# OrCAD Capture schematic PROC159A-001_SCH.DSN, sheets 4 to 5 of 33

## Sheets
4 08. POWER INPUT: size C; title: USB-C POWER
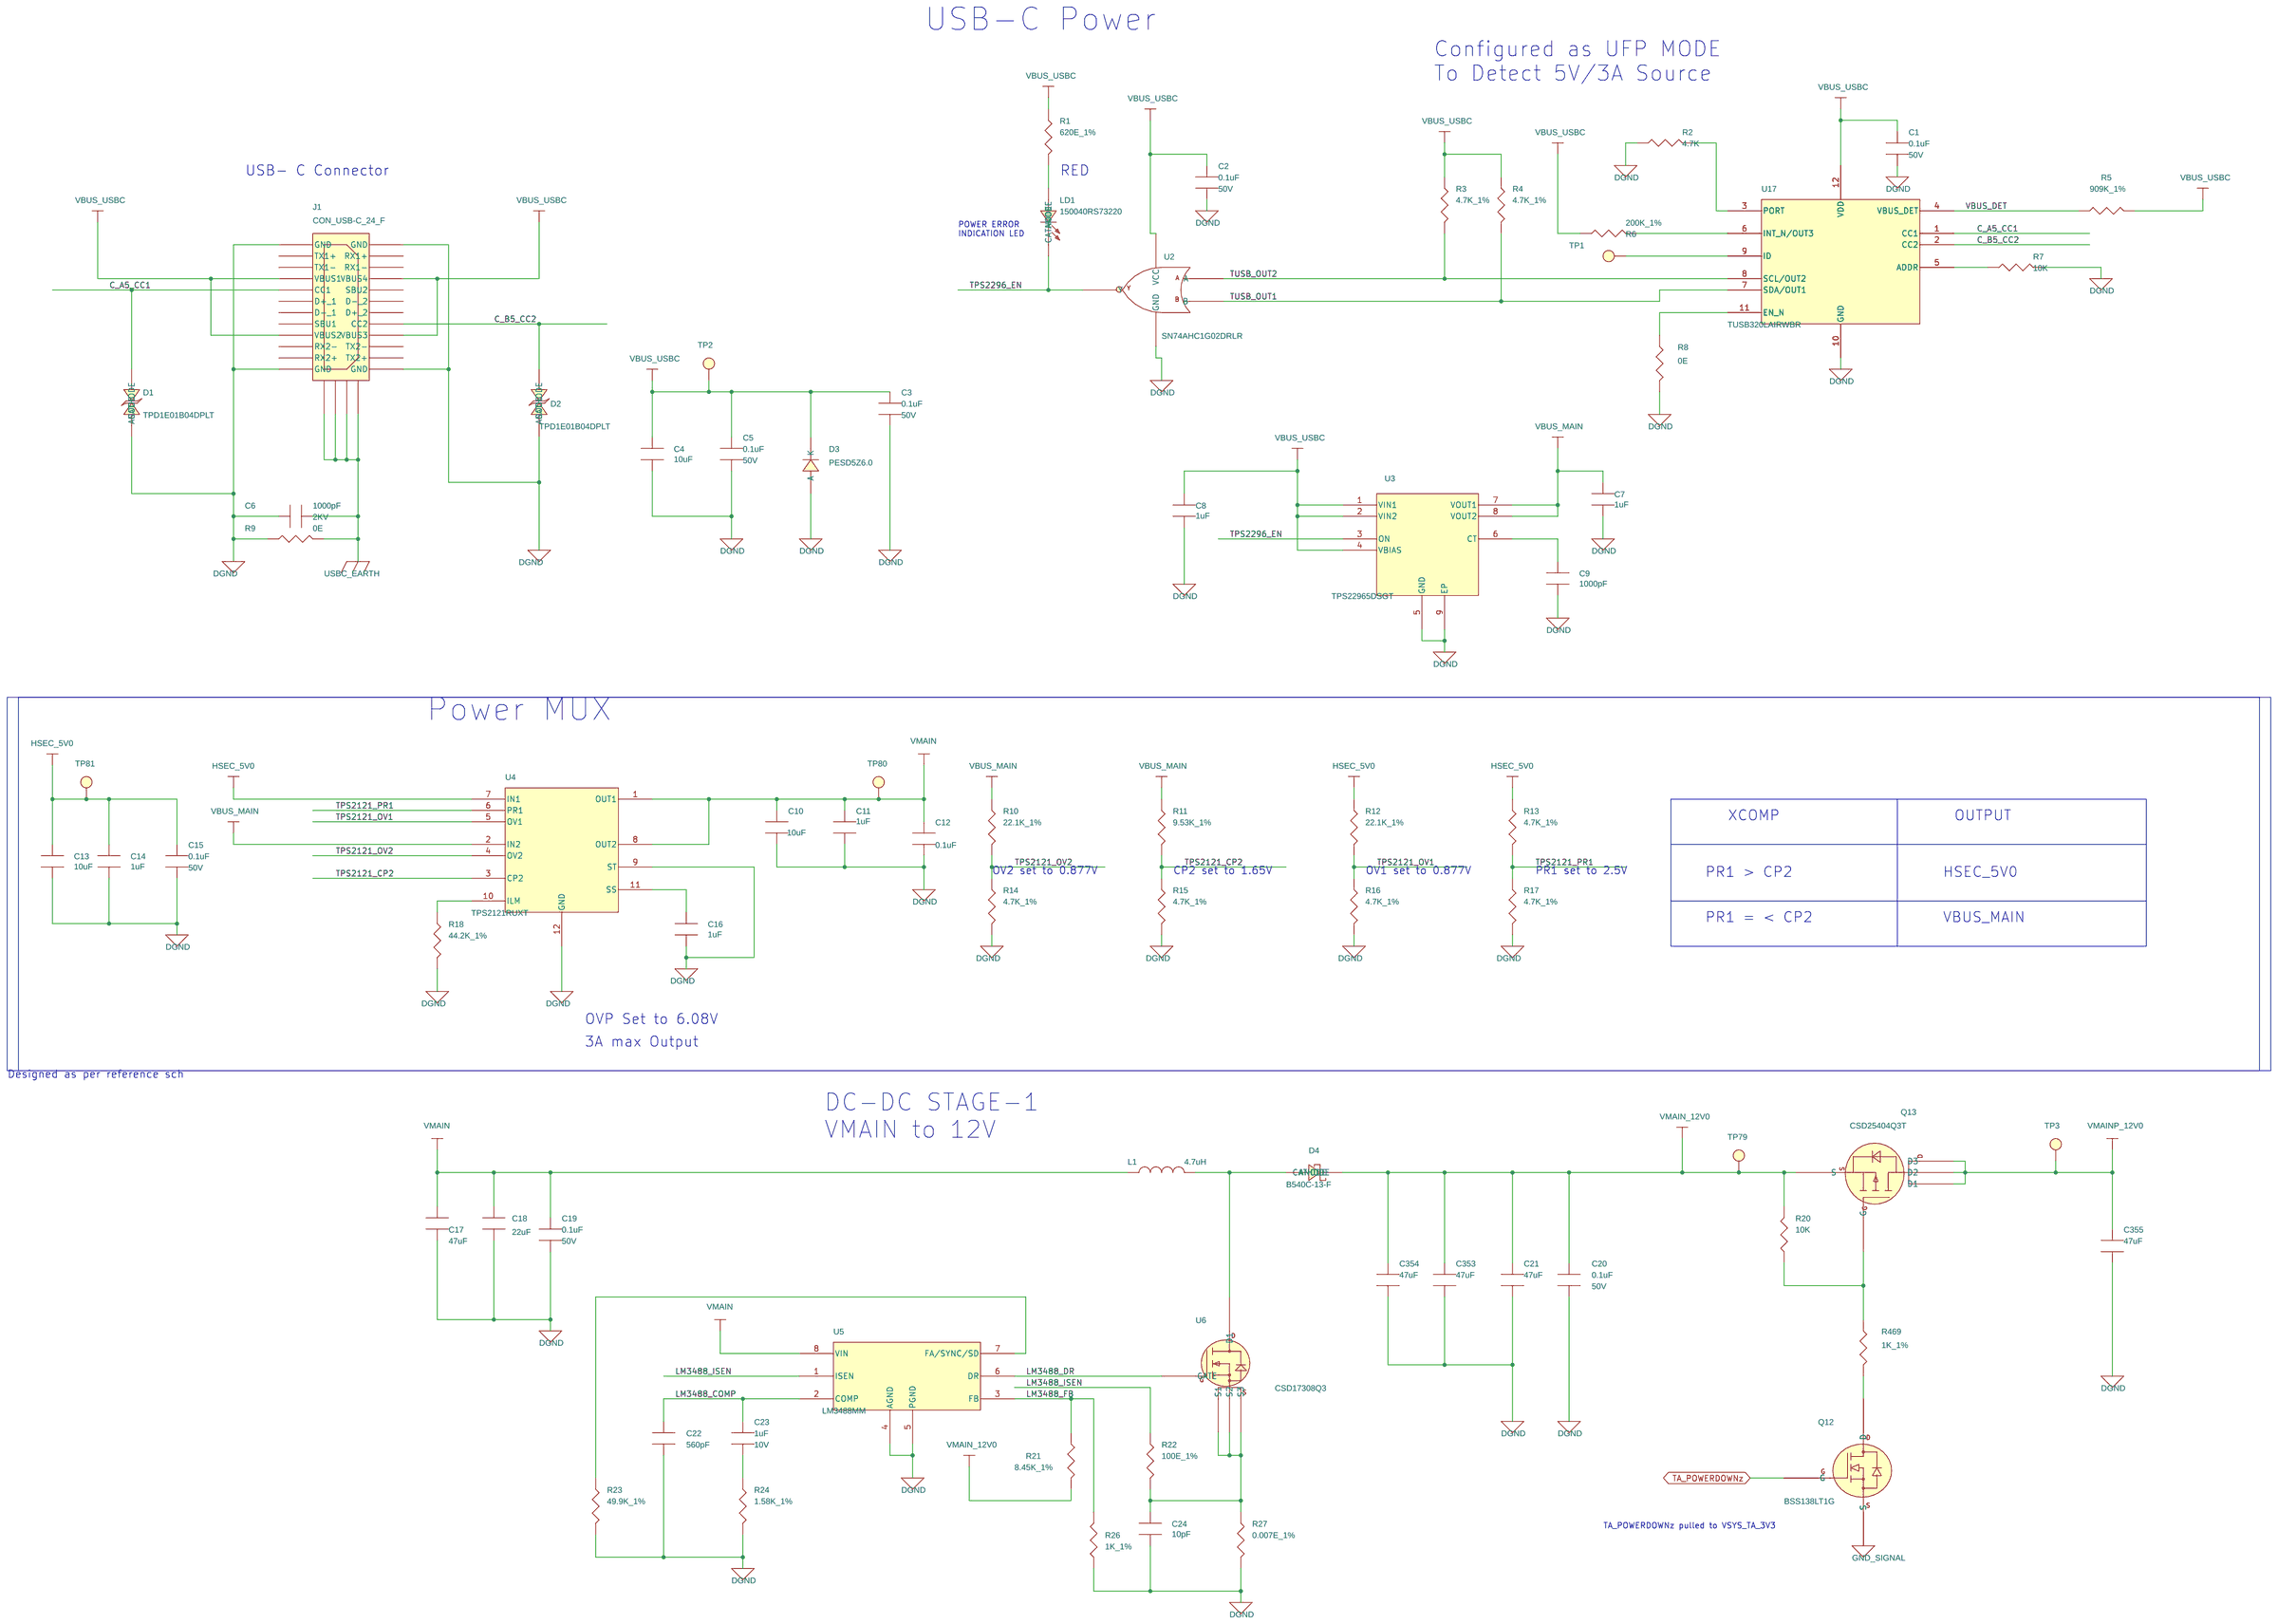
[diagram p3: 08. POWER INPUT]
5 04. POWER SEQUENCE: title: POWER SEQUENCE

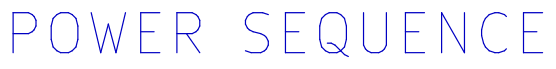
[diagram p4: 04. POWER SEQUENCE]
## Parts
C1  0.1uF  [CAP0402_0-75]
C2  0.1uF  [CAP0402_0-75]
C3  0.1uF  [CAP0402_0-75]
C4  10uF  [CAP1206_2]
C5  0.1uF  [CAP0402_0-75]
C6  1000pF  [CAP1206_1-75]
C7  1uF  [CAP0402_0-75]
C8  1uF  [CAP0402_0-75]
C9  1000pF  [CAP0402_0-75]
C10  10uF  [CAP1206_2]
C11  1uF  [CAP0402_0-75]
C12  0.1uF  [CAP0402_0-75]
C13  10uF  [CAP1206_2]
C14  1uF  [CAP0402_0-75]
C15  0.1uF  [CAP0402_0-75]
C16  1uF  [CAP0402_0-75]
C17  47uF  [CAP1206_2]
C18  22uF  [CAP0805_1-5]
C19  0.1uF  [CAP0402_0-75]
C20  0.1uF  [CAP0402_0-75]
C21  47uF  [CAP1206_2]
C22  560pF  [CAP0402_0-75]
C23  1uF  [CAP0402_0-75]
C24  10pF  [CAP0402_0-75]
C353  47uF  [CAP1206_2]
C354  47uF  [CAP1206_2]
C355  47uF  [CAP1206_2]
D1  TPD1E01B04DPLT  [DIO_DFN0201_0-4]
D2  TPD1E01B04DPLT  [DIO_DFN0201_0-4]
D3  PESD5Z6.0  [DIO_SOD523F_0-7]
D4  B540C-13-F  [DIO_SMC]
J1  CON_USB-C_24_F  [CON_USBC24_2012670_S_R_S_3-9]
L1  4.7uH  [IND_IHLP2020CZ-01_210X210_SMD_3]
LD1  150040RS73220  [LED_150040GS73220_40X20_SMD_0-4]
Q12  BSS138LT1G  [SOT23-123_1-2]
Q13  CSD25404Q3T  [VSON8_CSD173_130X130_1-1]
R1  620E_1%  [RES0402_0-5]
R2  4.7K  [RES0402_0-5]
R3  4.7K_1%  [RES0402_0-5]
R4  4.7K_1%  [RES0402_0-5]
R5  909K_1%  [RES0201_0-5]
R6  200K_1%  [RES0402_0-5]
R7  10K  [RES0402_0-5]
R8  0E  [RES0402_0-5]
R9  0E  [RES0805_0-75]
R10  22.1K_1%  [RES0402_0-5]
R11  9.53K_1%  [RES0402_0-5]
R12  22.1K_1%  [RES0402_0-5]
R13  4.7K_1%  [RES0402_0-5]
R14  4.7K_1%  [RES0402_0-5]
R15  4.7K_1%  [RES0402_0-5]
R16  4.7K_1%  [RES0402_0-5]
R17  4.7K_1%  [RES0402_0-5]
R18  44.2K_1%  [RES0402_0-5]
R20  10K  [RES0201_0-5]
R21  8.45K_1%  [RES0402_0-5]
R22  100E_1%  [RES0402_0-5]
R23  49.9K_1%  [RES0402_0-5]
R24  1.58K_1%  [RES0402_0-5]
R26  1K_1%  [RES0402_0-5]
R27  0.007E_1%  [RES1206_W_0-75]
R469  1K_1%  [RES0402_0-5]
TP1  TP40_SMD  [TP40_SMD]
TP2  TP40_SMD  [TP40_SMD]
TP3  TP40_SMD  [TP40_SMD]
TP79  TP40_SMD  [TP40_SMD]
TP80  TP40_SMD  [TP40_SMD]
TP81  TP40_SMD  [TP40_SMD]
U2  SN74AHC1G02DRLR  [SOT553-5_0-6]
U3  TPS22965DSGT  [WSON8_19-68_80X80_0-8]
U4  TPS2121RUXT  [VQFNHR12_TPS2121_80X100_1]
U5  LM3488MM  [VSSOP8_25-59_120X120_1-1]
U6  CSD17308Q3  [VSON8_CSD173_130X130]
U17  TUSB320LAIRWBR  [X2QFN12_TUSB322I_60X60_0-4]

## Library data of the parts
C1-C3 C5 C15 C19 C20 = CAP: CAP CERAMIC 0.1uF 50V 10% X7R 0402; Automotive Alternate_mfr_name: TDK; Automotive Alternate_mfr_part_number: CGA2B3X7R1H104K050BB; Chkd/date: MANIRAJA/261020; Crtd /date: ALVY/211020; Custom_Duty: 15%; Customs_HS_Code: 85322990; Direct Alternate_mfr_name: TDK; Direct Alternate_mfr_part_number: C1005X7R1H104K050BE; Distributor_name: DIGIKEY; Distributor_part_number: 490-10700-1-ND; Footprint Path: Y:\MIS_DATABASE\Library\ALTIUM_TOOL\PCB_FOOTPRINTS\Altium_Footprint_Lib.PcbLib; Height: 0.55MM; Library Path: Y:\MIS_DATABASE\Library\ALTIUM_TOOL\SCHEMATICS_PARTS\MS_DISCRETE_Library.schlib; Mfr_name: MURATA; Mfr_part_number: GRM155R71H104KE14D; Mistral Part No: 120011100014-R; Package: 0402; Part_type: CAPACITORS\CERAMIC; Project: J7_CP; RoHS: RoHS; Temperature: -55°C+125°C; Tolerance: 10%; Voltage: 50V; Wattage: NA; Weight: 3.1mg; Datasheet: Y:\MIS_DATABASE\DATASHEETS\CAPACITORS\GRM155R71H104KE14.PDF
C4 C10 C13 = CAP: CAP CERAMIC 10uF 50V 10% X7T 1206; Chkd/date: ALVY/010721; Crtd /date: MANIRAJA/010721; Custom_Duty: 15%; Customs_HS_Code: 85322990; Distributor_name: DIGIKEY; Distributor_part_number: 490-GRM31CD71H106KE11LCT-ND; Footprint Path: Y:\MIS_DATABASE\Library\ALTIUM_TOOL\PCB_FOOTPRINTS\Altium_Footprint_Lib.PcbLib; Height: 1.90MM; Library Path: Y:\MIS_DATABASE\Library\ALTIUM_TOOL\SCHEMATICS_PARTS\MS_DISCRETE_Library.schlib; Mfr_name: MURATA; Mfr_part_number: GRM31CD71H106KE11L; Mistral Part No: 120021070004-R; Package: 1206; Part_type: CAPACITORS\CERAMIC; Project: TI_AM263X_CC; RoHS: RoHS; Temperature: -55°C+125°C; Tolerance: 10%; Voltage: 50V; Wattage: NA; Weight: 27mg; Datasheet: Y:\MIS_DATABASE\DATASHEETS\CAPACITORS\GRM31CD71H106KE11.PDF
C6 = CAP: CAP CERAMIC 1000pF 2KV 10% X7R 1206; Automotive Alternate_mfr_name: KEMET; Automotive Alternate_mfr_part_number: C1206X102KGRACAUTO; Chkd/date: SHREESHAIL/291106; Crtd /date: MAZHAR/281106; Custom_Duty: 15%; Customs_HS_Code: 85322990; Direct Alternate_mfr_name: KEMET; Direct Alternate_mfr_part_number: C1206C102KGRACTU; Distributor_name: DIGIKEY; Distributor_part_number: 478-2956-1-ND; Footprint Path: Y:\MIS_DATABASE\Library\ALTIUM_TOOL\PCB_FOOTPRINTS\Altium_Footprint_Lib.PcbLib; Height: 1.52MM; Library Path: Y:\MIS_DATABASE\Library\ALTIUM_TOOL\SCHEMATICS_PARTS\MS_DISCRETE_Library.schlib; Mfr_name: AVX CORPORATION; Mfr_part_number: 1206GC102KAT1A; Mistral Part No: 120015080006-R; Package: 1206; Part_type: CAPACITORS\CERAMIC; Project: ADR1B; RoHS: RoHS; Temperature: -55°C+125°C; Tolerance: 10%; Voltage: 2KV; Wattage: NA; Weight: 16.2mg; Datasheet: Y:\MIS_DATABASE\DATASHEETS\CAPACITORS\AVX_HV-MLC.PDF
C7 C8 C11 C14 C16 = CAP: CAP CERAMIC 1uF 25V 10% X6S 0402; Chkd/date: MANIRAJA/140518; Crtd /date: ALVY/140518; Custom_Duty: 15%; Customs_HS_Code: 85322990; Distributor_name: DIGIKEY; Distributor_part_number: 490-10014-1-ND; Footprint Path: Y:\MIS_DATABASE\Library\ALTIUM_TOOL\PCB_FOOTPRINTS\Altium_Footprint_Lib.PcbLib; Height: 0.60MM; Library Path: Y:\MIS_DATABASE\Library\ALTIUM_TOOL\SCHEMATICS_PARTS\MS_DISCRETE_Library.schlib; Mfr_name: MURATA; Mfr_part_number: GRM155C81E105KE11D; Mistral Part No: 120018050004-R; Package: 0402; Part_type: CAPACITORS\CERAMIC; Project: TI_SVB_MAXWELL_DUT; RoHS: RoHS; Temperature: -55°C+105°C; Tolerance: 10%; Voltage: 25V; Wattage: NA; Weight: 6mg; Datasheet: Y:\MIS_DATABASE\DATASHEETS\CAPACITORS\GRM155C81E105KE11X.PDF
C9 = CAP: CAP CERAMIC 1000pF 50V 5% C0G(NP0) 0402; Chkd/date: VASANTHA/281216; Crtd /date: MAZHAR/290806; Custom_Duty: 15%; Customs_HS_Code: 85322990; Distributor_name: DIGIKEY; Distributor_part_number: 490-3244-1-ND; Footprint Path: Y:\MIS_DATABASE\Library\ALTIUM_TOOL\PCB_FOOTPRINTS\Altium_Footprint_Lib.PcbLib; Height: 0.55MM; Library Path: Y:\MIS_DATABASE\Library\ALTIUM_TOOL\SCHEMATICS_PARTS\MS_DISCRETE_Library.schlib; Mfr_name: MURATA; Mfr_part_number: GRM1555C1H102JA01D; Mistral Part No: 120016110009-R; Package: 0402; Part_type: CAPACITORS\CERAMIC; Project: SVDO_RMB_MMA; RoHS: RoHS; Temperature: -55°C+125°C; Tolerance: 5%; Voltage: 50V; Wattage: NA; Weight: 6mg; Datasheet: Y:\MIS_DATABASE\DATASHEETS\CAPACITORS\MURATA-GXX-SER_NOV17.PDF
C12 = CAP: CAP CERAMIC 0.1uF 50V 10% X7R 0402; Alt_Mfr_name: YAGEO AMERICA; Alt_Mfr_part_number: CC0402KRX5R8BB104; Chkd/date: MANIRAJA/261020; Crtd /date: ALVY/211020; Custom_Duty: 15%; Customs_HS_Code: 85322990; Distributor_name: DIGIKEY; Distributor_part_number: 490-10700-1-ND; Footprint Path: Y:\MIS_DATABASE\Library\ALTIUM_TOOL\PCB_FOOTPRINTS\Altium_Footprint_Lib.PcbLib; Height: 0.55MM; Library Path: Y:\MIS_DATABASE\Library\ALTIUM_TOOL\SCHEMATICS_PARTS\MS_DISCRETE_Library.schlib; Mfr_name: MURATA; Mfr_part_number: GRM155R71H104KE14D; Mistral Part No: 120011100014-R; Package: 0402; Part_type: CAPACITORS\CERAMIC; Project: J7_CP; RoHS: RoHS; Temperature: -55°C+125°C; Tolerance: 10%; Voltage: 50V; Wattage: NA; Weight: 3.1mg; Datasheet: Y:\MIS_DATABASE\DATASHEETS\CAPACITORS\GRM155R71H104KE14.PDF
C17 = CAP: CAP CERAMIC 47uF 10V 20% X5R 1206; Chkd/date: USMAN/121213; Crtd /date: USMAN/121213; Custom_Duty: 15%; Customs_HS_Code: 85322990; Distributor_name: DIGIKEY; Distributor_part_number: 490-5528-1-ND; Footprint Path: Y:\MIS_DATABASE\Library\ALTIUM_TOOL\PCB_FOOTPRINTS\Altium_Footprint_Lib.PcbLib; Height: 1.80MM; Library Path: Y:\MIS_DATABASE\Library\ALTIUM_TOOL\SCHEMATICS_PARTS\MS_DISCRETE_Library.schlib; Mfr_name: MURATA; Mfr_part_number: GRM31CR61A476ME15L; Mistral Part No: 120013120015-R; Package: 1206; Part_type: CAPACITORS\CERAMIC; Project: DMP; RoHS: RoHS; Temperature: -55°C+85°C; Tolerance: 20%; Voltage: 10V; Wattage: NA; Weight: 40mg; Datasheet: Y:\MIS_DATABASE\DATASHEETS\CAPACITORS\MURATA-GXX-SER_NOV17.PDF
C18 = CAP: CAP CERAMIC 22uF 25V 20% X5R 0805; Chkd/date: MANIRAJA/110718; Crtd /date: ALVY/110718; Custom_Duty: 15%; Customs_HS_Code: 85322990; Distributor_name: DIGIKEY; Distributor_part_number: 490-14661-1-ND; Footprint Path: Y:\MIS_DATABASE\Library\ALTIUM_TOOL\PCB_FOOTPRINTS\Altium_Footprint_Lib.PcbLib; Height: 1.45MM; Library Path: Y:\MIS_DATABASE\Library\ALTIUM_TOOL\SCHEMATICS_PARTS\MS_DISCRETE_Library.schlib; Mfr_name: MURATA; Mfr_part_number: GRM21BR61E226ME44K; Mistral Part No: 120013120018-R; Package: 0805; Part_type: CAPACITORS\CERAMIC; Project: TI_J7SVB_PCIE_ADD-ON-CARD; RoHS: RoHS; Temperature: -55°C+85°C; Tolerance: 20%; Voltage: 25V; Wattage: NA; Weight: 9.5mg; Datasheet: Y:\MIS_DATABASE\DATASHEETS\CAPACITORS\GRM21BR61E226ME44K.PDF
C21 C353-C355 = CAP: CAP CERAMIC 47uF 25V 20% X5R 1206; Chkd/date: VASANTHA/261214; Crtd /date: USMAN/160513; Custom_Duty: 15%; Customs_HS_Code: 85322990; Distributor_name: DIGIKEY; Distributor_part_number: 445-8047-1-ND; Footprint Path: Y:\MIS_DATABASE\Library\ALTIUM_TOOL\PCB_FOOTPRINTS\Altium_Footprint_Lib.PcbLib; Height: 1.80MM; Library Path: Y:\MIS_DATABASE\Library\ALTIUM_TOOL\SCHEMATICS_PARTS\MS_DISCRETE_Library.schlib; Mfr_name: TDK CORPORATION; Mfr_part_number: C3216X5R1E476M160AC; Mistral Part No: 120013050002-R; Package: 1206; Part_type: CAPACITORS\CERAMIC; Project: ERP; RoHS: RoHS; Temperature: -55°C+85°C; Tolerance: 20%; Voltage: 25V; Wattage: NA; Weight: 16.2mg; Datasheet: Y:\MIS_DATABASE\DATASHEETS\CAPACITORS\TDK_C-SER-JUL17.PDF
C22 = CAP: CAP CERAMIC 560pF 50V 5% C0G(NP0) 0402; Chkd/date: ALVY/260821; Crtd /date: MANIRAJA/260821; Custom_Duty: 15%; Customs_HS_Code: 85322990; Distributor_name: DIGIKEY; Distributor_part_number: 490-6248-1-ND; Footprint Path: Y:\MIS_DATABASE\Library\ALTIUM_TOOL\PCB_FOOTPRINTS\Altium_Footprint_Lib.PcbLib; Height: 0.55MM; Library Path: Y:\MIS_DATABASE\Library\ALTIUM_TOOL\SCHEMATICS_PARTS\MS_DISCRETE_Library.schlib; Mfr_name: MURATA; Mfr_part_number: GRM1555C1H561JA01J; Mistral Part No: 120019120008-R; Package: 0402; Part_type: CAPACITORS\CERAMIC; Project: TI_AM62x SKEVM_BRD; RoHS: RoHS; Temperature: -55°C+125°C; Tolerance: 5%; Voltage: 50V; Wattage: NA; Weight: 6mg; Datasheet: Y:\MIS_DATABASE\DATASHEETS\CAPACITORS\GRM1555C1H561JA01.PDF
C23 = CAP: CAP CERAMIC 1uF 10V 10% X5R 0402; Automotive Alternate_mfr_name: TDK; Automotive Alternate_mfr_part_number: CGA2B3X7R1H104K050BB; Chkd/date: MANIRAJA/190218; Crtd /date: ALVY/160218; Custom_Duty: 15%; Customs_HS_Code: 85322990; Direct Alternate_mfr_name: TDK; Direct Alternate_mfr_part_number: C1005X7R1H104K050BE; Distributor_name: DIGIKEY; Distributor_part_number: 399-7765-1-ND; Footprint Path: Y:\MIS_DATABASE\Library\ALTIUM_TOOL\PCB_FOOTPRINTS\Altium_Footprint_Lib.PcbLib; Height: 0.55MM; Library Path: Y:\MIS_DATABASE\Library\ALTIUM_TOOL\SCHEMATICS_PARTS\MS_DISCRETE_Library.schlib; Mfr_name: KEMET; Mfr_part_number: C0402C105K8PACTU; Mistral Part No: 120014050010-R; Package: 0402; Part_type: CAPACITORS\CERAMIC; Project: GRACO SMART MODULE; RoHS: RoHS; Temperature: -55°C+85°C; Tolerance: 10%; Voltage: 10V; Wattage: NA; Weight: 0.65mg; Datasheet: Y:\MIS_DATABASE\DATASHEETS\CAPACITORS\KEMET-C-X5R.PDF
C24 = CAP: CAP CERAMIC 10pF 50V 10% X7R 0402; Chkd/date: PRAVEEN/221222; Crtd /date: PRAVEEN/221222; Custom_Duty: 15%; Customs_HS_Code: 85322990; Distributor_name: DIGIKEY; Distributor_part_number: 399-C0402C100K5RAC7867CT-ND; Footprint Path: Y:\MIS_DATABASE\Library\ALTIUM_TOOL\PCB_FOOTPRINTS\Altium_Footprint_Lib.PcbLib; Height: 0.55MM; Library Path: Y:\MIS_DATABASE\Library\ALTIUM_TOOL\SCHEMATICS_PARTS\MS_DISCRETE_Library.schlib; Mfr_name: KEMET; Mfr_part_number: C0402C100K5RAC7867; Mistral Part No: 120022120019-R; Package: 0402; Part_type: CAPACITORS\CERAMIC; Project: DFS; RoHS: RoHS; Temperature: -55°C+125°C; Tolerance: 10%; Voltage: 50V; Wattage: NA; Weight: 0.65mg; Datasheet: Y:\MIS_DATABASE\DATASHEETS\CAPACITORS\C0402C100K5RAC7867.PDF
D1 D2 = DIODE_TVS_DUAL: DIODE 1CH ESD PROTECTION FOR USB TYPE-C AND THUNDERBOLT3 X2SON2; Chkd/date: MANIRAJA/230920; Crtd /date: ALVY/230920; Custom_Duty: 15%; Customs_HS_Code: 85412900; Distributor_name: DIGIKEY; Distributor_part_number: 296-44484-1-ND; Footprint Path: Y:\MIS_DATABASE\Library\ALTIUM_TOOL\PCB_FOOTPRINTS\Altium_Footprint_Lib.PcbLib; Height: 0.32MM; Library Path: Y:\MIS_DATABASE\Library\ALTIUM_TOOL\SCHEMATICS_PARTS\MS_DISCRETE_Library.schlib; Mfr_name: TEXAS INSTRUMENTS; Mistral Part No: 130020090037-R; Package: X2SON2; Part_type: DIODE\TVS; Project: AM64X_SKEVM; RoHS: RoHS; Temperature: -40°C+125°C; Tolerance: NA; Voltage: NA; Wattage: NA; Weight: 0.2mg; Datasheet: Y:\MIS_DATABASE\DATASHEETS\DISCRETES\DIODES\TPD1E01B04.PDF
D3 = DIODE: DIODE 6V LOW CAPACITANCE UNIDIRECTIONAL ESD PROTECTION SOD523; Crtd /date: ALVY/230621; Custom_Duty: 15%; Customs_HS_Code: 85412900; Distributor_name: DIGIKEY; Distributor_part_number: 1727-5815-1-ND; Footprint Path: Y:\MIS_DATABASE\Library\ALTIUM_TOOL\PCB_FOOTPRINTS\Altium_Footprint_Lib.PcbLib; Height: 0.65MM; Library Path: Y:\MIS_DATABASE\Library\ALTIUM_TOOL\SCHEMATICS_PARTS\MS_DISCRETE_Library.schlib; Mfr_name: NEXPERIA; Mfr_part_number: PESD5Z6.0,115; Mistral Part No: 130021060065-R; Package: SOD523; Project: AM263x_CC; RoHS: RoHS; Temperature: -65°C+150°C; Tolerance: NA; Voltage: 6V; Wattage: NA; Weight: 1.49mg; Datasheet: Y:\MIS_DATABASE\DATASHEETS\DISCRETES\DIODES\PESD5ZX.PDF
D4 = DIODE_SCHOTTKY: DIODE SCHOTTKY 40V 5A SMC; Chkd/date: BAVISH/311210; Crtd /date: MAZHAR/201210; Custom_Duty: 15%; Customs_HS_Code: 85412900; Distributor_name: DIGIKEY; Distributor_part_number: B540C-FDICT-ND; Height: 2.5MM; Mfr_name: DIODES INC; Mistral Part No: 130010120033-R; Package: SMC; Part_type: DIODE\SCHOTTKY; Project: IEMS; RoHS: RoHS; Temperature: -55°C+125°C; Tolerance: NA; Voltage: 40V; Wattage: NA; Weight: 0.21g; Datasheet: Y:\MIS_DATABASE\DATASHEETS\DISCRETES\DIODES\B540C.PDF
J1 = CON_USB-C_24_1240183621: CON USB-C TYPE 24POS FEMALE RT SMD; Chkd/date: MANIRAJA/050618; Crtd /date: ALVY/040618; Custom_Duty: 24%; Customs_HS_Code: 85369090; Distributor_name: DIGIKEY; Distributor_part_number: WM17992CT-ND; Footprint Path: Y:\MIS_DATABASE\Library\ALTIUM_TOOL\PCB_FOOTPRINTS\Altium_Footprint_Lib.PcbLib; Height: 3.86MM; Library Path: Y:\MIS_DATABASE\Library\ALTIUM_TOOL\SCHEMATICS_PARTS\MS_CONNECTOR_Library.schlib; Mfr_name: MOLEX; Mfr_part_number: 2012670005; Mistral Part No: 150018060002-R; Package: SMD; Part_type: CONNECTOR\USB; Project: TI_J7SVB_USB_ADD-ON-CARD; RoHS: RoHS; Temperature: -40°C+105°C; Tolerance: NA; Voltage: NA; Wattage: NA; Weight: 0.686g; Datasheet: Y:\MIS_DATABASE\DATASHEETS\CONNECTORS\2012670X.PDF
L1 = INDUCTOR: IND POWER 4.7uH 3.5A 20% SMD; Chkd/date: MANIRAJA/050219; Crtd /date: BAVISH/131010; Custom_Duty: 24%; Customs_HS_Code: 85437099; Distributor_name: DIGIKEY; Distributor_part_number: 541-1270-1-ND; Footprint Path: Y:\MIS_DATABASE\Library\ALTIUM_TOOL\PCB_FOOTPRINTS\Altium_Footprint_Lib.PcbLib; Height: 3.00MM; Library Path: Y:\MIS_DATABASE\Library\ALTIUM_TOOL\SCHEMATICS_PARTS\MS_DISCRETE_Library.schlib; Mfr_name: VISHAY; Mfr_part_number: IHLP2020CZER4R7M01; Mistral Part No: 130011010024-R; Package: SMD; Project: ITS-PWR_CARD; RoHS: RoHS; Temperature: -55°C+125°C; Tolerance: 20%; Voltage: NA; Wattage: NA; Weight: 200mg; Datasheet: Y:\MIS_DATABASE\DATASHEETS\DISCRETES\INDUCTORS\IHLP-2020CZ-01-SER.PDF
LD1 = DIODE_LED: DIODE LED RED SMD; Chkd/date: MANIRAJA/100920; Crtd /date: ALVY/100920; Custom_Duty: 24%; Customs_HS_Code: 85439000; Distributor_name: DIGIKEY; Distributor_part_number: 732-13422-1-ND; Footprint Path: Y:\MIS_DATABASE\Library\ALTIUM_TOOL\PCB_FOOTPRINTS\Altium_Footprint_Lib.PcbLib; Height: 0.35MM; Library Path: Y:\MIS_DATABASE\Library\ALTIUM_TOOL\SCHEMATICS_PARTS\MS_OPTO_Library.schlib; Mfr_name: WURTH ELECTRONICS; Mistral Part No: 130020090020-R; Package: SMD; Part_type: OPTO\LED; Project: AM64X_SKEVM; RoHS: RoHS; Temperature: -40°C+85°C; Tolerance: NA; Voltage: NA; Wattage: NA; Weight: 29.3mg; Datasheet: Y:\MIS_DATABASE\DATASHEETS\DISCRETES\LEDS\150040RS73220.PDF
Q12 = MOSFET_BSS138W: IC MOSFET N-CHANNEL 50V 200mA SOT23-3; Chkd/date: MANIRAJA/250219; Crtd /date: JEBRAN/060416; Custom_Duty: 15%; Customs_HS_Code: 85423100; Distributor_name: DIGIKEY; Distributor_part_number: BSS138LT1GOSCT-ND; Footprint Path: Y:\MIS_DATABASE\Library\ALTIUM_TOOL\PCB_FOOTPRINTS\Altium_Footprint_Lib.PcbLib; Height: 1.11MM; Library Path: Y:\MIS_DATABASE\Library\ALTIUM_TOOL\SCHEMATICS_PARTS\MS_MOSFET_Library.schlib; Mfr_name: ON SEMICONDUCTOR; Mistral Part No: 142016040001-R; Package: SOT23-3; Part_type: ICS\POWER\MOSFET; Project: LRDE_ABCM; RoHS: RoHS; Temperature: -55°C+150°C; Tolerance: NA; Voltage: NA; Wattage: NA; Weight: 8mg; Datasheet: Y:\MIS_DATABASE\DATASHEETS\DISCRETES\TRANSISTORS_FETS\BSS138LT1G.PDF
Q13 = MOSFET_CSD25402Q3A: IC 20V P-CHANNEL NEXFET POWER MOSFET VSON8; Chkd/date: ALVY/250621; Crtd /date: MANIRAJA/250621; Custom_Duty: 15%; Customs_HS_Code: 85423100; Distributor_name: DIGIKEY; Distributor_part_number: 296-43210-1-ND; Footprint Path: Y:\MIS_DATABASE\Library\ALTIUM_TOOL\PCB_FOOTPRINTS\Altium_Footprint_Lib.PcbLib; Height: 1.10MM; Library Path: Y:\MIS_DATABASE\Library\ALTIUM_TOOL\SCHEMATICS_PARTS\MS_MOSFET_Library.schlib; Mfr_name: TEXAS INSTRUMENTS; Mistral Part No: 142021060036-R; Package: VSON8; Part_type: ICS\POWER\MOSFET; Project: VOLTA_CHARGER V5; RoHS: RoHS; Temperature: -55°C+150°C; Tolerance: NA; Voltage: NA; Wattage: NA; Weight: 44.5mg; Datasheet: Y:\MIS_DATABASE\DATASHEETS\ICS\POWER\CSD25404Q3.PDF
R1 = RESISTOR: RES 620E 1/10W 1% 0402; Chkd/date: USMAN/120313; Crtd /date: CHAITHANYA/270912; Custom_Duty: 15%; Customs_HS_Code: 85332119; Distributor_name: DIGIKEY; Distributor_part_number: P620LCT-ND; Footprint Path: Y:\MIS_DATABASE\Library\ALTIUM_TOOL\PCB_FOOTPRINTS\Altium_Footprint_Lib.PcbLib; Height: 0.40MM; Library Path: Y:\MIS_DATABASE\Library\ALTIUM_TOOL\SCHEMATICS_PARTS\MS_DISCRETE_Library.schlib; Mfr_name: PANASONIC-ECG; Mfr_part_number: ERJ-2RKF6200X; Mistral Part No: 110012090013-R; Package: 0402; Part_type: RESISTORS\FIXED; Project: ITS-CONTROLER_CARD; RoHS: RoHS; Temperature: -55°C+155°C; Tolerance: 1%; Voltage: NA; Wattage: 1/10W; Weight: 0.8mg; Datasheet: Y:\MIS_DATABASE\DATASHEETS\RESISTORS\PAN-ERJSER_NOV17.PDF
R2 = RESISTOR: RES 4.7K 1/16W 5% 0402; Chkd/date: VASANTHA/130516; Crtd /date: VASANTHA/130516; Custom_Duty: 15%; Customs_HS_Code: 85332119; Distributor_name: DIGIKEY; Distributor_part_number: 311-4.7KJRCT-ND; Footprint Path: Y:\MIS_DATABASE\Library\ALTIUM_TOOL\PCB_FOOTPRINTS\Altium_Footprint_Lib.PcbLib; Height: 0.40MM; Library Path: Y:\MIS_DATABASE\Library\ALTIUM_TOOL\SCHEMATICS_PARTS\MS_DISCRETE_Library.schlib; Mfr_name: YAGEO AMERICA; Mfr_part_number: RC0402JR-074K7L; Mistral Part No: 110011060001-R; Package: 0402; Part_type: RESISTORS\FIXED; Project: TMDXCSK368; RoHS: RoHS; Temperature: -55°C+155°C; Tolerance: 5%; Voltage: NA; Wattage: 1/16W; Weight: 0.65mg; Datasheet: Y:\MIS_DATABASE\DATASHEETS\RESISTORS\RCXXXXL-SER_MAR18.PDF
R3 R4 R13-R17 = RESISTOR: RES 4.7K 1/16W 1% 0402; Chkd/date: VASANTHA/061216; Crtd /date: USMAN/070109; Custom_Duty: 15%; Customs_HS_Code: 85332119; Distributor_name: DIGIKEY; Distributor_part_number: 541-4.70KLCT-ND; Footprint Path: Y:\MIS_DATABASE\Library\ALTIUM_TOOL\PCB_FOOTPRINTS\Altium_Footprint_Lib.PcbLib; Height: 0.40MM; Library Path: Y:\MIS_DATABASE\Library\ALTIUM_TOOL\SCHEMATICS_PARTS\MS_DISCRETE_Library.schlib; Mfr_name: VISHAY; Mfr_part_number: CRCW04024K70FKED; Mistral Part No: 110009030797-R; Package: 0402; Part_type: RESISTORS\FIXED; Project: OMAP_EVM; RoHS: RoHS; Temperature: -55°C+155°C; Tolerance: 1%; Voltage: NA; Wattage: 1/16W; Weight: 0.65mg; Datasheet: Y:\MIS_DATABASE\DATASHEETS\RESISTORS\CRCW0603.PDF
R5 = RESISTOR: RES 909K 1/20W 1% 0201; Chkd/date: TAMILARASU/270423; Crtd /date: TAMILARASU/270423; Custom_Duty: 0.15; Customs_HS_Code: 85332119; Distributor_name: DIGIKEY; Distributor_part_number: P123197CT-ND; Footprint Path: Y:\MIS_DATABASE\Library\ALTIUM_TOOL\PCB_FOOTPRINTS\Altium_Footprint_Lib.PcbLib; Height: 0.26MM; Library Path: Y:\MIS_DATABASE\Library\ALTIUM_TOOL\SCHEMATICS_PARTS\MS_DISCRETE_Library.schlib; Mfr_name: PANASONIC-ECG; Mfr_part_number: ERJ-1GNF9093C; Mistral Part No: 110023040018-R; Package: 0201; Part_type: RESISTORS\FIXED; Project: AM263P_CC; RoHS: RoHS; Temperature: -55°C+125°C; Tolerance: 1%; Voltage: NA; Wattage: 1/20W; Weight: 0.15mg; Datasheet: Y:\MIS_DATABASE\DATASHEETS\RESISTORS\PAN-ERJSER_NOV17.PDF
R6 = RESISTOR: RES 200K 1/10W 1% 0402; Chkd/date: SHREESHAIL/121205; Crtd /date: MAZHAR/010805; Custom_Duty: 15%; Customs_HS_Code: 85332119; Distributor_name: DIGIKEY; Distributor_part_number: P200KLCT-ND; Footprint Path: Y:\MIS_DATABASE\Library\ALTIUM_TOOL\PCB_FOOTPRINTS\Altium_Footprint_Lib.PcbLib; Height: 0.40MM; Library Path: Y:\MIS_DATABASE\Library\ALTIUM_TOOL\SCHEMATICS_PARTS\MS_DISCRETE_Library.schlib; Mfr_name: PANASONIC-ECG; Mfr_part_number: ERJ-2RKF2003X; Mistral Part No: 110009030474-R; Package: 0402; Part_type: RESISTORS\FIXED; Project: PMP-VIOMEDIA; RoHS: RoHS; Temperature: -55°C+155°C; Tolerance: 1%; Voltage: NA; Wattage: 1/10W; Weight: 0.8mg; Datasheet: Y:\MIS_DATABASE\DATASHEETS\RESISTORS\PAN-ERJSER_NOV17.PDF
R7 = RESISTOR: RES 10K 1/16W 5% 0402; Chkd/date: VASANTHA/061216; Crtd /date: MAZHAR/230805; Custom_Duty: 15%; Customs_HS_Code: 85332119; Distributor_name: DIGIKEY; Distributor_part_number: 311-10KJRCT-ND; Footprint Path: Y:\MIS_DATABASE\Library\ALTIUM_TOOL\PCB_FOOTPRINTS\Altium_Footprint_Lib.PcbLib; Height: 0.40MM; Library Path: Y:\MIS_DATABASE\Library\ALTIUM_TOOL\SCHEMATICS_PARTS\MS_DISCRETE_Library.schlib; Mfr_name: YAGEO AMERICA; Mfr_part_number: RC0402JR-0710KL; Mistral Part No: 110011060021-R; Package: 0402; Part_type: RESISTORS\FIXED; Project: HSE; RoHS: RoHS; Temperature: -55°C+155°C; Tolerance: 5%; Voltage: NA; Wattage: 1/16W; Weight: 0.65mg; Datasheet: Y:\MIS_DATABASE\DATASHEETS\RESISTORS\RCXXXXL-SER_MAR18.PDF
R8 = RESISTOR: RES 0E 1/10W JUMPER 0402; Chkd/date: VASANTHA/061216; Crtd /date: NAVEED/201014; Custom_Duty: 15%; Customs_HS_Code: 85332119; Distributor_name: DIGIKEY; Distributor_part_number: P0.0JCT-ND; Footprint Path: Y:\MIS_DATABASE\Library\ALTIUM_TOOL\PCB_FOOTPRINTS\Altium_Footprint_Lib.PcbLib; Height: 0.40MM; IBISSP_MODLES: VALUE REPEATING 2 TIME; Library Path: Y:\MIS_DATABASE\Library\ALTIUM_TOOL\SCHEMATICS_PARTS\MS_DISCRETE_Library.schlib; Mfr_name: PANASONIC-ECG; Mfr_part_number: ERJ-2GE0R00X; Mistral Part No: 110018030052-R; Package: 0402; Part_type: RESISTORS\FIXED; Project: AEGIS POM; RoHS: RoHS; Temperature: -55°C+155°C; Tolerance: NA; Voltage: NA; Wattage: 1/10W; Weight: 0.8mg; Datasheet: Y:\MIS_DATABASE\DATASHEETS\RESISTORS\PAN-ERJSER_NOV17.PDF
R9 = RESISTOR: RES 0E 1/8W 5% 0805; Chkd/date: VASANTHA/130416; Crtd /date: JEBRAN/020316; Custom_Duty: 15%; Customs_HS_Code: 85332119; Distributor_name: DIGIKEY; Distributor_part_number: 311-0.0ARCT-ND; Footprint Path: Y:\MIS_DATABASE\Library\ALTIUM_TOOL\PCB_FOOTPRINTS\Altium_Footprint_Lib.PcbLib; Height: 0.60MM; Library Path: Y:\MIS_DATABASE\Library\ALTIUM_TOOL\SCHEMATICS_PARTS\MS_DISCRETE_Library.schlib; Mfr_name: YAGEO AMERICA; Mfr_part_number: RC0805JR-070RL; Mistral Part No: 110009030074-R; Package: 0805; Part_type: RESISTORS\FIXED; Project: ZK_BIOMETRIC; RoHS: RoHS; Temperature: -55°C+155°C; Tolerance: 5%; Voltage: NA; Wattage: 1/8W; Weight: 5.5mg; Datasheet: Y:\MIS_DATABASE\DATASHEETS\RESISTORS\RCXXXXL-SER_MAR18.PDF
R10 R12 = RESISTOR: RES 22.1K 1/16W 1% 0402; Chkd/date: MAZHAR/101110; Crtd /date: BAVISH/091110; Custom_Duty: 15%; Customs_HS_Code: 85332119; Distributor_name: DIGIKEY; Distributor_part_number: 541-22.1KLCT-ND; Footprint Path: Y:\MIS_DATABASE\Library\ALTIUM_TOOL\PCB_FOOTPRINTS\Altium_Footprint_Lib.PcbLib; Height: 0.40MM; Library Path: Y:\MIS_DATABASE\Library\ALTIUM_TOOL\SCHEMATICS_PARTS\MS_DISCRETE_Library.schlib; Mfr_name: VISHAY; Mfr_part_number: CRCW040222K1FKED; Mistral Part No: 110010110004-R; Package: 0402; Part_type: RESISTORS\FIXED; Project: CPCI3GADC_CARD; RoHS: RoHS; Temperature: -55°C+155°C; Tolerance: 1%; Voltage: NA; Wattage: 1/16W; Weight: 0.65mg; Datasheet: Y:\MIS_DATABASE\DATASHEETS\RESISTORS\CRCW0603.PDF
R11 = RESISTOR: RES 9.53K 1/16W 1% 0402; Chkd/date: MANIRAJA/070521; Crtd /date: ALVY/070521; Custom_Duty: 15%; Customs_HS_Code: 85332119; Distributor_name: DIGIKEY; Distributor_part_number: 311-9.53KLRCT-ND; Footprint Path: Y:\MIS_DATABASE\Library\ALTIUM_TOOL\PCB_FOOTPRINTS\Altium_Footprint_Lib.PcbLib; Height: 0.40MM; Library Path: Y:\MIS_DATABASE\Library\ALTIUM_TOOL\SCHEMATICS_PARTS\MS_DISCRETE_Library.schlib; Mfr_name: YAGEO AMERICA; Mfr_part_number: RC0402FR-079K53L; Mistral Part No: 110021050001-R; Package: 0402; Part_type: RESISTORS\FIXED; Project: TI_AM263X_SVB_DUT; RoHS: RoHS; Temperature: -55°C+155°C; Tolerance: 1%; Voltage: NA; Wattage: 1/16W; Weight: 0.65mg; Datasheet: Y:\MIS_DATABASE\DATASHEETS\RESISTORS\RCXXXXL-SER_MAR18.PDF
R18 = RESISTOR: RES 44.2K 1/10W 1% 0402; Chkd/date: MAZHAR/041208; Crtd /date: USMAN/181108; Custom_Duty: 15%; Customs_HS_Code: 85332119; Distributor_name: DIGIKEY; Distributor_part_number: P44.2KLCT-ND; Footprint Path: Y:\MIS_DATABASE\Library\ALTIUM_TOOL\PCB_FOOTPRINTS\Altium_Footprint_Lib.PcbLib; Height: 0.40MM; Library Path: Y:\MIS_DATABASE\Library\ALTIUM_TOOL\SCHEMATICS_PARTS\MS_DISCRETE_Library.schlib; Mfr_name: PANASONIC-ECG; Mfr_part_number: ERJ-2RKF4422X; Mistral Part No: 110009030845-R; Package: 0402; Part_type: RESISTORS\FIXED; Project: PICO PROJECTOR; RoHS: RoHS; Temperature: -55°C+155°C; Tolerance: 1%; Voltage: NA; Wattage: 1/10W; Weight: 0.8mg; Datasheet: Y:\MIS_DATABASE\DATASHEETS\RESISTORS\PAN-ERJSER_NOV17.PDF
R20 = RESISTOR: RES 10K 1/20W 5% 0201; Chkd/date: MANIRAJA/050517; Crtd /date: MANIRAJA/050517; Custom_Duty: 15%; Customs_HS_Code: 85332119; Distributor_name: DIGIKEY; Distributor_part_number: 311-10KNCT-ND; Footprint Path: Y:\MIS_DATABASE\Library\ALTIUM_TOOL\PCB_FOOTPRINTS\Altium_Footprint_Lib.PcbLib; Height: 0.26MM; Library Path: Y:\MIS_DATABASE\Library\ALTIUM_TOOL\SCHEMATICS_PARTS\MS_DISCRETE_Library.schlib; Mfr_name: YAGEO AMERICA; Mfr_part_number: RC0201JR-0710KL; Mistral Part No: 110010070051-R; Package: 0201; Part_type: RESISTORS\FIXED; Project: GOLDEN-I LITE; RoHS: RoHS; Temperature: -55°C+125°C; Tolerance: 5%; Voltage: NA; Wattage: 1/20W; Weight: 0.17mg; Datasheet: Y:\MIS_DATABASE\DATASHEETS\RESISTORS\RCXXXXL-SER_MAR18.PDF
R21 = RESISTOR: RES 8.45K 1/10W 1% 0402; Chkd/date: MANIRAJA/260320; Crtd /date: ALVY/240320; Custom_Duty: 15%; Customs_HS_Code: 85332119; Distributor_name: DIGIKEY; Distributor_part_number: P8.45KLCT-ND; Footprint Path: Y:\MIS_DATABASE\Library\ALTIUM_TOOL\PCB_FOOTPRINTS\Altium_Footprint_Lib.PcbLib; Height: 0.40MM; Library Path: Y:\MIS_DATABASE\Library\ALTIUM_TOOL\SCHEMATICS_PARTS\MS_DISCRETE_Library.schlib; Mfr_name: PANASONIC-ECG; Mfr_part_number: ERJ-2RKF8451X; Mistral Part No: 110020030032-R; Package: 0402; Part_type: RESISTORS\FIXED; Project: DARE_ECU_MCB; RoHS: RoHS; Temperature: -55°C+155°C; Tolerance: 1%; Voltage: NA; Wattage: 1/10W; Weight: 0.8mg; Datasheet: Y:\MIS_DATABASE\DATASHEETS\RESISTORS\PAN-ERJSER_NOV17.PDF
R22 = RESISTOR: RES 100E 1/16W 1% 0402; Chkd/date: MANIRAJA/080519; Crtd /date: ALVY/080519; Custom_Duty: 15%; Customs_HS_Code: 85332119; Distributor_name: DIGIKEY; Distributor_part_number: 541-3962-1-ND; Footprint Path: Y:\MIS_DATABASE\Library\ALTIUM_TOOL\PCB_FOOTPRINTS\Altium_Footprint_Lib.PcbLib; Height: 0.35MM; Library Path: Y:\MIS_DATABASE\Library\ALTIUM_TOOL\SCHEMATICS_PARTS\MS_DISCRETE_Library.schlib; Mfr_name: VISHAY; Mfr_part_number: CRCW0402100RFKEDC; Mistral Part No: 110014070015-R; Package: 0402; Part_type: RESISTORS\FIXED; Project: BRUKER_SD820_COMMONDO; RoHS: RoHS; Temperature: -55°C+155°C; Tolerance: 1%; Voltage: NA; Wattage: 1/16W; Weight: 0.65mg; Datasheet: Y:\MIS_DATABASE\DATASHEETS\RESISTORS\CRCW_C-SER.PDF
R23 = RESISTOR: RES 49.9K 1/16W 1% 0402; Chkd/date: MANIRAJA/221021; Crtd /date: ALVY/211021; Custom_Duty: 15%; Customs_HS_Code: 85332119; Distributor_name: DIGIKEY; Distributor_part_number: 541-3994-1-ND; Footprint Path: Y:\MIS_DATABASE\Library\ALTIUM_TOOL\PCB_FOOTPRINTS\Altium_Footprint_Lib.PcbLib; Height: 0.35MM; Library Path: Y:\MIS_DATABASE\Library\ALTIUM_TOOL\SCHEMATICS_PARTS\MS_DISCRETE_Library.schlib; Mfr_name: VISHAY; Mfr_part_number: CRCW040249K9FKEDC; Mistral Part No: 110009030902-R; Package: 0402; Part_type: RESISTORS\FIXED; Project: ERU_EMCR_MCRH_WGM BRD; RoHS: RoHS; Temperature: -55°C+155°C; Tolerance: 1%; Voltage: NA; Wattage: 1/16W; Weight: 0.65mg; Datasheet: Y:\MIS_DATABASE\DATASHEETS\RESISTORS\CRCW_C-SER.PDF
R24 = RESISTOR: RES 1.58K 1/10W 1% 0402; Chkd/date: MAZHAR/160609; Crtd /date: USMAN/090609; Custom_Duty: 15%; Customs_HS_Code: 85332119; Distributor_name: DIGIKEY; Distributor_part_number: P1.58KLCT-ND; Footprint Path: Y:\MIS_DATABASE\Library\ALTIUM_TOOL\PCB_FOOTPRINTS\Altium_Footprint_Lib.PcbLib; Height: 0.40MM; Library Path: Y:\MIS_DATABASE\Library\ALTIUM_TOOL\SCHEMATICS_PARTS\MS_DISCRETE_Library.schlib; Mfr_name: PANASONIC-ECG; Mfr_part_number: ERJ-2RKF1581X; Mistral Part No: 110009031208-R; Package: 0402; Part_type: RESISTORS\FIXED; Project: BBB; RoHS: RoHS; Temperature: -55°C+155°C; Tolerance: 1%; Voltage: NA; Wattage: 1/10W; Weight: 0.8mg; Datasheet: Y:\MIS_DATABASE\DATASHEETS\RESISTORS\PAN-ERJSER_NOV17.PDF
R26 R469 = RESISTOR: RES 1K 1/10W 1% 0402; Chkd/date: VASANTHA/281216; Crtd /date: MAZHAR/150506; Custom_Duty: 15%; Customs_HS_Code: 85332119; Distributor_name: DIGIKEY; Distributor_part_number: P1.00KLCT-ND; Footprint Path: Y:\MIS_DATABASE\Library\ALTIUM_TOOL\PCB_FOOTPRINTS\Altium_Footprint_Lib.PcbLib; Height: 0.40MM; Library Path: Y:\MIS_DATABASE\Library\ALTIUM_TOOL\SCHEMATICS_PARTS\MS_DISCRETE_Library.schlib; Mfr_name: PANASONIC-ECG; Mfr_part_number: ERJ-2RKF1001X; Mistral Part No: 110009030411-R; Package: 0402; Part_type: RESISTORS\FIXED; Project: VOCERA; RoHS: RoHS; Temperature: -55°C+155°C; Tolerance: 1%; Voltage: NA; Wattage: 1/10W; Weight: 0.8mg; Datasheet: Y:\MIS_DATABASE\DATASHEETS\RESISTORS\PAN-ERJSER_NOV17.PDF
R27 = RESISTOR: RES 0.007E 1W 1% 1206-W; Chkd/date: MANIRAJA/060720; Crtd /date: ALVY/030720; Custom_Duty: 15%; Customs_HS_Code: 85332119; Distributor_name: DIGIKEY; Distributor_part_number: PRL1632.007FCT-ND; Footprint Path: Y:\MIS_DATABASE\Library\ALTIUM_TOOL\PCB_FOOTPRINTS\Altium_Footprint_Lib.PcbLib; Height: 0.60MM; Library Path: Y:\MIS_DATABASE\Library\ALTIUM_TOOL\SCHEMATICS_PARTS\MS_DISCRETE_Library.schlib; Mfr_name: SUSUMU; Mfr_part_number: PRL1632-R007-F-T1; Mistral Part No: 110020070003-R; Package: 1206-W; Part_type: RESISTORS\FIXED; Project: ISSI TDA4VM; RoHS: RoHS; Temperature: -55°C+125°C; Tolerance: 1%; Voltage: NA; Wattage: 1W; Weight: 13.2mg; Datasheet: Y:\MIS_DATABASE\DATASHEETS\RESISTORS\PRL-SERIES.PDF
TP1-TP3 TP79-TP81 = TESTPOINT: TESTPOINT CIR 40 SMD; Chkd/date: MAZHAR/190505; Crtd /date: MAZHAR/190505; Distributor_name: NA; Distributor_part_number: NA; Footprint Path: Y:\MIS_DATABASE\Library\ALTIUM_TOOL\PCB_FOOTPRINTS\Altium_Footprint_Lib.PcbLib; Height: NA; Library Path: Y:\MIS_DATABASE\Library\ALTIUM_TOOL\SCHEMATICS_PARTS\MS_DISCRETE_Library.schlib; MECHANICAL 3D STEP FILE: NA; Mfr_name: LOCAL; Mistral Part No: 130009030933; Package: SMD; Project: RAINIER-3; RoHS: NA; Temperature: NA; Tolerance: NA; Voltage: NA; Wattage: NA; Weight: NA; Datasheet: NA
U2 = SN74AHC1G02DBV_SOT23-5: IC SINGLE 2-INPUT POSITIVE-NOR GATE SOT553-5; Chkd/date: MANIRAJA/141020; Crtd /date: ALVY/131020; Custom_Duty: 15%; Customs_HS_Code: 85423100; Distributor_name: DIGIKEY; Distributor_part_number: 296-23229-1-ND; Footprint Path: Y:\MIS_DATABASE\Library\ALTIUM_TOOL\PCB_FOOTPRINTS\Altium_Footprint_Lib.PcbLib; Height: 0.60MM; Library Path: Y:\MIS_DATABASE\Library\ALTIUM_TOOL\SCHEMATICS_PARTS\MS_GATE_Library.schlib; Mfr_name: TEXAS INSTRUMENTS; Mistral Part No: 141020100014-R; Package: SOT553-5; Part_type: ICS\DIGITAL\GATES; Project: AM64X_SKEVM; RoHS: RoHS; Temperature: -40°C+125°C; Tolerance: NA; Voltage: NA; Wattage: NA; Weight: 2.8mg; Datasheet: Y:\MIS_DATABASE\DATASHEETS\ICS\DIGITAL\GATES\SN74AHC1G02XX.PDF
U3 = TPS22965DSGT_WSON8: IC 5.7V 6A 1-CHANNEL 16mE ON-RESISTANCE LOAD SWITCH WSON8; Chkd/date: MANIRAJA/080817; Crtd /date: VASANTHA/280714; Custom_Duty: 15%; Customs_HS_Code: 85423100; Distributor_name: DIGIKEY; Distributor_part_number: 296-34943-1-ND; Footprint Path: Y:\MIS_DATABASE\Library\ALTIUM_TOOL\PCB_FOOTPRINTS\Altium_Footprint_Lib.PcbLib; Height: 0.80MM; Library Path: Y:\MIS_DATABASE\Library\ALTIUM_TOOL\SCHEMATICS_PARTS\MS_MISCPOWER_Library.schlib; Mfr_name: TEXAS INSTRUMENTS; Mistral Part No: 142014070020-R; Package: WSON8; Part_type: ICS\POWER\DRIVER; Project: DC_MIST_DIGITAL CARD; RoHS: RoHS; Temperature: -40°C+105°C; Tolerance: NA; Voltage: NA; Wattage: NA; Weight: 11mg; Datasheet: Y:\MIS_DATABASE\DATASHEETS\ICS\POWER\TPS22965-SER.PDF
U4 = TPS2121RUXT_VQFNHR12: IC 4.5A 56mE PRIORITY POWER MUX WITH SEAMLESS SWITCHOVER VQFN-HR12; Chkd/date: VASANTHA/270319; Crtd /date: ALVY/270319; Custom_Duty: 15%; Customs_HS_Code: 85423100; Distributor_name: DIGIKEY; Distributor_part_number: 296-53412-1-ND; Footprint Path: Y:\MIS_DATABASE\Library\ALTIUM_TOOL\PCB_FOOTPRINTS\Altium_Footprint_Lib.PcbLib; Height: 1.00MM; Library Path: Y:\MIS_DATABASE\Library\ALTIUM_TOOL\SCHEMATICS_PARTS\MS_MISCPOWER_Library.schlib; Mfr_name: TEXAS INSTRUMENTS; Mistral Part No: 142019030004-R; Package: VQFN-HR12; Part_type: ICS\POWER; Project: RFSU BACKPLANE; RoHS: RoHS; Temperature: -40°C+125°C; Tolerance: NA; Voltage: NA; Wattage: NA; Weight: NA; Datasheet: Y:\MIS_DATABASE\DATASHEETS\ICS\POWER\TPS212XX.PDF
U5 = LM3488_VSSOP8: IC HIGH-EFFICIENCY CONTROLLER FOR BOOST SEPIC AND FLY-BACK DC-DC CONVERTERS VSSOP8; Chkd/date: ALVY/040522; Crtd /date: TAMILARASU/040522; Custom_Duty: 15%; Customs_HS_Code: 85423100; Distributor_name: DIGIKEY; Distributor_part_number: LM3488MM/NOPBCT-ND; Footprint Path: Y:\MIS_DATABASE\Library\ALTIUM_TOOL\PCB_FOOTPRINTS\Altium_Footprint_Lib.PcbLib; Height: 1.10MM; Library Path: Y:\MIS_DATABASE\Library\ALTIUM_TOOL\SCHEMATICS_PARTS\MS_MISCPOWER_Library.schlib; Mfr_name: TEXAS INSTRUMENTS; Mfr_part_number: LM3488MM/NOPB; Mistral Part No: 142022050001-R; Package: VSSOP8; Part_type: ICS\POWER\CONTROL; Project: AM263xC_BRD; RoHS: RoHS; Temperature: -40°C+125°C; Tolerance: NA; Voltage: NA; Wattage: NA; Weight: 31.3mg; Datasheet: Y:\MIS_DATABASE\DATASHEETS\ICS\POWER\LM3488.PDF
U6 = MOSFET_CSD18501Q5A: IC MOSFET N-CHANNEL 30V 47A VSON8; Chkd/date: VASANTHA/13115; Crtd /date: VASANTHA/13115; Custom_Duty: 15%; Customs_HS_Code: 85423100; Distributor_name: DIGIKEY; Distributor_part_number: 296-27210-1-ND; Footprint Path: Y:\MIS_DATABASE\Library\ALTIUM_TOOL\PCB_FOOTPRINTS\Altium_Footprint_Lib.PcbLib; Height: 1.10MM; Library Path: Y:\MIS_DATABASE\Library\ALTIUM_TOOL\SCHEMATICS_PARTS\MS_MOSFET_Library.schlib; Mfr_name: TEXAS INSTRUMENTS; Mistral Part No: 142015110013-R; Package: SON8; Part_type: ICS\POWER\MOSFET; Project: OCTASIC_3600; RoHS: RoHS; Temperature: -55°C+150°C; Tolerance: NA; Voltage: 30V; Wattage: NA; Weight: NA; Datasheet: Y:\MIS_DATABASE\DATASHEETS\DISCRETES\TRANSISTORS_FETS\CSD17308Q3.PDF
U17 = TUSB320LAI_X2QFN12: IC USB TYPE-C CHANNEL LOGIC AND PORT CONTROL X2QFN12; Chkd/date: MANIRAJA/210920; Crtd /date: ALVY/210920; Custom_Duty: 15%; Customs_HS_Code: 85423100; Distributor_name: DIGIKEY; Distributor_part_number: 296-TUSB320LAIRWBRCT-ND; Footprint Path: Y:\MIS_DATABASE\Library\ALTIUM_TOOL\PCB_FOOTPRINTS\Altium_Footprint_Lib.PcbLib; Height: 0.40MM; Library Path: Y:\MIS_DATABASE\Library\ALTIUM_TOOL\SCHEMATICS_PARTS\MS_MISCINTERFACE_Library.schlib; Mfr_name: TEXAS INSTRUMENTS; Mistral Part No: 141020090030-R; Package: X2QFN12; Part_type: ICS\INTERFACE; Project: AM64X_SKEVM; RoHS: RoHS; Temperature: -40°C+85°C; Tolerance: NA; Voltage: NA; Wattage: NA; Weight: 5mg; Datasheet: Y:\MIS_DATABASE\DATASHEETS\ICS\INTERFACE\TUSB320LAI.PDF

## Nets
DGND: C1.2 C2.2 C3.2 C4.2 C5.2 C6.1 C7.2 C8.2 C9.2 C10.2 C11.2 C12.1 C13.2 C14.2 C15.2 C16.2 C17.2 C18.2 C19.2 C20.2 C21.2 C22.2 C24.2 C353.2 C354.2 C355.2 D1.2(ANODE) D2.2(ANODE) D3.2(A) J1.A1(GND) J1.A12(GND) J1.B1(GND) J1.B12(GND) Q12.2(S) R2.1 R7.2 R8.2 R9.1 R14.2 R15.2 R16.2 R17.2 R18.2 R23.2 R24.2 R26.1 R27.2 U2.3(GND) U3.5(GND) U3.9(EP) U4.9(ST) U4.12(GND) U5.4(AGND) U5.5(PGND) U17.10(GND) ; also on sheet 1 2 3 6 7 8 9 10 11 12 13 14 15 16 17 24 25 26 27 28 29 30 32 33
VBUS_DET: R5.1 U17.4(VBUS_DET)
VBUS_MAIN: C7.1 R10.1 R11.1 U3.7(VOUT1) U3.8(VOUT2) U4.2(IN2)
VBUS_USBC: C1.1 C2.1 C3.1 C4.1 C5.1 C8.1 D3.1(K) J1.A4(VBUS1) J1.A9(VBUS2) J1.B4(VBUS3) J1.B9(VBUS4) R1.1 R3.1 R4.1 R5.2 R6.1 TP2.1(TP) U2.5(VCC) U3.1(VIN1) U3.2(VIN2) U3.4(VBIAS) U17.12(VDD)
C_A5_CC1: D1.1(CATHODE) J1.A5(CC1) U17.1(CC1)
C_B5_CC2: D2.1(CATHODE) J1.B5(CC2) U17.2(CC2)
HSEC_5V0: C13.1 C14.1 C15.1 R12.1 R13.1 TP81.1(TP) U4.7(IN1) ; also on sheet 6
LM3488_COMP: C22.1 C23.1 U5.2(COMP)
LM3488_DR: U5.6(DR) U6.4(GATE)
LM3488_FB: R21.1 R26.2 U5.3(FB)
LM3488_ISEN: R22.1 U5.1(ISEN)
TA_POWERDOWNz: Q12.1(G) ; also on sheet 3 28
TPS2121_CP2: R11.2 R15.1 U4.3(CP2)
TPS2121_OV1: R12.2 R16.1 U4.5(OV1)
TPS2121_OV2: R10.2 R14.1 U4.4(OV2)
TPS2121_PR1: R13.2 R17.1 U4.6(PR1)
TPS2296_EN: LD1.1(CATHODE) U2.4(Y) U3.3(ON)
TUSB_OUT1: R4.2 U2.2(B) U17.7(SDA/OUT1)
TUSB_OUT2: R3.2 U2.1(A) U17.8(SCL/OUT2)
USBC_EARTH: C6.2 J1.SH1 J1.SH2 J1.SH3 J1.SH4 R9.2
VMAIN: C10.1 C11.1 C12.2 C17.1 C18.1 C19.1 L1.1 TP80.1(TP) U4.1(OUT1) U4.8(OUT2) U5.8(VIN) ; also on sheet 1 10 14 26 27 29
VMAIN_12V0: C20.1 C21.1 C353.1 C354.1 D4.1(CATHODE) Q13.5(S) R20.2 R21.2 TP79.1(TP) ; also on sheet 13 30
VMAINP_12V0: C355.1 Q13.1(D1) Q13.2(D2) Q13.3(D3) TP3.1(TP) ; also on sheet 30
N35052540: R7.1 U17.5(ADDR)
N35052638: R18.1 U4.10(ILM)
N35052879: C9.1 U3.6(CT)
N35052899: R6.2 U17.6(INT_N/OUT3)
N35052954: R2.2 U17.3(PORT)
N35052969: TP1.1(TP) U17.9(ID)
N35053013: R8.1 U17.11(EN_N)
N35053423: C16.1 U4.11(SS)
N35053522: D4.2(ANODE) L1.2 U6.5(D1)
N35053536: C24.1 R22.2 R27.1 U6.1(S1) U6.2(S2) U6.3(S3)
N35053695: R23.1 U5.7(FA/SYNC/SD)
N35053732: C23.2 R24.1
N35056553: LD1.2(ANODE) R1.2
N35537520: Q13.4(G) R20.1 R469.1
N35538921: Q12.3(D) R469.2

Not connected (* = marked no-connect by the designer): J1 A2(TX1+) A3(TX1-) A6(D+_1) A7(D-_1) A8(SBU1) A10(RX2-) A11(RX2+) B2(TX2+) B3(TX2-) B6(D+_2) B7(D-_2) B8(SBU2) B10(RX1-) B11(RX1+)

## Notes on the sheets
sheet 4
- USB-C Power
- Configured as UFP MODE
  To Detect 5V/3A Source
- USB- C Connector
- RED
- POWER ERROR
  INDICATION LED
- Power MUX
- XCOMP
- OUTPUT
- OV2 set to 0.877V
- CP2 set to 1.65V
- OV1 set to 0.877V
- PR1 set to 2.5V
- PR1 > CP2
- HSEC_5V0
- PR1 = < CP2
- VBUS_MAIN
- OVP Set to 6.08V
- 3A max Output
- Designed as per reference sch
- DC-DC STAGE-1
   VMAIN to 12V
- TA_POWERDOWNz pulled to VSYS_TA_3V3
sheet 5
- POWER SEQUENCE
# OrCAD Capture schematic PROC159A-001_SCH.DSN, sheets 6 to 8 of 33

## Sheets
6 31. HSEC Connector: size C; title: HSEC CONN
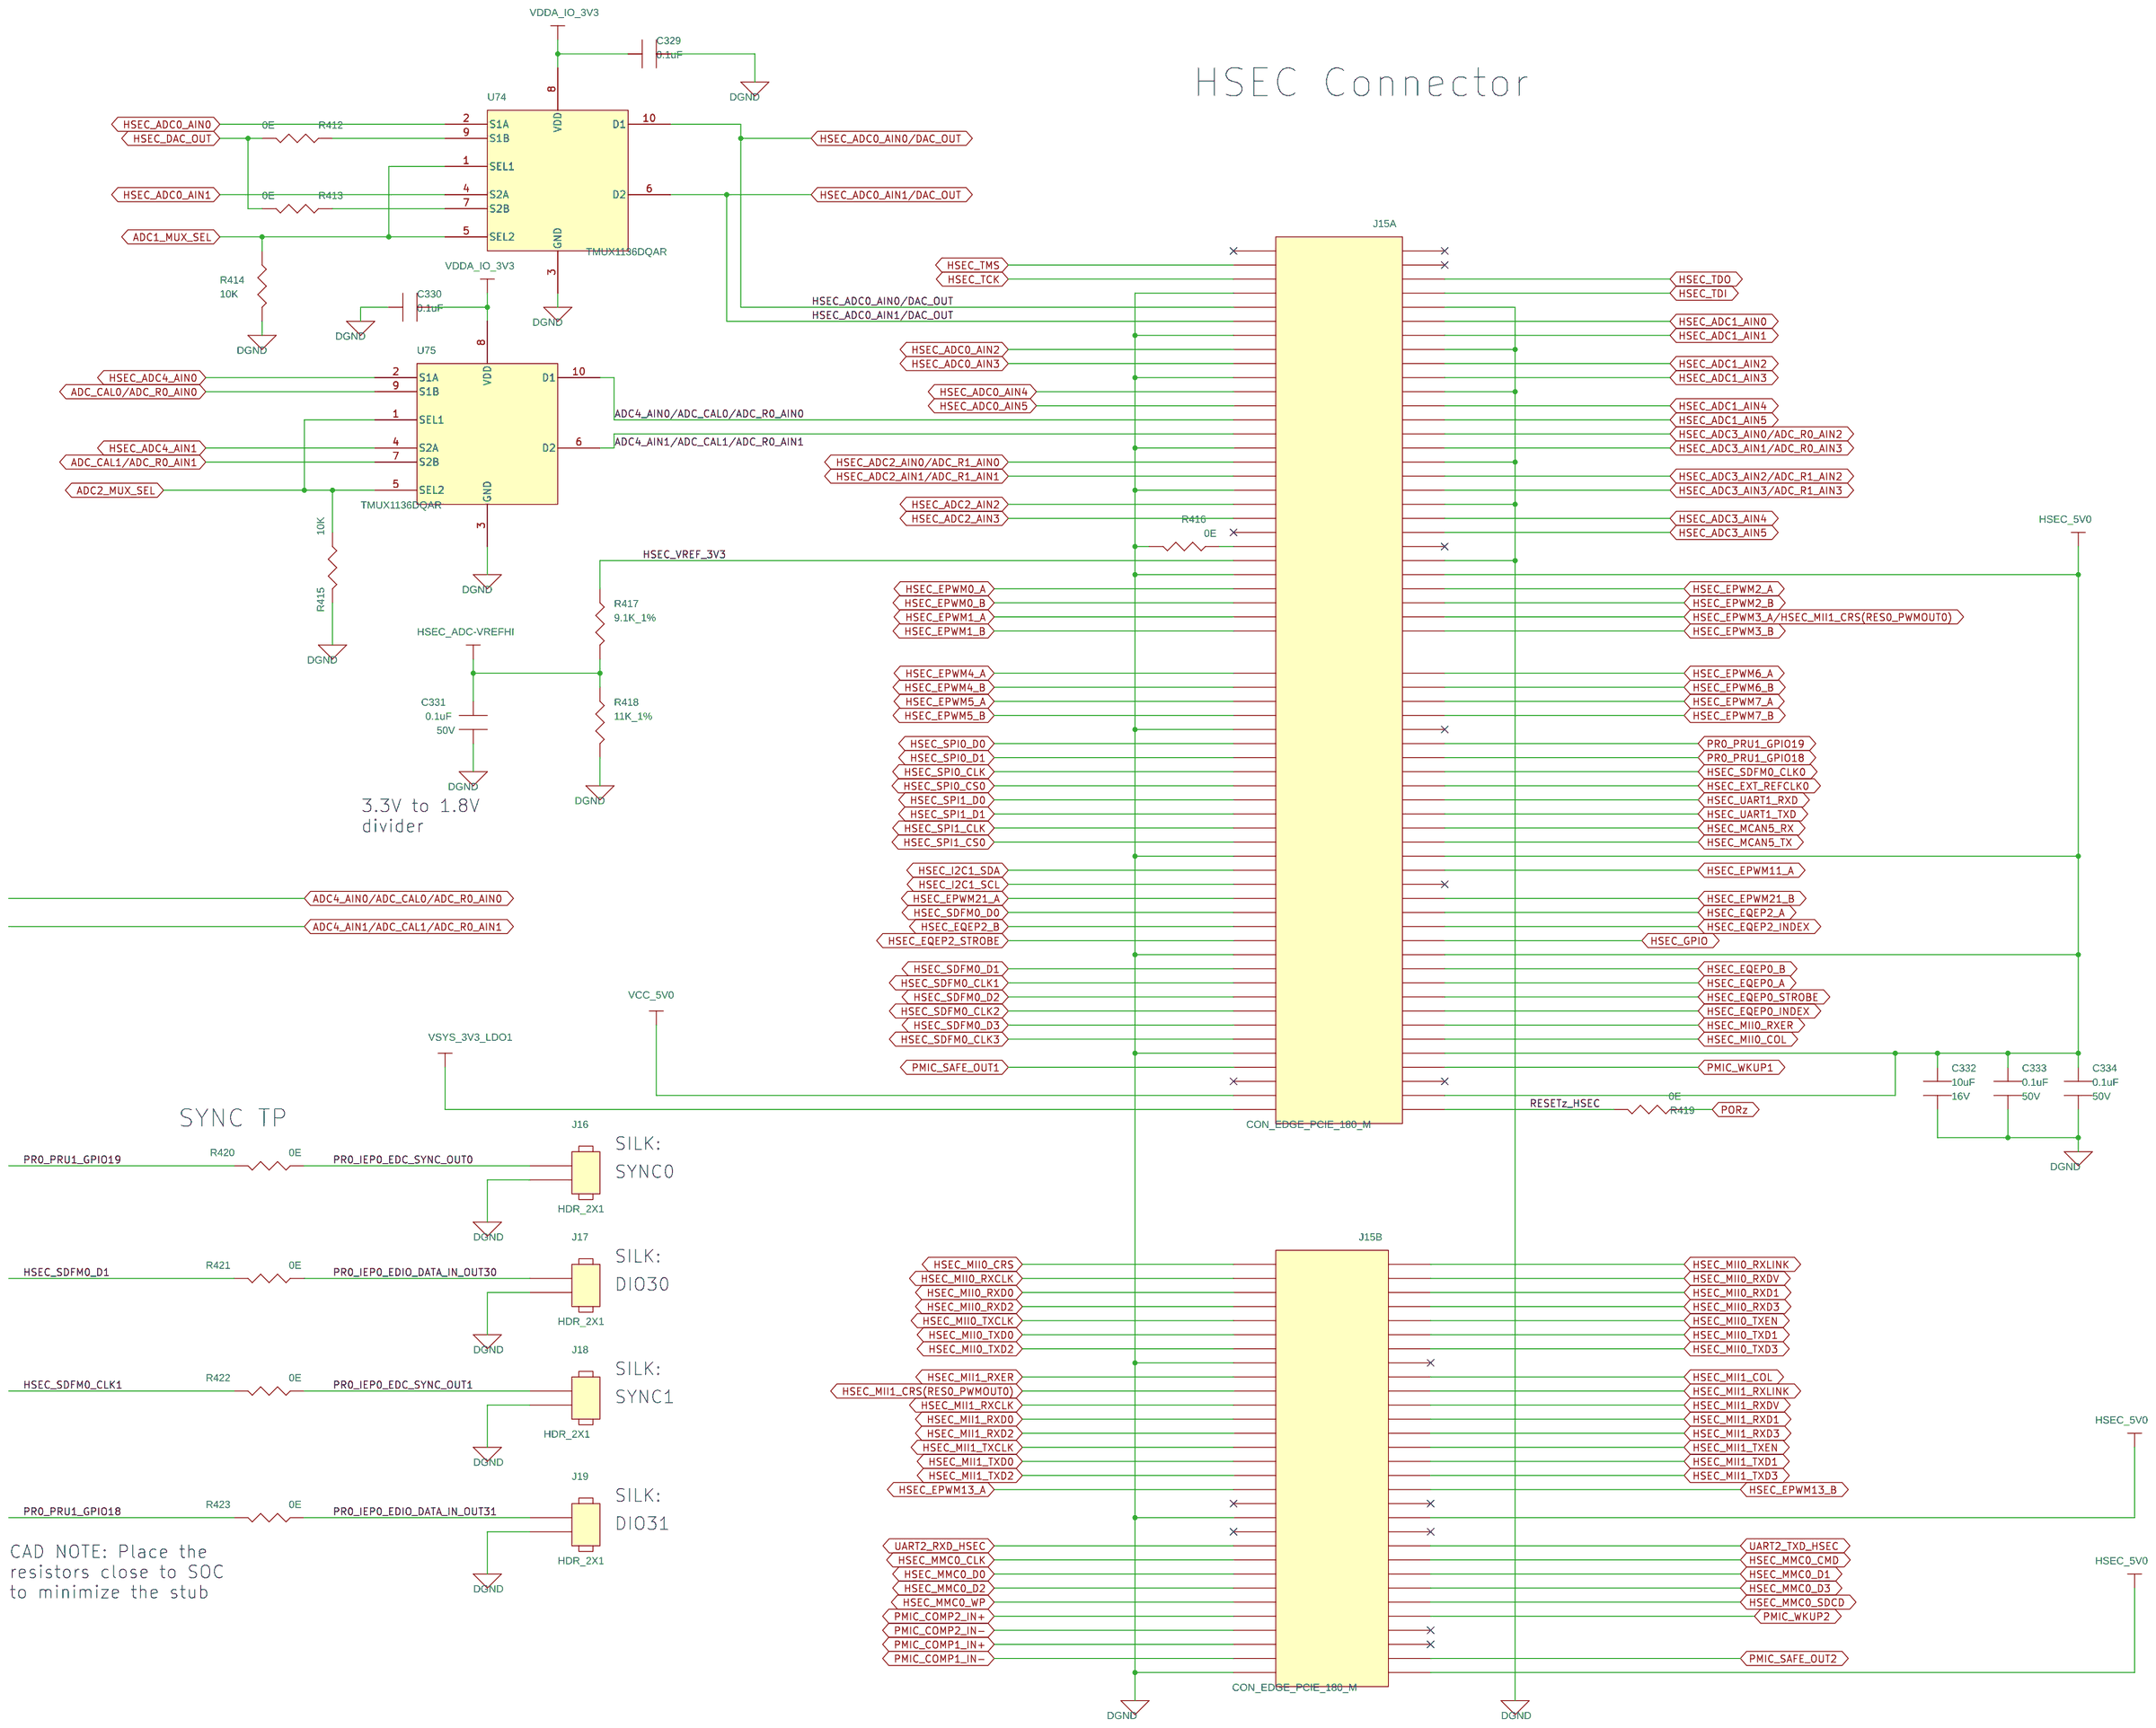
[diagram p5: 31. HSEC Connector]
7 20. SOC-ICSS ETHERNET CONN: size C; title: SOC-ICSS ETHERNET CONN
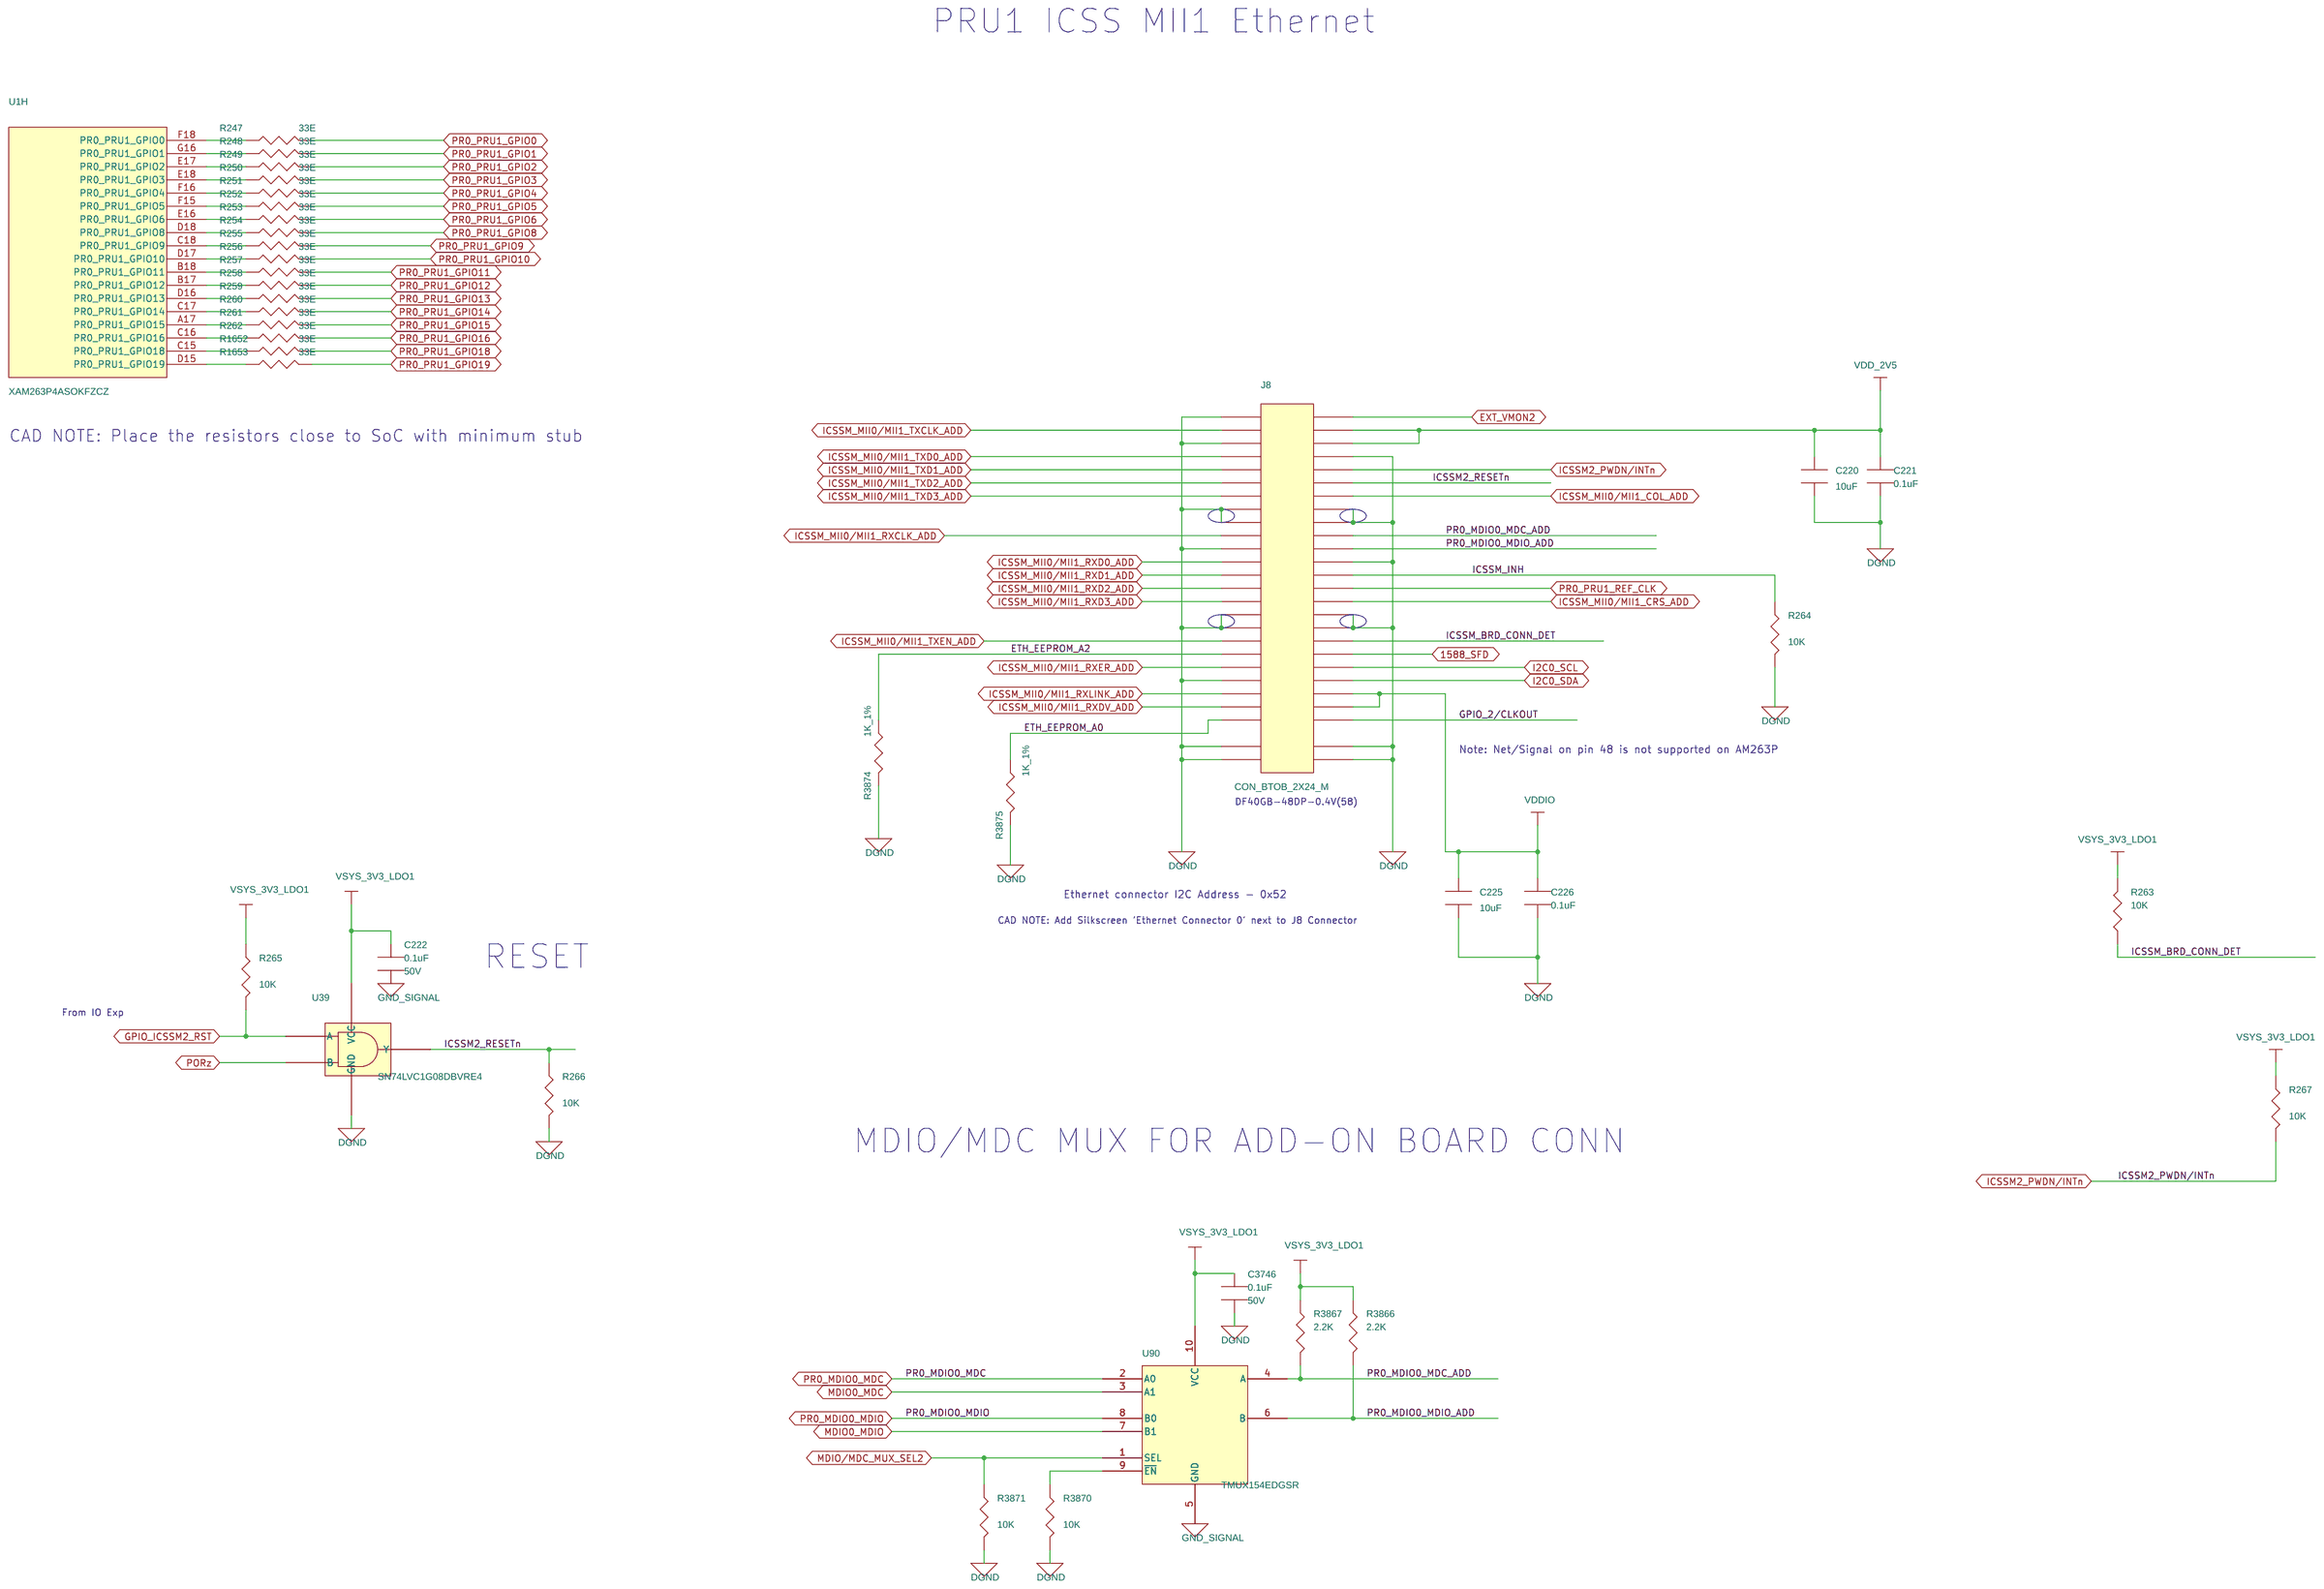
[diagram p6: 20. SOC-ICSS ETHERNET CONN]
8 13. SOC_POWER and GND: size C; title: SOC POWER AND GND

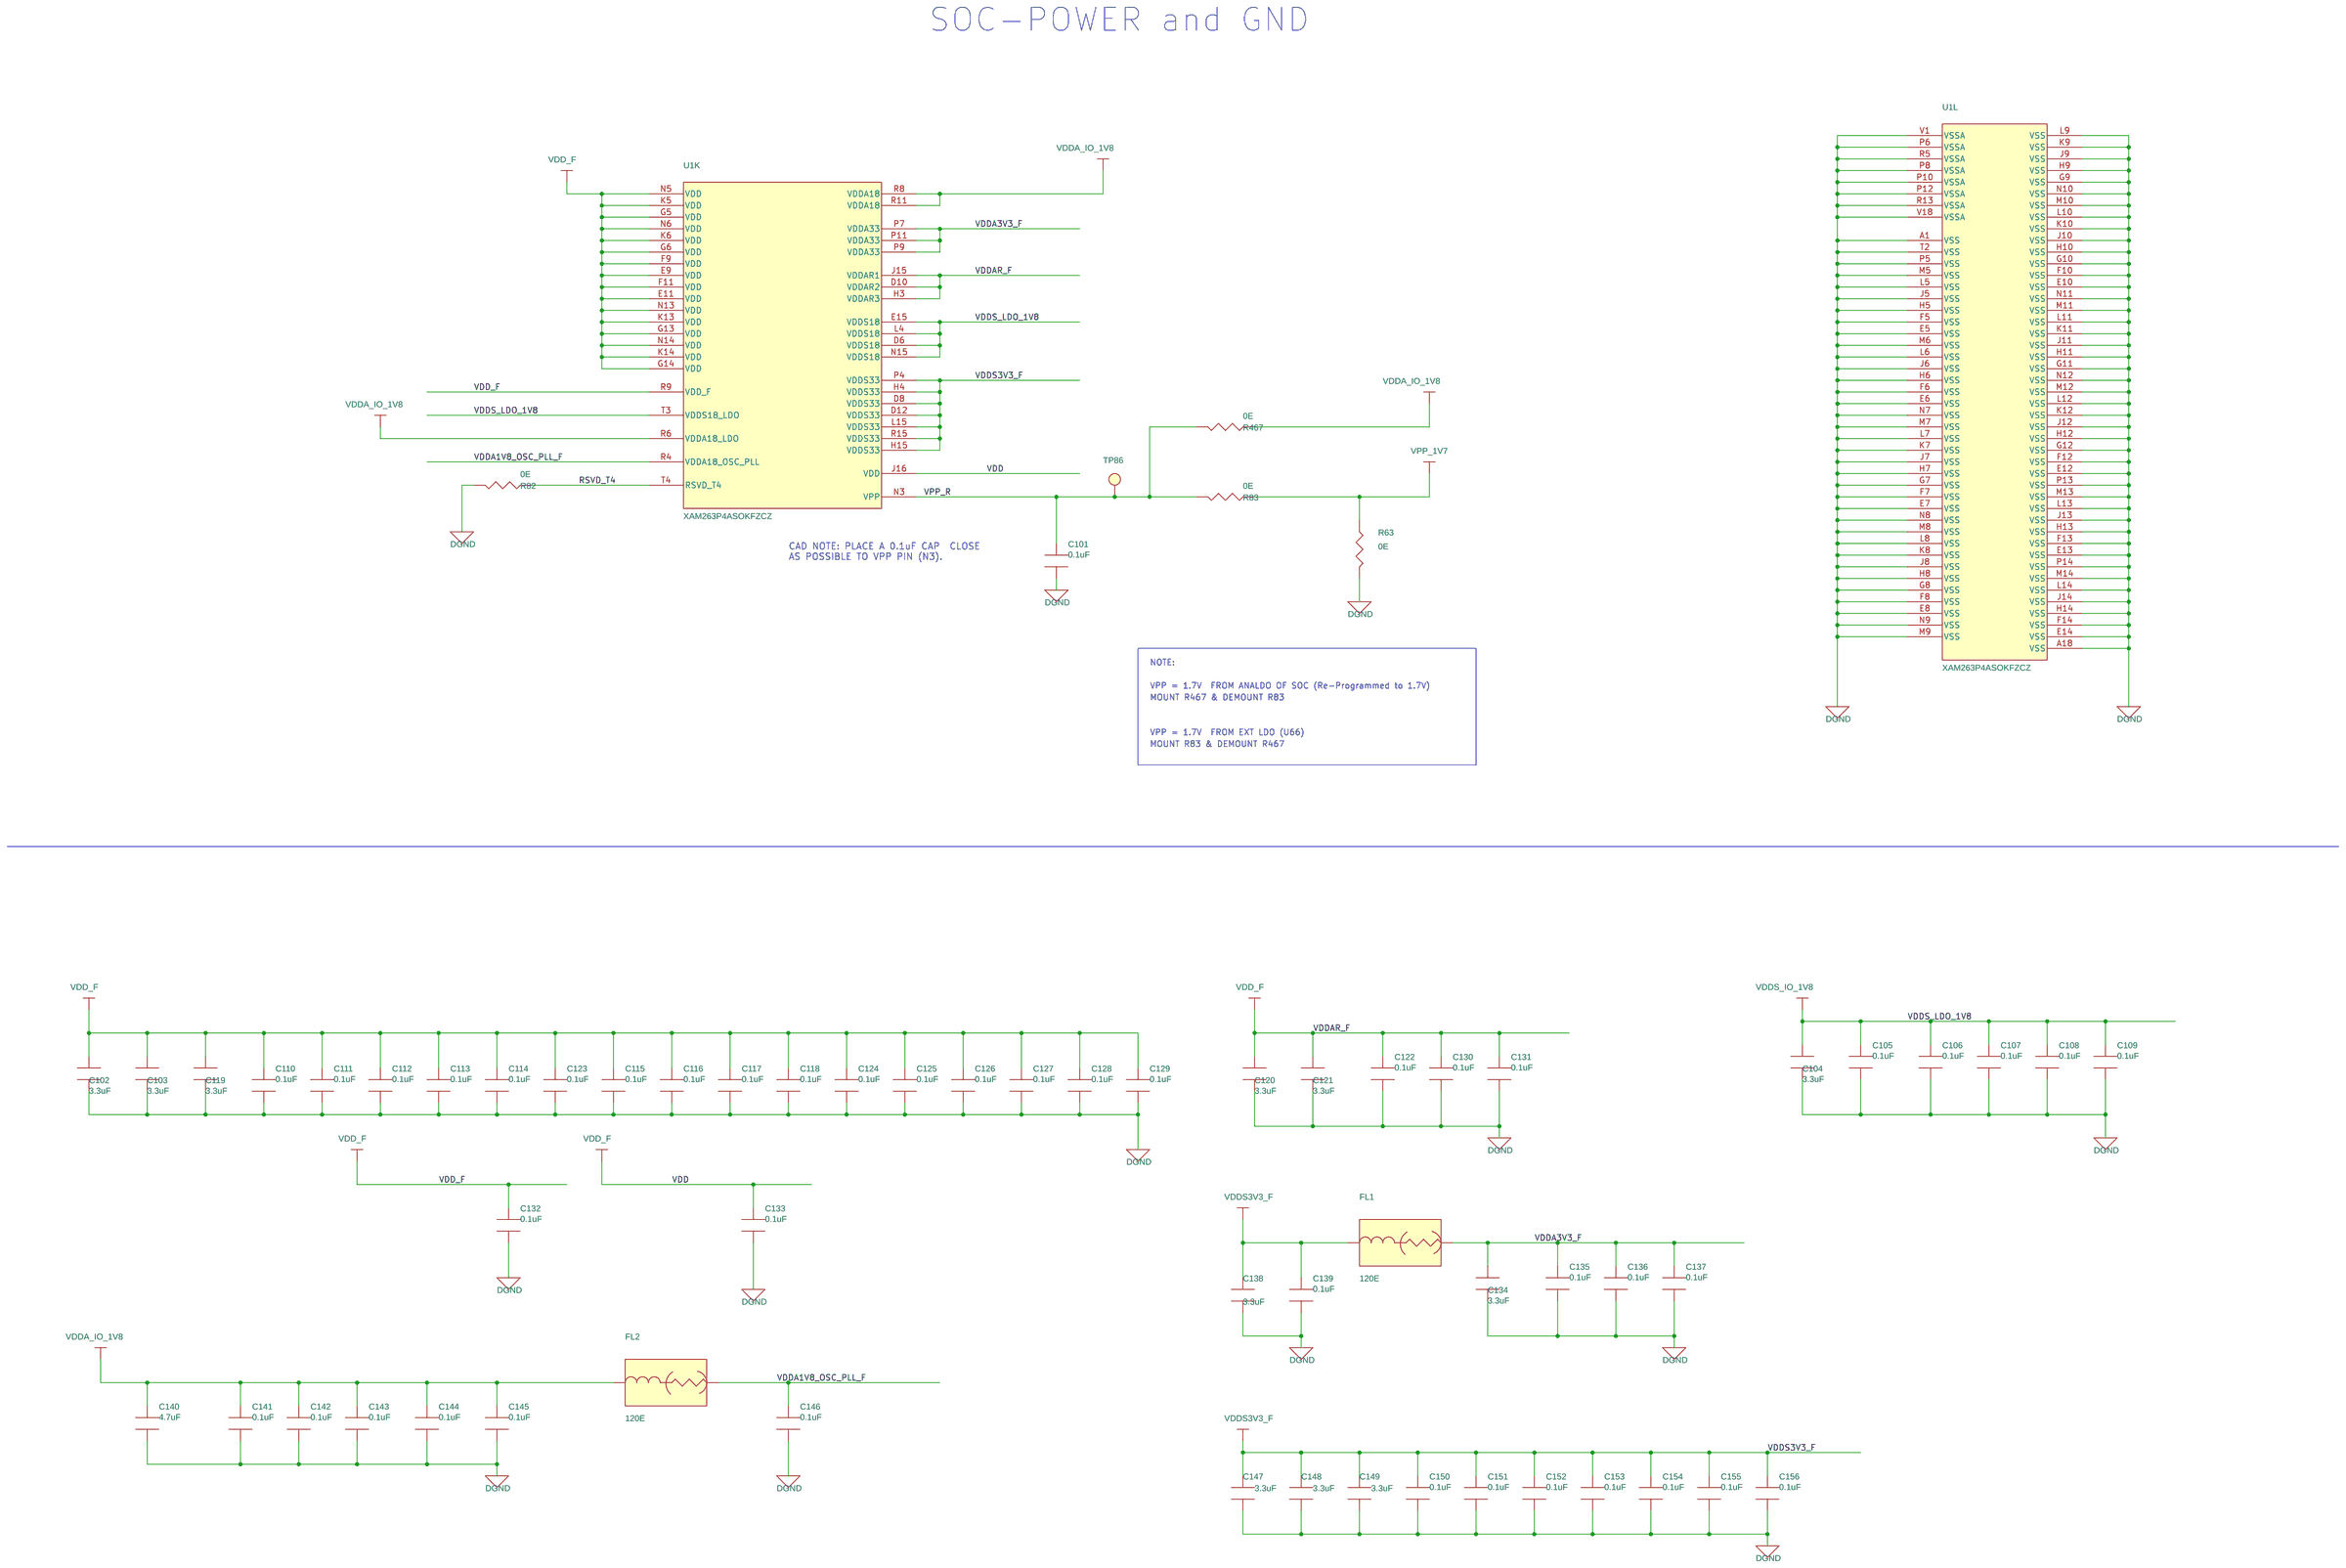
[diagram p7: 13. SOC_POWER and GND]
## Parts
sheet 13. SOC_POWER and GND
C101  0.1uF  [CAP0201_0-5]
C102  3.3uF  [CAP0603_1]
C103  3.3uF  [CAP0603_1]
C104  3.3uF  [CAP0603_1]
C105  0.1uF  [CAP0201_0-5]
C106  0.1uF  [CAP0201_0-5]
C107  0.1uF  [CAP0201_0-5]
C108  0.1uF  [CAP0402_0-75]
C109  0.1uF  [CAP0201_0-5]
C110  0.1uF  [CAP0201_0-5]
C111  0.1uF  [CAP0201_0-5]
C112  0.1uF  [CAP0201_0-5]
C113  0.1uF  [CAP0201_0-5]
C114  0.1uF  [CAP0201_0-5]
C115  0.1uF  [CAP0201_0-5]
C116  0.1uF  [CAP0201_0-5]
C117  0.1uF  [CAP0201_0-5]
C118  0.1uF  [CAP0201_0-5]
C119  3.3uF  [CAP0603_1]
C120  3.3uF  [CAP0603_1]
C121  3.3uF  [CAP0603_1]
C122  0.1uF  [CAP0201_0-5]
C123  0.1uF  [CAP0201_0-5]
C124  0.1uF  [CAP0201_0-5]
C125  0.1uF  [CAP0201_0-5]
C126  0.1uF  [CAP0201_0-5]
C127  0.1uF  [CAP0201_0-5]
C128  0.1uF  [CAP0201_0-5]
C129  0.1uF  [CAP0201_0-5]
C130  0.1uF  [CAP0201_0-5]
C131  0.1uF  [CAP0201_0-5]
C132  0.1uF  [CAP0201_0-5]
C133  0.1uF  [CAP0201_0-5]
C134  3.3uF  [CAP0603_1]
C135  0.1uF  [CAP0201_0-5]
C136  0.1uF  [CAP0201_0-5]
C137  0.1uF  [CAP0201_0-5]
C138  3.3uF  [CAP0603_1]
C139  0.1uF  [CAP0201_0-5]
C140  4.7uF  [CAP0603_1]
C141  0.1uF  [CAP0201_0-5]
C142  0.1uF  [CAP0201_0-5]
C143  0.1uF  [CAP0201_0-5]
C144  0.1uF  [CAP0201_0-5]
C145  0.1uF  [CAP0201_0-5]
C146  0.1uF  [CAP0201_0-5]
C147  3.3uF  [CAP0603_1]
C148  3.3uF  [CAP0603_1]
C149  3.3uF  [CAP0603_1]
C150  0.1uF  [CAP0201_0-5]
C151  0.1uF  [CAP0201_0-5]
C152  0.1uF  [CAP0201_0-5]
C153  0.1uF  [CAP0201_0-5]
C154  0.1uF  [CAP0201_0-5]
C155  0.1uF  [CAP0201_0-5]
C156  0.1uF  [CAP0201_0-5]
FL1  120E  [EMIFIL_BLM18R_0603_1]
FL2  120E  [EMIFIL_BLM18R_0603_1]
R63  0E  [RES0402_0-5]
R82  0E  [RES0402_0-5]
R83  0E  [RES0402_0-5]
R467  0E  [RES0402_0-5]
TP86  TP20_SMD  [TP20_SMD]
U1  XAM263P4ASOKFZCZ  [BGA324_31-49_590X590_1-4]  (sections A,B,C,D,E,F,G,H,I,J,K,L,M)
sheet 20. SOC-ICSS ETHERNET CONN
C220  10uF  [CAP0402_0-75]
C221  0.1uF  [CAP0402_0-75]
C222  0.1uF  [CAP0402_0-75]
C225  10uF  [CAP0402_0-75]
C226  0.1uF  [CAP0402_0-75]
C3746  0.1uF  [CAP0402_0-75]
J8  CON_BTOB_2X24_M  [CON_BTOB2X24_DF40GB-48DP_P_S_S_1-3]
R247  33E  [RES0402_0-5]
R248  33E  [RES0402_0-5]
R249  33E  [RES0402_0-5]
R250  33E  [RES0402_0-5]
R251  33E  [RES0402_0-5]
R252  33E  [RES0402_0-5]
R253  33E  [RES0402_0-5]
R254  33E  [RES0402_0-5]
R255  33E  [RES0402_0-5]
R256  33E  [RES0402_0-5]
R257  33E  [RES0402_0-5]
R258  33E  [RES0402_0-5]
R259  33E  [RES0402_0-5]
R260  33E  [RES0402_0-5]
R261  33E  [RES0402_0-5]
R262  33E  [RES0402_0-5]
R263  10K  [RES0201_0-5]
R264  10K  [RES0402_0-5]
R265  10K  [RES0402_0-5]
R266  10K  [RES0402_0-5]
R267  10K  [RES0402_0-5]
R1652  33E  [RES0402_0-5]
R1653  33E  [RES0402_0-5]
R3866  2.2K  [RES0402_0-5]
R3867  2.2K  [RES0402_0-5]
R3870  10K  [RES0402_0-5]
R3871  10K  [RES0402_0-5]
R3874  1K_1%  [RES0402_0-5]
R3875  1K_1%  [RES0402_0-5]
U39  SN74LVC1G08DBVRE4  [SOT23-5]
U90  TMUX154EDGSR  [MSOP10_19-68_120X120_1-1]
sheet 31. HSEC Connector
C329  0.1uF  [CAP0402_0-75]
C330  0.1uF  [CAP0402_0-75]
C331  0.1uF  [CAP0402_0-75]
C332  10uF  [CAP0603_1]
C333  0.1uF  [CAP0402_0-75]
C334  0.1uF  [CAP0402_0-75]
J15  CON_EDGE_PCIE_180_M  [CON_EDGE180_HSEC8-180_FING_P_R_S]  (sections A,B)
J16  HDR_2X1  [HDR_2X1_100_S_T_10-8]
J17  HDR_2X1  [HDR_2X1_100_S_T_10-8]
J18  HDR_2X1  [HDR_2X1_100_S_T_10-8]
J19  HDR_2X1  [HDR_2X1_100_S_T_10-8]
R412  0E  [RES0402_0-5]
R413  0E  [RES0402_0-5]
R414  10K  [RES0402_0-5]
R415  10K  [RES0402_0-5]
R416  0E  [RES0402_0-5]
R417  9.1K_1%  [RES0402_0-5]
R418  11K_1%  [RES0402_0-5]
R419  0E  [RES0402_0-5]
R420  0E  [RES0402_0-5]
R421  0E  [RES0402_0-5]
R422  0E  [RES0402_0-5]
R423  0E  [RES0402_0-5]
U74  TMUX1136DQAR  [USON10_TMUX1204_40X100_0-6]
U75  TMUX1136DQAR  [USON10_TMUX1204_40X100_0-6]

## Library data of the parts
C101 C105-C107 C109-C118 C122-C133 C135-C137 C139 C141-C146 C150-C156 = CAP: CAP CERAMIC 0.1uF 10V 10% X5R 0201; Chkd/date: VASANTHA/061216; Crtd /date: MUDDU/190810; Custom_Duty: 15%; Customs_HS_Code: 85322990; Distributor_name: DIGIKEY; Distributor_part_number: 490-5881-1-ND; Footprint Path: Y:\MIS_DATABASE\Library\ALTIUM_TOOL\PCB_FOOTPRINTS\Altium_Footprint_Lib.PcbLib; Height: 0.33MM; Library Path: Y:\MIS_DATABASE\Library\ALTIUM_TOOL\SCHEMATICS_PARTS\MS_DISCRETE_Library.schlib; Mfr_name: MURATA; Mfr_part_number: GRM033R61A104KE15D; Mistral Part No: 120009050017-R; Package: 0201; Part_type: CAPACITORS\CERAMIC; Project: PB_BUGBASE; RoHS: RoHS; Temperature: -55°C+85°C; Tolerance: 10%; Voltage: 10V; Wattage: NA; Weight: 0.33mg; Datasheet: Y:\MIS_DATABASE\DATASHEETS\CAPACITORS\MURATA-GXX-SER_NOV17.PDF
C102-C104 C119-C121 C134 C138 C147-C149 = CAP: CAP CERAMIC 3.3uF 10V 10% X5R 0603; Chkd/date: MANIRAJA/210519; Crtd /date: MANIRAJA/210519; Custom_Duty: 15%; Customs_HS_Code: 85322990; Distributor_name: DIGIKEY; Distributor_part_number: 1276-1892-1-ND; Footprint Path: Y:\MIS_DATABASE\Library\ALTIUM_TOOL\PCB_FOOTPRINTS\Altium_Footprint_Lib.PcbLib; Height: 0.90MM; Library Path: Y:\MIS_DATABASE\Library\ALTIUM_TOOL\SCHEMATICS_PARTS\MS_DISCRETE_Library.schlib; Mfr_name: SAMSUNG; Mfr_part_number: CL10A335KP8NNNC; Mistral Part No: 120014070039-R; Package: 0603; Part_type: CAPACITORS\CERAMIC; Project: RFSU_RFTJ_CARD; RoHS: RoHS; Temperature: -55°C+85°C; Tolerance: 10%; Voltage: 10V; Wattage: NA; Weight: NA; Datasheet: Y:\MIS_DATABASE\DATASHEETS\CAPACITORS\CL10A335KP8NNNC.PDF
C108 = CAP: CAP CERAMIC 0.1uF 25V 10% X7R 0402; Chkd/date: MANIRAJA/190218; Crtd /date: ALVY/160218; Custom_Duty: 15%; Customs_HS_Code: 85322990; Distributor_name: DIGIKEY; Distributor_part_number: 490-10698-1-ND; Footprint Path: Y:\MIS_DATABASE\Library\ALTIUM_TOOL\PCB_FOOTPRINTS\Altium_Footprint_Lib.PcbLib; Height: 0.55MM; Library Path: Y:\MIS_DATABASE\Library\ALTIUM_TOOL\SCHEMATICS_PARTS\MS_DISCRETE_Library.schlib; Mfr_name: MURATA; Mfr_part_number: GRM155R71E104KE14D; Mistral Part No: 120013060012-R; Package: 0402; Part_type: CAPACITORS\CERAMIC; Project: GRACO SMART MODULE; RoHS: RoHS; Temperature: -55°C+125°C; Tolerance: 10%; Voltage: 25V; Wattage: NA; Weight: 6mg; Datasheet: Y:\MIS_DATABASE\DATASHEETS\CAPACITORS\GRM155R71E104KE14.PDF
C140 = CAP: CAP CERAMIC 4.7uF 25V 10% X6S 0603; Chkd/date: MANIRAJA/241018; Crtd /date: ALVY/241018; Custom_Duty: 15%; Customs_HS_Code: 85322990; Distributor_name: DIGIKEY; Distributor_part_number: 490-7199-1-ND; Footprint Path: Y:\MIS_DATABASE\Library\ALTIUM_TOOL\PCB_FOOTPRINTS\Altium_Footprint_Lib.PcbLib; Height: 1.00MM; Library Path: Y:\MIS_DATABASE\Library\ALTIUM_TOOL\SCHEMATICS_PARTS\MS_DISCRETE_Library.schlib; Mfr_name: MURATA; Mfr_part_number: GRM188C81E475KE11D; Mistral Part No: 120018100056-R; Package: 0603; Part_type: CAPACITORS\CERAMIC; Project: TI_J7ES_EVM_CP; RoHS: RoHS; Temperature: -55°C+105°C; Tolerance: 10%; Voltage: 25V; Wattage: NA; Weight: 6.3mg; Datasheet: Y:\MIS_DATABASE\DATASHEETS\CAPACITORS\GRM188C81E475KE11D.PDF
FL1 FL2 = EMIFILTER_IND: FERRITE BEAD 120E 2A 0603; Chkd/date: VASANTHA/061216; Crtd /date: MUDDU/190610; Custom_Duty: 24%; Customs_HS_Code: 85437099; Distributor_name: DIGIKEY; Distributor_part_number: 490-3991-1-ND; Footprint Path: Y:\MIS_DATABASE\Library\ALTIUM_TOOL\PCB_FOOTPRINTS\Altium_Footprint_Lib.PcbLib; Height: 0.95MM; Library Path: Y:\MIS_DATABASE\Library\ALTIUM_TOOL\SCHEMATICS_PARTS\MS_FILTER_Library.schlib; Mfr_name: MURATA; Mfr_part_number: BLM18EG121SN1D; Mistral Part No: 130010060030-R; Package: 0603; Part_type: FILTER; Project: CENTAURUS; RoHS: RoHS; Temperature: -55°C+125°C; Tolerance: NA; Voltage: NA; Wattage: NA; Weight: NA; Datasheet: Y:\MIS_DATABASE\DATASHEETS\DISCRETES\INDUCTORS\BLM18E.PDF
R63 R82 R83 R412 R413 R416 R419-R423 R467 = RESISTOR: RES 0E 1/10W JUMPER 0402; Chkd/date: VASANTHA/061216; Crtd /date: NAVEED/201014; Custom_Duty: 15%; Customs_HS_Code: 85332119; Distributor_name: DIGIKEY; Distributor_part_number: P0.0JCT-ND; Footprint Path: Y:\MIS_DATABASE\Library\ALTIUM_TOOL\PCB_FOOTPRINTS\Altium_Footprint_Lib.PcbLib; Height: 0.40MM; IBISSP_MODLES: VALUE REPEATING 2 TIME; Library Path: Y:\MIS_DATABASE\Library\ALTIUM_TOOL\SCHEMATICS_PARTS\MS_DISCRETE_Library.schlib; Mfr_name: PANASONIC-ECG; Mfr_part_number: ERJ-2GE0R00X; Mistral Part No: 110018030052-R; Package: 0402; Part_type: RESISTORS\FIXED; Project: AEGIS POM; RoHS: RoHS; Temperature: -55°C+155°C; Tolerance: NA; Voltage: NA; Wattage: 1/10W; Weight: 0.8mg; Datasheet: Y:\MIS_DATABASE\DATASHEETS\RESISTORS\PAN-ERJSER_NOV17.PDF
TP86 = TESTPOINT: TESTPOINT CIR 20 SMD; Chkd/date: SHREESHAIL/171006; Crtd /date: MAZHAR/171006; Custom_Duty: NA; Customs_HS_Code: NA; Distributor_name: NA; Distributor_part_number: NA; Footprint Path: Y:\MIS_DATABASE\Library\ALTIUM_TOOL\PCB_FOOTPRINTS\Altium_Footprint_Lib.PcbLib; Height: NA; Library Path: Y:\MIS_DATABASE\Library\ALTIUM_TOOL\SCHEMATICS_PARTS\MS_DISCRETE_Library.schlib; MECHANICAL 3D STEP FILE: NA; Mfr_name: LOCAL; Mistral Part No: NA; Package: SMD; Project: BT MODULE_CSRBC04; RoHS: NA; Temperature: NA; Tolerance: NA; Voltage: NA; Wattage: NA; Weight: NA; Datasheet: NA
U1 = XAM263P4ASOKFZCZ_BGA324: IC AM263P SoC BGA324; Chkd/date: PRAVEEN/050423; Crtd /date: PRAVEEN/050423; Custom_Duty: 15%; Customs_HS_Code: 85423100; Distributor_name: NA; Distributor_part_number: NA; Footprint Path: Y:\MIS_DATABASE\Library\ALTIUM_TOOL\PCB_FOOTPRINTS\Altium_Footprint_Lib.PcbLib; Height: 1.40MM; MECHANICAL 3D STEP FILE: NA; Mfr_name: NA; Mistral Part No: 141323040001; Package: BGA324; Part_type: ICS\DIGITAL\FPGA; Project: AM263P_CC; RoHS: RoHS; Temperature: NA; Tolerance: NA; Voltage: NA; Wattage: NA; Weight: NA; Datasheet: Y:\MIS_DATABASE\DATASHEETS\ICS\INTERFACE\ZCZ0324A.PDF
C220 C225 = CAP: CAP CERAMIC 10uF 10V 20% X5R 0402; Chkd/date: MANIRAJA/300520; Crtd /date: ALVY/260520; Custom_Duty: 15%; Customs_HS_Code: 85322990; Distributor_name: DIGIKEY; Distributor_part_number: 490-GRM155R61A106ME11DTR-ND; Footprint Path: Y:\MIS_DATABASE\Library\ALTIUM_TOOL\PCB_FOOTPRINTS\Altium_Footprint_Lib.PcbLib; Height: 0.55MM; Library Path: Y:\MIS_DATABASE\Library\ALTIUM_TOOL\SCHEMATICS_PARTS\MS_DISCRETE_Library.schlib; Mfr_name: MURATA; Mfr_part_number: GRM155R61A106ME11D; Mistral Part No: 120013110019-R; Package: 0402; Part_type: CAPACITORS\CERAMIC; Project: QCS610_NANOSOM; RoHS: RoHS; Temperature: -55°C+85°C; Tolerance: 20%; Voltage: 10V; Wattage: NA; Weight: 3.1mg; Datasheet: Y:\MIS_DATABASE\DATASHEETS\CAPACITORS\MURATA-GXX-SER_NOV17.PDF
C221 C226 C329-C331 C333 C334 = CAP: CAP CERAMIC 0.1uF 50V 10% X7R 0402; Chkd/date: MANIRAJA/261020; Crtd /date: ALVY/211020; Custom_Duty: 15%; Customs_HS_Code: 85322990; Distributor_name: DIGIKEY; Distributor_part_number: 490-10700-1-ND; Footprint Path: Y:\MIS_DATABASE\Library\ALTIUM_TOOL\PCB_FOOTPRINTS\Altium_Footprint_Lib.PcbLib; Height: 0.55MM; Library Path: Y:\MIS_DATABASE\Library\ALTIUM_TOOL\SCHEMATICS_PARTS\MS_DISCRETE_Library.schlib; Mfr_name: MURATA; Mfr_part_number: GRM155R71H104KE14D; Mistral Part No: 120011100014-R; Package: 0402; Part_type: CAPACITORS\CERAMIC; Project: J7_CP; RoHS: RoHS; Temperature: -55°C+125°C; Tolerance: 10%; Voltage: 50V; Wattage: NA; Weight: 3.1mg; Datasheet: Y:\MIS_DATABASE\DATASHEETS\CAPACITORS\GRM155R71H104KE14.PDF
C222 C3746 = CAP: CAP CERAMIC 0.1uF 50V 10% X7R 0402; Automotive Alternate_mfr_name: TDK; Automotive Alternate_mfr_part_number: CGA2B3X7R1H104K050BB; Chkd/date: MANIRAJA/261020; Crtd /date: ALVY/211020; Custom_Duty: 15%; Customs_HS_Code: 85322990; Direct Alternate_mfr_name: TDK; Direct Alternate_mfr_part_number: C1005X7R1H104K050BE; Distributor_name: DIGIKEY; Distributor_part_number: 490-10700-1-ND; Footprint Path: Y:\MIS_DATABASE\Library\ALTIUM_TOOL\PCB_FOOTPRINTS\Altium_Footprint_Lib.PcbLib; Height: 0.55MM; Library Path: Y:\MIS_DATABASE\Library\ALTIUM_TOOL\SCHEMATICS_PARTS\MS_DISCRETE_Library.schlib; Mfr_name: MURATA; Mfr_part_number: GRM155R71H104KE14D; Mistral Part No: 120011100014-R; Package: 0402; Part_type: CAPACITORS\CERAMIC; Project: J7_CP; RoHS: RoHS; Temperature: -55°C+125°C; Tolerance: 10%; Voltage: 50V; Wattage: NA; Weight: 3.1mg; Datasheet: Y:\MIS_DATABASE\DATASHEETS\CAPACITORS\GRM155R71H104KE14.PDF
J8 = CON_BTOB_24X2_M_SH4: CON BTOB 2X24 0.40MM PITCH MALE ST SMD; Chkd/date: PRAVEEN/290323; Crtd /date: PRAVEEN/290323; Custom_Duty: 24%; Customs_HS_Code: 85369090; Distributor_name: DIGIKEY; Distributor_part_number: H124956CT-ND; Footprint Path: Y:\MIS_DATABASE\Library\ALTIUM_TOOL\PCB_FOOTPRINTS\Altium_Footprint_Lib.PcbLib; Height: 1.30MM; Library Path: Y:\MIS_DATABASE\Library\ALTIUM_TOOL\SCHEMATICS_PARTS\MS_CONNECTOR_Library.schlib; Mfr_name: HIROSE ELECTRIC EUROPE; Mfr_part_number: DF40GB-48DP-0.4V(58); Mistral Part No: 150023030029-R; Package: SMD; Part_type: CONNECTOR\BTOB; Project: AM263P_CC; RoHS: RoHS; Temperature: -35°C+85°C; Tolerance: NA; Voltage: NA; Wattage: NA; Weight: NA; Datasheet: Y:\MIS_DATABASE\DATASHEETS\CONNECTORS\DF40GB-48DP-0.4V.PDF
R247-R262 R1652 R1653 = RESISTOR: RES 33E 1/10W 5% 0402; Chkd/date: VASANTHA/201216; Crtd /date: GEETHA/190406; Custom_Duty: 15%; Customs_HS_Code: 85332119; Distributor_name: DIGIKEY; Distributor_part_number: P33JCT-ND; Footprint Path: Y:\MIS_DATABASE\Library\ALTIUM_TOOL\PCB_FOOTPRINTS\Altium_Footprint_Lib.PcbLib; Height: 0.40MM; Library Path: Y:\MIS_DATABASE\Library\ALTIUM_TOOL\SCHEMATICS_PARTS\MS_DISCRETE_Library.schlib; Mfr_name: PANASONIC-ECG; Mfr_part_number: ERJ-2GEJ330X; Mistral Part No: 110009030699-R; Package: 0402; Part_type: RESISTORS\FIXED; Project: RED EYE; RoHS: RoHS; Temperature: -55°C+155°C; Tolerance: 5%; Voltage: NA; Wattage: 1/10W; Weight: 0.8mg; Datasheet: Y:\MIS_DATABASE\DATASHEETS\RESISTORS\PAN-ERJSER_NOV17.PDF
R263 = RESISTOR: RES 10K 1/20W 5% 0201; Chkd/date: MANIRAJA/050517; Crtd /date: MANIRAJA/050517; Custom_Duty: 15%; Customs_HS_Code: 85332119; Distributor_name: DIGIKEY; Distributor_part_number: 311-10KNCT-ND; Footprint Path: Y:\MIS_DATABASE\Library\ALTIUM_TOOL\PCB_FOOTPRINTS\Altium_Footprint_Lib.PcbLib; Height: 0.26MM; Library Path: Y:\MIS_DATABASE\Library\ALTIUM_TOOL\SCHEMATICS_PARTS\MS_DISCRETE_Library.schlib; Mfr_name: YAGEO AMERICA; Mfr_part_number: RC0201JR-0710KL; Mistral Part No: 110010070051-R; Package: 0201; Part_type: RESISTORS\FIXED; Project: GOLDEN-I LITE; RoHS: RoHS; Temperature: -55°C+125°C; Tolerance: 5%; Voltage: NA; Wattage: 1/20W; Weight: 0.17mg; Datasheet: Y:\MIS_DATABASE\DATASHEETS\RESISTORS\RCXXXXL-SER_MAR18.PDF
R264-R267 R414 R415 R3870 R3871 = RESISTOR: RES 10K 1/16W 5% 0402; Chkd/date: VASANTHA/061216; Crtd /date: MAZHAR/230805; Custom_Duty: 15%; Customs_HS_Code: 85332119; Distributor_name: DIGIKEY; Distributor_part_number: 311-10KJRCT-ND; Footprint Path: Y:\MIS_DATABASE\Library\ALTIUM_TOOL\PCB_FOOTPRINTS\Altium_Footprint_Lib.PcbLib; Height: 0.40MM; Library Path: Y:\MIS_DATABASE\Library\ALTIUM_TOOL\SCHEMATICS_PARTS\MS_DISCRETE_Library.schlib; Mfr_name: YAGEO AMERICA; Mfr_part_number: RC0402JR-0710KL; Mistral Part No: 110011060021-R; Package: 0402; Part_type: RESISTORS\FIXED; Project: HSE; RoHS: RoHS; Temperature: -55°C+155°C; Tolerance: 5%; Voltage: NA; Wattage: 1/16W; Weight: 0.65mg; Datasheet: Y:\MIS_DATABASE\DATASHEETS\RESISTORS\RCXXXXL-SER_MAR18.PDF
R3866 R3867 = RESISTOR: RES 2.2K 1/10W 5% 0402; Chkd/date: SHREESHAIL/210406; Crtd /date: GEETHA/200406; Custom_Duty: 15%; Customs_HS_Code: 85332119; Distributor_name: DIGIKEY; Distributor_part_number: P2.2KJCT-ND; Footprint Path: Y:\MIS_DATABASE\Library\ALTIUM_TOOL\PCB_FOOTPRINTS\Altium_Footprint_Lib.PcbLib; Height: 0.40MM; Library Path: Y:\MIS_DATABASE\Library\ALTIUM_TOOL\SCHEMATICS_PARTS\MS_DISCRETE_Library.schlib; Mfr_name: PANASONIC-ECG; Mfr_part_number: ERJ-2GEJ222X; Mistral Part No: 110009030429-R; Package: 0402; Part_type: RESISTORS\FIXED; Project: RED EYE; RoHS: RoHS; Temperature: -55°C+155°C; Tolerance: 5%; Voltage: NA; Wattage: 1/10W; Weight: 0.8mg; Datasheet: Y:\MIS_DATABASE\DATASHEETS\RESISTORS\PAN-ERJSER_NOV17.PDF
R3874 R3875 = RESISTOR: RES 1K 1/10W 1% 0402; Chkd/date: VASANTHA/281216; Crtd /date: MAZHAR/150506; Custom_Duty: 15%; Customs_HS_Code: 85332119; Distributor_name: DIGIKEY; Distributor_part_number: P1.00KLCT-ND; Footprint Path: Y:\MIS_DATABASE\Library\ALTIUM_TOOL\PCB_FOOTPRINTS\Altium_Footprint_Lib.PcbLib; Height: 0.40MM; Library Path: Y:\MIS_DATABASE\Library\ALTIUM_TOOL\SCHEMATICS_PARTS\MS_DISCRETE_Library.schlib; Mfr_name: PANASONIC-ECG; Mfr_part_number: ERJ-2RKF1001X; Mistral Part No: 110009030411-R; Package: 0402; Part_type: RESISTORS\FIXED; Project: VOCERA; RoHS: RoHS; Temperature: -55°C+155°C; Tolerance: 1%; Voltage: NA; Wattage: 1/10W; Weight: 0.8mg; Datasheet: Y:\MIS_DATABASE\DATASHEETS\RESISTORS\PAN-ERJSER_NOV17.PDF
U39 = SN74LVC1G08DBVRE4_SOT23-5: IC SINGLE 2-INPUT POSITIVE AND GATE SOT23-5; Automotive Alternate_mfr_name: TEXAS INSTRUMENTS; Automotive Alternate_mfr_part_number: SN74LVC1G08QDBVRQ1; Chkd/date: SUHAS/221010; Crtd /date: USMAN/151008; Custom_Duty: 15%; Customs_HS_Code: 85423100; Distributor_name: DIGIKEY; Distributor_part_number: SN74LVC1G08DBVRE4-ND; Height: 1.45MM; Mfr_name: TEXAS INSTRUMENTS; Mistral Part No: 141009060026-R; Part_type: ICS\DIGITAL\GATES; Project: KHAN_MAIN; RoHS: Sb/ Br FREE; Temperature: -40°C+85°C; Datasheet: Y:\MIS_DATABASE\DATASHEETS\ICS\DIGITAL\GATES\SN74LVC1G08.PDF
U90 = TMUX154EDGSR_VSSOP10: IC ESD PROTECTED 2-CH 2:1 SWITCH WITH POWERED-OFF PROTECTION VSSOP10; Chkd/date: MANIRAJA/040918; Crtd /date: MANIRAJA/040918; Custom_Duty: 15%; Customs_HS_Code: 85423100; Distributor_name: DIGIKEY; Distributor_part_number: 296-48347-1-ND; Footprint Path: Y:\MIS_DATABASE\Library\ALTIUM_TOOL\PCB_FOOTPRINTS\Altium_Footprint_Lib.PcbLib; Height: 1.10MM; Library Path: Y:\MIS_DATABASE\Library\ALTIUM_TOOL\SCHEMATICS_PARTS\MS_ANALOG-APPLICATION_Library.schlib; Mfr_name: TEXAS INSTRUMENTS; Mistral Part No: 140118090001-R; Package: VSSOP10; Part_type: ICS\ANALOG\SWITCH; Project: DLRL_DFP_ATRUC CARD; RoHS: RoHS; Temperature: -40°C+85°C; Tolerance: NA; Voltage: NA; Wattage: NA; Weight: NA; Datasheet: Y:\MIS_DATABASE\DATASHEETS\ICS\ANALOG\TMUX154EXXX.PDF
C332 = CAP: CAP CERAMIC 10uF 16V 20% X6S 0603; Chkd/date: VASANTHA/170117; Crtd /date: VASANTHA/170117; Custom_Duty: 15%; Customs_HS_Code: 85322990; Distributor_name: DIGIKEY; Distributor_part_number: 490-7198-1-ND; Footprint Path: Y:\MIS_DATABASE\Library\ALTIUM_TOOL\PCB_FOOTPRINTS\Altium_Footprint_Lib.PcbLib; Height: 0.90MM; Library Path: Y:\MIS_DATABASE\Library\ALTIUM_TOOL\SCHEMATICS_PARTS\MS_DISCRETE_Library.schlib; Mfr_name: MURATA; Mfr_part_number: GRM188C81C106MA73D; Mistral Part No: 120017010004-R; Package: 0603; Part_type: CAPACITORS\CERAMIC; Project: TRMM_SMART-M_PS; RoHS: RoHS; Temperature: -55°C+105°C; Tolerance: 20%; Voltage: 16V; Wattage: NA; Weight: 6.3mg; Datasheet: Y:\MIS_DATABASE\DATASHEETS\CAPACITORS\MURATA-GXX-SER_NOV17.PDF
J15 = CON_EDGE_180_HSEC8-180: CON EDGE PCIE FINGERS 180POS 0.80MM PITCH MALE RT SMD; Chkd/date: ALVY/250321; Crtd /date: MANIRAJA/250321; Custom_Duty: NA; Customs_HS_Code: NA; Distributor_name: NA; Distributor_part_number: NA; Footprint Path: Y:\MIS_DATABASE\Library\ALTIUM_TOOL\PCB_FOOTPRINTS\Altium_Footprint_Lib.PcbLib; Height: NA; Library Path: Y:\MIS_DATABASE\Library\ALTIUM_TOOL\SCHEMATICS_PARTS\MS_CONNECTOR_Library.schlib; Mfr_name: SAMTEC; Mfr_part_number: HSEC8-180 EDGE CONNECTOR; Mistral Part No: NA; Package: SMD; Part_type: CONNECTOR\EDGE; Project: TI_AM263XX_CC; RoHS: NA; Temperature: NA; Tolerance: NA; Voltage: NA; Wattage: NA; Weight: NA; Datasheet: NA
J16-J19 = HEADER_2X1: CON HDR 2X1 2.54MM PITCH ST TH; Chkd/date: VASANTHA/060117; Crtd /date: MAZHAR/280405; Custom_Duty: 24%; Customs_HS_Code: 85369090; Distributor_name: DIGIKEY; Distributor_part_number: WM4000-ND; Footprint Path: Y:\MIS_DATABASE\Library\ALTIUM_TOOL\PCB_FOOTPRINTS\Altium_Footprint_Lib.PcbLib; Height: 10.79MM; Library Path: Y:\MIS_DATABASE\Library\ALTIUM_TOOL\SCHEMATICS_PARTS\MS_CONNECTOR_Library.schlib; Mfr_name: MOLEX; Mfr_part_number: 22-03-2021; Mistral Part No: 150009030246-R; Package: THRU-HOLE; Part_type: CONNECTOR\HEADERS; Project: FPGA EXTENDER CARD; RoHS: RoHS; Temperature: -0°C+75°C; Tolerance: NA; Voltage: NA; Wattage: NA; Weight: 139gm; Datasheet: Y:\MIS_DATABASE\DATASHEETS\CONNECTORS\HEADER_X4030.PDF
R417 = RESISTOR: RES 9.1K 1/16W 1% 0402; Chkd/date: VASANTHA/280616; Crtd /date: VASANTHA/280616; Custom_Duty: 15%; Customs_HS_Code: 85332119; Distributor_name: DIGIKEY; Distributor_part_number: 311-9.10KLRCT-ND; Footprint Path: Y:\MIS_DATABASE\Library\ALTIUM_TOOL\PCB_FOOTPRINTS\Altium_Footprint_Lib.PcbLib; Height: 0.40MM; Library Path: Y:\MIS_DATABASE\Library\ALTIUM_TOOL\SCHEMATICS_PARTS\MS_DISCRETE_Library.schlib; Mfr_name: YAGEO AMERICA; Mfr_part_number: RC0402FR-079K1L; Mistral Part No: 110016060010-R; Package: 0402; Part_type: RESISTORS\FIXED; Project: TMDXCSKCC; RoHS: RoHS; Temperature: -55°C+155°C; Tolerance: 1%; Voltage: NA; Wattage: 1/16W; Weight: 0.65mg; Datasheet: Y:\MIS_DATABASE\DATASHEETS\RESISTORS\RCXXXXL-SER_MAR18.PDF
R418 = RESISTOR: RES 11K 1/16W 1% 0402; Chkd/date: VASANTHA/251115; Crtd /date: VASANTHA/251115; Custom_Duty: 15%; Customs_HS_Code: 85332119; Distributor_name: DIGIKEY; Distributor_part_number: 311-11.0KLRCT-ND; Footprint Path: Y:\MIS_DATABASE\Library\ALTIUM_TOOL\PCB_FOOTPRINTS\Altium_Footprint_Lib.PcbLib; Height: 0.40MM; Library Path: Y:\MIS_DATABASE\Library\ALTIUM_TOOL\SCHEMATICS_PARTS\MS_DISCRETE_Library.schlib; Mfr_name: YAGEO AMERICA; Mfr_part_number: RC0402FR-0711KL; Mistral Part No: 110015110012-R; Package: 0402; Part_type: RESISTORS\FIXED; Project: TI_VLAN_SWITCH; RoHS: RoHS; Temperature: -55°C+155°C; Tolerance: 1%; Voltage: NA; Wattage: 1/16W; Weight: 0.65mg; Datasheet: Y:\MIS_DATABASE\DATASHEETS\RESISTORS\RCXXXXL-SER_MAR18.PDF
U74 U75 = TMUX1136_USON10: IC 5V LOW-LEAKAGE-CURRENT 2:1 2-CHANNEL PRECISION ANALOG SWITCH USON10; Chkd/date: MANIRAJA/291121; Crtd /date: ALVY/291121; Custom_Duty: 15%; Customs_HS_Code: 85423100; Distributor_name: DIGIKEY; Distributor_part_number: 296-TMUX1136DQARCT-ND; Footprint Path: Y:\MIS_DATABASE\Library\ALTIUM_TOOL\PCB_FOOTPRINTS\Altium_Footprint_Lib.PcbLib; Height: 0.55MM; Library Path: Y:\MIS_DATABASE\Library\ALTIUM_TOOL\SCHEMATICS_PARTS\MS_ANALOG-APPLICATION_Library.schlib; Mfr_name: TEXAS INSTRUMENTS; Mistral Part No: 140121110003-R; Package: USON10; Part_type: ICS\ANALOG\SWITCH; Project: TI_AM263x_CC_BRD; RoHS: RoHS; Temperature: -40°C+125°C; Tolerance: NA; Voltage: NA; Wattage: NA; Weight: 4.3mg; Datasheet: Y:\MIS_DATABASE\DATASHEETS\ICS\ANALOG\TMUX1136.PDF

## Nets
DGND: C101.2 C102.2 C103.2 C104.2 C105.2 C106.2 C107.2 C108.2 C109.2 C110.2 C111.2 C112.2 C113.2 C114.2 C115.2 C116.2 C117.2 C118.2 C119.2 C120.2 C121.2 C122.2 C123.2 C124.2 C125.2 C126.2 C127.2 C128.2 C129.2 C130.2 C131.2 C132.2 C133.2 C134.2 C135.2 C136.2 C137.2 C138.2 C139.2 C140.2 C141.2 C142.2 C143.2 C144.2 C145.2 C146.2 C147.2 C148.2 C149.2 C150.2 C151.2 C152.2 C153.2 C154.2 C155.2 C156.2 C220.2 C221.2 C222.2 C225.2 C226.2 C329.2 C330.1 C331.2 C332.2 C333.2 C334.2 C3746.2 J8.1 J8.5 J8.8 J8.15 J8.16 J8.17 J8.18 J8.21 J8.24 J8.31 J8.32 J8.33 J8.34 J8.41 J8.SH1 J8.SH2 J8.SH3 J8.SH4 J15.7 J15.10 J15.13 J15.16 J15.19 J15.22 J15.29 J15.32 J15.35 J15.38 J15.46 J15.47 J15.65 J15.83 J15.97 J15.111 J15.135 J15.157 J15.179 J16.2 J17.2 J18.2 J19.2 R63.2 R82.2 R264.1 R266.1 R414.2 R415.2 R416.2 R418.2 R3870.1 R3871.1 R3874.2 R3875.2 U1.A1(VSS) U1.A18(VSS) U1.E5(VSS) U1.E6(VSS) U1.E7(VSS) U1.E8(VSS) U1.E10(VSS) U1.E12(VSS) U1.E13(VSS) U1.E14(VSS) U1.F5(VSS) U1.F6(VSS) U1.F7(VSS) U1.F8(VSS) U1.F10(VSS) U1.F12(VSS) U1.F13(VSS) U1.F14(VSS) U1.G7(VSS) U1.G8(VSS) U1.G9(VSS) U1.G10(VSS) U1.G11(VSS) U1.G12(VSS) U1.H5(VSS) U1.H6(VSS) U1.H7(VSS) U1.H8(VSS) U1.H9(VSS) U1.H10(VSS) U1.H11(VSS) U1.H12(VSS) U1.H13(VSS) U1.H14(VSS) U1.J5(VSS) U1.J6(VSS) U1.J7(VSS) U1.J8(VSS) U1.J9(VSS) U1.J10(VSS) U1.J11(VSS) U1.J12(VSS) U1.J13(VSS) U1.J14(VSS) U1.K7(VSS) U1.K8(VSS) U1.K9(VSS) U1.K10(VSS) U1.K11(VSS) U1.K12(VSS) U1.L5(VSS) U1.L6(VSS) U1.L7(VSS) U1.L8(VSS) U1.L9(VSS) U1.L10(VSS) U1.L11(VSS) U1.L12(VSS) U1.L13(VSS) U1.L14(VSS) U1.M5(VSS) U1.M6(VSS) U1.M7(VSS) U1.M8(VSS) U1.M9(VSS) U1.M10(VSS) U1.M11(VSS) U1.M12(VSS) U1.M13(VSS) U1.M14(VSS) U1.N7(VSS) U1.N8(VSS) U1.N9(VSS) U1.N10(VSS) U1.N11(VSS) U1.N12(VSS) U1.P5(VSS) U1.P6(VSSA) U1.P8(VSSA) U1.P10(VSSA) U1.P12(VSSA) U1.P13(VSS) U1.P14(VSS) U1.R5(VSSA) U1.R13(VSSA) U1.T2(VSS) U1.V1(VSSA) U1.V18(VSSA) U39.3(GND) U74.3(GND) U75.3(GND) U90.5(GND) ; also on sheet 1 2 3 4 9 10 11 12 13 14 15 16 17 24 25 26 27 28 29 30 32 33
VCC_1V2: C102.1 C103.1 C110.1 C111.1 C112.1 C113.1 C114.1 C115.1 C116.1 C117.1 C118.1 C119.1 C120.1 C121.1 C122.1 C123.1 C124.1 C125.1 C126.1 C127.1 C128.1 C129.1 C130.1 C131.1 C132.1 C133.1 U1.D10(VDDAR2) U1.E9(VDD) U1.E11(VDD) U1.F9(VDD) U1.F11(VDD) U1.G5(VDD) U1.G6(VDD) U1.G13(VDD) U1.G14(VDD) U1.H3(VDDAR3) U1.J15(VDDAR1) U1.J16(VDD) U1.K5(VDD) U1.K6(VDD) U1.K13(VDD) U1.K14(VDD) U1.N5(VDD) U1.N6(VDD) U1.N13(VDD) U1.N14(VDD) U1.R9(VDD_F) ; also on sheet 1
VCC_5V0: J15.117 ; also on sheet 13
VDD_2V5: C220.1 C221.1 J8.4 J8.6 ; also on sheet 14 15
VDD_IO_3V3: C138.1 C139.1 C147.1 C148.1 C149.1 C150.1 C151.1 C152.1 C153.1 C154.1 C155.1 C156.1 FL1.1 U1.D8(VDDS33) U1.D12(VDDS33) U1.H4(VDDS33) U1.H15(VDDS33) U1.L15(VDDS33) U1.P4(VDDS33) U1.R15(VDDS33) ; also on sheet 1
VDDA1V8_OSC_PLL_F: C146.1 FL2.2 U1.R4(VDDA18_OSC_PLL)
VDDA3V3_F: C134.1 C135.1 C136.1 C137.1 FL1.2 U1.P7(VDDA33) U1.P9(VDDA33) U1.P11(VDDA33)
VDDA_IO_1V8: C140.1 C141.1 C142.1 C143.1 C144.1 C145.1 FL2.1 R467.1 U1.R6(VDDA18_LDO) U1.R8(VDDA18) U1.R11(VDDA18) ; also on sheet 16
VDDA_IO_3V3: C329.1 C330.2 U74.8(VDD) U75.8(VDD) ; also on sheet 2 16
VDDIO: C225.1 C226.1 J8.44 J8.46 ; also on sheet 14 15
VDDS_IO_1V8: C104.1 C105.1 C106.1 C107.1 C108.1 C109.1 U1.D6(VDDS18) U1.E15(VDDS18) U1.L4(VDDS18) U1.N15(VDDS18) U1.T3(VDDS18_LDO) ; also on sheet 9
1588_SFD: J8.38 ; also on sheet 27
ADC1_MUX_SEL: R414.1 U74.1(SEL1) U74.5(SEL2) ; also on sheet 12
ADC2_MUX_SEL: R415.1 U75.1(SEL1) U75.5(SEL2) ; also on sheet 12
ADC4_AIN0/ADC_CAL0/ADC_R0_AIN0: J15.25 U75.10(D1) ; also on sheet 16
ADC4_AIN1/ADC_CAL1/ADC_R0_AIN1: J15.27 U75.6(D2) ; also on sheet 16
ADC_CAL0/ADC_R0_AIN0: U75.9(S1B) ; also on sheet 2
ADC_CAL1/ADC_R0_AIN1: U75.7(S2B) ; also on sheet 2
ETH_EEPROM_A0: J8.47 R3875.1
ETH_EEPROM_A2: J8.37 R3874.1
EXT_VMON2: J8.2 ; also on sheet 30
GPIO_2/CLKOUT: J8.48
GPIO_ICSSM2_RST: R265.1 U39.1(A) ; also on sheet 12
HSEC_5V0: C332.1 C333.1 C334.1 J15.48 J15.84 J15.98 J15.112 J15.118 J15.158 J15.180 ; also on sheet 4
HSEC_ADC0_AIN0: U74.2(S1A) ; also on sheet 16
HSEC_ADC0_AIN0/DAC_OUT: J15.9 U74.10(D1) ; also on sheet 16
HSEC_ADC0_AIN1: U74.4(S2A) ; also on sheet 16
HSEC_ADC0_AIN1/DAC_OUT: J15.11 U74.6(D2) ; also on sheet 16
HSEC_ADC0_AIN2: J15.15 ; also on sheet 16
HSEC_ADC0_AIN3: J15.17 ; also on sheet 16
HSEC_ADC0_AIN4: J15.21 ; also on sheet 16
HSEC_ADC0_AIN5: J15.23 ; also on sheet 16
HSEC_ADC1_AIN0: J15.12 ; also on sheet 16
HSEC_ADC1_AIN1: J15.14 ; also on sheet 16
HSEC_ADC1_AIN2: J15.18 ; also on sheet 16
HSEC_ADC1_AIN3: J15.20 ; also on sheet 16
HSEC_ADC1_AIN4: J15.24 ; also on sheet 16
HSEC_ADC1_AIN5: J15.26 ; also on sheet 16
HSEC_ADC2_AIN0/ADC_R1_AIN0: J15.31 ; also on sheet 2
HSEC_ADC2_AIN1/ADC_R1_AIN1: J15.33 ; also on sheet 2
HSEC_ADC2_AIN2: J15.37 ; also on sheet 16
HSEC_ADC2_AIN3: J15.39 ; also on sheet 16
HSEC_ADC3_AIN0/ADC_R0_AIN2: J15.28 ; also on sheet 2
HSEC_ADC3_AIN1/ADC_R0_AIN3: J15.30 ; also on sheet 2
HSEC_ADC3_AIN2/ADC_R1_AIN2: J15.34 ; also on sheet 2
HSEC_ADC3_AIN3/ADC_R1_AIN3: J15.36 ; also on sheet 2
HSEC_ADC3_AIN4: J15.40 ; also on sheet 16
HSEC_ADC3_AIN5: J15.42 ; also on sheet 16
HSEC_ADC4_AIN0: U75.2(S1A) ; also on sheet 16
HSEC_ADC4_AIN1: U75.4(S2A) ; also on sheet 16
HSEC_ADC-VREFHI: C331.1 R417.2 R418.1 ; also on sheet 16
HSEC_DAC_OUT: R412.2 R413.2 ; also on sheet 16
HSEC_EPWM0_A: J15.49 ; also on sheet 27
HSEC_EPWM0_B: J15.51 ; also on sheet 27
HSEC_EPWM1_A: J15.53 ; also on sheet 27
HSEC_EPWM1_B: J15.55 ; also on sheet 27
HSEC_EPWM2_A: J15.50 ; also on sheet 27
HSEC_EPWM2_B: J15.52 ; also on sheet 27
HSEC_EPWM3_A/HSEC_MII1_CRS(RES0_PWMOUT0): J15.54 ; also on sheet 2
HSEC_EPWM3_B: J15.56 ; also on sheet 27
HSEC_EPWM4_A: J15.57 ; also on sheet 27
HSEC_EPWM4_B: J15.59 ; also on sheet 27
HSEC_EPWM5_A: J15.61 ; also on sheet 27
HSEC_EPWM5_B: J15.63 ; also on sheet 27
HSEC_EPWM6_A: J15.58 ; also on sheet 27
HSEC_EPWM6_B: J15.60 ; also on sheet 27
HSEC_EPWM7_A: J15.62 ; also on sheet 27
HSEC_EPWM7_B: J15.64 ; also on sheet 27
HSEC_EPWM11_A: J15.86 ; also on sheet 27
HSEC_EPWM13_A: J15.153 ; also on sheet 27
HSEC_EPWM13_B: J15.154 ; also on sheet 27
HSEC_EPWM21_A: J15.89 ; also on sheet 15
HSEC_EPWM21_B: J15.90 ; also on sheet 15
HSEC_EQEP0_A: J15.102 ; also on sheet 26
HSEC_EQEP0_B: J15.100 ; also on sheet 26
HSEC_EQEP0_INDEX: J15.106 ; also on sheet 26
HSEC_EQEP0_STROBE: J15.104 ; also on sheet 26
HSEC_EQEP2_A: J15.92 ; also on sheet 26
HSEC_EQEP2_B: J15.93 ; also on sheet 26
HSEC_EQEP2_INDEX: J15.94 ; also on sheet 26
HSEC_EQEP2_STROBE: J15.95 ; also on sheet 26
HSEC_EXT_REFCLK0: J15.74 ; also on sheet 27
HSEC_GPIO: J15.96 ; also on sheet 12
HSEC_I2C1_SCL: J15.87 ; also on sheet 26
HSEC_I2C1_SDA: J15.85 ; also on sheet 26
HSEC_MCAN5_RX: J15.80 ; also on sheet 13
HSEC_MCAN5_TX: J15.82 ; also on sheet 13
HSEC_MII0_COL: J15.110 ; also on sheet 32
HSEC_MII0_CRS: J15.121 ; also on sheet 32
HSEC_MII0_RXCLK: J15.123 ; also on sheet 32
HSEC_MII0_RXD0: J15.125 ; also on sheet 32
HSEC_MII0_RXD1: J15.126 ; also on sheet 32
HSEC_MII0_RXD2: J15.127 ; also on sheet 32
HSEC_MII0_RXD3: J15.128 ; also on sheet 32
HSEC_MII0_RXDV: J15.124 ; also on sheet 32
HSEC_MII0_RXER: J15.108 ; also on sheet 32
HSEC_MII0_RXLINK: J15.122 ; also on sheet 32
HSEC_MII0_TXCLK: J15.129 ; also on sheet 32
HSEC_MII0_TXD0: J15.131 ; also on sheet 32
HSEC_MII0_TXD1: J15.132 ; also on sheet 32
HSEC_MII0_TXD2: J15.133 ; also on sheet 32
HSEC_MII0_TXD3: J15.134 ; also on sheet 32
HSEC_MII0_TXEN: J15.130 ; also on sheet 32
HSEC_MII1_COL: J15.138 ; also on sheet 32
HSEC_MII1_CRS(RES0_PWMOUT0): J15.139 ; also on sheet 2 32
HSEC_MII1_RXCLK: J15.141 ; also on sheet 32
HSEC_MII1_RXD0: J15.143 ; also on sheet 32
HSEC_MII1_RXD1: J15.144 ; also on sheet 32
HSEC_MII1_RXD2: J15.145 ; also on sheet 32
HSEC_MII1_RXD3: J15.146 ; also on sheet 32
HSEC_MII1_RXDV: J15.142 ; also on sheet 32
HSEC_MII1_RXER: J15.137 ; also on sheet 32
HSEC_MII1_RXLINK: J15.140 ; also on sheet 32
HSEC_MII1_TXCLK: J15.147 ; also on sheet 32
HSEC_MII1_TXD0: J15.149 ; also on sheet 32
HSEC_MII1_TXD1: J15.150 ; also on sheet 32
HSEC_MII1_TXD2: J15.151 ; also on sheet 32
HSEC_MII1_TXD3: J15.152 ; also on sheet 32
HSEC_MII1_TXEN: J15.148 ; also on sheet 32
HSEC_MMC0_CLK: J15.163 ; also on sheet 25
HSEC_MMC0_CMD: J15.164 ; also on sheet 25
HSEC_MMC0_D0: J15.165 ; also on sheet 25
HSEC_MMC0_D1: J15.166 ; also on sheet 25
HSEC_MMC0_D2: J15.167 ; also on sheet 25
HSEC_MMC0_D3: J15.168 ; also on sheet 25
HSEC_MMC0_SDCD: J15.170 ; also on sheet 25
HSEC_MMC0_WP: J15.169 ; also on sheet 25
HSEC_SDFM0_CLK0: J15.72 ; also on sheet 27
HSEC_SDFM0_CLK1: J15.101 R422.2 ; also on sheet 27
HSEC_SDFM0_CLK2: J15.105 ; also on sheet 27
HSEC_SDFM0_CLK3: J15.109 ; also on sheet 27
HSEC_SDFM0_D0: J15.91 ; also on sheet 27
HSEC_SDFM0_D1: J15.99 R421.2 ; also on sheet 27
HSEC_SDFM0_D2: J15.103 ; also on sheet 27
HSEC_SDFM0_D3: J15.107 ; also on sheet 27
HSEC_SPI0_CLK: J15.71 ; also on sheet 26
HSEC_SPI0_CS0: J15.73 ; also on sheet 26
HSEC_SPI0_D0: J15.67 ; also on sheet 26
HSEC_SPI0_D1: J15.69 ; also on sheet 26
HSEC_SPI1_CLK: J15.79 ; also on sheet 30
HSEC_SPI1_CS0: J15.81 ; also on sheet 30
HSEC_SPI1_D0: J15.75 ; also on sheet 30
HSEC_SPI1_D1: J15.77 ; also on sheet 30
HSEC_TCK: J15.5 ; also on sheet 27
HSEC_TDI: J15.8 ; also on sheet 27
HSEC_TDO: J15.6 ; also on sheet 27
HSEC_TMS: J15.3 ; also on sheet 27
HSEC_UART1_RXD: J15.76 ; also on sheet 9
HSEC_UART1_TXD: J15.78 ; also on sheet 9
HSEC_VREF_3V3: J15.45 R417.1
I2C0_SCL: J8.40 ; also on sheet 26
I2C0_SDA: J8.42 ; also on sheet 26
ICSSM2_PWDN/INTn: J8.10 R267.1 ; also on sheet 27
ICSSM2_RESETn: J8.12 R266.2 U39.4(Y)
ICSSM_BRD_CONN_DET: J8.36 R263.1
ICSSM_INH: J8.26 R264.2
ICSSM_MII0/MII1_COL_ADD: J8.14 ; also on sheet 33
ICSSM_MII0/MII1_CRS_ADD: J8.30 ; also on sheet 33
ICSSM_MII0/MII1_RXCLK_ADD: J8.19 ; also on sheet 33
ICSSM_MII0/MII1_RXD0_ADD: J8.23 ; also on sheet 33
ICSSM_MII0/MII1_RXD1_ADD: J8.25 ; also on sheet 33
ICSSM_MII0/MII1_RXD2_ADD: J8.27 ; also on sheet 33
ICSSM_MII0/MII1_RXD3_ADD: J8.29 ; also on sheet 33
ICSSM_MII0/MII1_RXDV_ADD: J8.45 ; also on sheet 33
ICSSM_MII0/MII1_RXER_ADD: J8.39 ; also on sheet 33
ICSSM_MII0/MII1_RXLINK_ADD: J8.43 ; also on sheet 33
ICSSM_MII0/MII1_TXCLK_ADD: J8.3 ; also on sheet 33
ICSSM_MII0/MII1_TXD0_ADD: J8.7 ; also on sheet 33
ICSSM_MII0/MII1_TXD1_ADD: J8.9 ; also on sheet 33
ICSSM_MII0/MII1_TXD2_ADD: J8.11 ; also on sheet 33
ICSSM_MII0/MII1_TXD3_ADD: J8.13 ; also on sheet 33
ICSSM_MII0/MII1_TXEN_ADD: J8.35 ; also on sheet 33
MDIO0_MDC: U90.3(A1) ; also on sheet 12 15
MDIO0_MDIO: U90.7(B1) ; also on sheet 12 15
MDIO/MDC_MUX_SEL2: R3871.2 U90.1(SEL) ; also on sheet 12
PMIC_COMP1_IN+: J15.175 ; also on sheet 30
PMIC_COMP1_IN-: J15.177 ; also on sheet 30
PMIC_COMP2_IN+: J15.171 ; also on sheet 30
PMIC_COMP2_IN-: J15.173 ; also on sheet 30
PMIC_SAFE_OUT1: J15.113 ; also on sheet 30
PMIC_SAFE_OUT2: J15.178 ; also on sheet 27 30
PMIC_WKUP1: J15.114 ; also on sheet 30
PMIC_WKUP2: J15.172 ; also on sheet 13 30
PORZ: R419.1 U39.2(B) ; also on sheet 10 11 15 24 27
PR0_IEP0_EDC_SYNC_OUT0: J16.1 R420.1
PR0_IEP0_EDC_SYNC_OUT1: J18.1 R422.1
PR0_IEP0_EDIO_DATA_IN_OUT30: J17.1 R421.1
PR0_IEP0_EDIO_DATA_IN_OUT31: J19.1 R423.1
PR0_MDIO0_MDC: U90.2(A0) ; also on sheet 15
PR0_MDIO0_MDC_ADD: J8.20 R3867.2 U90.4(A)
PR0_MDIO0_MDIO: U90.8(B0) ; also on sheet 15
PR0_MDIO0_MDIO_ADD: J8.22 R3866.2 U90.6(B)
PR0_PRU1_GPIO0: R247.2 ; also on sheet 32
PR0_PRU1_GPIO1: R248.2 ; also on sheet 32
PR0_PRU1_GPIO2: R249.2 ; also on sheet 32
PR0_PRU1_GPIO3: R250.2 ; also on sheet 32
PR0_PRU1_GPIO4: R251.2 ; also on sheet 32
PR0_PRU1_GPIO5: R252.2 ; also on sheet 32
PR0_PRU1_GPIO6: R253.2 ; also on sheet 32
PR0_PRU1_GPIO8: R254.2 ; also on sheet 32
PR0_PRU1_GPIO9: R255.2 ; also on sheet 32
PR0_PRU1_GPIO10: R256.2 ; also on sheet 32
PR0_PRU1_GPIO11: R257.2 ; also on sheet 32
PR0_PRU1_GPIO12: R258.2 ; also on sheet 32
PR0_PRU1_GPIO13: R259.2 ; also on sheet 32
PR0_PRU1_GPIO14: R260.2 ; also on sheet 32
PR0_PRU1_GPIO15: R261.2 ; also on sheet 32
PR0_PRU1_GPIO16: R262.2 ; also on sheet 32
PR0_PRU1_GPIO18: J15.70 R423.2 R1652.2
PR0_PRU1_GPIO19: J15.68 R420.2 R1653.2
PR0_PRU1_REF_CLK: J8.28 ; also on sheet 9
RESETz_HSEC: J15.120 R419.2
RSVD_T4: R82.1 U1.T4(RSVD)
UART2_RXD_HSEC: J15.161 ; also on sheet 26
UART2_TXD_HSEC: J15.162 ; also on sheet 26
VPP_1V7: R63.1 R83.1 ; also on sheet 29
VPP_R: C101.1 R83.2 R467.2 TP86.1(TP) U1.N3(VPP)
VSYS_3V3_LDO1: C222.1 C3746.1 J15.119 R263.2 R265.2 R267.2 R3866.1 R3867.1 U39.5(VCC) U90.10(VCC) ; also on sheet 1 9 10 11 12 13 14 15 16 17 24 26 27 28 29 30 32 33
N33461336: J15.43 R416.1
N33933588: R412.1 U74.9(S1B)
N33933633: R413.1 U74.7(S2B)
N35805242: R247.1 U1.F18(PR0_PRU1_GPIO0)
N35805430: R255.1 U1.C18(PR0_PRU1_GPIO9)
N35805533: R248.1 U1.G16(PR0_PRU1_GPIO1)
N35805539: R249.1 U1.E17(PR0_PRU1_GPIO2)
N35805550: R250.1 U1.E18(PR0_PRU1_GPIO3)
N35805561: R251.1 U1.F16(PR0_PRU1_GPIO4)
N35805574: R252.1 U1.F15(PR0_PRU1_GPIO5)
N35805586: R253.1 U1.E16(PR0_PRU1_GPIO6)
N35805597: R254.1 U1.D18(PR0_PRU1_GPIO8)
N35805610: R256.1 U1.D17(PR0_PRU1_GPIO10)
N35805636: R257.1 U1.B18(PR0_PRU1_GPIO11)
N35805639: R258.1 U1.B17(PR0_PRU1_GPIO12)
N35805644: R259.1 U1.D16(PR0_PRU1_GPIO13)
N35805649: R260.1 U1.C17(PR0_PRU1_GPIO14)
N35805656: R261.1 U1.A17(PR0_PRU1_GPIO15)
N35805662: R262.1 U1.C16(PR0_PRU1_GPIO16)
N35805667: R1652.1 U1.C15(PR0_PRU1_GPIO18)
N35805672: R1653.1 U1.D15(PR0_PRU1_GPIO19)
N35842882: R3870.2 U90.9(~{EN})

Not connected (* = marked no-connect by the designer): J15 1* 2* 4* 41* 44* 66* 88* 115* 116* 136* 155* 156* 159* 160* 174* 176*

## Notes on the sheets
sheet 6
- HSEC Connector
- 3.3V to 1.8V
  divider
- SYNC TP
- SILK:
- SYNC0
- SILK:
- DIO30
- SILK:
- SYNC1
- SILK:
- DIO31
- CAD NOTE: Place the
  resistors close to SOC
  to minimize the stub
sheet 7
- PRU1 ICSS MII1 Ethernet
- CAD NOTE: Place the resistors close to SoC with minimum stub
- Note: Net/Signal on pin 48 is not supported on AM263P
- DF40GB-48DP-0.4V(58)
- Ethernet connector I2C Address - 0x52
- CAD NOTE: Add Silkscreen 'Ethernet Connector 0' next to J8 Connector
- RESET
- From IO Exp
- MDIO/MDC MUX FOR ADD-ON BOARD CONN
sheet 8
- SOC-POWER and GND
- CAD NOTE: PLACE A 0.1uF CAP  CLOSE
  AS POSSIBLE TO VPP PIN (N3).
- NOTE:
- VPP = 1.7V  FROM ANALDO OF SOC (Re-Programmed to 1.7V)
- MOUNT R467 & DEMOUNT R83
- MOUNT R83 & DEMOUNT R467
- VPP = 1.7V  FROM EXT LDO (U66)
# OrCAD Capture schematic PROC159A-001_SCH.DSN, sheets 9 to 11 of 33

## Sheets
9 23. CLOCKS AND LIN1: size C; title: CLOCKS AND LIN1
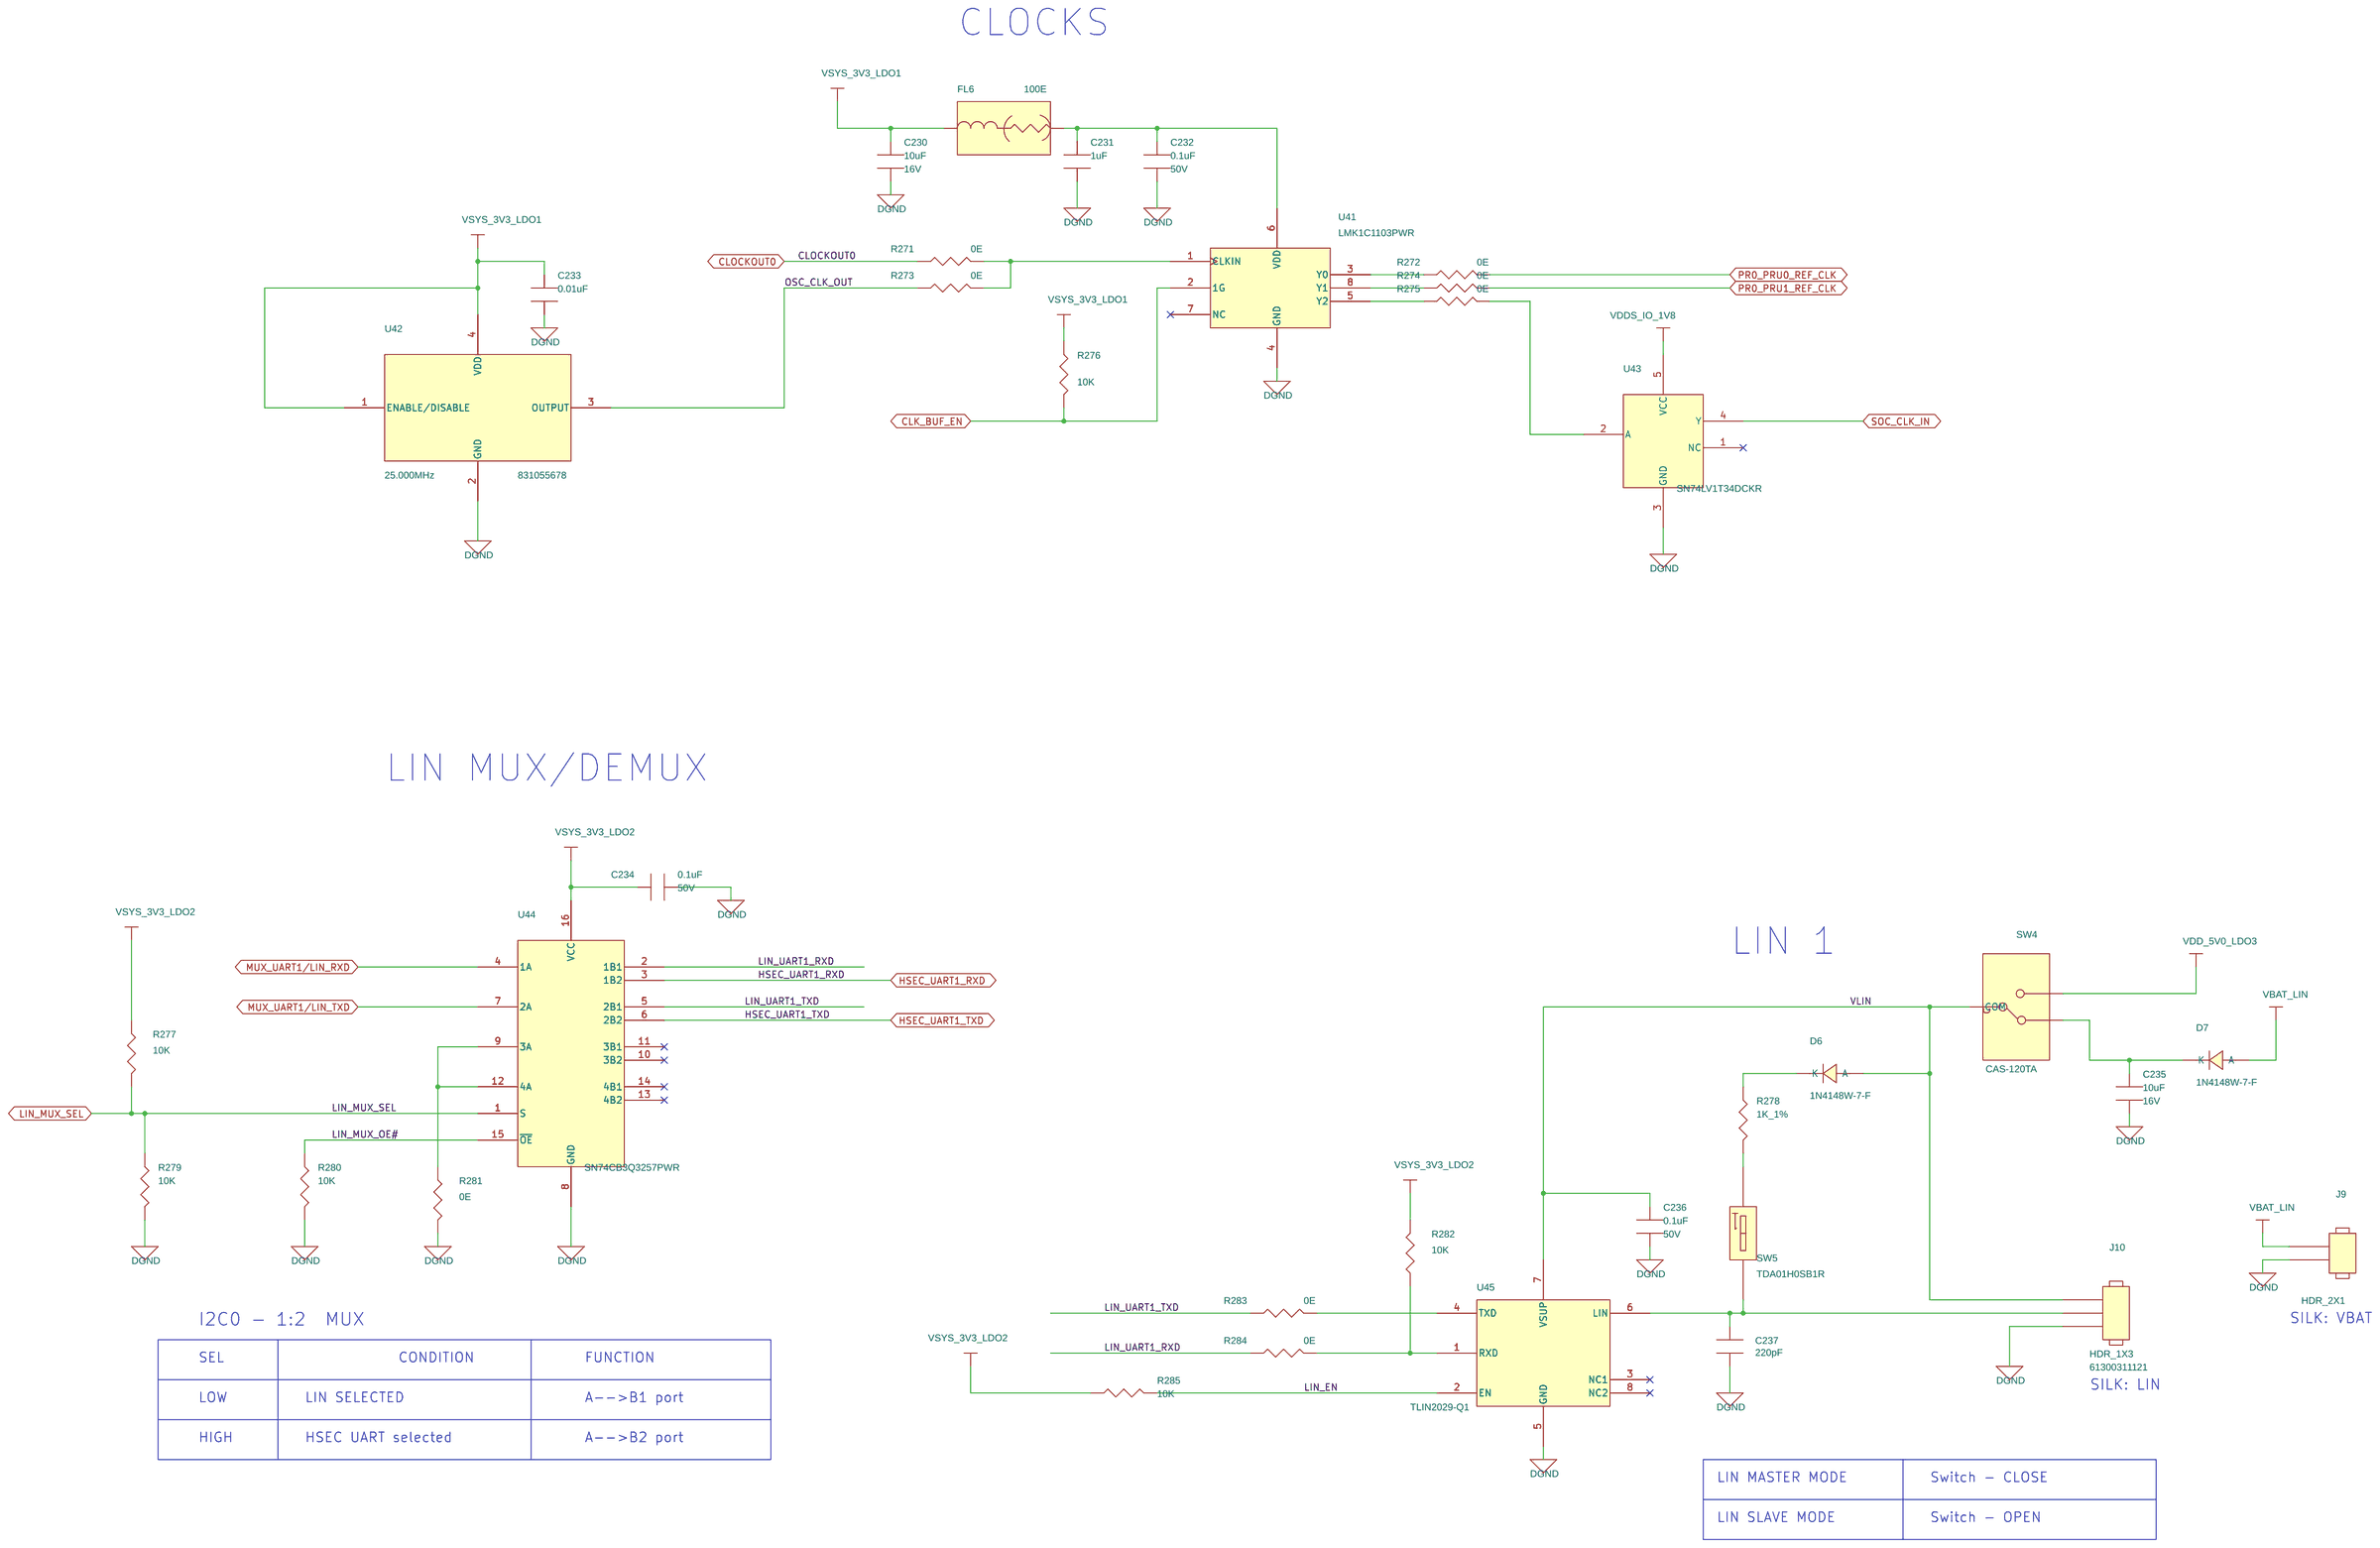
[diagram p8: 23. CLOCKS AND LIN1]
10 32. RESET SWITCHES: size C; title: RESET SWITCHES
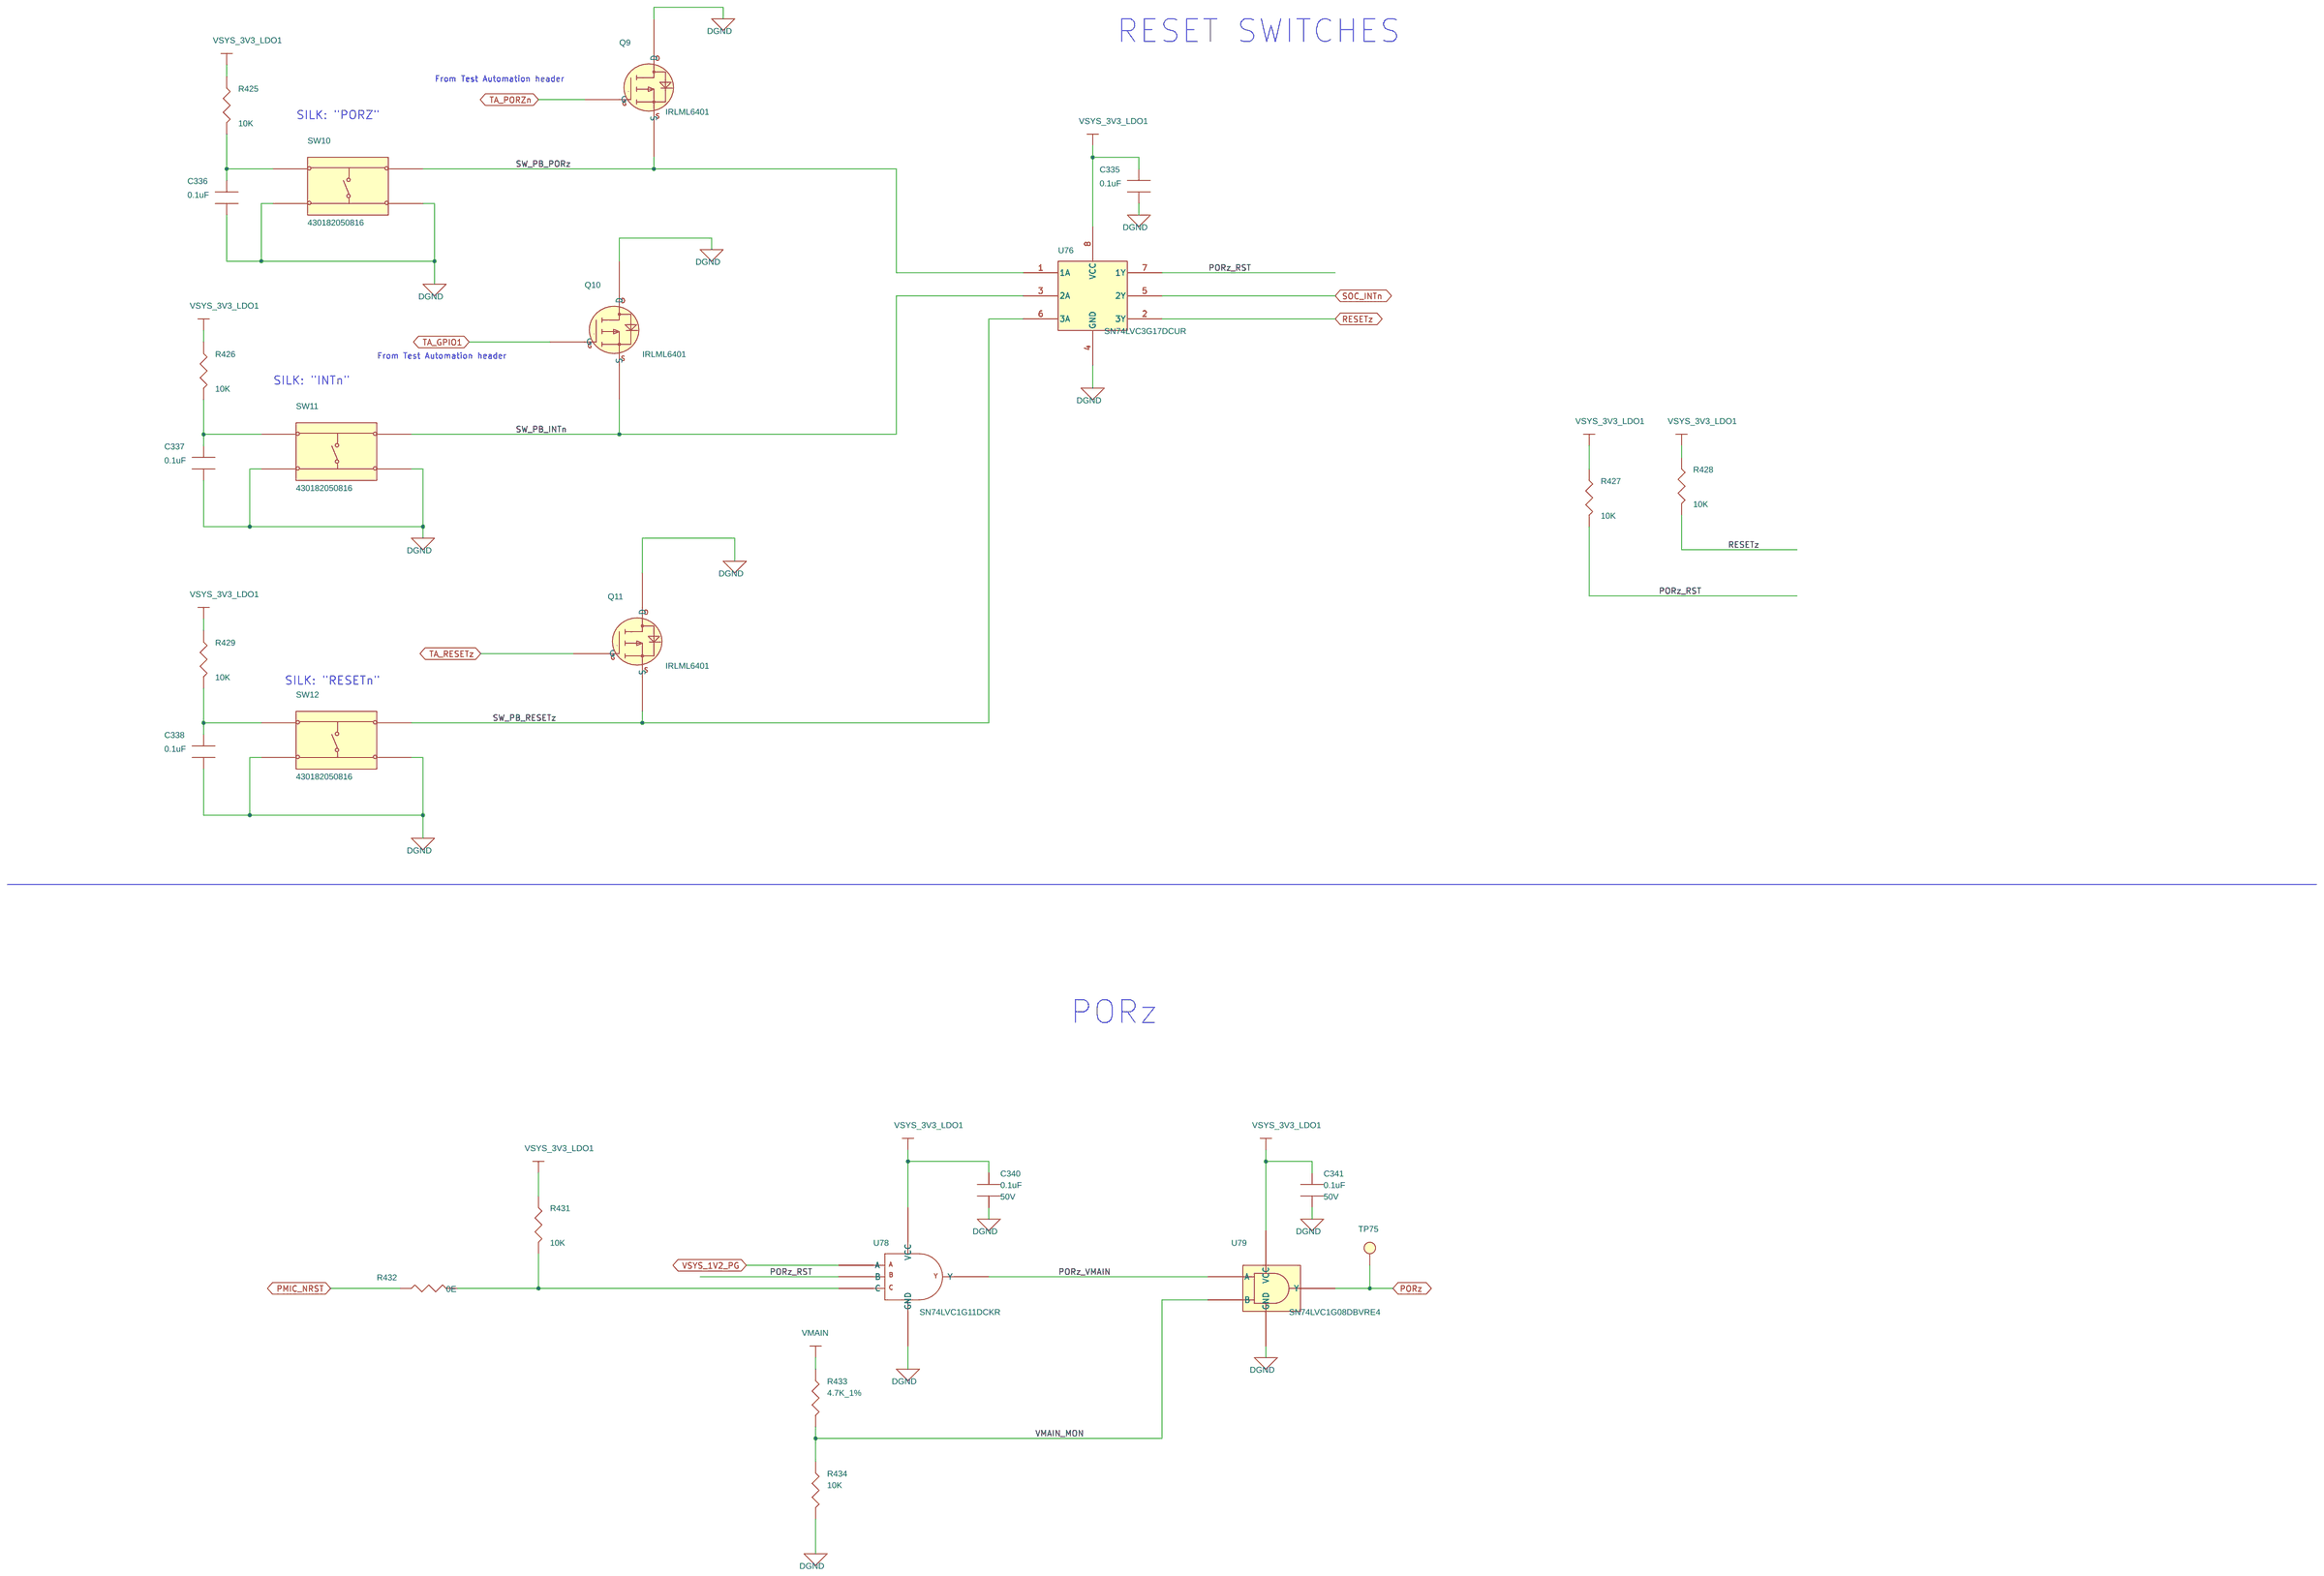
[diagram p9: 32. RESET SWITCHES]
11 25. BOOTMODE BUFFER AND SWITCH: size C; title: BOOTMODE BUFFER AND SWITCH

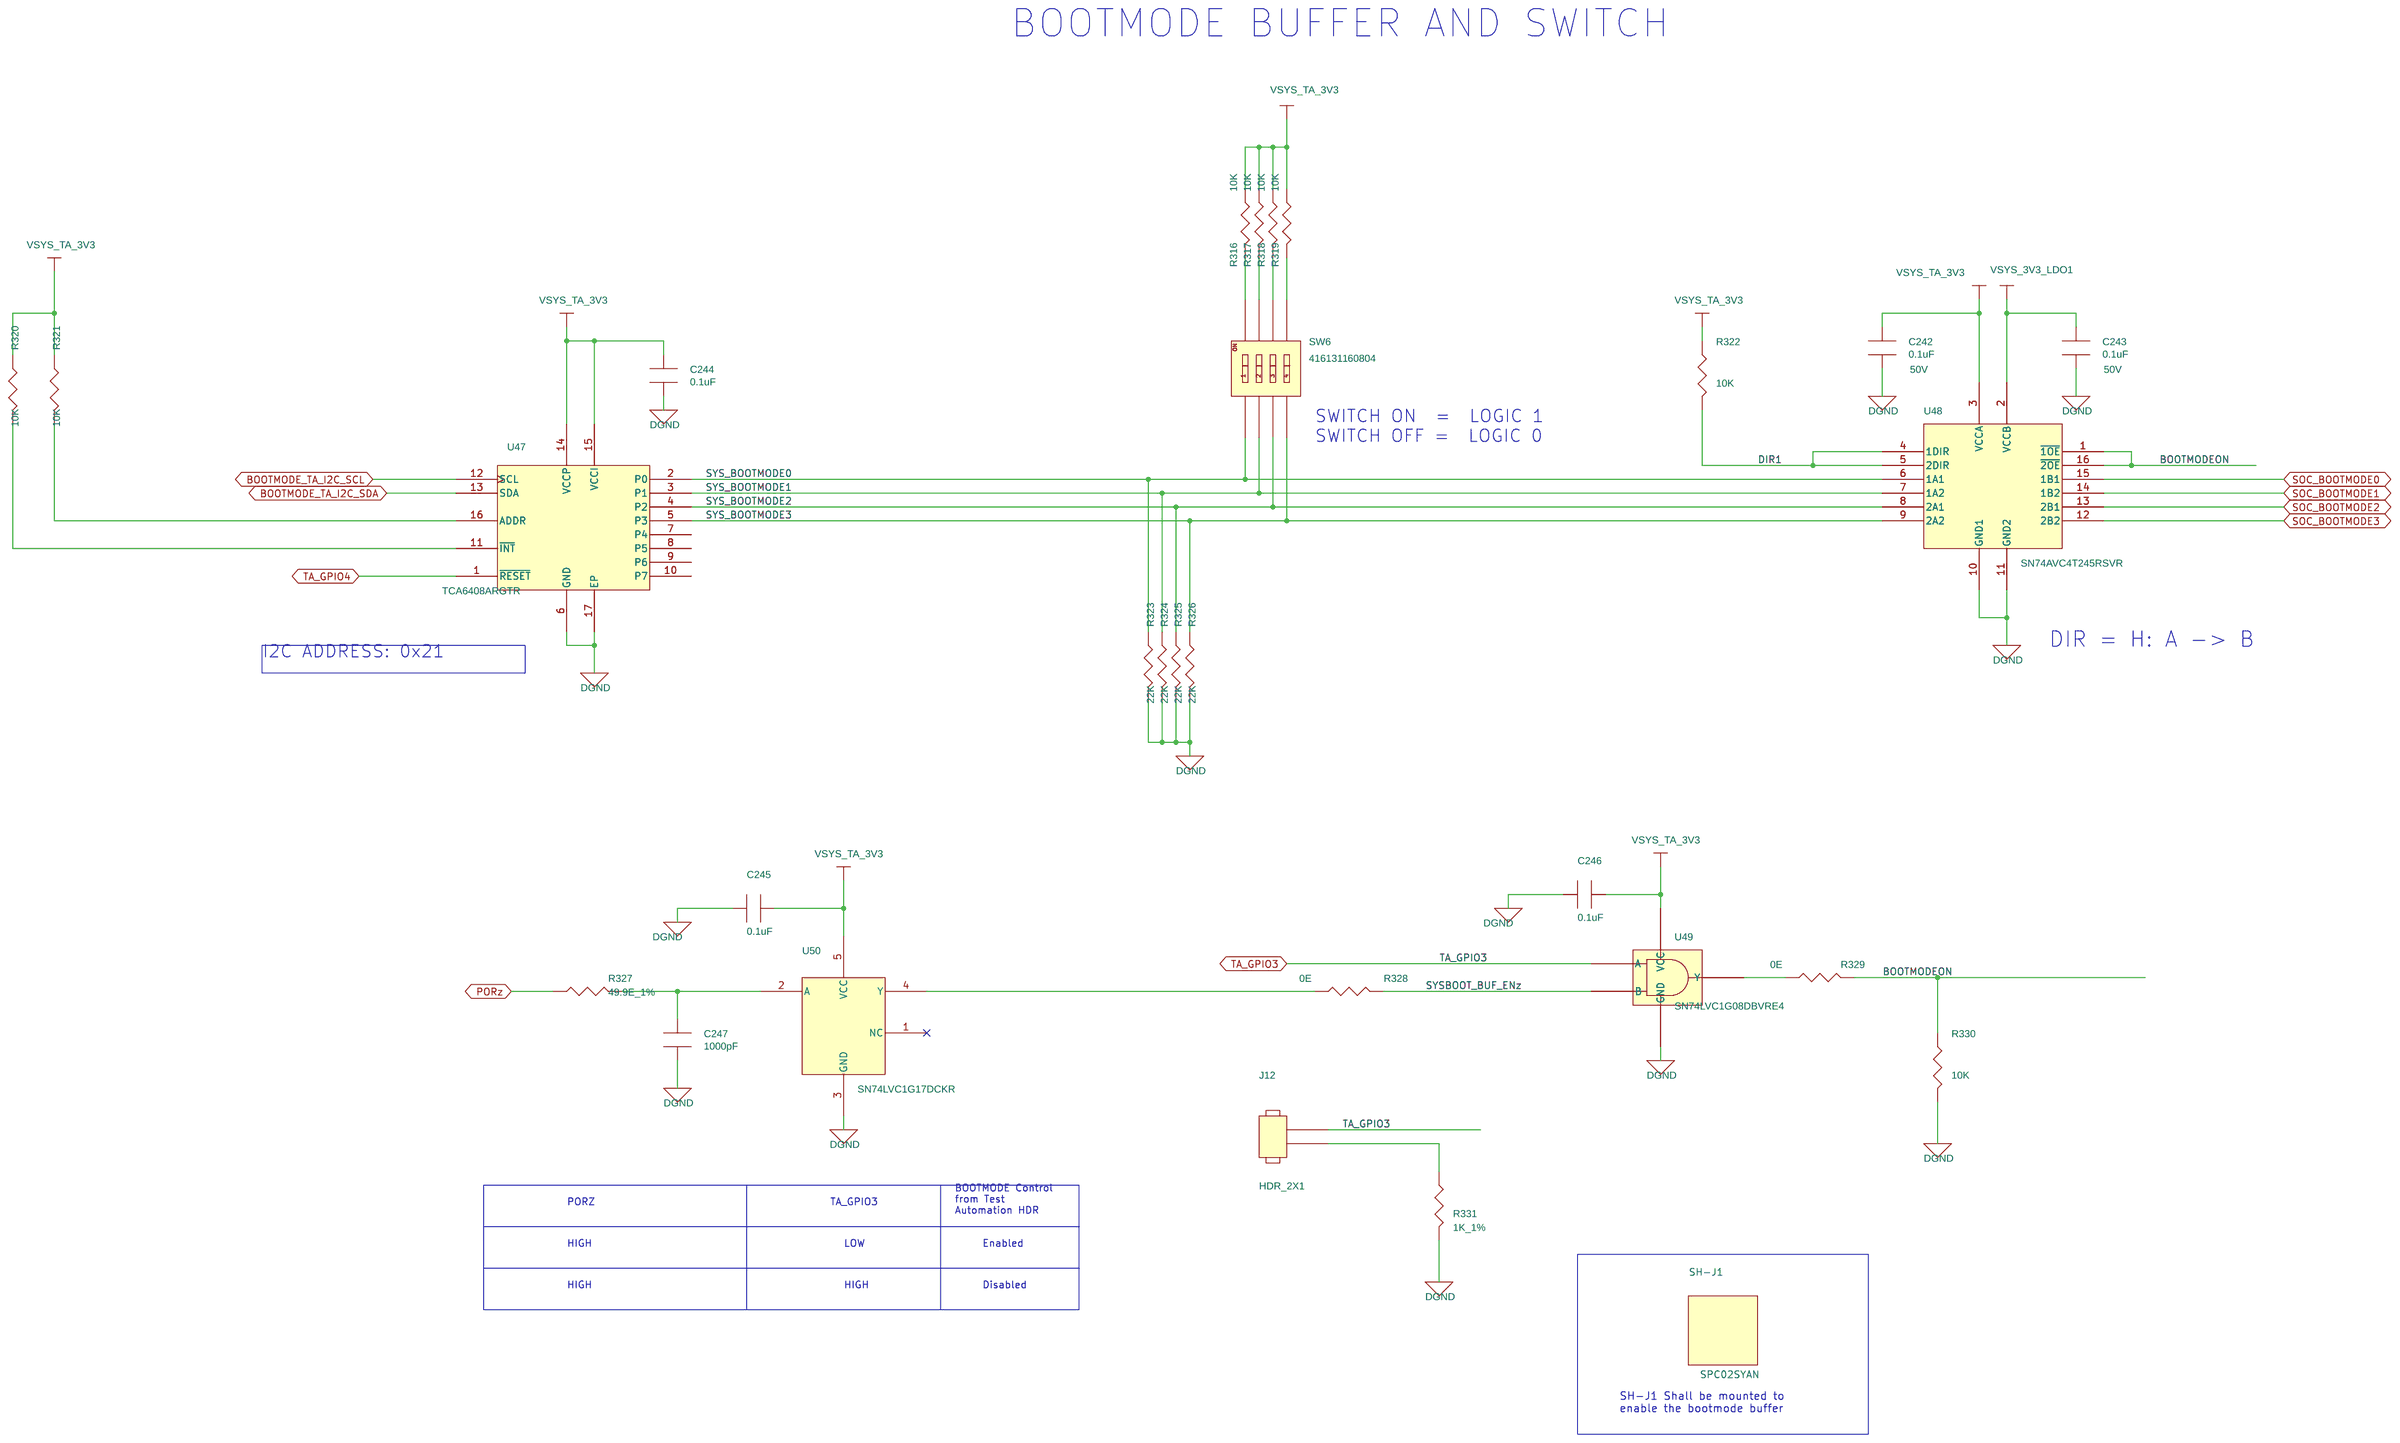
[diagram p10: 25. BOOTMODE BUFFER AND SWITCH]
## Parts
sheet 23. CLOCKS AND LIN1
C230  10uF  [CAP0603_1]
C231  1uF  [CAP0402_0-75]
C232  0.1uF  [CAP0402_0-75]
C233  0.01uF  [CAP0402_0-75]
C234  0.1uF  [CAP0402_0-75]
C235  10uF  [CAP0603_1]
C236  0.1uF  [CAP0402_0-75]
C237  220pF  [CAP0402_0-75]
D6  1N4148W-7-F  [DIO_SOD123_1-4]
D7  1N4148W-7-F  [DIO_SOD123_1-4]
FL6  100E  [EMIFIL_BLM18R_0603]
J9  HDR_2X1  [HDR_2X1_100_S_T]
J10  HDR_1X3  [HDR_1X3_100_S_T]
R271  0E  [RES0402_0-5]
R272  0E  [RES0402_0-5]
R273  0E  [RES0402_0-5]
R274  0E  [RES0402_0-5]
R275  0E  [RES0402_0-5]
R276  10K  [RES0402_0-5]
R277  10K  [RES0402_0-5]
R278  1K_1%  [RES0402_0-5]
R279  10K  [RES0402_0-5]
R280  10K  [RES0402_0-5]
R281  0E  [RES0402_0-5]
R282  10K  [RES0402_0-5]
R283  0E  [RES0402_0-5]
R284  0E  [RES0402_0-5]
R285  10K  [RES0402_0-5]
SW4  CAS-120TA  [SW3_CAS-120TA_215X100_SMD]
SW5  TDA01H0SB1R  [SW_TDA01H0S_240X90_SMD_2-3]
U41  LMK1C1103PWR  [TSSOP8_25-59_125X180_1-2]
U42  25.000MHz  [OSC4_ASEK_130X100_SMD_1-2]
U43  SN74LV1T34DCKR  [SC70-5_1-1]
U44  SN74CB3Q3257PWR  [TSSOP16_25-59_205X180]
U45  TLIN2029-Q1  [SOIC8_1-8]
sheet 25. BOOTMODE BUFFER AND SWITCH
C242  0.1uF  [CAP0402_0-75]
C243  0.1uF  [CAP0402_0-75]
C244  0.1uF  [CAP0402_0-75]
C245  0.1uF  [CAP0402_0-75]
C246  0.1uF  [CAP0402_0-75]
C247  1000pF  [CAP0402_0-75]
J12  HDR_2X1  [HDR_2X1_100_S_T]
R316  10K  [RES0402_0-5]
R317  10K  [RES0402_0-5]
R318  10K  [RES0402_0-5]
R319  10K  [RES0402_0-5]
R320  10K  [RES0402_0-5]
R321  10K  [RES0402_0-5]
R322  10K  [RES0402_0-5]
R323  22K  [RES0402_0-5]
R324  22K  [RES0402_0-5]
R325  22K  [RES0402_0-5]
R326  22K  [RES0402_0-5]
R327  49.9E_1%  [RES0402_0-5]
R328  0E  [RES0402_0-5]
R329  0E  [RES0402_0-5]
R330  10K  [RES0402_0-5]
R331  1K_1%  [RES0402_0-5]
SH-J1  SPC02SYAN  [NA]
SW6  416131160804  [SW8_416131160804_260X230_SMD_2-7]
U47  TCA6408ARGTR  [QFN16_19-68_120X120_1_EP1-6]
U48  SN74AVC4T245RSVR  [UQFN16_TMUX1574_70X100_0-6]
U49  SN74LVC1G08DBVRE4  [SOT23-5]
U50  SN74LVC1G17DCKR  [SC70-5]
sheet 32. RESET SWITCHES
C335  0.1uF  [CAP0402_0-75]
C336  0.1uF  [CAP0402_0-75]
C337  0.1uF  [CAP0402_0-75]
C338  0.1uF  [CAP0402_0-75]
C340  0.1uF  [CAP0402_0-75]
C341  0.1uF  [CAP0402_0-75]
Q9  IRLML6401  [TO_SOT23-123]
Q10  IRLML6401  [TO_SOT23-123]
Q11  IRLML6401  [TO_SOT23-123]
R425  10K  [RES0402_0-5]
R426  10K  [RES0402_0-5]
R427  10K  [RES0402_0-5]
R428  10K  [RES0402_0-5]
R429  10K  [RES0402_0-5]
R431  10K  [RES0402_0-5]
R432  0E  [RES0402_0-5]
R433  4.7K_1%  [RES0402_0-5]
R434  10K  [RES0402_0-5]
SW10  430182050816  [SW4_430182050816_240X240_SMD_5-2]
SW11  430182050816  [SW4_430182050816_240X240_SMD_5-2]
SW12  430182050816  [SW4_430182050816_240X240_SMD_5-2]
TP75  TP40_SMD  [TP40_SMD]
U76  SN74LVC3G17DCUR  [VSSOP8_19-68_85X95_0-9]
U78  SN74LVC1G11DCKR  [SC70-6]
U79  SN74LVC1G08DBVRE4  [SOT23-5]

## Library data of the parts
C230 C235 = CAP: CAP CERAMIC 10uF 16V 20% X6S 0603; Chkd/date: VASANTHA/170117; Crtd /date: VASANTHA/170117; Custom_Duty: 15%; Customs_HS_Code: 85322990; Distributor_name: DIGIKEY; Distributor_part_number: 490-7198-1-ND; Footprint Path: Y:\MIS_DATABASE\Library\ALTIUM_TOOL\PCB_FOOTPRINTS\Altium_Footprint_Lib.PcbLib; Height: 0.90MM; Library Path: Y:\MIS_DATABASE\Library\ALTIUM_TOOL\SCHEMATICS_PARTS\MS_DISCRETE_Library.schlib; Mfr_name: MURATA; Mfr_part_number: GRM188C81C106MA73D; Mistral Part No: 120017010004-R; Package: 0603; Part_type: CAPACITORS\CERAMIC; Project: TRMM_SMART-M_PS; RoHS: RoHS; Temperature: -55°C+105°C; Tolerance: 20%; Voltage: 16V; Wattage: NA; Weight: 6.3mg; Datasheet: Y:\MIS_DATABASE\DATASHEETS\CAPACITORS\MURATA-GXX-SER_NOV17.PDF
C231 = CAP: CAP CERAMIC 1uF 25V 10% X6S 0402; Chkd/date: MANIRAJA/140518; Crtd /date: ALVY/140518; Custom_Duty: 15%; Customs_HS_Code: 85322990; Distributor_name: DIGIKEY; Distributor_part_number: 490-10014-1-ND; Footprint Path: Y:\MIS_DATABASE\Library\ALTIUM_TOOL\PCB_FOOTPRINTS\Altium_Footprint_Lib.PcbLib; Height: 0.60MM; Library Path: Y:\MIS_DATABASE\Library\ALTIUM_TOOL\SCHEMATICS_PARTS\MS_DISCRETE_Library.schlib; Mfr_name: MURATA; Mfr_part_number: GRM155C81E105KE11D; Mistral Part No: 120018050004-R; Package: 0402; Part_type: CAPACITORS\CERAMIC; Project: TI_SVB_MAXWELL_DUT; RoHS: RoHS; Temperature: -55°C+105°C; Tolerance: 10%; Voltage: 25V; Wattage: NA; Weight: 6mg; Datasheet: Y:\MIS_DATABASE\DATASHEETS\CAPACITORS\GRM155C81E105KE11X.PDF
C232 C236 C242-C246 C341 = CAP: CAP CERAMIC 0.1uF 50V 10% X7R 0402; Chkd/date: MANIRAJA/261020; Crtd /date: ALVY/211020; Custom_Duty: 15%; Customs_HS_Code: 85322990; Distributor_name: DIGIKEY; Distributor_part_number: 490-10700-1-ND; Footprint Path: Y:\MIS_DATABASE\Library\ALTIUM_TOOL\PCB_FOOTPRINTS\Altium_Footprint_Lib.PcbLib; Height: 0.55MM; Library Path: Y:\MIS_DATABASE\Library\ALTIUM_TOOL\SCHEMATICS_PARTS\MS_DISCRETE_Library.schlib; Mfr_name: MURATA; Mfr_part_number: GRM155R71H104KE14D; Mistral Part No: 120011100014-R; Package: 0402; Part_type: CAPACITORS\CERAMIC; Project: J7_CP; RoHS: RoHS; Temperature: -55°C+125°C; Tolerance: 10%; Voltage: 50V; Wattage: NA; Weight: 3.1mg; Datasheet: Y:\MIS_DATABASE\DATASHEETS\CAPACITORS\GRM155R71H104KE14.PDF
C233 = CAP: CAP CERAMIC 0.01uF 50V 10% X7R 0402; Chkd/date: MANIRAJA/280319; Crtd /date: MANIRAJA/280319; Custom_Duty: 15%; Customs_HS_Code: 85322990; Distributor_name: DIGIKEY; Distributor_part_number: 490-4516-1-ND; Footprint Path: Y:\MIS_DATABASE\Library\ALTIUM_TOOL\PCB_FOOTPRINTS\Altium_Footprint_Lib.PcbLib; Height: 0.55MM; Library Path: Y:\MIS_DATABASE\Library\ALTIUM_TOOL\SCHEMATICS_PARTS\MS_DISCRETE_Library.schlib; Mfr_name: MURATA; Mfr_part_number: GRM155R71H103KA88D; Mistral Part No: 120009030025-R; Package: 0402; Part_type: CAPACITORS\CERAMIC; Project: G4_SVGA; RoHS: RoHS; Temperature: -55°C+125°C; Tolerance: 10%; Voltage: 50V; Wattage: NA; Weight: 0.65mg; Datasheet: Y:\MIS_DATABASE\DATASHEETS\CAPACITORS\GRM155R71H103KA88D.PDF
C234 C335-C338 C340 = CAP: CAP CERAMIC 0.1uF 50V 10% X7R 0402; Automotive Alternate_mfr_name: TDK; Automotive Alternate_mfr_part_number: CGA2B3X7R1H104K050BB; Chkd/date: MANIRAJA/261020; Crtd /date: ALVY/211020; Custom_Duty: 15%; Customs_HS_Code: 85322990; Direct Alternate_mfr_name: TDK; Direct Alternate_mfr_part_number: C1005X7R1H104K050BE; Distributor_name: DIGIKEY; Distributor_part_number: 490-10700-1-ND; Footprint Path: Y:\MIS_DATABASE\Library\ALTIUM_TOOL\PCB_FOOTPRINTS\Altium_Footprint_Lib.PcbLib; Height: 0.55MM; Library Path: Y:\MIS_DATABASE\Library\ALTIUM_TOOL\SCHEMATICS_PARTS\MS_DISCRETE_Library.schlib; Mfr_name: MURATA; Mfr_part_number: GRM155R71H104KE14D; Mistral Part No: 120011100014-R; Package: 0402; Part_type: CAPACITORS\CERAMIC; Project: J7_CP; RoHS: RoHS; Temperature: -55°C+125°C; Tolerance: 10%; Voltage: 50V; Wattage: NA; Weight: 3.1mg; Datasheet: Y:\MIS_DATABASE\DATASHEETS\CAPACITORS\GRM155R71H104KE14.PDF
C237 = CAP: CAP CERAMIC 220pF 100V 5% C0G(NP0) 0402; Chkd/date: MANIRAJA/061021; Crtd /date: ALVY/051021; Custom_Duty: 15%; Customs_HS_Code: 85322990; Distributor_name: DIGIKEY; Distributor_part_number: 490-GRM1555C2A221JE01DTR-ND; Footprint Path: Y:\MIS_DATABASE\Library\ALTIUM_TOOL\PCB_FOOTPRINTS\Altium_Footprint_Lib.PcbLib; Height: 0.55MM; Library Path: Y:\MIS_DATABASE\Library\ALTIUM_TOOL\SCHEMATICS_PARTS\MS_DISCRETE_Library.schlib; Mfr_name: MURATA; Mfr_part_number: GRM1555C2A221JE01D; Mistral Part No: 120021100001-R; Package: 0402; Part_type: CAPACITORS\CERAMIC; Project: TI_AM62x SKEVM_BRD; RoHS: RoHS; Temperature: -55°C+125°C; Tolerance: 5%; Voltage: 100V; Wattage: NA; Weight: 1.6mg; Datasheet: Y:\MIS_DATABASE\DATASHEETS\CAPACITORS\GRM1555C2A221JE01.PDF
D6 D7 = DIODE: DIODE SWITCH 400mW 100V SOD123; Chkd/date: VASANTHA/220317; Crtd /date: MANIRAJA/150317; Custom_Duty: 15%; Customs_HS_Code: 85412900; Distributor_name: DIGIKEY; Distributor_part_number: 1N4148W-FDICT-ND; Height: 1.35MM; Mfr_name: DIODES INC; Mistral Part No: 130009030246-R; Package: SOD123; Part_type: DIODE\SWITCHING; Project: REVA-IBMS; RoHS: RoHS; Temperature: -65°C+150°C; Tolerance: NA; Voltage: 100V; Wattage: 400mW; Weight: 0.01g; Datasheet: Y:\MIS_DATABASE\DATASHEETS\DISCRETES\DIODES\1N4148W.PDF
FL6 = EMIFILTER_IND: PASSIVE FILTER EMI 100E 2A 0603; Chkd/date: BAVISH/170811; Crtd /date: CHAITHANYA/170811; Custom_Duty: 24%; Customs_HS_Code: 85437099; Distributor_name: DIGIKEY; Distributor_part_number: BLM18EG101TN1D-ND; Footprint Path: Y:\MIS_DATABASE\Library\ALTIUM_TOOL\PCB_FOOTPRINTS\Altium_Footprint_Lib.PcbLib; Height: 0.65MM; Library Path: Y:\MIS_DATABASE\Library\ALTIUM_TOOL\SCHEMATICS_PARTS\MS_FILTER_Library.schlib; Mfr_name: MURATA; Mfr_part_number: BLM18EG101TN1D; Mistral Part No: 130011080028-R; Package: 0603; Part_type: FILTER; Project: CPCI3GADC_CARD; RoHS: RoHS; Temperature: -55°C+125°C; Tolerance: NA; Voltage: NA; Wattage: NA; Weight: NA; Datasheet: Y:\MIS_DATABASE\DATASHEETS\DISCRETES\INDUCTORS\BLM18E.PDF
J9 J12 = HEADER_2X1: CON HDR 2X1 2.54MM PITCH ST TH; Chkd/date: NAVEED/210714; Crtd /date: USMAN/031012; Custom_Duty: 24%; Customs_HS_Code: 85369090; Distributor_name: DIGIKEY; Distributor_part_number: WM8072-ND; Height: 5.60MM; Mfr_name: MOLEX; Mfr_part_number: 90120-0122; Mistral Part No: 150012100005-R; Package: THRU-HOLE; Part_type: CONNECTOR\HEADERS; Project: NPOL_FEP; RoHS: RoHS; Temperature: -55°C+125°C; Tolerance: NA; Voltage: NA; Wattage: NA; Weight: NA; Datasheet: Y:\MIS_DATABASE\DATASHEETS\CONNECTORS\90120-SERIES.PDF
J10 = HEADER_3X1: CON HDR 1X3 2.54MM PITCH ST TH; Chkd/date: VASANTHA/211015; Crtd /date: VASANTHA/211015; Custom_Duty: 24%; Customs_HS_Code: 85369090; Distributor_name: DIGIKEY; Distributor_part_number: 732-5316-ND; Height: 8.54MM; Mfr_name: WURTH ELECTRONICS INC; Mfr_part_number: 61300311121; Mistral Part No: 150015100037-R; Package: THRU-HOLE; Part_type: CONNECTOR\HEADERS; Project: CYPHY_ROADKILL; RoHS: RoHS; Temperature: NA; Tolerance: NA; Voltage: NA; Wattage: NA; Weight: NA; Datasheet: Y:\MIS_DATABASE\DATASHEETS\CONNECTORS\6130XXX.PDF
R271-R275 R283 R284 = RESISTOR: RES 0E 1/10W JUMPER 0402; Assembly_Instruction: DNI; Chkd/date: VASANTHA/061216; Crtd /date: NAVEED/201014; Custom_Duty: 15%; Customs_HS_Code: 85332119; Distributor_name: DIGIKEY; Distributor_part_number: P0.0JCT-ND; Footprint Path: Y:\MIS_DATABASE\Library\ALTIUM_TOOL\PCB_FOOTPRINTS\Altium_Footprint_Lib.PcbLib; Height: 0.40MM; IBISSP_MODLES: VALUE REPEATING 2 TIME; Library Path: Y:\MIS_DATABASE\Library\ALTIUM_TOOL\SCHEMATICS_PARTS\MS_DISCRETE_Library.schlib; Mfr_name: PANASONIC-ECG; Mfr_part_number: ERJ-2GE0R00X; Mistral Part No: 110018030052-R; Package: 0402; Part_type: RESISTORS\FIXED; Project: AEGIS POM; RoHS: RoHS; Temperature: -55°C+155°C; Tolerance: NA; Voltage: NA; Wattage: 1/10W; Weight: 0.8mg; Datasheet: Y:\MIS_DATABASE\DATASHEETS\RESISTORS\PAN-ERJSER_NOV17.PDF
R276 R277 R282 R285 R316-R322 R330 R425-R429 R431 R434 = RESISTOR: RES 10K 1/16W 5% 0402; Chkd/date: VASANTHA/061216; Crtd /date: MAZHAR/230805; Custom_Duty: 15%; Customs_HS_Code: 85332119; Distributor_name: DIGIKEY; Distributor_part_number: 311-10KJRCT-ND; Footprint Path: Y:\MIS_DATABASE\Library\ALTIUM_TOOL\PCB_FOOTPRINTS\Altium_Footprint_Lib.PcbLib; Height: 0.40MM; Library Path: Y:\MIS_DATABASE\Library\ALTIUM_TOOL\SCHEMATICS_PARTS\MS_DISCRETE_Library.schlib; Mfr_name: YAGEO AMERICA; Mfr_part_number: RC0402JR-0710KL; Mistral Part No: 110011060021-R; Package: 0402; Part_type: RESISTORS\FIXED; Project: HSE; RoHS: RoHS; Temperature: -55°C+155°C; Tolerance: 5%; Voltage: NA; Wattage: 1/16W; Weight: 0.65mg; Datasheet: Y:\MIS_DATABASE\DATASHEETS\RESISTORS\RCXXXXL-SER_MAR18.PDF
R278 R331 = RESISTOR: RES 1K 1/10W 1% 0402; Chkd/date: VASANTHA/281216; Crtd /date: MAZHAR/150506; Custom_Duty: 15%; Customs_HS_Code: 85332119; Distributor_name: DIGIKEY; Distributor_part_number: P1.00KLCT-ND; Footprint Path: Y:\MIS_DATABASE\Library\ALTIUM_TOOL\PCB_FOOTPRINTS\Altium_Footprint_Lib.PcbLib; Height: 0.40MM; Library Path: Y:\MIS_DATABASE\Library\ALTIUM_TOOL\SCHEMATICS_PARTS\MS_DISCRETE_Library.schlib; Mfr_name: PANASONIC-ECG; Mfr_part_number: ERJ-2RKF1001X; Mistral Part No: 110009030411-R; Package: 0402; Part_type: RESISTORS\FIXED; Project: VOCERA; RoHS: RoHS; Temperature: -55°C+155°C; Tolerance: 1%; Voltage: NA; Wattage: 1/10W; Weight: 0.8mg; Datasheet: Y:\MIS_DATABASE\DATASHEETS\RESISTORS\PAN-ERJSER_NOV17.PDF
R279 R280 = RESISTOR: RES 10K 1/16W 5% 0402; Assembly_Instruction: DNI; Chkd/date: VASANTHA/061216; Crtd /date: MAZHAR/230805; Custom_Duty: 15%; Customs_HS_Code: 85332119; Distributor_name: DIGIKEY; Distributor_part_number: 311-10KJRCT-ND; Footprint Path: Y:\MIS_DATABASE\Library\ALTIUM_TOOL\PCB_FOOTPRINTS\Altium_Footprint_Lib.PcbLib; Height: 0.40MM; Library Path: Y:\MIS_DATABASE\Library\ALTIUM_TOOL\SCHEMATICS_PARTS\MS_DISCRETE_Library.schlib; Mfr_name: YAGEO AMERICA; Mfr_part_number: RC0402JR-0710KL; Mistral Part No: 110011060021-R; Package: 0402; Part_type: RESISTORS\FIXED; Project: HSE; RoHS: RoHS; Temperature: -55°C+155°C; Tolerance: 5%; Voltage: NA; Wattage: 1/16W; Weight: 0.65mg; Datasheet: Y:\MIS_DATABASE\DATASHEETS\RESISTORS\RCXXXXL-SER_MAR18.PDF
R281 R328 R329 R432 = RESISTOR: RES 0E 1/10W JUMPER 0402; Chkd/date: VASANTHA/061216; Crtd /date: NAVEED/201014; Custom_Duty: 15%; Customs_HS_Code: 85332119; Distributor_name: DIGIKEY; Distributor_part_number: P0.0JCT-ND; Footprint Path: Y:\MIS_DATABASE\Library\ALTIUM_TOOL\PCB_FOOTPRINTS\Altium_Footprint_Lib.PcbLib; Height: 0.40MM; IBISSP_MODLES: VALUE REPEATING 2 TIME; Library Path: Y:\MIS_DATABASE\Library\ALTIUM_TOOL\SCHEMATICS_PARTS\MS_DISCRETE_Library.schlib; Mfr_name: PANASONIC-ECG; Mfr_part_number: ERJ-2GE0R00X; Mistral Part No: 110018030052-R; Package: 0402; Part_type: RESISTORS\FIXED; Project: AEGIS POM; RoHS: RoHS; Temperature: -55°C+155°C; Tolerance: NA; Voltage: NA; Wattage: 1/10W; Weight: 0.8mg; Datasheet: Y:\MIS_DATABASE\DATASHEETS\RESISTORS\PAN-ERJSER_NOV17.PDF
SW4 = SWTACT_CAS-120TA: SWITCH TACT SPST SMD; Chkd/date: MAZHAR/221108; Crtd /date: USMAN/171008; Custom_Duty: 24%; Customs_HS_Code: 85369090; Distributor_name: DIGIKEY; Distributor_part_number: CAS120JCT-ND; Height: 2.50MM; Mfr_name: COPAL ELECTRONICS; Mistral Part No: 130009030342; Package: SMD; Part_type: ELECTRO-MECHANICAL\SWITCH; Project: SMART VIEW_IP CAMERA; Datasheet: Y:\MIS_DATABASE\DATASHEETS\MISC\SWITCHES\CAS-XX.PDF
SW5 = SW2_CHS-01TA: SWITCH SLIDE 1POS SPST SMD; Chkd/date: MANIRAJA/031018; Crtd /date: MANIRAJA/031018; Custom_Duty: 24%; Customs_HS_Code: 85369090; Distributor_name: DIGIKEY; Distributor_part_number: CKN10538CT-ND; Footprint Path: Y:\MIS_DATABASE\Library\ALTIUM_TOOL\PCB_FOOTPRINTS\Altium_Footprint_Lib.PcbLib; Height: 2.30MM; Library Path: Y:\MIS_DATABASE\Library\ALTIUM_TOOL\SCHEMATICS_PARTS\MS_SWITCH_Library.schlib; Mfr_name: CK; Mistral Part No: 130018100003-R; Package: SMD; Part_type: ELECTRO-MECHANICAL\SWITCH; Project: TI_60GHz-AOP; RoHS: RoHS; Temperature: -40°C+85°C; Tolerance: NA; Voltage: NA; Wattage: NA; Weight: NA; Datasheet: Y:\MIS_DATABASE\DATASHEETS\MISC\SWITCHES\TDAXX-SER.PDF
U41 = LMK1C1103_TSSOP8: IC 3-CHANNEL LVCMOS CLOCK BUFFER TSSOP8; Chkd/date: MANIRAJA/080920; Crtd /date: ALVY/070920; Custom_Duty: 15%; Customs_HS_Code: 85423100; Distributor_name: DIGIKEY; Distributor_part_number: 296-LMK1C1103PWRCT-ND; Footprint Path: Y:\MIS_DATABASE\Library\ALTIUM_TOOL\PCB_FOOTPRINTS\Altium_Footprint_Lib.PcbLib; Height: 1.20MM; Library Path: Y:\MIS_DATABASE\Library\ALTIUM_TOOL\SCHEMATICS_PARTS\MS_COMBINATIONAL_Library.schlib; Mfr_name: TEXAS INSTRUMENTS; Mistral Part No: 141020090002-R; Package: TSSOP8; Part_type: ICS\DIGITAL\COMBINATIONAL; Project: AM64X_SKEVM; RoHS: RoHS; Temperature: -40°C+125°C; Tolerance: NA; Voltage: NA; Wattage: NA; Weight: 34.1mg; Datasheet: Y:\MIS_DATABASE\DATASHEETS\ICS\DIGITAL\COMBINATIONAL\LMK1C110X.PDF
U42 = OSC4_EQXP-HC33: OSC 25.000MHz 3.3V CMOS SMD; Chkd/date: MANIRAJA/070121; Crtd /date: ALVY/060121; Custom_Duty: 24%; Customs_HS_Code: 85437099; Distributor_name: NA; Distributor_part_number: NA; Footprint Path: Y:\MIS_DATABASE\Library\ALTIUM_TOOL\PCB_FOOTPRINTS\Altium_Footprint_Lib.PcbLib; Height: 1.20MM; Library Path: Y:\MIS_DATABASE\Library\ALTIUM_TOOL\SCHEMATICS_PARTS\MS_DISCRETE_Library.schlib; Mfr_name: WURTH ELEKTRONIK; Mfr_part_number: 831055678; Mistral Part No: 130021010008-R; Package: SMD; Part_type: OSCILLATORS; Project: TI_AM243x LP EVM; RoHS: RoHS; Temperature: -40°C+85°C; Tolerance: NA; Voltage: 3.3V; Wattage: NA; Weight: NA; Datasheet: Y:\MIS_DATABASE\DATASHEETS\MISC\CRY_OSC\831055678.PDF
U43 = SN74LVC1G07DBVR_SOT23-5: IC SINGLE BUFFER GATE CMOS LOGIC LEVEL SHIFTER SC70-5; Chkd/date: MANIRAJA/130819; Crtd /date: MANIRAJA/130819; Custom_Duty: 15%; Customs_HS_Code: 85423100; Distributor_name: DIGIKEY; Distributor_part_number: 296-37177-1-ND; Footprint Path: Y:\MIS_DATABASE\Library\ALTIUM_TOOL\PCB_FOOTPRINTS\Altium_Footprint_Lib.PcbLib; Height: 1.10MM; Library Path: Y:\MIS_DATABASE\Library\ALTIUM_TOOL\SCHEMATICS_PARTS\MS_GATE_Library.schlib; Mfr_name: TEXAS INSTRUMENTS; Mistral Part No: 141019080005-R; Package: SC70-5; Part_type: ICS\DIGITAL\GATES; Project: BRUKER_SD820_COMMONDO; RoHS: RoHS; Temperature: -40°C+125°C; Tolerance: NA; Voltage: NA; Wattage: NA; Weight: 20mg; Datasheet: Y:\MIS_DATABASE\DATASHEETS\ICS\DIGITAL\GATES\SN74LV1T34.PDF
U44 = SN74CB3Q3257PWR_TSSOP16: IC 4BIT 1-OF-2 FET MULTIPLEXER/DEMULTIPLEXER TSSOP16; Chkd/date: SUHAS/251010; Crtd /date: USMAN/060109; Custom_Duty: 15%; Customs_HS_Code: 85423100; Distributor_name: DIGIKEY; Distributor_part_number: 296-19138-1-ND; Height: 1.20MM; Mfr_name: TEXAS INSTRUMENTS; Mistral Part No: 141009030117-R; Package: TSSOP16; Part_type: ICS\DIGITAL\COMBINATIONAL; Project: OMAP_EVM; RoHS: Sb/ Br FREE; Temperature: -40°C+85°C; Datasheet: Y:\MIS_DATABASE\DATASHEETS\ICS\DIGITAL\COMBINATIONAL\SN74CB3Q3257.PDF
U45 = TLIN2029DQ1_SOIC8: IC FAULT PROTECTED LIN TRANSCEIVER WITH DOMINANT STATE TIMEOUT SOIC8; Chkd/date: MANIRAJA/140818; Crtd /date: ALVY/140818; Custom_Duty: 15%; Customs_HS_Code: 85423100; Distributor_name: DIGIKEY; Distributor_part_number: 296-49967-ND; Footprint Path: Y:\MIS_DATABASE\Library\ALTIUM_TOOL\PCB_FOOTPRINTS\Altium_Footprint_Lib.PcbLib; Height: 1.75MM; Library Path: Y:\MIS_DATABASE\Library\ALTIUM_TOOL\SCHEMATICS_PARTS\MS_TELECOM_Library.schlib; Mfr_name: TEXAS INSTRUMENTS; Mfr_part_number: TLIN2029DQ1; Mistral Part No: 143018080003-R; Package: SOIC8; Part_type: ICS\TELECOM\TRANSCEIVER; Project: TI_J7ES_GESI_BOARD; RoHS: RoHS; Temperature: -40°C+125°C; Tolerance: NA; Voltage: NA; Wattage: NA; Weight: NA; Datasheet: Y:\MIS_DATABASE\DATASHEETS\ICS\TELECOM\TLIN2029-Q1.PDF
C247 = CAP: CAP CERAMIC 1000pF 50V 5% C0G(NP0) 0402; Chkd/date: VASANTHA/281216; Crtd /date: MAZHAR/290806; Custom_Duty: 15%; Customs_HS_Code: 85322990; Distributor_name: DIGIKEY; Distributor_part_number: 490-3244-1-ND; Footprint Path: Y:\MIS_DATABASE\Library\ALTIUM_TOOL\PCB_FOOTPRINTS\Altium_Footprint_Lib.PcbLib; Height: 0.55MM; Library Path: Y:\MIS_DATABASE\Library\ALTIUM_TOOL\SCHEMATICS_PARTS\MS_DISCRETE_Library.schlib; Mfr_name: MURATA; Mfr_part_number: GRM1555C1H102JA01D; Mistral Part No: 120016110009-R; Package: 0402; Part_type: CAPACITORS\CERAMIC; Project: SVDO_RMB_MMA; RoHS: RoHS; Temperature: -55°C+125°C; Tolerance: 5%; Voltage: 50V; Wattage: NA; Weight: 6mg; Datasheet: Y:\MIS_DATABASE\DATASHEETS\CAPACITORS\MURATA-GXX-SER_NOV17.PDF
R323-R326 = RESISTOR: RES 22K 1/16W 5% 0402; Chkd/date: MANIRAJA/310718; Crtd /date: BAVISH/021210; Custom_Duty: 15%; Customs_HS_Code: 85332119; Distributor_name: DIGIKEY; Distributor_part_number: 311-22KJRCT-ND; Footprint Path: Y:\MIS_DATABASE\Library\ALTIUM_TOOL\PCB_FOOTPRINTS\Altium_Footprint_Lib.PcbLib; Height: 0.40MM; Library Path: Y:\MIS_DATABASE\Library\ALTIUM_TOOL\SCHEMATICS_PARTS\MS_DISCRETE_Library.schlib; Mfr_name: YAGEO AMERICA; Mfr_part_number: RC0402JR-0722KL; Mistral Part No: 110010120021-R; Package: 0402; Part_type: RESISTORS\FIXED; Project: TE4; RoHS: RoHS; Temperature: -55°C+155°C; Tolerance: 5%; Voltage: NA; Wattage: 1/16W; Weight: 0.65mg; Datasheet: Y:\MIS_DATABASE\DATASHEETS\RESISTORS\RCXXXXL-SER_MAR18.PDF
R327 = RESISTOR: RES 49.9E 1/10W 1% 0402; Chkd/date: VASANTHA/201216; Crtd /date: MAZHAR/201005; Custom_Duty: 15%; Customs_HS_Code: 85332119; Distributor_name: DIGIKEY; Distributor_part_number: P49.9LCT-ND; Footprint Path: Y:\MIS_DATABASE\Library\ALTIUM_TOOL\PCB_FOOTPRINTS\Altium_Footprint_Lib.PcbLib; Height: 0.40MM; Library Path: Y:\MIS_DATABASE\Library\ALTIUM_TOOL\SCHEMATICS_PARTS\MS_DISCRETE_Library.schlib; Mfr_name: PANASONIC-ECG; Mfr_part_number: ERJ-2RKF49R9X; Mistral Part No: 110009030897-R; Package: 0402; Part_type: RESISTORS\FIXED; Project: RED EYE; RoHS: RoHS; Temperature: -55°C+155°C; Tolerance: 1%; Voltage: NA; Wattage: 1/10W; Weight: 0.8mg; Datasheet: Y:\MIS_DATABASE\DATASHEETS\RESISTORS\PAN-ERJSER_NOV17.PDF
SH-J1 = ACCESSORY: ACCESSORIE JUMPER SHORTING GOLD FLASH; Chkd/date: SUHAS\211010; Crtd /date: USMAN/301208; Distributor_name: DIGIKEY; Distributor_part_number: S9001-ND; Footprint Path: Y:\MIS_DATABASE\Library\ALTIUM_TOOL\PCB_FOOTPRINTS\Altium_Footprint_Lib.PcbLib; Library Path: Y:\MIS_DATABASE\Library\ALTIUM_TOOL\SCHEMATICS_PARTS\MS_MECHANICAL_Library.schlib; Mfr_name: SULLINS CONNECTOR; Mistral Part No: 160009030153-R; Part_type: ACCESSORIES; Project: SMART VIEW_NVR; RoHS: RoHS; Temperature: -55°C+105°C; Datasheet: Y:\MIS_DATABASE\DATASHEETS\MISC\MODULES\SPC02SYAN.PDF
SW6 = SW8_GDH04S04: SWITCH SLIDE SPST ST SMD; Chkd/date: MANIRAJA/120121; Crtd /date: MANIRAJA/120121; Custom_Duty: 24%; Customs_HS_Code: 85369090; Distributor_name: DIGIKEY; Distributor_part_number: 732-3854-1-ND; Footprint Path: Y:\MIS_DATABASE\Library\ALTIUM_TOOL\PCB_FOOTPRINTS\Altium_Footprint_Lib.PcbLib; Height: 2.65MM; Library Path: Y:\MIS_DATABASE\Library\ALTIUM_TOOL\SCHEMATICS_PARTS\MS_SWITCH_Library.schlib; Mfr_name: WURTH ELEKTRONIK; Mistral Part No: 130021010016-R; Package: SMD; Part_type: ELECTRO-MECHANICAL\SWITCH; Project: AM223X_LP; RoHS: RoHS; Temperature: -40°C+85°C; Tolerance: NA; Voltage: NA; Wattage: NA; Weight: 110mg; Datasheet: Y:\MIS_DATABASE\DATASHEETS\MISC\SWITCHES\4161311608XX.PDF
U47 = TCA6408ARGTR_VQFN16: IC 8-BIT I2C AND SMBUS I/O EXPANDER WITH INTERRUPT O/P VQFN16; Chkd/date: MANIRAJA/151018; Crtd /date: MANIRAJA/151018; Custom_Duty: 15%; Customs_HS_Code: 85423100; Distributor_name: DIGIKEY; Distributor_part_number: 296-24825-1-ND; Footprint Path: Y:\MIS_DATABASE\Library\ALTIUM_TOOL\PCB_FOOTPRINTS\Altium_Footprint_Lib.PcbLib; Height: 1.00MM; Library Path: Y:\MIS_DATABASE\Library\ALTIUM_TOOL\SCHEMATICS_PARTS\MS_MISCINTERFACE_Library.schlib; Mfr_name: TEXAS INSTRUMENTS; Mistral Part No: 141018100011-R; Package: VQFN16; Part_type: ICS\INTERFACE; Project: TI_60GHz-AOP; RoHS: RoHS; Temperature: -40°C+85°C; Tolerance: NA; Voltage: NA; Wattage: NA; Weight: 24.1mg; Datasheet: Y:\MIS_DATABASE\DATASHEETS\ICS\INTERFACE\TCA6408AXX.PDF
U48 = SN74AVC4T245RSV_UQFN16: IC 2-BIT BUS TRANSCEIVER WITH CONFIGURABLE VOLTAGE TRANSLATION AND 3 STATE O/P UQFN16; Chkd/date: MANIRAJA/040520; Crtd /date: BAVISH/190411; Custom_Duty: 15%; Customs_HS_Code: 85423100; Distributor_name: DIGIKEY; Distributor_part_number: 296-24366-1-ND; Footprint Path: Y:\MIS_DATABASE\Library\ALTIUM_TOOL\PCB_FOOTPRINTS\Altium_Footprint_Lib.PcbLib; Height: 0.55MM; Library Path: Y:\MIS_DATABASE\Library\ALTIUM_TOOL\SCHEMATICS_PARTS\MS_BUSDRIVERTRANSCEIVER_Library.schlib; Mfr_name: TEXAS INSTRUMENTS; Mistral Part No: 141011040011-R; Package: UQFN16; Part_type: ICS\DIGITAL\BUSTRANSCEIVER; Project: HMC; RoHS: RoHS; Temperature: -40°C+85°C; Tolerance: NA; Voltage: NA; Wattage: NA; Weight: 41mg; Datasheet: Y:\MIS_DATABASE\DATASHEETS\ICS\DIGITAL\BUSTRANSCEIVER\SN74AVC4T245-SER.PDF
U49 U79 = SN74LVC1G08DBVRE4_SOT23-5: IC SINGLE 2-INPUT POSITIVE AND GATE SOT23-5; Automotive Alternate_mfr_name: TEXAS INSTRUMENTS; Automotive Alternate_mfr_part_number: SN74LVC1G08QDBVRQ1; Chkd/date: SUHAS/221010; Crtd /date: USMAN/151008; Custom_Duty: 15%; Customs_HS_Code: 85423100; Distributor_name: DIGIKEY; Distributor_part_number: SN74LVC1G08DBVRE4-ND; Height: 1.45MM; Mfr_name: TEXAS INSTRUMENTS; Mistral Part No: 141009060026-R; Part_type: ICS\DIGITAL\GATES; Project: KHAN_MAIN; RoHS: Sb/ Br FREE; Temperature: -40°C+85°C; Datasheet: Y:\MIS_DATABASE\DATASHEETS\ICS\DIGITAL\GATES\SN74LVC1G08.PDF
U50 = SN74LVC1G17DCKR_SC70-5: IC SINGLE SCHMITT-TRIGGER BUFFER SC70-5; Chkd/date: MAZHAR/011210; Crtd /date: BAVISH/251110; Custom_Duty: 15%; Customs_HS_Code: 85423100; Distributor_name: DIGIKEY; Distributor_part_number: 296-11934-1-ND; Height: 1.10MM; Mfr_name: TEXAS INSTRUMENTS; Mistral Part No: 141010110012-R; Part_type: ICS\DIGITAL\COMBINATIONAL; Project: ITS-PWR_CARD; RoHS: RoHS; Temperature: -40°C+85°C; Tolerance: NA; Voltage: NA; Wattage: NA; Weight: NA; Datasheet: Y:\MIS_DATABASE\DATASHEETS\ICS\DIGITAL\COMBINATIONAL\SN74LVC1G17DCK.PDF
Q9-Q11 = MOSFET_IRLML6401TR: TRANSISTOR MOSFET P-CHANNEL SOT23-3; Chkd/date: SHREESHAIL/020206; Crtd /date: MAZHAR/040505; Custom_Duty: 15%; Customs_HS_Code: 85412900; Distributor_name: DIGIKEY; Distributor_part_number: IRLML6401PBFCT-ND; Height: 1.11MM; Mfr_name: IRF; Mfr_part_number: IRLML6401TRPBF; Mistral Part No: 130009031213-P; Package: SOT23-3; Part_type: TRANSISTOR\MOSFET; Project: G4_SVGA; RoHS: Pb-Free; Temperature: -55°C+150°C; Tolerance: NA; Voltage: NA; Wattage: NA; Weight: NA; Datasheet: Y:\MIS_DATABASE\DATASHEETS\DISCRETES\TRANSISTORS_FETS\IRLML6401.PDF
R433 = RESISTOR: RES 4.7K 1/16W 1% 0402; Chkd/date: VASANTHA/061216; Crtd /date: USMAN/070109; Custom_Duty: 15%; Customs_HS_Code: 85332119; Distributor_name: DIGIKEY; Distributor_part_number: 541-4.70KLCT-ND; Footprint Path: Y:\MIS_DATABASE\Library\ALTIUM_TOOL\PCB_FOOTPRINTS\Altium_Footprint_Lib.PcbLib; Height: 0.40MM; Library Path: Y:\MIS_DATABASE\Library\ALTIUM_TOOL\SCHEMATICS_PARTS\MS_DISCRETE_Library.schlib; Mfr_name: VISHAY; Mfr_part_number: CRCW04024K70FKED; Mistral Part No: 110009030797-R; Package: 0402; Part_type: RESISTORS\FIXED; Project: OMAP_EVM; RoHS: RoHS; Temperature: -55°C+155°C; Tolerance: 1%; Voltage: NA; Wattage: 1/16W; Weight: 0.65mg; Datasheet: Y:\MIS_DATABASE\DATASHEETS\RESISTORS\CRCW0603.PDF
SW10-SW12 = SW4_430182050816: SWITCH TACTILE SPST ST SMD; Chkd/date: MANIRAJA/180121; Crtd /date: ALVY/180121; Custom_Duty: 24%; Customs_HS_Code: 85369090; Distributor_name: DIGIKEY; Distributor_part_number: 732-7005-1-ND; Footprint Path: Y:\MIS_DATABASE\Library\ALTIUM_TOOL\PCB_FOOTPRINTS\Altium_Footprint_Lib.PcbLib; Height: 5.15MM; Library Path: Y:\MIS_DATABASE\Library\ALTIUM_TOOL\SCHEMATICS_PARTS\MS_SWITCH_Library.schlib; Mfr_name: WURTH ELEKTRONIK; Mistral Part No: 130021010021-R; Package: SMD; Part_type: ELECTRO-MECHANICAL\SWITCH; Project: TI_DRA829 SK EVM BRD; RoHS: RoHS; Temperature: -40°C+85°C; Tolerance: NA; Voltage: NA; Wattage: NA; Weight: 220mg; Datasheet: Y:\MIS_DATABASE\DATASHEETS\MISC\SWITCHES\4301X2XXX816.PDF
TP75 = TESTPOINT: TESTPOINT CIR 40 SMD; Chkd/date: MAZHAR/190505; Crtd /date: MAZHAR/190505; Distributor_name: NA; Distributor_part_number: NA; Footprint Path: Y:\MIS_DATABASE\Library\ALTIUM_TOOL\PCB_FOOTPRINTS\Altium_Footprint_Lib.PcbLib; Height: NA; Library Path: Y:\MIS_DATABASE\Library\ALTIUM_TOOL\SCHEMATICS_PARTS\MS_DISCRETE_Library.schlib; MECHANICAL 3D STEP FILE: NA; Mfr_name: LOCAL; Mistral Part No: 130009030933; Package: SMD; Project: RAINIER-3; RoHS: NA; Temperature: NA; Tolerance: NA; Voltage: NA; Wattage: NA; Weight: NA; Datasheet: NA
U76 = SN74LVC3G17DCUR_VSSOP8: IC TRIPLE SCHMITT-TRIGGER BUFFER VSSOP8; Chkd/date: MANIRAJA/280917; Crtd /date: MANIRAJA/280917; Custom_Duty: 15%; Customs_HS_Code: 85423100; Distributor_name: DIGIKEY; Distributor_part_number: 296-18818-1-ND; Height: 0.90MM; Mfr_name: TEXAS INSTRUMENTS; Mistral Part No: 141017090019-R; Package: VSSOP8; Part_type: ICS\DIGITAL\COMBINATIONAL; Project: TI_MAXIE_CPB; RoHS: RoHS; Temperature: -40°C+125°C; Tolerance: NA; Voltage: NA; Wattage: NA; Weight: 9.6mg; Datasheet: Y:\MIS_DATABASE\DATASHEETS\ICS\DIGITAL\COMBINATIONAL\SN74LVC3G17.PDF
U78 = SN74LVC1G11DCKR_SC70-6: IC SINGLE 3-INPUT POSITIVE-AND GATE SC70-6; Chkd/date: SHREESHAIL/220506; Crtd /date: MAZHAR/150506; Custom_Duty: 15%; Customs_HS_Code: 85423100; Distributor_name: DIGIKEY; Distributor_part_number: 296-18066-1-ND; Height: 1.10MM; Mfr_name: TEXAS INSTRUMENTS; Mistral Part No: 141009030230-R; Part_type: ICS\DIGITAL\GATES; Project: VOCERA; RoHS: Sb/ Br FREE; Datasheet: Y:\MIS_DATABASE\DATASHEETS\ICS\DIGITAL\GATES\SN74LVC1G.PDF

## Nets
DGND: C230.2 C231.2 C232.2 C233.2 C234.2 C235.2 C236.2 C237.2 C242.2 C243.2 C244.2 C245.1 C246.1 C247.2 C335.2 C336.2 C337.2 C338.2 C340.2 C341.2 J9.2 J10.3 Q9.3(D) Q10.3(D) Q11.3(D) R279.2 R280.2 R281.2 R323.1 R324.1 R325.1 R326.1 R330.1 R331.2 R434.2 SW10.1 SW10.3 SW11.1 SW11.3 SW12.1 SW12.3 U41.4(GND) U42.2(GND) U43.3(GND) U44.8(GND) U45.5(GND) U47.6(GND) U47.17(EP) U48.10(GND1) U48.11(GND2) U49.3(GND) U50.3(GND) U76.4(GND) U78.2(GND) U79.3(GND) ; also on sheet 1 2 3 4 6 7 8 12 13 14 15 16 17 24 25 26 27 28 29 30 32 33
VBAT_LIN: D7.2(A) J9.1
VDD_5V0_LDO3: SW4.1 ; also on sheet 12 13 30
VDDS_IO_1V8: U43.5(VCC) ; also on sheet 8
BOOTMODE_TA_I2C_SCL: U47.12(SCL) ; also on sheet 3 28
BOOTMODE_TA_I2C_SDA: U47.13(SDA) ; also on sheet 3 28
BOOTMODEON: R329.1 R330.2 U48.1(~{1OE}) U48.16(~{2OE})
CLK_BUF_EN: R276.1 U41.2(1G) ; also on sheet 12
CLOCKOUT0: R271.1 ; also on sheet 27
DIR1: R322.1 U48.4(1DIR) U48.5(2DIR)
HSEC_UART1_RXD: U44.3(1B2) ; also on sheet 6
HSEC_UART1_TXD: U44.6(2B2) ; also on sheet 6
LIN_EN: R285.1 U45.2(EN)
LIN_MUX_OE#: R280.1 U44.15(~{OE})
LIN_MUX_SEL: R277.2 R279.1 U44.1(S) ; also on sheet 12
LIN_UART1_RXD: R284.1 U44.2(1B1)
LIN_UART1_TXD: R283.1 U44.5(2B1)
MUX_UART1/LIN_RXD: U44.4(1A) ; also on sheet 26
MUX_UART1/LIN_TXD: U44.7(2A) ; also on sheet 26
OSC_CLK_OUT: R273.1 U42.3(OUTPUT)
PMIC_NRST: R432.1 ; also on sheet 30
PORZ: R327.1 TP75.1(TP) U79.4(Y) ; also on sheet 6 7 15 24 27
PORz_RST: R427.2 U76.7(1Y) U78.3(B)
PORz_VMAIN: U78.4(Y) U79.1(A)
PR0_PRU0_REF_CLK: R272.2 ; also on sheet 15
PR0_PRU1_REF_CLK: R274.2 ; also on sheet 7
RESETz: R428.2 U76.2(3Y) ; also on sheet 27
SOC_BOOTMODE0: U48.15(1B1) ; also on sheet 24
SOC_BOOTMODE1: U48.14(1B2) ; also on sheet 24
SOC_BOOTMODE2: U48.13(2B1) ; also on sheet 26
SOC_BOOTMODE3: U48.12(2B2) ; also on sheet 26
SOC_CLK_IN: U43.4(Y) ; also on sheet 27
SOC_INTn: U76.5(2Y) ; also on sheet 26
SW_PB_INTn: Q10.2(S) SW11.2 U76.3(2A)
SW_PB_PORz: Q9.2(S) SW10.2 U76.1(1A)
SW_PB_RESETz: Q11.2(S) SW12.2 U76.6(3A)
SYS_BOOTMODE0: R323.2 SW6.1 U47.2(P0) U48.6(1A1)
SYS_BOOTMODE1: R324.2 SW6.2 U47.3(P1) U48.7(1A2)
SYS_BOOTMODE2: R325.2 SW6.3 U47.4(P2) U48.8(2A1)
SYS_BOOTMODE3: R326.2 SW6.4 U47.5(P3) U48.9(2A2)
SYSBOOT_BUF_ENz: R328.1 U49.2(B)
TA_GPIO1: Q10.1(G) ; also on sheet 3 28
TA_GPIO3: J12.1 U49.1(A) ; also on sheet 3 28
TA_GPIO4: U47.1(~{RESET}) ; also on sheet 3 28
TA_PORZn: Q9.1(G) ; also on sheet 3 28
TA_RESETz: Q11.1(G) ; also on sheet 3 28
VLIN: C236.1 D6.2(A) J10.1 SW4.2(COM) U45.7(VSUP)
VMAIN: R433.1 ; also on sheet 1 4 14 26 27 29
VMAIN_MON: R433.2 R434.1 U79.2(B)
VSYS_1V2_PG: U78.1(A) ; also on sheet 1 29
VSYS_3V3_LDO1: C230.1 C233.1 C243.1 C335.1 C340.1 C341.1 FL6.1 R276.2 R425.1 R426.1 R427.1 R428.1 R429.1 R431.1 U42.1(ENABLE/DISABLE) U42.4(VDD) U48.2(VCCB) U76.8(VCC) U78.5(VCC) U79.5(VCC) ; also on sheet 1 6 7 12 13 14 15 16 17 24 26 27 28 29 30 32 33
VSYS_3V3_LDO2: C234.1 R277.1 R282.1 R285.2 U44.16(VCC) ; also on sheet 1 12 13 25 26 30
VSYS_TA_3V3: C242.1 C244.1 C245.2 C246.2 R316.1 R317.1 R318.1 R319.1 R320.2 R321.2 R322.2 U47.14(VCCP) U47.15(VCCI) U48.3(VCCA) U49.5(VCC) U50.5(VCC) ; also on sheet 1 3 28 29
N32133653: R329.2 U49.4(Y)
N32133735: R319.2 SW6.5
N32133737: R318.2 SW6.6
N32133754: R317.2 SW6.7
N32133756: R316.2 SW6.8
N32302430: C336.1 R425.2 SW10.4
N32359377: C338.1 R429.2 SW12.4
N32360252: C337.1 R426.2 SW11.4
N32800162: R321.1 U47.16(ADDR)
N32800169: R320.1 U47.11(~{INT})
N32845049: C231.1 C232.1 FL6.2 U41.6(VDD)
N32845083: R271.2 R273.2 U41.1(CLKIN)
N32845192: R272.1 U41.3(Y0)
N32845194: R274.1 U41.8(Y1)
N32845196: R275.1 U41.5(Y2)
N32851242: J12.2 R331.1
N33235493: R328.2 U50.4(Y)
N33514520: C247.1 R327.2 U50.2(A)
N33770351: R275.2 U43.2(A)
N33879812: R283.2 U45.4(TXD)
N33879815: R282.2 R284.2 U45.1(RXD)
N33880944: R281.1 U44.9(3A) U44.12(4A)
N33881371: C237.1 J10.2 SW5.1 U45.6(LIN)
N33882160: D6.1(K) R278.1
N33883080: R278.2 SW5.2
N33986982: C235.1 D7.1(K) SW4.3
N34869480: R431.2 R432.2 U78.6(C)

Not connected (* = marked no-connect by the designer): U41 7(NC)*; U43 1(NC)*; U44 10(3B2)* 11(3B1)* 13(4B2)* 14(4B1)*; U45 3(NC1)* 8(NC2)*; U47 7(P4) 8(P5) 9(P6) 10(P7); U50 1(NC)*

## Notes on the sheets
sheet 9
- CLOCKS
- LIN MUX/DEMUX
- LIN 1
- I2C0 - 1:2  MUX
- SILK: VBAT
- SEL
- CONDITION
- FUNCTION
- SILK: LIN
- LOW
- LIN SELECTED
- A-->B1 port
- HIGH
- HSEC UART selected
- A-->B2 port
- LIN MASTER MODE
- Switch - CLOSE
- LIN SLAVE MODE
- Switch - OPEN
sheet 10
- RESET SWITCHES
- From Test Automation header
- SILK: "PORZ"
- From Test Automation header
- SILK: "INTn"
- SILK: "RESETn"
- PORz
sheet 11
- BOOTMODE BUFFER AND SWITCH
- SWITCH ON  =  LOGIC 1
  SWITCH OFF =  LOGIC 0
- DIR = H: A -> B
- I2C ADDRESS: 0x21
- BOOTMODE Control
  from Test
  Automation HDR
- PORZ
- TA_GPIO3
- HIGH
- LOW
- Enabled
- HIGH
- HIGH
- Disabled
- SH-J1 Shall be mounted to
  enable the bootmode buffer
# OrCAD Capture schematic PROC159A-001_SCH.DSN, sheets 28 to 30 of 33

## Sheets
28 24. TEST AUTOMATION HEADER: size C; title: TEST AUTOMATION HEADER
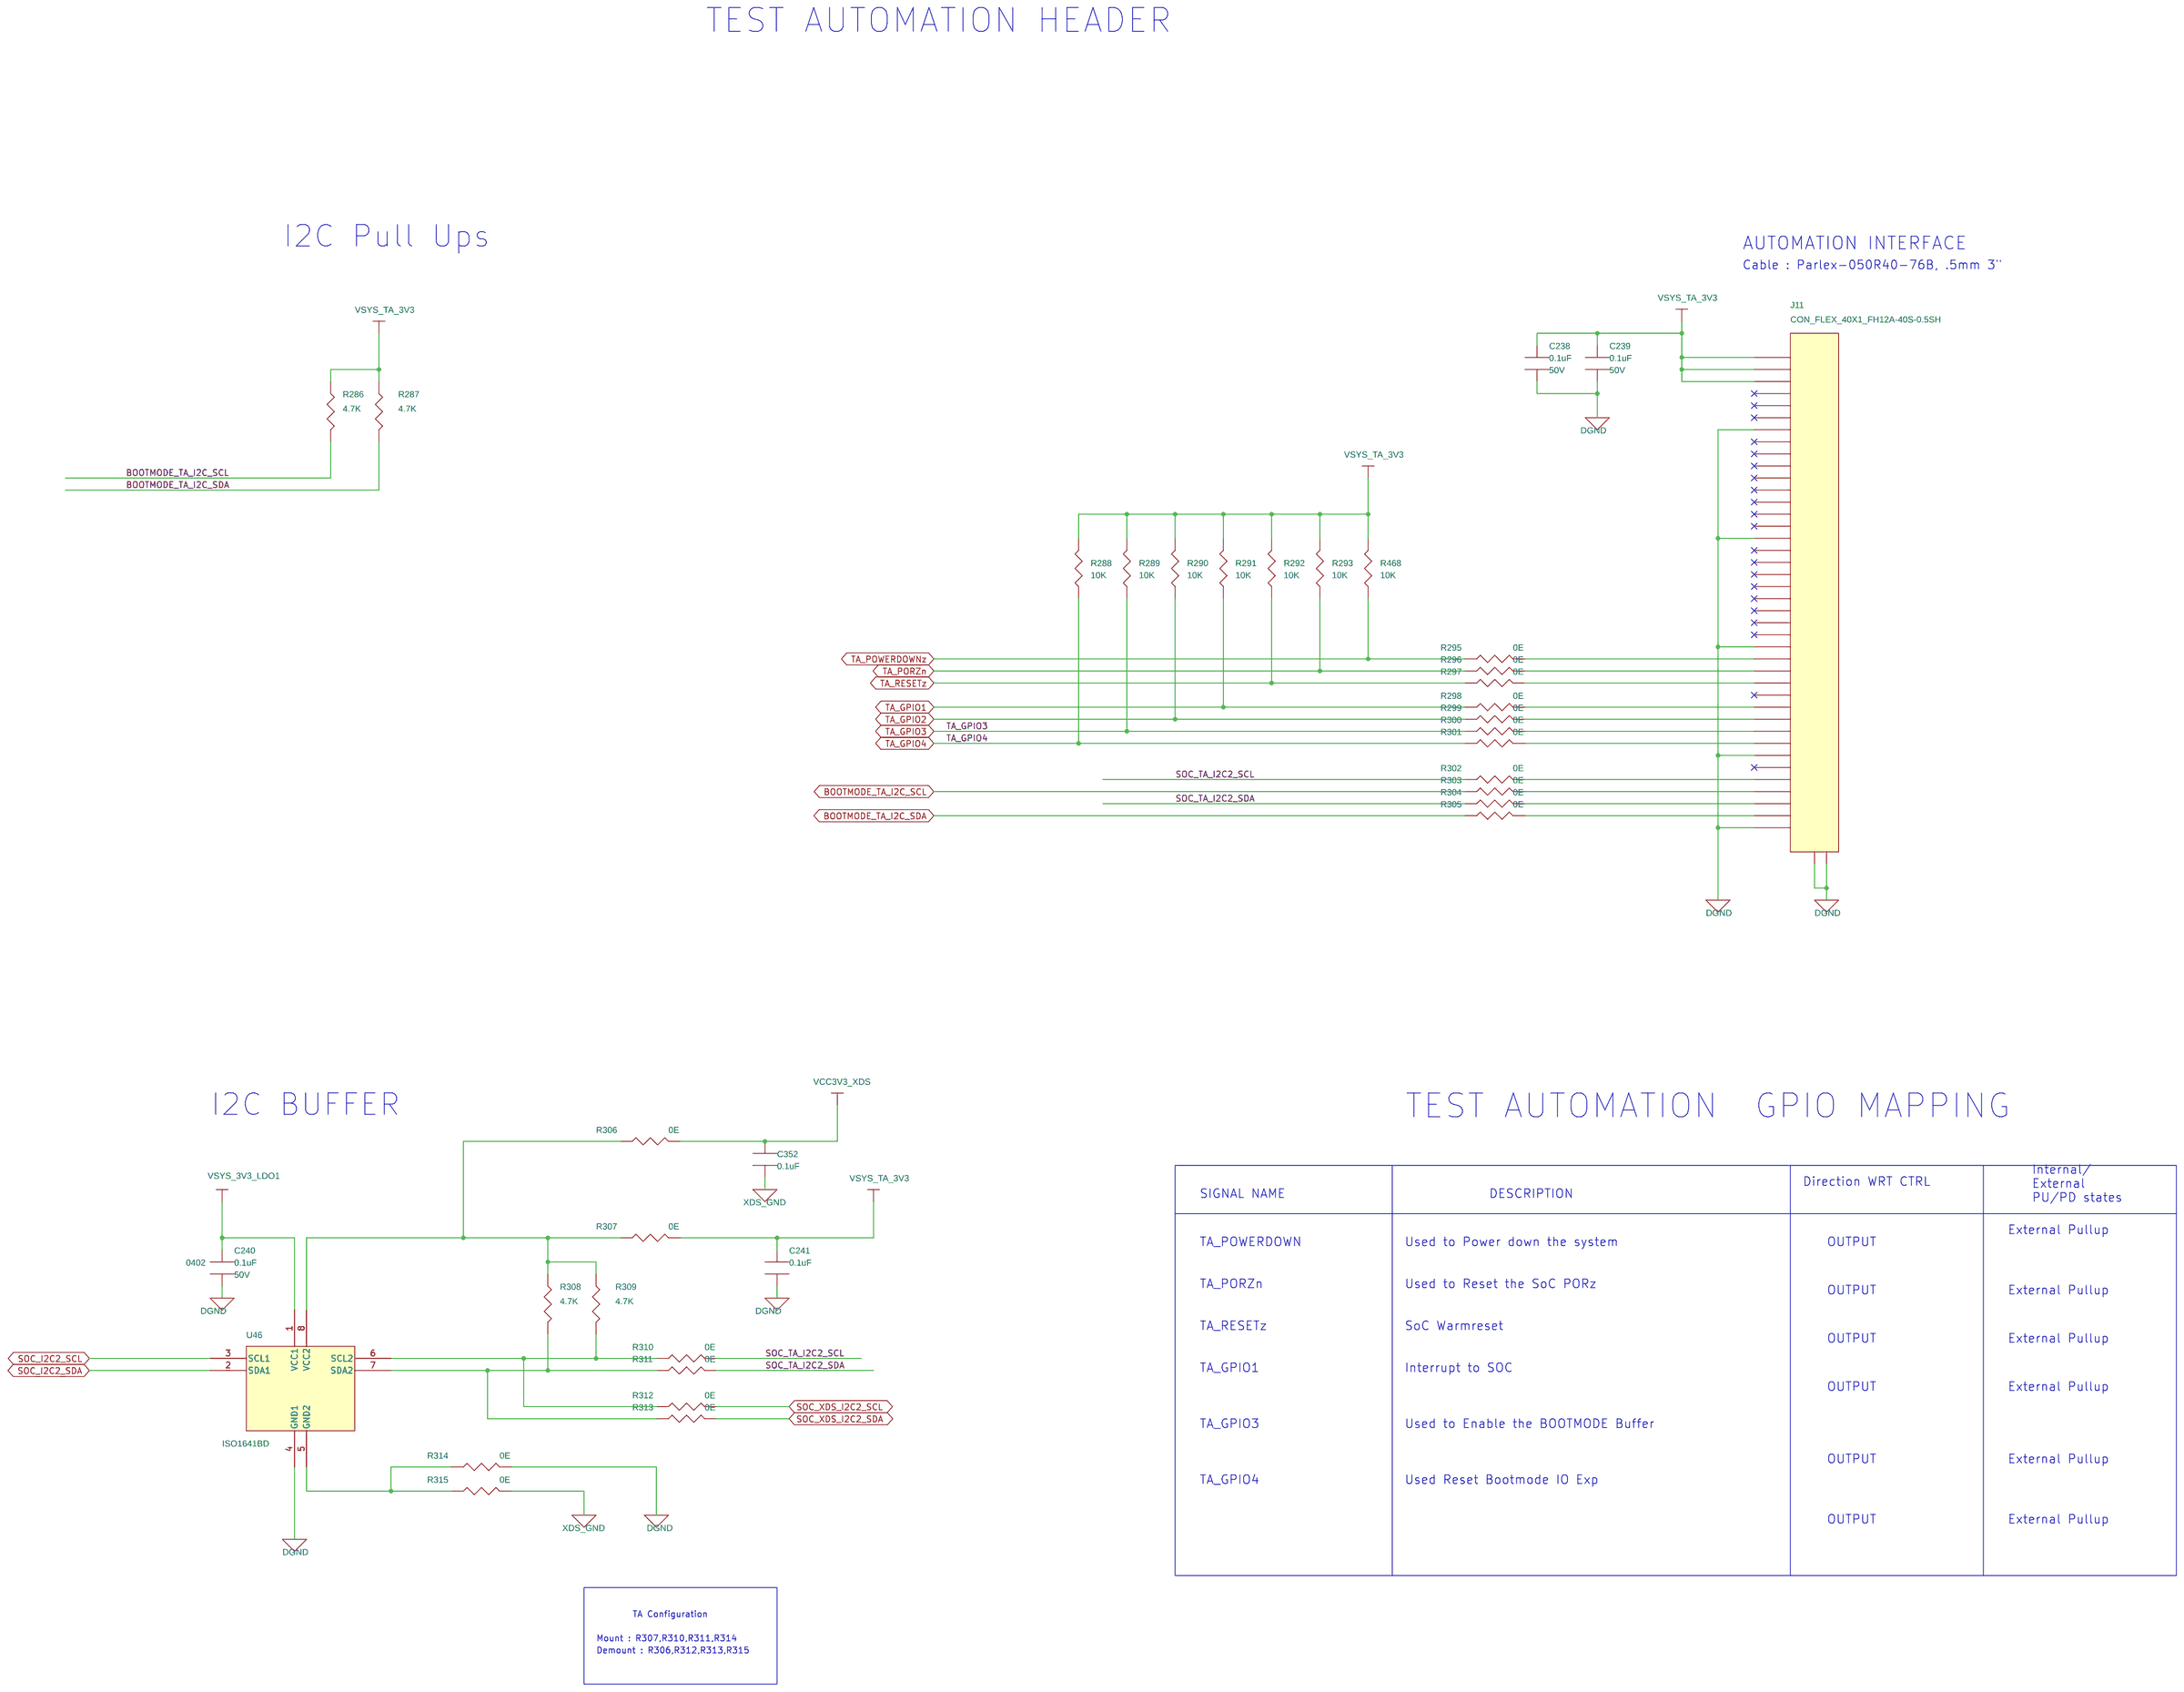
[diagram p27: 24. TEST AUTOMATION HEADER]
29 10. POWER SUPPLY #1: size C; title: POWER SUPPLY #1
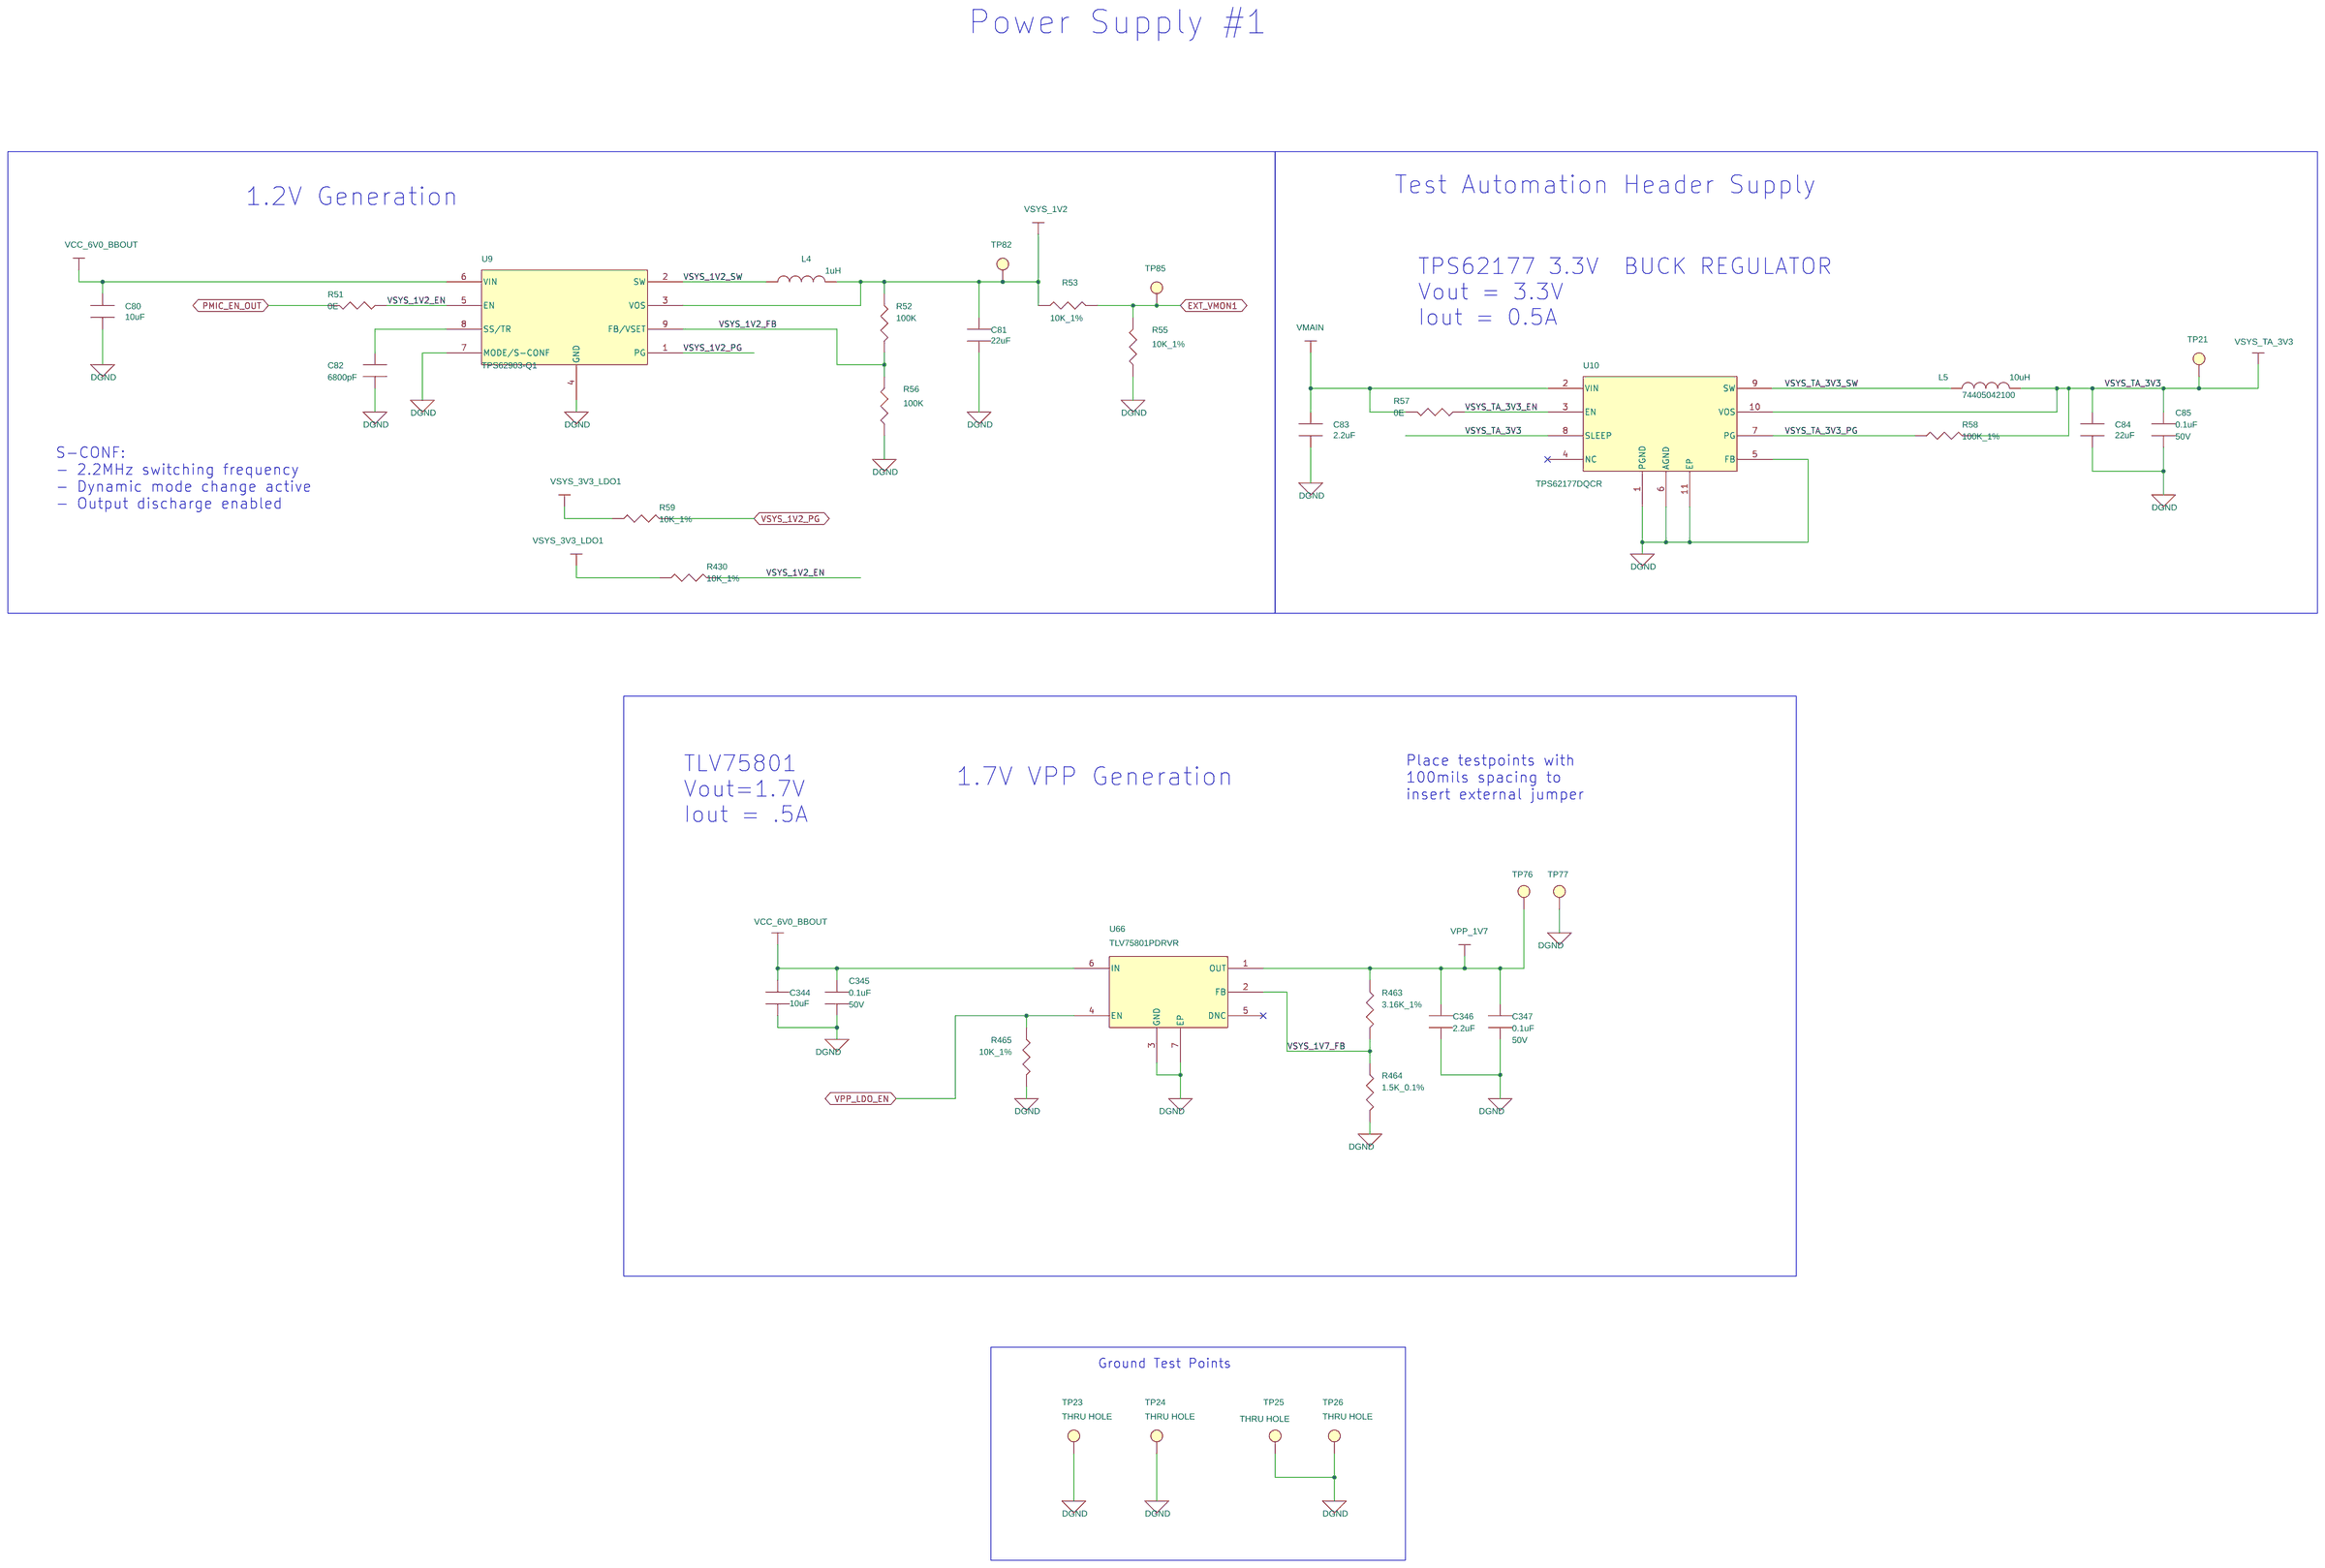
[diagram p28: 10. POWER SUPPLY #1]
30 09. BLACKBIRD PMIC: size C; title: BLACKBIRD PMIC

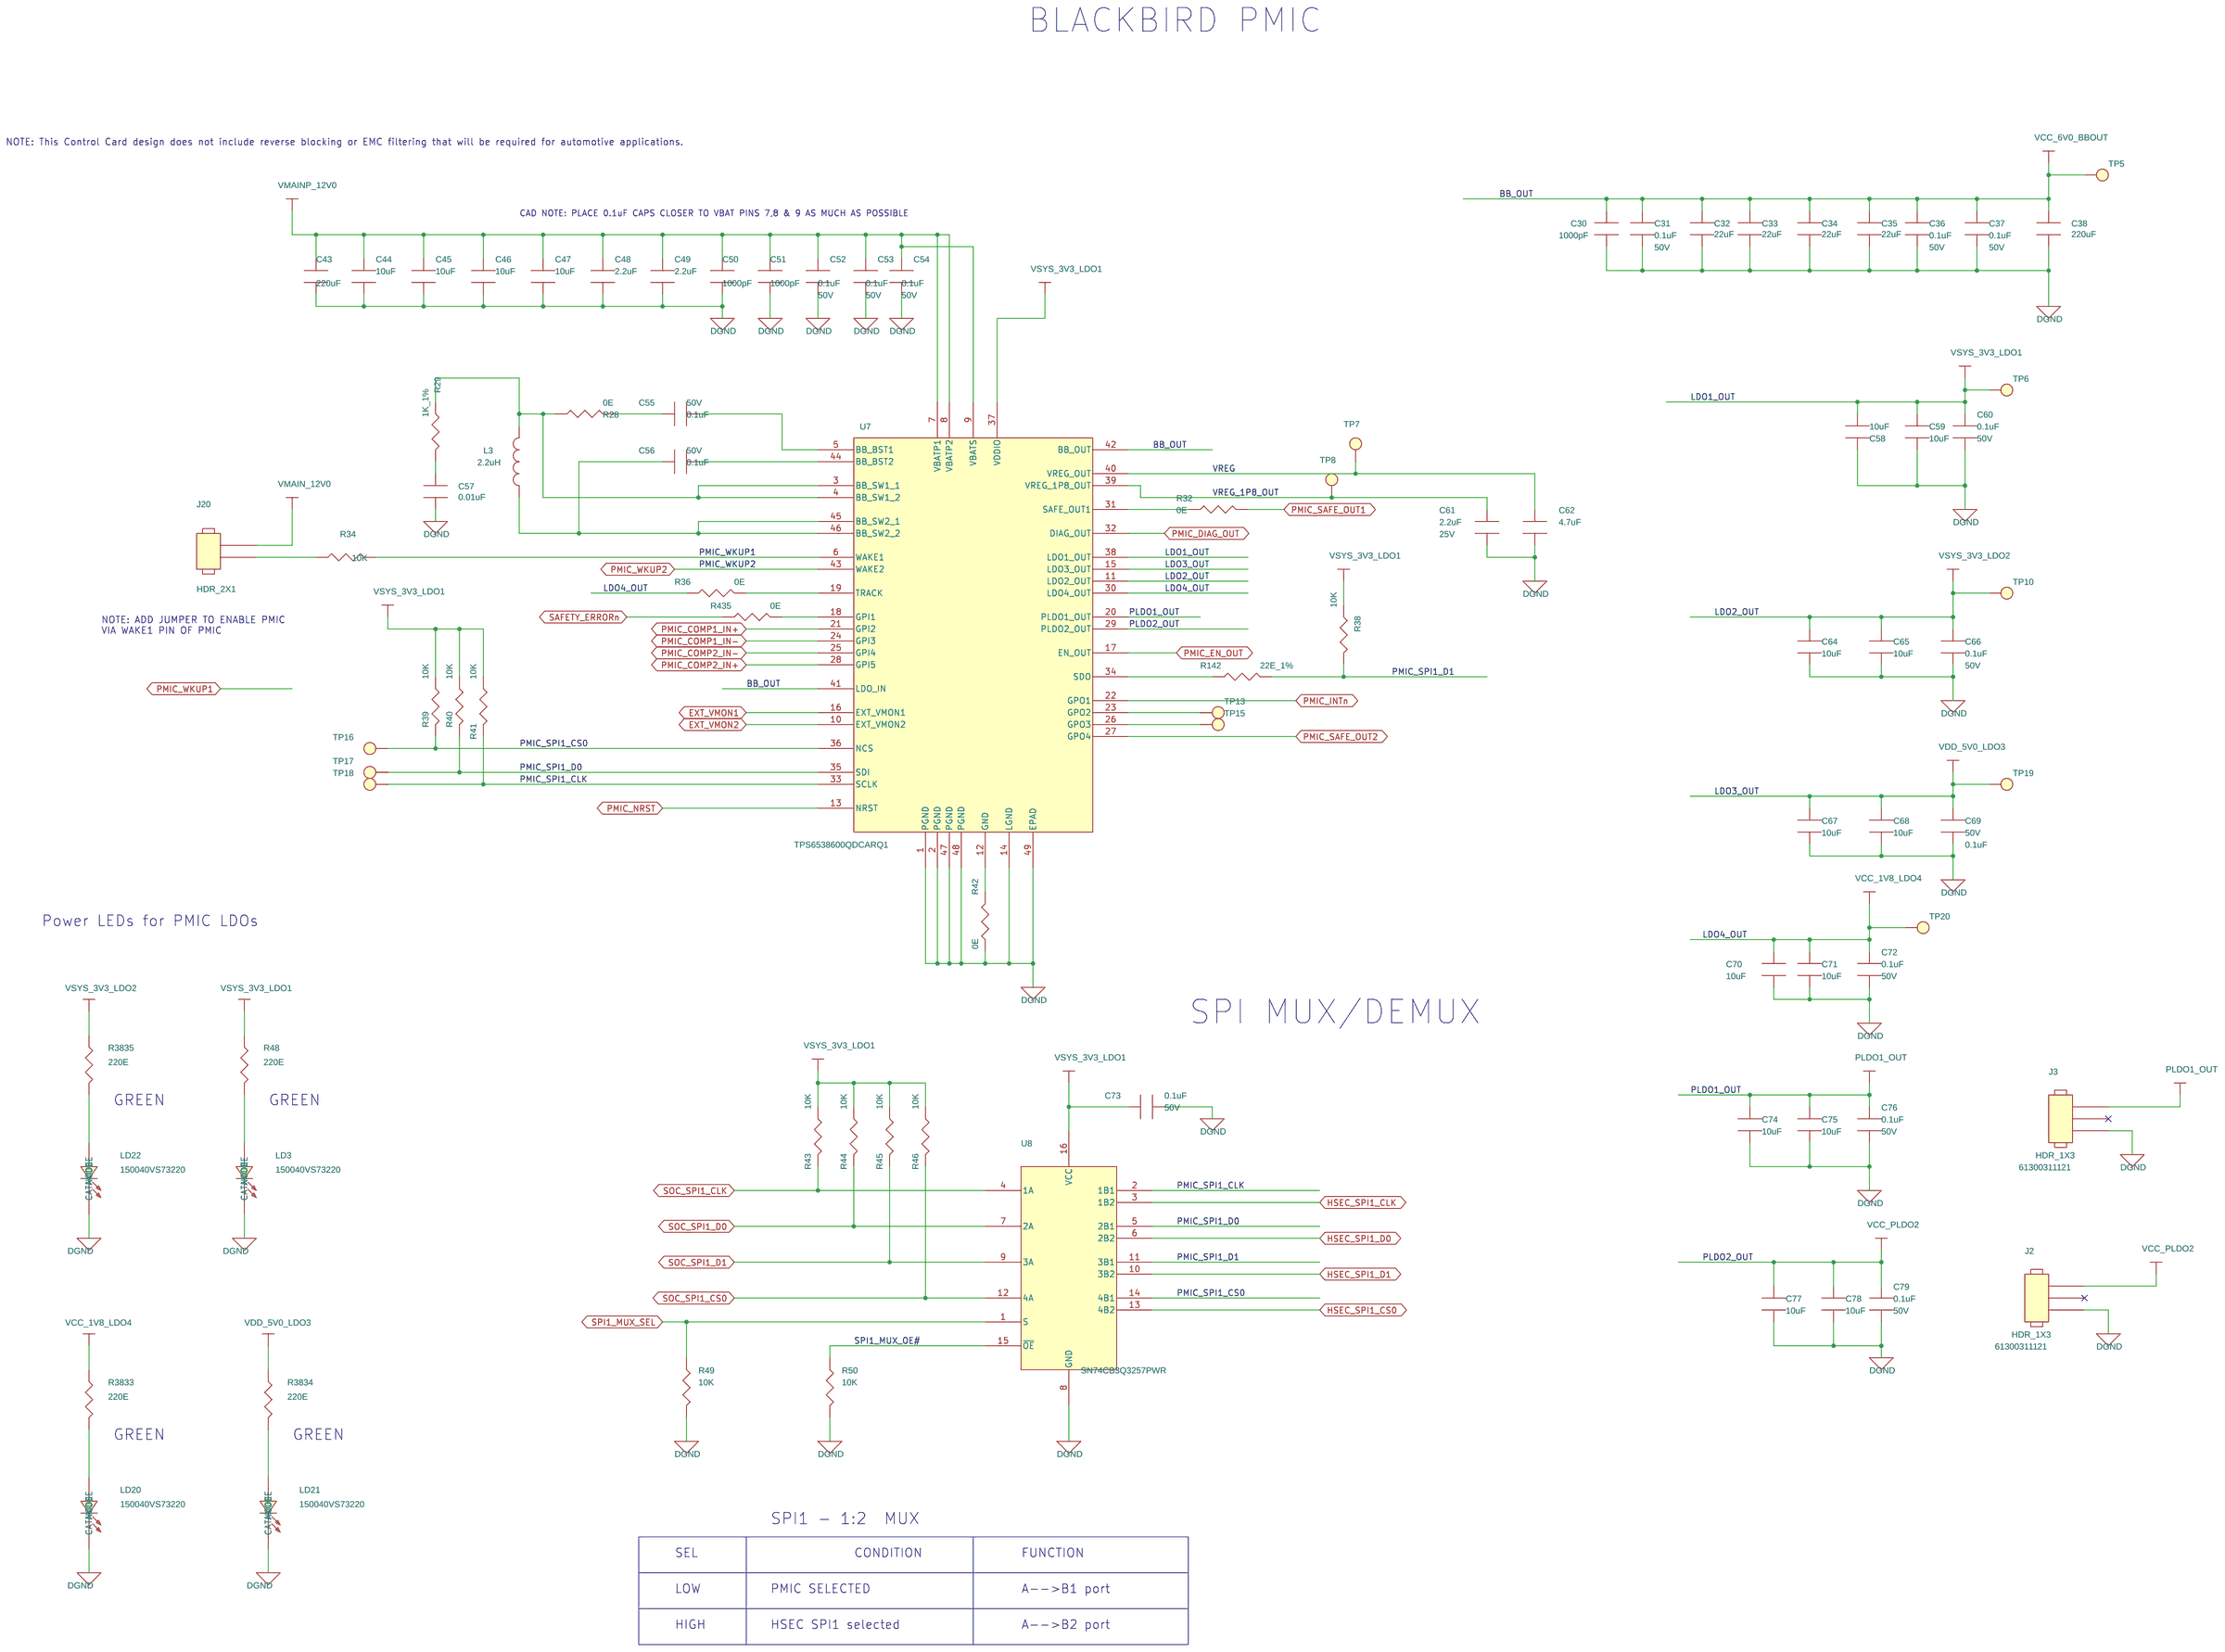
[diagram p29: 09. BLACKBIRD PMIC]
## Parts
sheet 09. BLACKBIRD PMIC
C30  1000pF  [CAP0402_0-75]
C31  0.1uF  [CAP0402_0-75]
C32  22uF  [CAP0805_1-5]
C33  22uF  [CAP0805_1-5]
C34  22uF  [CAP0805_1-5]
C35  22uF  [CAP0805_1-5]
C36  0.1uF  [CAP0402_0-75]
C37  0.1uF  [CAP0402_0-75]
C38  220uF  [CAP1206_2]
C43  220uF  [CAP1206_2]
C44  10uF  [CAP0805_1-5]
C45  10uF  [CAP0805_1-5]
C46  10uF  [CAP0805_1-5]
C47  10uF  [CAP0805_1-5]
C48  2.2uF  [CAP0402_0-75]
C49  2.2uF  [CAP0402_0-75]
C50  1000pF  [CAP0402_0-75]
C51  1000pF  [CAP0402_0-75]
C52  0.1uF  [CAP0402_0-75]
C53  0.1uF  [CAP0402_0-75]
C54  0.1uF  [CAP0402_0-75]
C55  0.1uF  [CAP0402_0-75]
C56  0.1uF  [CAP0402_0-75]
C57  0.01uF  [CAP0402_0-75]
C58  10uF  [CAP0805_1-5]
C59  10uF  [CAP0805_1-5]
C60  0.1uF  [CAP0402_0-75]
C61  2.2uF  [CAP0402_0-75]
C62  4.7uF  [CAP0402_0-75]
C64  10uF  [CAP0805_1-5]
C65  10uF  [CAP0805_1-5]
C66  0.1uF  [CAP0402_0-75]
C67  10uF  [CAP0805_1-5]
C68  10uF  [CAP0805_1-5]
C69  0.1uF  [CAP0402_0-75]
C70  10uF  [CAP0805_1-5]
C71  10uF  [CAP0805_1-5]
C72  0.1uF  [CAP0402_0-75]
C73  0.1uF  [CAP0402_0-75]
C74  10uF  [CAP0805_1-5]
C75  10uF  [CAP0805_1-5]
C76  0.1uF  [CAP0402_0-75]
C77  10uF  [CAP0805_1-5]
C78  10uF  [CAP0805_1-5]
C79  0.1uF  [CAP0402_0-75]
J2  HDR_1X3  [HDR_1X3_100_S_T]
J3  HDR_1X3  [HDR_1X3_100_S_T]
J20  HDR_2X1  [HDR_2X1_100_S_T_10-8]
L3  2.2uH  [IND_IHLP2020B_230X215_SMD]
LD3  150040VS73220  [LED_150040GS73220_40X20_SMD_0-4]
LD20  150040VS73220  [LED_150040GS73220_40X20_SMD_0-4]
LD21  150040VS73220  [LED_150040GS73220_40X20_SMD_0-4]
LD22  150040VS73220  [LED_150040GS73220_40X20_SMD_0-4]
R28  0E  [RES0402_0-5]
R29  1K_1%  [RES0402_0-5]
R32  0E  [RES0402_0-5]
R34  10K  [RES0402_0-5]
R36  0E  [RES0402_0-5]
R38  10K  [RES0402_0-5]
R39  10K  [RES0402_0-5]
R40  10K  [RES0402_0-5]
R41  10K  [RES0402_0-5]
R42  0E  [RES0402_0-5]
R43  10K  [RES0402_0-5]
R44  10K  [RES0402_0-5]
R45  10K  [RES0402_0-5]
R46  10K  [RES0402_0-5]
R48  220E  [RES0402_0-5]
R49  10K  [RES0402_0-5]
R50  10K  [RES0402_0-5]
R142  22E_1%  [RES0402_0-5]
R435  0E  [RES0402_0-5]
R3833  220E  [RES0402_0-5]
R3834  220E  [RES0402_0-5]
R3835  220E  [RES0402_0-5]
TP5  TP40_SMD  [TP40_SMD]
TP6  TP40_SMD  [TP40_SMD]
TP7  TP20_SMD  [TP20_SMD]
TP8  TP20_SMD  [TP20_SMD]
TP10  TP40_SMD  [TP40_SMD]
TP13  TP20_SMD  [TP20_SMD]
TP15  TP20_SMD  [TP20_SMD]
TP16  TP20_SMD  [TP20_SMD]
TP17  TP20_SMD  [TP20_SMD]
TP18  TP20_SMD  [TP20_SMD]
TP19  TP40_SMD  [TP40_SMD]
TP20  TP40_SMD  [TP40_SMD]
U7  TPS6538600QDCARQ1  [HTSSOP48_19-68_500X245_1-2]
U8  SN74CB3Q3257PWR  [TSSOP16_25-59_205X180]
sheet 10. POWER SUPPLY #1
C80  10uF  [CAP0805_1-5]
C81  22uF  [CAP0805_1-5]
C82  6800pF  [CAP0402_0-75]
C83  2.2uF  [CAP0402_0-75]
C84  22uF  [CAP0805_1-5]
C85  0.1uF  [CAP0402_0-75]
C344  10uF  [CAP1206_2]
C345  0.1uF  [CAP0402_0-75]
C346  2.2uF  [CAP0402_0-75]
C347  0.1uF  [CAP0402_0-75]
L4  1uH  [IND_XAL4020_170X170_SMD_3-1]
L5  10uH  [IND_74405042100_170X170_SMD_2]
R51  0E  [RES0402_0-5]
R52  100K  [RES0402_0-5]
R53  10K_1%  [RES0402_0-5]
R55  10K_1%  [RES0402_0-5]
R56  100K  [RES0402_0-5]
R57  0E  [RES0402_0-5]
R58  100K_1%  [RES0402_0-5]
R59  10K_1%  [RES0402_0-5]
R430  10K_1%  [RES0402_0-5]
R463  3.16K_1%  [RES0402_0-5]
R464  1.5K_0.1%  [RES0402_0-5]
R465  10K_1%  [RES0402_0-5]
TP21  TP40_SMD  [TP40_SMD]
TP23  THRU HOLE  [TP_40X65]
TP24  THRU HOLE  [TP_40X65]
TP25  THRU HOLE  [TP_40X65]
TP26  THRU HOLE  [TP_40X65]
TP76  THRU HOLE  [TP_40X65]
TP77  THRU HOLE  [TP_40X65]
TP82  TP40_SMD  [TP40_SMD]
TP85  TP40_SMD  [TP40_SMD]
U9  TPS62903-Q1  [VQFNHR9_TPS62903_80X90_1-1]
U10  TPS62177DQCR  [WSON10_19-68_80X120_0-8]
U66  TLV75801PDRVR  [SON6_25-59_85X85_0-8]
sheet 24. TEST AUTOMATION HEADER
C238  0.1uF  [CAP0402_0-75]
C239  0.1uF  [CAP0402_0-75]
C240  0.1uF  [CAP0402_0-75]
C241  0.1uF  [CAP0402_0-75]
C352  0.1uF  [CAP0402_0-75]
J11  CON_FLEX_40X1_FH12A-40S-0.5SH  [CON_FLEX40X1_FH12A_S_R_S]
R286  4.7K  [RES0402_0-5]
R287  4.7K  [RES0402_0-5]
R288  10K  [RES0402_0-5]
R289  10K  [RES0402_0-5]
R290  10K  [RES0402_0-5]
R291  10K  [RES0402_0-5]
R292  10K  [RES0402_0-5]
R293  10K  [RES0402_0-5]
R295  0E  [RES0201_0-5]
R296  0E  [RES0201_0-5]
R297  0E  [RES0201_0-5]
R298  0E  [RES0201_0-5]
R299  0E  [RES0201_0-5]
R300  0E  [RES0201_0-5]
R301  0E  [RES0201_0-5]
R302  0E  [RES0201_0-5]
R303  0E  [RES0201_0-5]
R304  0E  [RES0201_0-5]
R305  0E  [RES0201_0-5]
R306  0E  [RES0201_0-5]
R307  0E  [RES0201_0-5]
R308  4.7K  [RES0402_0-5]
R309  4.7K  [RES0402_0-5]
R310  0E  [RES0201_0-5]
R311  0E  [RES0201_0-5]
R312  0E  [RES0201_0-5]
R313  0E  [RES0201_0-5]
R314  0E  [RES0201_0-5]
R315  0E  [RES0201_0-5]
R468  10K  [RES0402_0-5]
U46  ISO1641BD  [SOIC8_1-8]

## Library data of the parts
C30 C50 C51 = CAP: CAP CERAMIC 1000pF 50V 5% C0G(NP0) 0402; Chkd/date: VASANTHA/281216; Crtd /date: MAZHAR/290806; Custom_Duty: 15%; Customs_HS_Code: 85322990; Distributor_name: DIGIKEY; Distributor_part_number: 490-3244-1-ND; Footprint Path: Y:\MIS_DATABASE\Library\ALTIUM_TOOL\PCB_FOOTPRINTS\Altium_Footprint_Lib.PcbLib; Height: 0.55MM; Library Path: Y:\MIS_DATABASE\Library\ALTIUM_TOOL\SCHEMATICS_PARTS\MS_DISCRETE_Library.schlib; Mfr_name: MURATA; Mfr_part_number: GRM1555C1H102JA01D; Mistral Part No: 120016110009-R; Package: 0402; Part_type: CAPACITORS\CERAMIC; Project: SVDO_RMB_MMA; RoHS: RoHS; Temperature: -55°C+125°C; Tolerance: 5%; Voltage: 50V; Wattage: NA; Weight: 6mg; Datasheet: Y:\MIS_DATABASE\DATASHEETS\CAPACITORS\MURATA-GXX-SER_NOV17.PDF
C31 C36 C37 C52-C56 C60 C66 C69 C72 C73 C76 C79 C85 C238 C239 = CAP: CAP CERAMIC 0.1uF 50V 10% X7R 0402; Automotive Alternate_mfr_name: TDK; Automotive Alternate_mfr_part_number: CGA2B3X7R1H104K050BB; Chkd/date: MANIRAJA/261020; Crtd /date: ALVY/211020; Custom_Duty: 15%; Customs_HS_Code: 85322990; Direct Alternate_mfr_name: TDK; Direct Alternate_mfr_part_number: C1005X7R1H104K050BE; Distributor_name: DIGIKEY; Distributor_part_number: 490-10700-1-ND; Footprint Path: Y:\MIS_DATABASE\Library\ALTIUM_TOOL\PCB_FOOTPRINTS\Altium_Footprint_Lib.PcbLib; Height: 0.55MM; Library Path: Y:\MIS_DATABASE\Library\ALTIUM_TOOL\SCHEMATICS_PARTS\MS_DISCRETE_Library.schlib; Mfr_name: MURATA; Mfr_part_number: GRM155R71H104KE14D; Mistral Part No: 120011100014-R; Package: 0402; Part_type: CAPACITORS\CERAMIC; Project: J7_CP; RoHS: RoHS; Temperature: -55°C+125°C; Tolerance: 10%; Voltage: 50V; Wattage: NA; Weight: 3.1mg; Datasheet: Y:\MIS_DATABASE\DATASHEETS\CAPACITORS\GRM155R71H104KE14.PDF
C32-C35 C81 C84 = CAP: CAP CERAMIC 22uF 25V 20% X5R 0805; Chkd/date: MANIRAJA/110718; Crtd /date: ALVY/110718; Custom_Duty: 15%; Customs_HS_Code: 85322990; Distributor_name: DIGIKEY; Distributor_part_number: 490-14661-1-ND; Footprint Path: Y:\MIS_DATABASE\Library\ALTIUM_TOOL\PCB_FOOTPRINTS\Altium_Footprint_Lib.PcbLib; Height: 1.45MM; Library Path: Y:\MIS_DATABASE\Library\ALTIUM_TOOL\SCHEMATICS_PARTS\MS_DISCRETE_Library.schlib; Mfr_name: MURATA; Mfr_part_number: GRM21BR61E226ME44K; Mistral Part No: 120013120018-R; Package: 0805; Part_type: CAPACITORS\CERAMIC; Project: TI_J7SVB_PCIE_ADD-ON-CARD; RoHS: RoHS; Temperature: -55°C+85°C; Tolerance: 20%; Voltage: 25V; Wattage: NA; Weight: 9.5mg; Datasheet: Y:\MIS_DATABASE\DATASHEETS\CAPACITORS\GRM21BR61E226ME44K.PDF
C38 C43 = CAP: CAP CERAMIC 220uF 6.3V 20% X5R 1206; Chkd/date: MANIRAJA/260421; Crtd /date: ALVY/260421; Custom_Duty: 15%; Customs_HS_Code: 85322990; Distributor_name: DIGIKEY; Distributor_part_number: 490-13970-1-ND; Footprint Path: Y:\MIS_DATABASE\Library\ALTIUM_TOOL\PCB_FOOTPRINTS\Altium_Footprint_Lib.PcbLib; Height: 1.90MM; Library Path: Y:\MIS_DATABASE\Library\ALTIUM_TOOL\SCHEMATICS_PARTS\MS_DISCRETE_Library.schlib; Mfr_name: MURATA; Mfr_part_number: GRM31CR60J227ME11L; Mistral Part No: 120021040030-R; Package: 1206; Part_type: CAPACITORS\CERAMIC; Project: SP_EP2_RX BRD; RoHS: RoHS; Temperature: -55°C+85°C; Tolerance: 20%; Voltage: 6.3V; Wattage: NA; Weight: 27mg; Datasheet: Y:\MIS_DATABASE\DATASHEETS\CAPACITORS\GRM31CR60J227ME11.PDF
C44-C47 C58 C59 C64 C65 C67 C68 C70 C71 C74 C75 C77 C78 C80 = CAP: CAP CERAMIC 10uF 50V 10% X5R 0805; Chkd/date: MANIRAJA/010321; Crtd /date: ALVY/010321; Custom_Duty: 15%; Customs_HS_Code: 85322990; Distributor_name: DIGIKEY; Distributor_part_number: 490-18663-1-ND; Footprint Path: Y:\MIS_DATABASE\Library\ALTIUM_TOOL\PCB_FOOTPRINTS\Altium_Footprint_Lib.PcbLib; Height: 1.45MM; Library Path: Y:\MIS_DATABASE\Library\ALTIUM_TOOL\SCHEMATICS_PARTS\MS_DISCRETE_Library.schlib; Mfr_name: MURATA; Mfr_part_number: GRM21BR61H106KE43L; Mistral Part No: 120021030002-R; Package: 0805; Part_type: CAPACITORS\CERAMIC; Project: J7ES_SK_BRD; RoHS: RoHS; Temperature: -55°C+85°C; Tolerance: 10%; Voltage: 50V; Wattage: NA; Weight: 6.4mg; Datasheet: Y:\MIS_DATABASE\DATASHEETS\CAPACITORS\GRM21BR61H106KE43.PDF
C48 C49 C61 = CAP: CAP CERAMIC 2.2uF 25V 10% X5R 0402; Automotive Alternate_mfr_name: TAIYO YUDEN; Automotive Alternate_mfr_part_number: LMK105ABJ225MVHF; Chkd/date: ALVY/010721; Crtd /date: MANIRAJA/010721; Custom_Duty: 15%; Customs_HS_Code: 85322990; Direct Alternate_mfr_name: TDK; Direct Alternate_mfr_part_number: C1005X5R1A225K050BC; Distributor_name: DIGIKEY; Distributor_part_number: 490-12703-1-ND; Footprint Path: Y:\MIS_DATABASE\Library\ALTIUM_TOOL\PCB_FOOTPRINTS\Altium_Footprint_Lib.PcbLib; Height: 0.70MM; Library Path: Y:\MIS_DATABASE\Library\ALTIUM_TOOL\SCHEMATICS_PARTS\MS_DISCRETE_Library.schlib; Mfr_name: MURATA; Mfr_part_number: GRM155R61E225KE11D; Mistral Part No: 120015120001-R; Package: 0402; Part_type: CAPACITORS\CERAMIC; Project: TI_AM263X_CC; RoHS: RoHS; Temperature: -55°C+85°C; Tolerance: 10%; Voltage: 25V; Wattage: NA; Weight: 1.5mg; Datasheet: Y:\MIS_DATABASE\DATASHEETS\CAPACITORS\GRM155R61E225KE11.PDF
C57 = CAP: CAP CERAMIC 0.01uF 25V 10% X7R AUTO 0402; Chkd/date: ALVY/200421; Crtd /date: MANIRAJA/200421; Custom_Duty: 15%; Customs_HS_Code: 85322990; Distributor_name: DIGIKEY; Distributor_part_number: 490-6043-1-ND; Footprint Path: Y:\MIS_DATABASE\Library\ALTIUM_TOOL\PCB_FOOTPRINTS\Altium_Footprint_Lib.PcbLib; Height: 0.55MM; Library Path: Y:\MIS_DATABASE\Library\ALTIUM_TOOL\SCHEMATICS_PARTS\MS_DISCRETE_Library.schlib; Mfr_name: MURATA; Mfr_part_number: GCM155R71E103KA37D; Mistral Part No: 120021040005-R; Package: 0402; Part_type: CAPACITORS\CERAMIC; Project: IWR6843ISK LOW FR4 PROTO; RoHS: RoHS; Temperature: -55°C+125°C; Tolerance: 10%; Voltage: 25V; Wattage: NA; Weight: 6mg; Datasheet: Y:\MIS_DATABASE\DATASHEETS\CAPACITORS\GCM155R71E103KA37.PDF
C62 = CAP: CAP CERAMIC 4.7uF 10V 20% X5R 0402; Chkd/date: MANIRAJA/110718; Crtd /date: ALVY/110718; Custom_Duty: 15%; Customs_HS_Code: 85322990; Distributor_name: DIGIKEY; Distributor_part_number: 490-14306-1-ND; Footprint Path: Y:\MIS_DATABASE\Library\ALTIUM_TOOL\PCB_FOOTPRINTS\Altium_Footprint_Lib.PcbLib; Height: 0.65MM; Library Path: Y:\MIS_DATABASE\Library\ALTIUM_TOOL\SCHEMATICS_PARTS\MS_DISCRETE_Library.schlib; Mfr_name: MURATA; Mfr_part_number: GRM155R61A475MEAAD; Mistral Part No: 120012060002-R; Package: 0402; Part_type: CAPACITORS\CERAMIC; Project: TI_J7SVB_PCIE_ADD-ON-CARD; RoHS: RoHS; Temperature: -55°C+85°C; Tolerance: 20%; Voltage: 10V; Wattage: NA; Weight: 14mg; Datasheet: Y:\MIS_DATABASE\DATASHEETS\CAPACITORS\GRM155R61A475MEAAD.PDF
J2 J3 = HEADER_3X1: CON HDR 1X3 2.54MM PITCH ST TH; Chkd/date: VASANTHA/211015; Crtd /date: VASANTHA/211015; Custom_Duty: 24%; Customs_HS_Code: 85369090; Distributor_name: DIGIKEY; Distributor_part_number: 732-5316-ND; Height: 8.54MM; Mfr_name: WURTH ELECTRONICS INC; Mfr_part_number: 61300311121; Mistral Part No: 150015100037-R; Package: THRU-HOLE; Part_type: CONNECTOR\HEADERS; Project: CYPHY_ROADKILL; RoHS: RoHS; Temperature: NA; Tolerance: NA; Voltage: NA; Wattage: NA; Weight: NA; Datasheet: Y:\MIS_DATABASE\DATASHEETS\CONNECTORS\6130XXX.PDF
J20 = HEADER_2X1: CON HDR 2X1 2.54MM PITCH ST TH; Chkd/date: VASANTHA/060117; Crtd /date: MAZHAR/280405; Custom_Duty: 24%; Customs_HS_Code: 85369090; Distributor_name: DIGIKEY; Distributor_part_number: WM4000-ND; Footprint Path: Y:\MIS_DATABASE\Library\ALTIUM_TOOL\PCB_FOOTPRINTS\Altium_Footprint_Lib.PcbLib; Height: 10.79MM; Library Path: Y:\MIS_DATABASE\Library\ALTIUM_TOOL\SCHEMATICS_PARTS\MS_CONNECTOR_Library.schlib; Mfr_name: MOLEX; Mfr_part_number: 22-03-2021; Mistral Part No: 150009030246-R; Package: THRU-HOLE; Part_type: CONNECTOR\HEADERS; Project: FPGA EXTENDER CARD; RoHS: RoHS; Temperature: -0°C+75°C; Tolerance: NA; Voltage: NA; Wattage: NA; Weight: 139gm; Datasheet: Y:\MIS_DATABASE\DATASHEETS\CONNECTORS\HEADER_X4030.PDF
L3 = INDUCTOR: IND POWER 2.2uH 4.2A 20% SMD; Chkd/date: MAZHAR/220310; Crtd /date: MUDDU/080310; Custom_Duty: 24%; Customs_HS_Code: 85437099; Distributor_name: DIGIKEY; Distributor_part_number: 541-1088-1-ND; Height: 2.00MM; Mfr_name: VISHAY; Mfr_part_number: IHLP2020BZER2R2M01; Mistral Part No: 130010030009-R; Package: SMD; Project: VME_DSP_SUITE; RoHS: RoHS; Temperature: -55°C+125°C; Tolerance: 20%; Weight: NA; Datasheet: Y:\MIS_DATABASE\DATASHEETS\DISCRETES\INDUCTORS\IHLP2020B.PDF
LD3 LD20-LD22 = DIODE_LED: DIODE LED BRIGHT GREEN SMD; Chkd/date: MANIRAJA/261120; Crtd /date: ALVY/261120; Custom_Duty: 24%; Customs_HS_Code: 85439000; Distributor_name: DIGIKEY; Distributor_part_number: 732-13425-1-ND; Footprint Path: Y:\MIS_DATABASE\Library\ALTIUM_TOOL\PCB_FOOTPRINTS\Altium_Footprint_Lib.PcbLib; Height: 0.35MM; Library Path: Y:\MIS_DATABASE\Library\ALTIUM_TOOL\SCHEMATICS_PARTS\MS_OPTO_Library.schlib; Mfr_name: WURTH ELECTRONIK; Mistral Part No: 130020110071-R; Package: SMD; Part_type: OPTO\LED; Project: AM64X_SKEVM; RoHS: RoHS; Temperature: -40°C+85°C; Tolerance: NA; Voltage: NA; Wattage: NA; Weight: 29.3mg; Datasheet: Y:\MIS_DATABASE\DATASHEETS\DISCRETES\LEDS\150040VS73220.PDF
R28 R32 R36 R42 R51 R57 R435 = RESISTOR: RES 0E 1/10W JUMPER 0402; Chkd/date: VASANTHA/061216; Crtd /date: NAVEED/201014; Custom_Duty: 15%; Customs_HS_Code: 85332119; Distributor_name: DIGIKEY; Distributor_part_number: P0.0JCT-ND; Footprint Path: Y:\MIS_DATABASE\Library\ALTIUM_TOOL\PCB_FOOTPRINTS\Altium_Footprint_Lib.PcbLib; Height: 0.40MM; IBISSP_MODLES: VALUE REPEATING 2 TIME; Library Path: Y:\MIS_DATABASE\Library\ALTIUM_TOOL\SCHEMATICS_PARTS\MS_DISCRETE_Library.schlib; Mfr_name: PANASONIC-ECG; Mfr_part_number: ERJ-2GE0R00X; Mistral Part No: 110018030052-R; Package: 0402; Part_type: RESISTORS\FIXED; Project: AEGIS POM; RoHS: RoHS; Temperature: -55°C+155°C; Tolerance: NA; Voltage: NA; Wattage: 1/10W; Weight: 0.8mg; Datasheet: Y:\MIS_DATABASE\DATASHEETS\RESISTORS\PAN-ERJSER_NOV17.PDF
R29 = RESISTOR: RES 1K 1/10W 1% 0402; Chkd/date: VASANTHA/281216; Crtd /date: MAZHAR/150506; Custom_Duty: 15%; Customs_HS_Code: 85332119; Distributor_name: DIGIKEY; Distributor_part_number: P1.00KLCT-ND; Footprint Path: Y:\MIS_DATABASE\Library\ALTIUM_TOOL\PCB_FOOTPRINTS\Altium_Footprint_Lib.PcbLib; Height: 0.40MM; Library Path: Y:\MIS_DATABASE\Library\ALTIUM_TOOL\SCHEMATICS_PARTS\MS_DISCRETE_Library.schlib; Mfr_name: PANASONIC-ECG; Mfr_part_number: ERJ-2RKF1001X; Mistral Part No: 110009030411-R; Package: 0402; Part_type: RESISTORS\FIXED; Project: VOCERA; RoHS: RoHS; Temperature: -55°C+155°C; Tolerance: 1%; Voltage: NA; Wattage: 1/10W; Weight: 0.8mg; Datasheet: Y:\MIS_DATABASE\DATASHEETS\RESISTORS\PAN-ERJSER_NOV17.PDF
R34 R38-R41 R43-R46 R288-R293 R468 = RESISTOR: RES 10K 1/16W 5% 0402; Chkd/date: VASANTHA/061216; Crtd /date: MAZHAR/230805; Custom_Duty: 15%; Customs_HS_Code: 85332119; Distributor_name: DIGIKEY; Distributor_part_number: 311-10KJRCT-ND; Footprint Path: Y:\MIS_DATABASE\Library\ALTIUM_TOOL\PCB_FOOTPRINTS\Altium_Footprint_Lib.PcbLib; Height: 0.40MM; Library Path: Y:\MIS_DATABASE\Library\ALTIUM_TOOL\SCHEMATICS_PARTS\MS_DISCRETE_Library.schlib; Mfr_name: YAGEO AMERICA; Mfr_part_number: RC0402JR-0710KL; Mistral Part No: 110011060021-R; Package: 0402; Part_type: RESISTORS\FIXED; Project: HSE; RoHS: RoHS; Temperature: -55°C+155°C; Tolerance: 5%; Voltage: NA; Wattage: 1/16W; Weight: 0.65mg; Datasheet: Y:\MIS_DATABASE\DATASHEETS\RESISTORS\RCXXXXL-SER_MAR18.PDF
R48 R3833-R3835 = RESISTOR: RES 220E 1/10W 5% 0402; Chkd/date: VASANTHA/291216; Crtd /date: GEETHA/260406; Custom_Duty: 15%; Customs_HS_Code: 85332119; Distributor_name: DIGIKEY; Distributor_part_number: P220JCT-ND; Footprint Path: Y:\MIS_DATABASE\Library\ALTIUM_TOOL\PCB_FOOTPRINTS\Altium_Footprint_Lib.PcbLib; Height: 0.40MM; Library Path: Y:\MIS_DATABASE\Library\ALTIUM_TOOL\SCHEMATICS_PARTS\MS_DISCRETE_Library.schlib; Mfr_name: PANASONIC-ECG; Mfr_part_number: ERJ-2GEJ221X; Mistral Part No: 110009030506-R; Package: 0402; Part_type: RESISTORS\FIXED; Project: RED EYE; RoHS: RoHS; Temperature: -55°C+155°C; Tolerance: 5%; Voltage: NA; Wattage: 1/10W; Weight: 0.8mg; Datasheet: Y:\MIS_DATABASE\DATASHEETS\RESISTORS\PAN-ERJSER_NOV17.PDF
R49 R50 = RESISTOR: RES 10K 1/16W 5% 0402; Assembly_Instruction: DNI; Chkd/date: VASANTHA/061216; Crtd /date: MAZHAR/230805; Custom_Duty: 15%; Customs_HS_Code: 85332119; Distributor_name: DIGIKEY; Distributor_part_number: 311-10KJRCT-ND; Footprint Path: Y:\MIS_DATABASE\Library\ALTIUM_TOOL\PCB_FOOTPRINTS\Altium_Footprint_Lib.PcbLib; Height: 0.40MM; Library Path: Y:\MIS_DATABASE\Library\ALTIUM_TOOL\SCHEMATICS_PARTS\MS_DISCRETE_Library.schlib; Mfr_name: YAGEO AMERICA; Mfr_part_number: RC0402JR-0710KL; Mistral Part No: 110011060021-R; Package: 0402; Part_type: RESISTORS\FIXED; Project: HSE; RoHS: RoHS; Temperature: -55°C+155°C; Tolerance: 5%; Voltage: NA; Wattage: 1/16W; Weight: 0.65mg; Datasheet: Y:\MIS_DATABASE\DATASHEETS\RESISTORS\RCXXXXL-SER_MAR18.PDF
R142 = RESISTOR: RES 22E 1/10W 1% 0402; Chkd/date: MANIRAJA/270319; Crtd /date: MANIRAJA/270319; Custom_Duty: 15%; Customs_HS_Code: 85332119; Distributor_name: DIGIKEY; Distributor_part_number: P22.0LCT-ND; Footprint Path: Y:\MIS_DATABASE\Library\ALTIUM_TOOL\PCB_FOOTPRINTS\Altium_Footprint_Lib.PcbLib; Height: 0.40MM; Library Path: Y:\MIS_DATABASE\Library\ALTIUM_TOOL\SCHEMATICS_PARTS\MS_DISCRETE_Library.schlib; Mfr_name: PANASONIC-ECG; Mfr_part_number: ERJ-2RKF22R0X; Mistral Part No: 110019040025-R; Package: 0402; Part_type: RESISTORS\FIXED; Project: V8TS; RoHS: RoHS; Temperature: -55°C+155°C; Tolerance: 1%; Voltage: NA; Wattage: 1/10W; Weight: 0.8mg; Datasheet: Y:\MIS_DATABASE\DATASHEETS\RESISTORS\PAN-ERJSER_NOV17.PDF
TP5 TP6 TP10 TP19-TP21 TP82 TP85 = TESTPOINT: TESTPOINT CIR 40 SMD; Chkd/date: MAZHAR/190505; Crtd /date: MAZHAR/190505; Distributor_name: NA; Distributor_part_number: NA; Footprint Path: Y:\MIS_DATABASE\Library\ALTIUM_TOOL\PCB_FOOTPRINTS\Altium_Footprint_Lib.PcbLib; Height: NA; Library Path: Y:\MIS_DATABASE\Library\ALTIUM_TOOL\SCHEMATICS_PARTS\MS_DISCRETE_Library.schlib; MECHANICAL 3D STEP FILE: NA; Mfr_name: LOCAL; Mistral Part No: 130009030933; Package: SMD; Project: RAINIER-3; RoHS: NA; Temperature: NA; Tolerance: NA; Voltage: NA; Wattage: NA; Weight: NA; Datasheet: NA
TP7 TP8 TP13 TP15-TP18 = TESTPOINT: TESTPOINT CIR 20 SMD; Chkd/date: SHREESHAIL/171006; Crtd /date: MAZHAR/171006; Custom_Duty: NA; Customs_HS_Code: NA; Distributor_name: NA; Distributor_part_number: NA; Footprint Path: Y:\MIS_DATABASE\Library\ALTIUM_TOOL\PCB_FOOTPRINTS\Altium_Footprint_Lib.PcbLib; Height: NA; Library Path: Y:\MIS_DATABASE\Library\ALTIUM_TOOL\SCHEMATICS_PARTS\MS_DISCRETE_Library.schlib; MECHANICAL 3D STEP FILE: NA; Mfr_name: LOCAL; Mistral Part No: NA; Package: SMD; Project: BT MODULE_CSRBC04; RoHS: NA; Temperature: NA; Tolerance: NA; Voltage: NA; Wattage: NA; Weight: NA; Datasheet: NA
U7 = TPS6538600-Q1_HTSSOP48: IC POWER MANAGEMENT IC FOR SAFETY HTSSOP48; Chkd/date: PRAVEEN/100323; Crtd /date: PRAVEEN/100323; Custom_Duty: 15%; Customs_HS_Code: 85423100; Distributor_name: NA; Distributor_part_number: NA; Height: 1.20MM; Mfr_name: TEXAS INSTRUMENTS; Mistral Part No: 142023030004-R; Package: HTSSOP48; Part_type: ICS\POWER\MANAGEMENT; Project: AM263P_CC; RoHS: RoHS; Temperature: -40°C+125°C; Tolerance: NA; Voltage: NA; Wattage: NA; Weight: NA; Datasheet: Y:\MIS_DATABASE\DATASHEETS\ICS\POWER\TPS6538600QDCARQ1.PDF
U8 = SN74CB3Q3257PWR_TSSOP16: IC 4BIT 1-OF-2 FET MULTIPLEXER/DEMULTIPLEXER TSSOP16; Chkd/date: SUHAS/251010; Crtd /date: USMAN/060109; Custom_Duty: 15%; Customs_HS_Code: 85423100; Distributor_name: DIGIKEY; Distributor_part_number: 296-19138-1-ND; Height: 1.20MM; Mfr_name: TEXAS INSTRUMENTS; Mistral Part No: 141009030117-R; Package: TSSOP16; Part_type: ICS\DIGITAL\COMBINATIONAL; Project: OMAP_EVM; RoHS: Sb/ Br FREE; Temperature: -40°C+85°C; Datasheet: Y:\MIS_DATABASE\DATASHEETS\ICS\DIGITAL\COMBINATIONAL\SN74CB3Q3257.PDF
C82 = CAP: CAP CERAMIC 6800pF 25V 5% X7R 0402; Chkd/date: VASANTHA/211215; Crtd /date: VASANTHA/211215; Custom_Duty: 15%; Customs_HS_Code: 85322990; Distributor_name: DIGIKEY; Distributor_part_number: 399-8974-1-ND; Footprint Path: Y:\MIS_DATABASE\Library\ALTIUM_TOOL\PCB_FOOTPRINTS\Altium_Footprint_Lib.PcbLib; Height: 0.55MM; Library Path: Y:\MIS_DATABASE\Library\ALTIUM_TOOL\SCHEMATICS_PARTS\MS_DISCRETE_Library.schlib; Mfr_name: KEMET; Mfr_part_number: C0402C682J3RACTU; Mistral Part No: 120015120013-R; Package: 0402; Part_type: CAPACITORS\CERAMIC; Project: DLRL_NBSDR; RoHS: RoHS; Temperature: -55°C+125°C; Tolerance: 5%; Voltage: 25V; Wattage: NA; Weight: 0.65mg; Datasheet: Y:\MIS_DATABASE\DATASHEETS\CAPACITORS\KEMET-C-X7R.PDF
C83 C346 = CAP: CAP CERAMIC 2.2uF 25V 10% X5R 0402; Chkd/date: ALVY/010721; Crtd /date: MANIRAJA/010721; Custom_Duty: 15%; Customs_HS_Code: 85322990; Distributor_name: DIGIKEY; Distributor_part_number: 490-12703-1-ND; Footprint Path: Y:\MIS_DATABASE\Library\ALTIUM_TOOL\PCB_FOOTPRINTS\Altium_Footprint_Lib.PcbLib; Height: 0.70MM; Library Path: Y:\MIS_DATABASE\Library\ALTIUM_TOOL\SCHEMATICS_PARTS\MS_DISCRETE_Library.schlib; Mfr_name: MURATA; Mfr_part_number: GRM155R61E225KE11D; Mistral Part No: 120015120001-R; Package: 0402; Part_type: CAPACITORS\CERAMIC; Project: TI_AM263X_CC; RoHS: RoHS; Temperature: -55°C+85°C; Tolerance: 10%; Voltage: 25V; Wattage: NA; Weight: 1.5mg; Datasheet: Y:\MIS_DATABASE\DATASHEETS\CAPACITORS\GRM155R61E225KE11.PDF
C344 = CAP: CAP CERAMIC 10uF 50V 10% X7T 1206; Chkd/date: ALVY/010721; Crtd /date: MANIRAJA/010721; Custom_Duty: 15%; Customs_HS_Code: 85322990; Distributor_name: DIGIKEY; Distributor_part_number: 490-GRM31CD71H106KE11LCT-ND; Footprint Path: Y:\MIS_DATABASE\Library\ALTIUM_TOOL\PCB_FOOTPRINTS\Altium_Footprint_Lib.PcbLib; Height: 1.90MM; Library Path: Y:\MIS_DATABASE\Library\ALTIUM_TOOL\SCHEMATICS_PARTS\MS_DISCRETE_Library.schlib; Mfr_name: MURATA; Mfr_part_number: GRM31CD71H106KE11L; Mistral Part No: 120021070004-R; Package: 1206; Part_type: CAPACITORS\CERAMIC; Project: TI_AM263X_CC; RoHS: RoHS; Temperature: -55°C+125°C; Tolerance: 10%; Voltage: 50V; Wattage: NA; Weight: 27mg; Datasheet: Y:\MIS_DATABASE\DATASHEETS\CAPACITORS\GRM31CD71H106KE11.PDF
C240 C241 C345 C352 = CAP: CAP CERAMIC 0.1uF 50V 10% X7R 0402; Automotive Alternate_mfr_name: TDK; Automotive Alternate_mfr_part_number: CGA2B1X7R1C104K050BC; Chkd/date: MANIRAJA/261020; Crtd /date: ALVY/211020; Custom_Duty: 15%; Customs_HS_Code: 85322990; Direct Alternate_mfr_name: MURATA; Direct Alternate_mfr_part_number: GCM155R71C104JA55D; Distributor_name: DIGIKEY; Distributor_part_number: 490-10700-1-ND; Footprint Path: Y:\MIS_DATABASE\Library\ALTIUM_TOOL\PCB_FOOTPRINTS\Altium_Footprint_Lib.PcbLib; Height: 0.55MM; Library Path: Y:\MIS_DATABASE\Library\ALTIUM_TOOL\SCHEMATICS_PARTS\MS_DISCRETE_Library.schlib; Mfr_name: MURATA; Mfr_part_number: GRM155R71H104KE14D; Mistral Part No: 120011100014-R; Package: 0402; Part_type: CAPACITORS\CERAMIC; Project: J7_CP; RoHS: RoHS; Temperature: -55°C+125°C; Tolerance: 10%; Voltage: 50V; Wattage: NA; Weight: 3.1mg; Datasheet: Y:\MIS_DATABASE\DATASHEETS\CAPACITORS\GRM155R71H104KE14.PDF
C347 = CAP: CAP CERAMIC 0.1uF 50V 10% X7R 0402; Chkd/date: MANIRAJA/261020; Crtd /date: ALVY/211020; Custom_Duty: 15%; Customs_HS_Code: 85322990; Distributor_name: DIGIKEY; Distributor_part_number: 490-10700-1-ND; Footprint Path: Y:\MIS_DATABASE\Library\ALTIUM_TOOL\PCB_FOOTPRINTS\Altium_Footprint_Lib.PcbLib; Height: 0.55MM; Library Path: Y:\MIS_DATABASE\Library\ALTIUM_TOOL\SCHEMATICS_PARTS\MS_DISCRETE_Library.schlib; Mfr_name: MURATA; Mfr_part_number: GRM155R71H104KE14D; Mistral Part No: 120011100014-R; Package: 0402; Part_type: CAPACITORS\CERAMIC; Project: J7_CP; RoHS: RoHS; Temperature: -55°C+125°C; Tolerance: 10%; Voltage: 50V; Wattage: NA; Weight: 3.1mg; Datasheet: Y:\MIS_DATABASE\DATASHEETS\CAPACITORS\GRM155R71H104KE14.PDF
L4 = INDUCTOR: IND POWER 1uH 13A 20% SMD; Chkd/date: PRAVEEN/050523; Crtd /date: TAMILARASU/060523; Custom_Duty: 15%; Customs_HS_Code: 85412900; Distributor_name: DIGIKEY; Distributor_part_number: 2457-XGL4030-102MEC-ND; Footprint Path: Y:\MIS_DATABASE\Library\ALTIUM_TOOL\PCB_FOOTPRINTS\Altium_Footprint_Lib.PcbLib; Height: 3.10MM; Library Path: Y:\MIS_DATABASE\Library\ALTIUM_TOOL\SCHEMATICS_PARTS\MS_DISCRETE_Library.schlib; Mfr_name: COILCRAFT; Mfr_part_number: XGL4030-102MEC; Mistral Part No: 130023050003-R; Package: SMD; Project: AM263P_CC; RoHS: RoHS; Temperature: -40°C+125°C; Tolerance: 20%; Voltage: NA; Wattage: NA; Weight: NA; Datasheet: Y:\MIS_DATABASE\DATASHEETS\DISCRETES\INDUCTORS\XGL4030-SER.PDF
L5 = INDUCTOR: IND POWER 10uH 1.7A 20% SMD; Chkd/date: MANIRAJA/280520; Crtd /date: ALVY/280520; Custom_Duty: 24%; Customs_HS_Code: 85437099; Distributor_name: DIGIKEY; Distributor_part_number: 732-10793-1-ND; Footprint Path: Y:\MIS_DATABASE\Library\ALTIUM_TOOL\PCB_FOOTPRINTS\Altium_Footprint_Lib.PcbLib; Height: 2.00MM; Library Path: Y:\MIS_DATABASE\Library\ALTIUM_TOOL\SCHEMATICS_PARTS\MS_DISCRETE_Library.schlib; Mfr_name: WURTH ELECTRONICS; Mfr_part_number: 74405042100; Mistral Part No: 130020050044-R; Package: SMD; Project: AM64x-GP_EVM BRD; RoHS: RoHS; Temperature: -40°C+125°C; Tolerance: 20%; Voltage: NA; Wattage: NA; Weight: 270mg; Datasheet: Y:\MIS_DATABASE\DATASHEETS\DISCRETES\INDUCTORS\74405042100.PDF
R52 R56 = RESISTOR: RES 100K 1/16W 5% 0402; Chkd/date: VASANTHA/061216; Crtd /date: BAVISH/010611; Custom_Duty: 15%; Customs_HS_Code: 85332119; Distributor_name: DIGIKEY; Distributor_part_number: 541-100KJCT-ND; Footprint Path: Y:\MIS_DATABASE\Library\ALTIUM_TOOL\PCB_FOOTPRINTS\Altium_Footprint_Lib.PcbLib; Height: 0.40MM; Library Path: Y:\MIS_DATABASE\Library\ALTIUM_TOOL\SCHEMATICS_PARTS\MS_DISCRETE_Library.schlib; Mfr_name: VISHAY; Mfr_part_number: CRCW0402100KJNED; Mistral Part No: 110011060002-R; Package: 0402; Part_type: RESISTORS\FIXED; Project: AM4515_EVM_LCD; RoHS: RoHS; Temperature: -55°C+155°C; Tolerance: 5%; Voltage: NA; Wattage: 1/16W; Weight: 0.65mg; Datasheet: Y:\MIS_DATABASE\DATASHEETS\RESISTORS\CRCW0603.PDF
R53 R55 R59 R430 R465 = RESISTOR: RES 10K 1/16W 1% 0402; Chkd/date: VASANTHA/201216; Crtd /date: GEETHA/290506; Custom_Duty: 15%; Customs_HS_Code: 85332119; Distributor_name: DIGIKEY; Distributor_part_number: 311-10.0KLRTR-ND; Footprint Path: Y:\MIS_DATABASE\Library\ALTIUM_TOOL\PCB_FOOTPRINTS\Altium_Footprint_Lib.PcbLib; Height: 0.40MM; Library Path: Y:\MIS_DATABASE\Library\ALTIUM_TOOL\SCHEMATICS_PARTS\MS_DISCRETE_Library.schlib; Mfr_name: YAGEO AMERICA; Mfr_part_number: RC0402FR-0710KL; Mistral Part No: 110015090015-R; Package: 0402; Part_type: RESISTORS\FIXED; Project: VOCERA; RoHS: RoHS; Temperature: -55°C+155°C; Tolerance: 1%; Voltage: NA; Wattage: 1/16W; Weight: 0.65mg; Datasheet: Y:\MIS_DATABASE\DATASHEETS\RESISTORS\RCXXXXL-SER_MAR18.PDF
R58 = RESISTOR: RES 100K 1/16W 1% 0402; Chkd/date: MANIRAJA/300520; Crtd /date: ALVY/250520; Custom_Duty: 15%; Customs_HS_Code: 85332119; Distributor_name: DIGIKEY; Distributor_part_number: 541-100KLCT-ND; Footprint Path: Y:\MIS_DATABASE\Library\ALTIUM_TOOL\PCB_FOOTPRINTS\Altium_Footprint_Lib.PcbLib; Height: 0.40MM; Library Path: Y:\MIS_DATABASE\Library\ALTIUM_TOOL\SCHEMATICS_PARTS\MS_DISCRETE_Library.schlib; Mfr_name: VISHAY; Mfr_part_number: CRCW0402100KFKED; Mistral Part No: 110014060043-R; Package: 0402; Part_type: RESISTORS\FIXED; Project: QCS610_NANOSOM; RoHS: RoHS; Temperature: -55°C+155°C; Tolerance: 1%; Voltage: NA; Wattage: 1/16W; Weight: 11mg; Datasheet: Y:\MIS_DATABASE\DATASHEETS\RESISTORS\CRCW0603.PDF
R463 = RESISTOR: RES 3.16K 1/10W 1% 0402; Chkd/date: MANIRAJA/081020; Crtd /date: ALVY/071020; Custom_Duty: 15%; Customs_HS_Code: 85332119; Distributor_name: DIGIKEY; Distributor_part_number: 2019-RK73H1ETTP3161FCT-ND; Footprint Path: Y:\MIS_DATABASE\Library\ALTIUM_TOOL\PCB_FOOTPRINTS\Altium_Footprint_Lib.PcbLib; Height: 0.40MM; Library Path: Y:\MIS_DATABASE\Library\ALTIUM_TOOL\SCHEMATICS_PARTS\MS_DISCRETE_Library.schlib; Mfr_name: KOA SPEER; Mfr_part_number: RK73H1ETTP3161F; Mistral Part No: 110009030614-R; Package: 0402; Part_type: RESISTORS\FIXED; Project: VAGG_SBC_BRD; RoHS: RoHS; Temperature: -55°C+155°C; Tolerance: 1%; Voltage: NA; Wattage: 1/10W; Weight: 0.65mg; Datasheet: Y:\MIS_DATABASE\DATASHEETS\RESISTORS\RK73H-SER.PDF
R464 = RESISTOR: RES 1.5K 1/16W 0.1% 0402; Chkd/date: ALVY/020620; Crtd /date: MANIRAJA/020620; Custom_Duty: 15%; Customs_HS_Code: 85332119; Distributor_name: DIGIKEY; Distributor_part_number: YAG4349CT-ND; Footprint Path: Y:\MIS_DATABASE\Library\ALTIUM_TOOL\PCB_FOOTPRINTS\Altium_Footprint_Lib.PcbLib; Height: 0.35MM; Library Path: Y:\MIS_DATABASE\Library\ALTIUM_TOOL\SCHEMATICS_PARTS\MS_DISCRETE_Library.schlib; Mfr_name: YAGEO AMERICA; Mfr_part_number: RT0402BRE071K5L; Mistral Part No: 110020060015-R; Package: 0402; Part_type: RESISTORS\FIXED; Project: 32CHSCC CONTROLLER CARD; RoHS: RoHS; Temperature: -55°C+155°C; Tolerance: 0.1%; Voltage: NA; Wattage: 1/16W; Weight: 0.65mg; Datasheet: Y:\MIS_DATABASE\DATASHEETS\RESISTORS\YAGEO_RT-SERIES.PDF
TP23-TP26 TP76 TP77 = TESTPOINT: TESTPOINT 1.0MM DRILL PTH; Chkd/date: MAZHAR/271211; Crtd /date: SHREESHAIL/041005; Distributor_name: NA; Distributor_part_number: NA; Height: NA; Mfr_name: LOCAL; Mistral Part No: 130009030938; Package: THRU-HOLE; Project: HSE; Datasheet: NA
U9 = TPS62903_VQFNHR9: IC 3-18V 3A AUTOMOTIVE LOW IQ BUCK CONVERTER WITH +165°C VQFN-HR9; Chkd/date: PRAVEEN/170323; Crtd /date: TAMILARASU/170323; Custom_Duty: 15%; Customs_HS_Code: 85423100; Distributor_name: DIGIKEY; Distributor_part_number: 296-TPS62913RPURCT-ND; Footprint Path: Y:\MIS_DATABASE\Library\ALTIUM_TOOL\PCB_FOOTPRINTS\Altium_Footprint_Lib.PcbLib; Height: 1.05MM; Library Path: Y:\MIS_DATABASE\Library\ALTIUM_TOOL\SCHEMATICS_PARTS\MS_MISCPOWER_Library.schlib; MECHANICAL 3D STEP FILE: VQFNHR10_TPS62903_80X90_1-5; Mfr_name: TEXAS INSTRUMENTS; Mfr_part_number: TPS62903QRYTRQ1; Mistral Part No: 142023030009-R; Package: VQFN-HR10; Part_type: ICS\POWER\CONVERTER; Project: AM263P_CC; RoHS: RoHS; Temperature: -40°C+165°C; Tolerance: NA; Voltage: NA; Wattage: NA; Weight: NA; Datasheet: Y:\MIS_DATABASE\DATASHEETS\ICS\POWER\TPS62903-Q1.PDF
U10 = TPS62177_WSON10: IC 3.3V 0.5A STEP DOWN CONVERTER WITH SLEEP MODE WSON10; Chkd/date: MANIRAJA/170719; Crtd /date: MANIRAJA/170719; Custom_Duty: 15%; Customs_HS_Code: 85423100; Distributor_name: DIGIKEY; Distributor_part_number: 296-41856-1-ND; Footprint Path: Y:\MIS_DATABASE\Library\ALTIUM_TOOL\PCB_FOOTPRINTS\Altium_Footprint_Lib.PcbLib; Height: 0.80MM; Library Path: Y:\MIS_DATABASE\Library\ALTIUM_TOOL\SCHEMATICS_PARTS\MS_MISCPOWER_Library.schlib; Mfr_name: TEXAS INSTRUMENTS; Mistral Part No: 142019070007-R; Package: WSON10; Part_type: ICS\POWER\DC-DC CONVERTER; Project: TI_MAXIE_CPB; RoHS: RoHS; Temperature: -40°C+85°C; Tolerance: NA; Voltage: NA; Wattage: NA; Weight: 15mg; Datasheet: Y:\MIS_DATABASE\DATASHEETS\ICS\POWER\TPS62177.PDF
U66 = TLV75801P_WSON6: IC 500mA ADJ LDO REGULATOR WSON6; Chkd/date: ALVY/051219; Crtd /date: MANIRAJA/051219; Custom_Duty: 15%; Customs_HS_Code: 85423100; Distributor_name: DIGIKEY; Distributor_part_number: 296-53047-1-ND; Footprint Path: Y:\MIS_DATABASE\Library\ALTIUM_TOOL\PCB_FOOTPRINTS\Altium_Footprint_Lib.PcbLib; Height: 0.80MM; Library Path: Y:\MIS_DATABASE\Library\ALTIUM_TOOL\SCHEMATICS_PARTS\MS_MISCPOWER_Library.schlib; Mfr_name: TEXAS INSTRUMENTS; Mistral Part No: 142019120004-R; Package: WSON6; Part_type: ICS\POWER\VOLTAGE REGULATOR; Project: SAMSUNG_STREAM; RoHS: RoHS; Temperature: -40°C+125°C; Tolerance: NA; Voltage: NA; Wattage: NA; Weight: NA; Datasheet: Y:\MIS_DATABASE\DATASHEETS\ICS\POWER\TLV75801PXXX.PDF
J11 = CON_FLEX_40X1_FH12A-40S-0.5SH: CON FPC 40X1 0.50MM PITCH RT TOP SMD; Chkd/date: SHREESHAIL/201106; Crtd /date: MAZHAR/171106; Custom_Duty: 24%; Customs_HS_Code: 85369090; Distributor_name: DIGIKEY; Distributor_part_number: HFK40CT-ND; Height: 2.00MM; Mfr_name: HIROSE ELECTRIC EUROPE; Mfr_part_number: FH12A-40S-0.5SH(55); Mistral Part No: 150009030176-R; Package: SMD; Part_type: CONNECTOR\FPC; Project: PMP LCD BOARD; Datasheet: Y:\MIS_DATABASE\DATASHEETS\CONNECTORS\FH12SERIES.PDF
R286 R287 R308 R309 = RESISTOR: RES 4.7K 1/16W 5% 0402; Chkd/date: VASANTHA/130516; Crtd /date: VASANTHA/130516; Custom_Duty: 15%; Customs_HS_Code: 85332119; Distributor_name: DIGIKEY; Distributor_part_number: 311-4.7KJRCT-ND; Footprint Path: Y:\MIS_DATABASE\Library\ALTIUM_TOOL\PCB_FOOTPRINTS\Altium_Footprint_Lib.PcbLib; Height: 0.40MM; Library Path: Y:\MIS_DATABASE\Library\ALTIUM_TOOL\SCHEMATICS_PARTS\MS_DISCRETE_Library.schlib; Mfr_name: YAGEO AMERICA; Mfr_part_number: RC0402JR-074K7L; Mistral Part No: 110011060001-R; Package: 0402; Part_type: RESISTORS\FIXED; Project: TMDXCSK368; RoHS: RoHS; Temperature: -55°C+155°C; Tolerance: 5%; Voltage: NA; Wattage: 1/16W; Weight: 0.65mg; Datasheet: Y:\MIS_DATABASE\DATASHEETS\RESISTORS\RCXXXXL-SER_MAR18.PDF
R295-R307 R310-R315 = RESISTOR: RES 0E 1/20W 5% 0201; Chkd/date: NAVEED/301214; Crtd /date: MUDDU/120710; Custom_Duty: 15%; Customs_HS_Code: 85332119; Distributor_name: DIGIKEY; Distributor_part_number: 311-0.0NCT-ND; Footprint Path: Y:\MIS_DATABASE\Library\ALTIUM_TOOL\PCB_FOOTPRINTS\Altium_Footprint_Lib.PcbLib; Height: 0.26MM; Library Path: Y:\MIS_DATABASE\Library\ALTIUM_TOOL\SCHEMATICS_PARTS\MS_DISCRETE_Library.schlib; Mfr_name: YAGEO AMERICA; Mfr_part_number: RC0201JR-070RL; Mistral Part No: 110010070067-R; Package: 0201; Part_type: RESISTORS\FIXED; Project: PB_BUGBASE; RoHS: RoHS; Temperature: -55°C+125°C; Tolerance: 5%; Voltage: NA; Wattage: 1/20W; Weight: 0.17mg; Datasheet: Y:\MIS_DATABASE\DATASHEETS\RESISTORS\RCXXXXL-SER_MAR18.PDF
U46 = ISO1641B_SOIC8: IC HOT-SWAPPABLE BIDIRECTIONAL I2C ISOLATORS WITH ENHANCED EMC AND GPIOS SOIC8; Chkd/date: PRAVEEN/180423; Crtd /date: PRAVEEN/180423; Custom_Duty: 15%; Customs_HS_Code: 85423100; Distributor_name: DIGIKEY; Distributor_part_number: 296-ISO1641BDRCT-ND; Footprint Path: Y:\MIS_DATABASE\Library\ALTIUM_TOOL\PCB_FOOTPRINTS\Altium_Footprint_Lib.PcbLib; Height: 1.75MM; Library Path: Y:\MIS_DATABASE\Library\ALTIUM_TOOL\SCHEMATICS_PARTS\MS_MISC_Library.schlib; Mfr_name: TEXAS INSTRUMENTS; Mfr_part_number: ISO1641BDR; Mistral Part No: 141023040007-R; Package: SOIC8; Part_type: ICS\DIGITAL\ISOLATOR; Project: AM263P_CC; RoHS: RoHS; Temperature: -40°C+125°C; Tolerance: NA; Voltage: NA; Wattage: NA; Weight: 540mg; Datasheet: Y:\MIS_DATABASE\DATASHEETS\ICS\MISC\ISO1641BD.PDF

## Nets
DGND: C30.2 C31.2 C32.2 C33.2 C34.2 C35.2 C36.2 C37.2 C38.2 C43.2 C44.2 C45.2 C46.2 C47.2 C48.2 C49.2 C50.2 C51.2 C52.2 C53.2 C54.2 C57.2 C58.2 C59.2 C60.2 C61.2 C62.2 C64.2 C65.2 C66.2 C67.2 C68.2 C69.2 C70.2 C71.2 C72.2 C73.2 C74.2 C75.2 C76.2 C77.2 C78.2 C79.2 C80.2 C81.2 C82.2 C83.2 C84.2 C85.2 C238.2 C239.2 C240.2 C241.2 C344.2 C345.2 C346.2 C347.2 J2.3 J3.3 J11.7 J11.16 J11.25 J11.34 J11.40 J11.41 J11.42 LD3.1(CATHODE) LD20.1(CATHODE) LD21.1(CATHODE) LD22.1(CATHODE) R42.2 R49.2 R50.2 R55.1 R56.1 R314.2 R464.2 R465.2 TP23.1(TP) TP24.1(TP) TP25.1(TP) TP26.1(TP) TP77.1(TP) U7.1(PGND) U7.2(PGND) U7.14(LGND) U7.47(PGND) U7.48(PGND) U7.49(EPAD) U8.8(GND) U9.4(GND) U9.7(MODE/S-CONF) U10.1(PGND) U10.5(FB) U10.6(AGND) U10.11(EP) U46.4(GND1) U66.3(GND) U66.7(EP) ; also on sheet 1 2 3 4 6 7 8 9 10 11 12 13 14 15 16 17 24 25 26 27 32 33
VCC3V3_XDS: C352.1 R306.2 ; also on sheet 3 17 27
VCC_1V8_LDO4: C70.1 C71.1 C72.1 R36.2 R3833.1 TP20.1(TP) U7.30(LDO4_OUT) ; also on sheet 16
VCC_6V0_BBOUT: C30.1 C31.1 C32.1 C33.1 C34.1 C35.1 C36.1 C37.1 C38.1 C80.1 C344.1 C345.1 TP5.1(TP) U7.41(LDO_IN) U7.42(BB_OUT) U9.6(VIN) U66.6(IN)
VCC_PLDO1: C74.1 C75.1 C76.1 J3.1 U7.20(PLDO1_OUT)
VCC_PLDO2: C77.1 C78.1 C79.1 J2.1 U7.29(PLDO2_OUT)
VDD_5V0_LDO3: C67.1 C68.1 C69.1 R3834.1 TP19.1(TP) U7.15(LDO3_OUT) ; also on sheet 9 12 13
BOOTMODE_TA_I2C_SCL: R286.2 R303.1 ; also on sheet 3 11
BOOTMODE_TA_I2C_SDA: R287.2 R305.1 ; also on sheet 3 11
EXT_VMON1: R53.2 R55.2 TP85.1(TP) U7.16(EXT_VMON1)
EXT_VMON2: U7.10(EXT_VMON2) ; also on sheet 7
HSEC_SPI1_CLK: U8.3(1B2) ; also on sheet 6
HSEC_SPI1_CS0: U8.13(4B2) ; also on sheet 6
HSEC_SPI1_D0: U8.6(2B2) ; also on sheet 6
HSEC_SPI1_D1: U8.10(3B2) ; also on sheet 6
PMIC_COMP1_IN+: U7.21(GPI2) ; also on sheet 6
PMIC_COMP1_IN-: U7.24(GPI3) ; also on sheet 6
PMIC_COMP2_IN+: U7.28(GPI5) ; also on sheet 6
PMIC_COMP2_IN-: U7.25(GPI4) ; also on sheet 6
PMIC_DIAG_OUT: U7.32(DIAG_OUT) ; also on sheet 16
PMIC_EN_OUT: R51.1 U7.17(EN_OUT)
PMIC_INTn: U7.22(GPO1) ; also on sheet 12
PMIC_NRST: U7.13(NRST) ; also on sheet 10
PMIC_SAFE_OUT1: R32.1 ; also on sheet 6
PMIC_SAFE_OUT2: U7.27(GPO4) ; also on sheet 6 27
PMIC_SPI1_CLK: R41.2 TP18.1(TP) U7.33(SCLK) U8.2(1B1)
PMIC_SPI1_CS0: R39.2 TP16.1(TP) U7.36(NCS) U8.14(4B1)
PMIC_SPI1_D0: R40.2 TP17.1(TP) U7.35(SDI) U8.5(2B1)
PMIC_SPI1_D1: R38.2 R142.2 U8.11(3B1)
PMIC_WKUP1: R34.2 U7.6(WAKE1) ; also on sheet 6
PMIC_WKUP2: U7.43(WAKE2) ; also on sheet 6 13
SAFETY_ERRORn: R435.2 ; also on sheet 27
SOC_I2C2_SCL: U46.3(SCL1) ; also on sheet 1 12 26
SOC_I2C2_SDA: U46.2(SDA1) ; also on sheet 1 12 26
SOC_SPI1_CLK: R43.2 U8.4(1A) ; also on sheet 26
SOC_SPI1_CS0: R46.2 U8.12(4A) ; also on sheet 26
SOC_SPI1_D0: R44.2 U8.7(2A) ; also on sheet 26
SOC_SPI1_D1: R45.2 U8.9(3A) ; also on sheet 26
SOC_TA_I2C2_SCL: R302.1 R310.2
SOC_TA_I2C2_SDA: R304.1 R311.2
SOC_XDS_I2C2_SCL: R312.2 ; also on sheet 17
SOC_XDS_I2C2_SDA: R313.2 ; also on sheet 17
SPI1_MUX_OE#: R50.1 U8.15(~{OE})
SPI1_MUX_SEL: R49.1 U8.1(S) ; also on sheet 12
TA_GPIO1: R291.1 R298.1 ; also on sheet 3 10
TA_GPIO2: R290.1 R299.1 ; also on sheet 3
TA_GPIO3: R289.1 R300.1 ; also on sheet 3 11
TA_GPIO4: R288.1 R301.1 ; also on sheet 3 11
TA_PORZn: R293.1 R296.1 ; also on sheet 3 10
TA_POWERDOWNz: R295.1 R468.1 ; also on sheet 3 4
TA_RESETz: R292.1 R297.1 ; also on sheet 3 10
VMAIN: C83.1 R57.1 U10.2(VIN) ; also on sheet 1 4 10 14 26 27
VMAIN_12V0: J20.2 ; also on sheet 4 13
VMAINP_12V0: C43.1 C44.1 C45.1 C46.1 C47.1 C48.1 C49.1 C50.1 C51.1 C52.1 C53.1 C54.1 U7.7(VBATP1) U7.8(VBATP2) U7.9(VBATS) ; also on sheet 4
VPP_1V7: C346.1 C347.1 R463.1 TP76.1(TP) U66.1(OUT) ; also on sheet 8
VPP_LDO_EN: R465.1 U66.4(EN) ; also on sheet 12
VREG: C62.1 TP7.1(TP) U7.40(VREG_OUT)
VREG_1P8_OUT: C61.1 TP8.1(TP) U7.39(VREG_1P8_OUT)
VSYS_1V2: C81.1 L4.2 R52.1 R53.1 TP82.1(TP) U9.3(VOS) ; also on sheet 1
VSYS_1V2_EN: R51.2 R430.2 U9.5(EN)
VSYS_1V2_FB: R52.2 R56.2 U9.9(FB/VSET)
VSYS_1V2_PG: R59.2 U9.1(PG) ; also on sheet 1 10
VSYS_1V2_SW: L4.1 U9.2(SW)
VSYS_1V7_FB: R463.2 R464.1 U66.2(FB)
VSYS_3V3_LDO1: C58.1 C59.1 C60.1 C73.1 C240.1 R38.1 R39.1 R40.1 R41.1 R43.1 R44.1 R45.1 R46.1 R48.1 R59.1 R430.1 TP6.1(TP) U7.37(VDDIO) U7.38(LDO1_OUT) U8.16(VCC) U46.1(VCC1) ; also on sheet 1 6 7 9 10 11 12 13 14 15 16 17 24 26 27 32 33
VSYS_3V3_LDO2: C64.1 C65.1 C66.1 R3835.1 TP10.1(TP) U7.11(LDO2_OUT) ; also on sheet 1 9 12 13 25 26
VSYS_TA_3V3: C84.1 C85.1 C238.1 C239.1 C241.1 J11.1 J11.2 J11.3 L5.2 R58.2 R286.1 R287.1 R288.2 R289.2 R290.2 R291.2 R292.2 R293.2 R307.2 R468.2 TP21.1(TP) U10.8(SLEEP) U10.10(VOS) ; also on sheet 1 3 11
VSYS_TA_3V3_EN: R57.2 U10.3(EN)
VSYS_TA_3V3_PG: R58.1 U10.7(PG)
VSYS_TA_3V3_SW: L5.1 U10.9(SW)
XDS_GND: C352.2 R315.2 ; also on sheet 3 17 27
N31943874: R306.1 R307.1 R308.1 R309.1 U46.8(VCC2)
N33038314: LD3.2(ANODE) R48.2
N34663370: J11.27 R296.2
N34663404: J11.30 R298.2
N34663407: J11.31 R299.2
N34663410: J11.32 R300.2
N34663413: J11.28 R297.2
N34663434: J11.33 R301.2
N34665841: J11.36 R302.2
N34665844: J11.37 R303.2
N34665847: J11.38 R304.2
N34665853: J11.39 R305.2
N34666564: R309.2 R310.1 R312.1 U46.6(SCL2)
N34666567: R308.2 R311.1 R313.1 U46.7(SDA2)
N34733472: TP13.1(TP) U7.23(GPO2)
N34733475: TP15.1(TP) U7.26(GPO3)
N34733595: R32.2 U7.31(SAFE_OUT1)
N34755833: L3.1 R28.2 R29.1 U7.3(BB_SW1_1) U7.4(BB_SW1_2)
N34755845: C56.1 L3.2 U7.45(BB_SW2_1) U7.46(BB_SW2_2)
N34755854: C55.2 U7.5(BB_BST1)
N34755863: C56.2 U7.44(BB_BST2)
N34755869: C55.1 R28.1
N34756880: R36.1 U7.19(TRACK)
N34775734: C82.1 U9.8(SS/TR)
N34820051: J11.26 R295.2
N34869775: C57.1 R29.2
N35065419: R42.1 U7.12(GND)
N35071225: R435.1 U7.18(GPI1)
N35139843: R142.1 U7.34(SDO)
N35373997: R314.1 R315.1 U46.5(GND2)
N35375175: J20.1 R34.1
N35656498: LD20.2(ANODE) R3833.2
N35656998: LD21.2(ANODE) R3834.2
N35657235: LD22.2(ANODE) R3835.2

Not connected (* = marked no-connect by the designer): J2 2*; J3 2*; J11 4* 5* 6* 8* 9* 10* 11* 12* 13* 14* 15* 17* 18* 19* 20* 21* 22* 23* 24* 29* 35*; U10 4(NC)*; U66 5(DNC)*

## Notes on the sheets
sheet 28
- TEST AUTOMATION HEADER
- I2C Pull Ups
- AUTOMATION INTERFACE
- Cable : Parlex-050R40-76B, .5mm 3"
- I2C BUFFER
- TEST AUTOMATION  GPIO MAPPING
- Internal/
  External
  PU/PD states
- Direction WRT CTRL
- SIGNAL NAME
- DESCRIPTION
- TA_POWERDOWN
  TA_PORZn
  TA_RESETz
  TA_GPIO1
  TA_GPIO3
  TA_GPIO4
- Used to Power down the system
  Used to Reset the SoC PORz
  SoC Warmreset
  Interrupt to SOC
  Used to Enable the BOOTMODE Buffer
  Used Reset Bootmode IO Exp
- OUTPUT
- External Pullup
- OUTPUT
- External Pullup
- OUTPUT
- External Pullup
- OUTPUT
- External Pullup
- OUTPUT
- External Pullup
- OUTPUT
- External Pullup
- TA Configuration
- Mount : R307,R310,R311,R314
- Demount : R306,R312,R313,R315
sheet 29
- Power Supply #1
- 1.2V Generation
- Test Automation Header Supply
- TPS62177 3.3V  BUCK REGULATOR
  Vout = 3.3V
  Iout = 0.5A
- S-CONF:
  - 2.2MHz switching frequency
  - Dynamic mode change active
  - Output discharge enabled
- TLV75801
  Vout=1.7V
  Iout = .5A
- Place testpoints with
  100mils spacing to
  insert external jumper
- 1.7V VPP Generation
- Ground Test Points
sheet 30
- BLACKBIRD PMIC
- NOTE: This Control Card design does not include reverse blocking or EMC filtering that will be required for automotive applications.
- CAD NOTE: PLACE 0.1uF CAPS CLOSER TO VBAT PINS 7,8 & 9 AS MUCH AS POSSIBLE
- NOTE: ADD JUMPER TO ENABLE PMIC
  VIA WAKE1 PIN OF PMIC
- Power LEDs for PMIC LDOs
- SPI MUX/DEMUX
- GREEN
- GREEN
- GREEN
- GREEN
- SPI1 - 1:2  MUX
- SEL
- CONDITION
- FUNCTION
- LOW
- PMIC SELECTED
- A-->B1 port
- HIGH
- HSEC SPI1 selected
- A-->B2 port
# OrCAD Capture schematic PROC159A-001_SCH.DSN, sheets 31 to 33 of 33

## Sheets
31 33. CC EVM NOTES, HW & LABELS: title: CC EVM NOTES,HW &LABELS
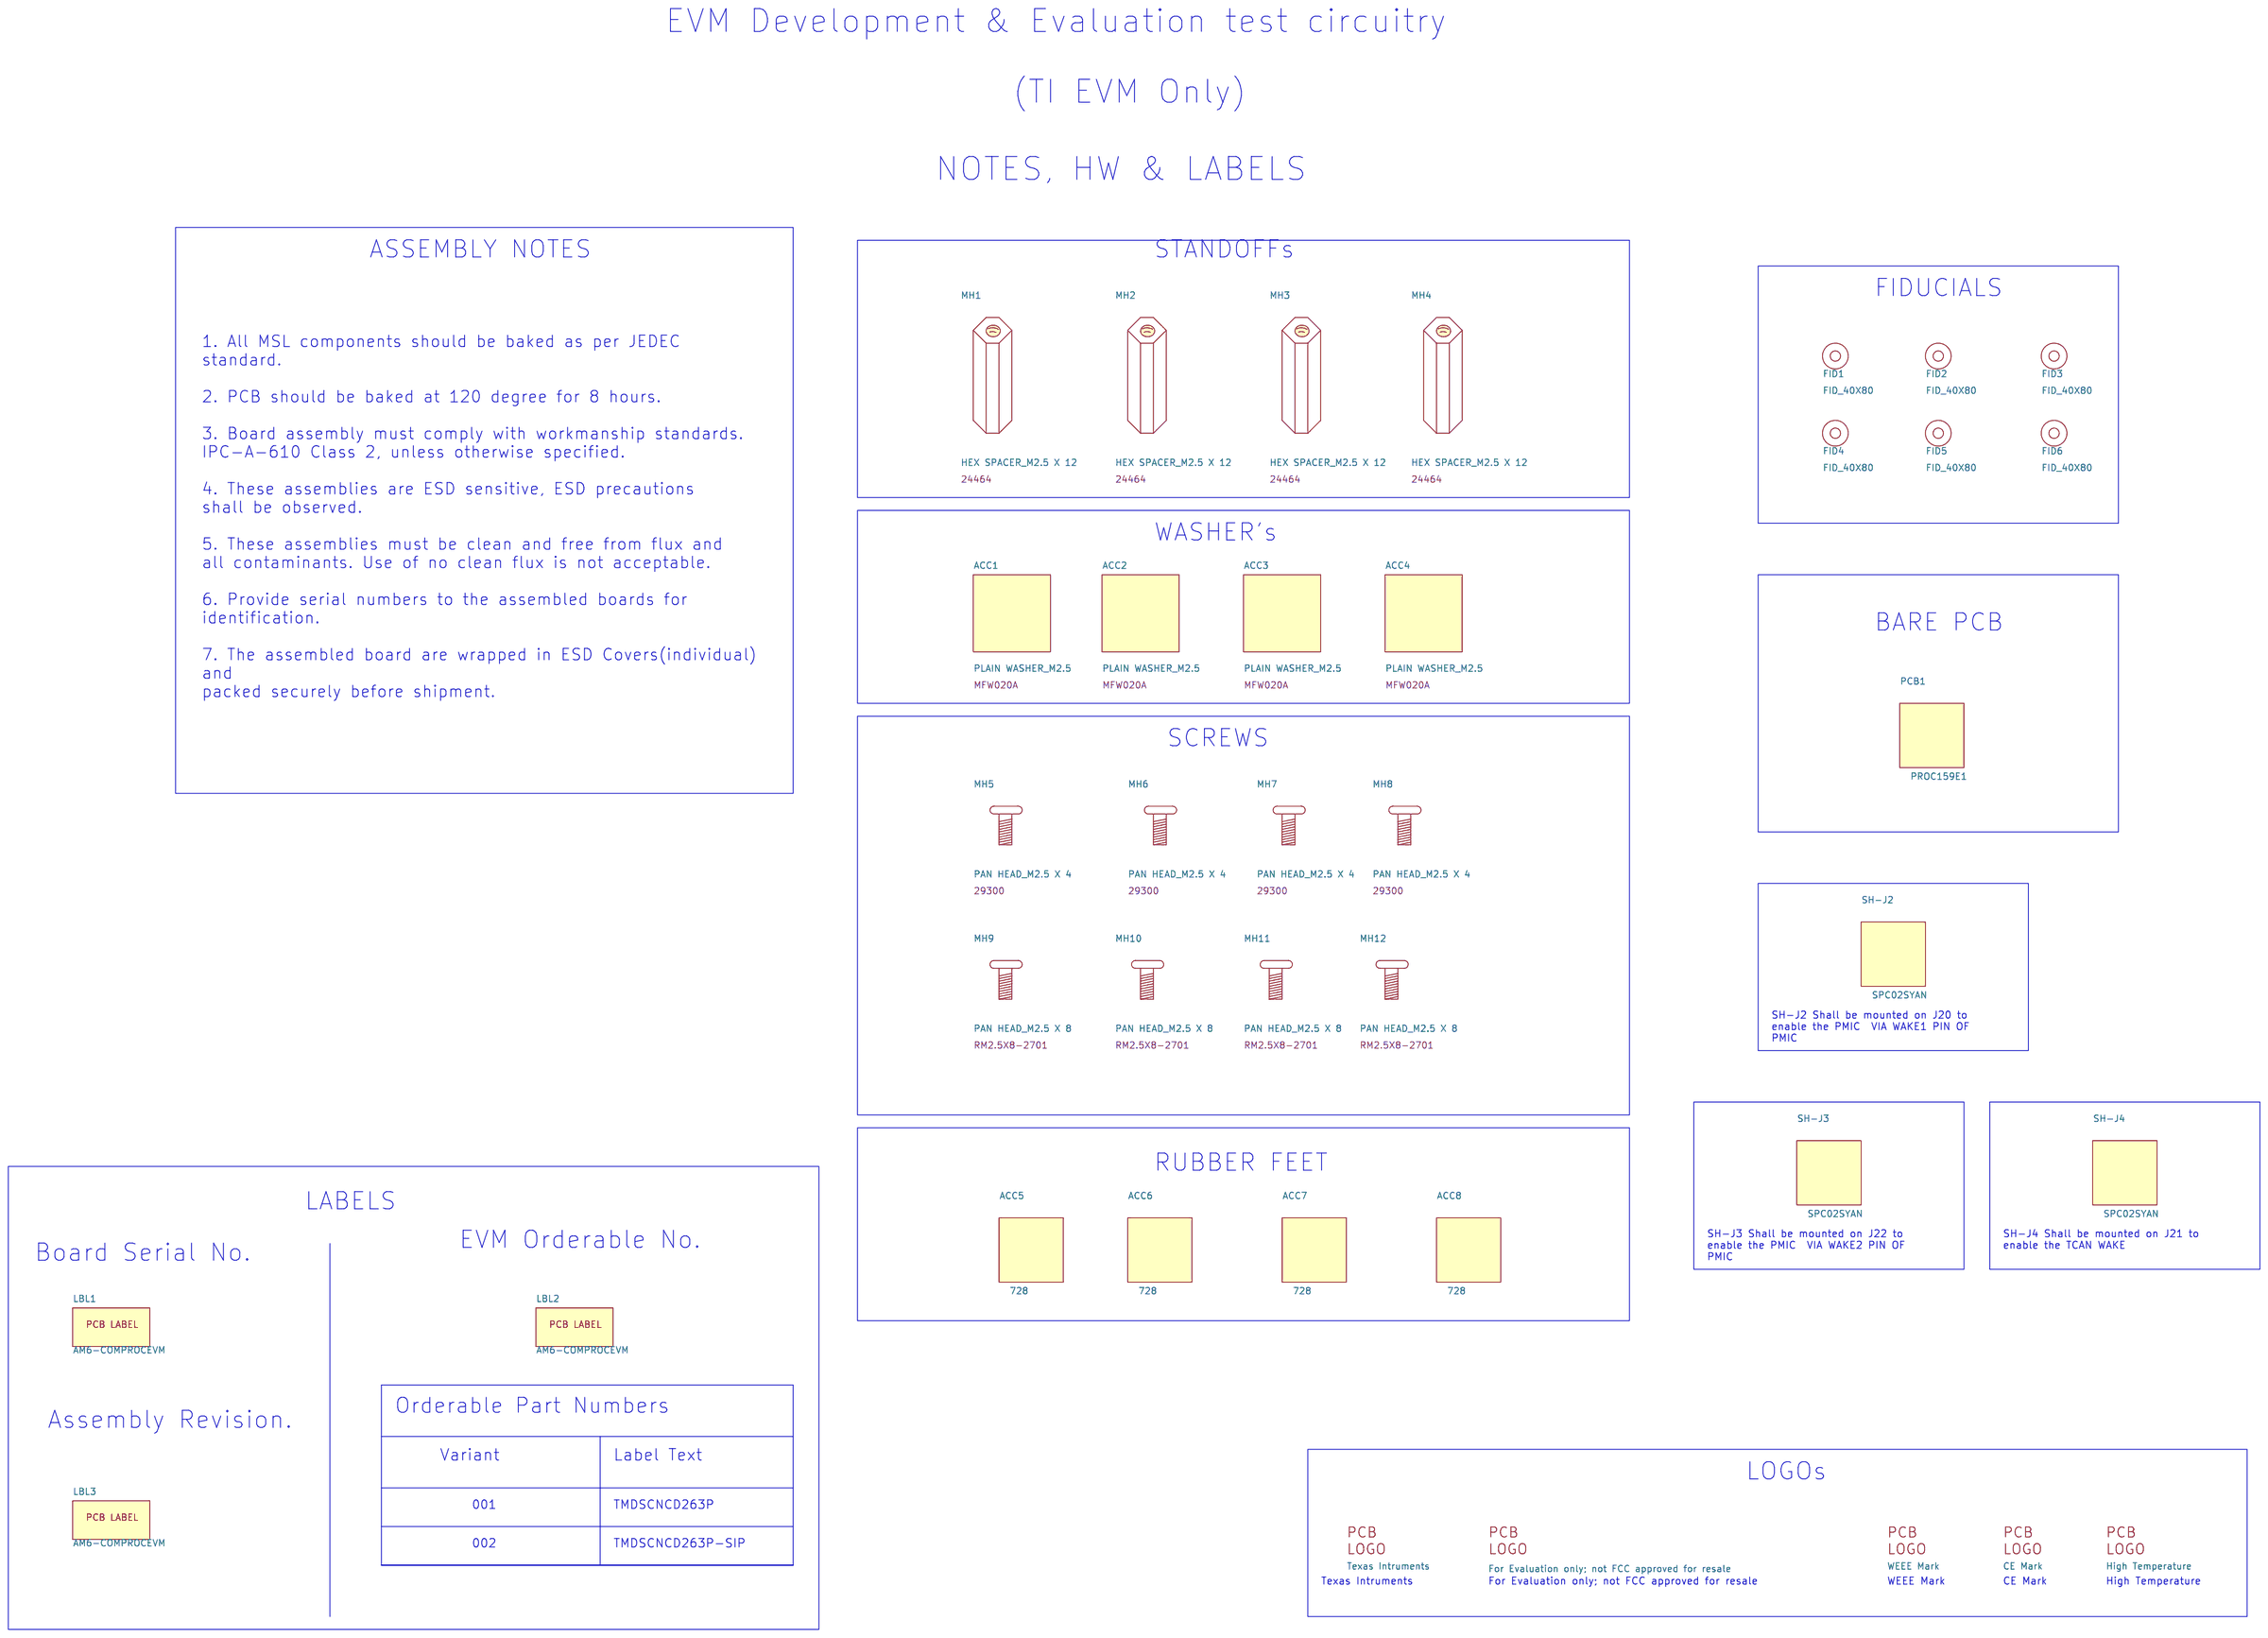
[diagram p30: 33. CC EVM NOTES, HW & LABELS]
32 21. ICSS ETHERNET/HSEC MUXES: size C; title: ICSS ETHERNET /HSEC MUXES
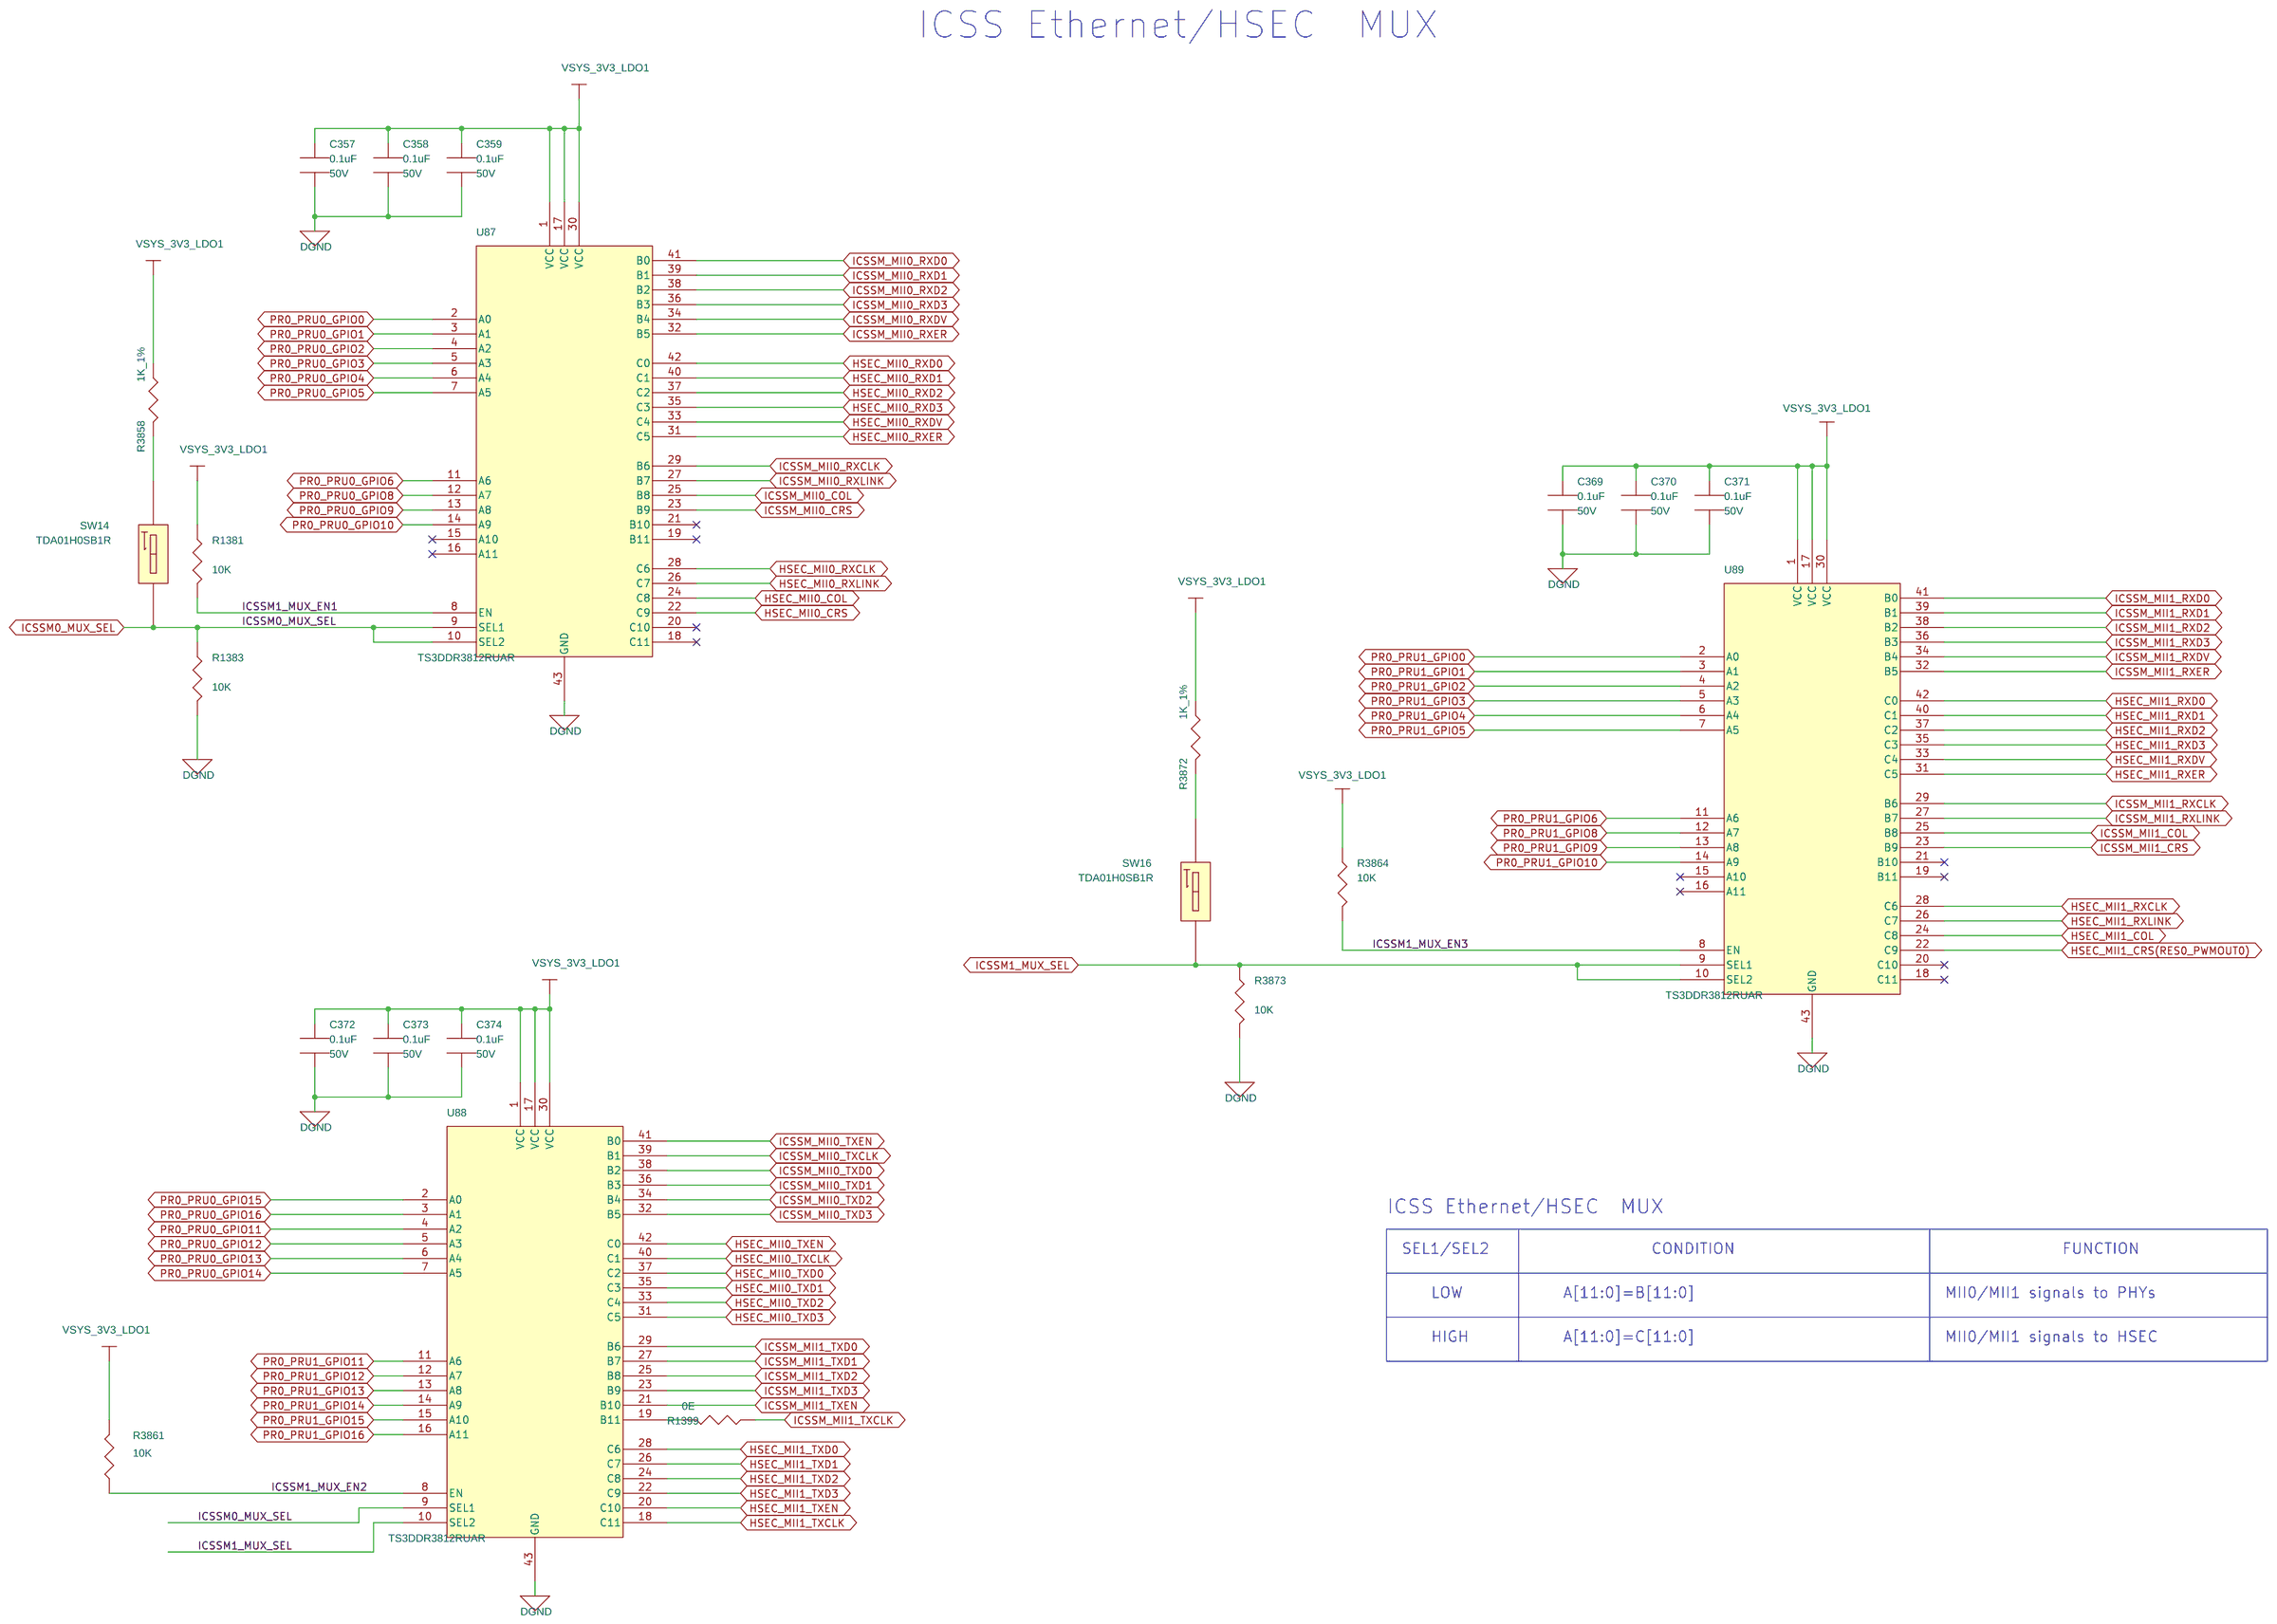
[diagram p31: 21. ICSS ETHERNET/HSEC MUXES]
33 22. ICSS ON/ADD-MII0/MII1MUXES: size C; title: ICSS ON-BOARD/ADD-ON PHY & MII0/MII1 MUXES

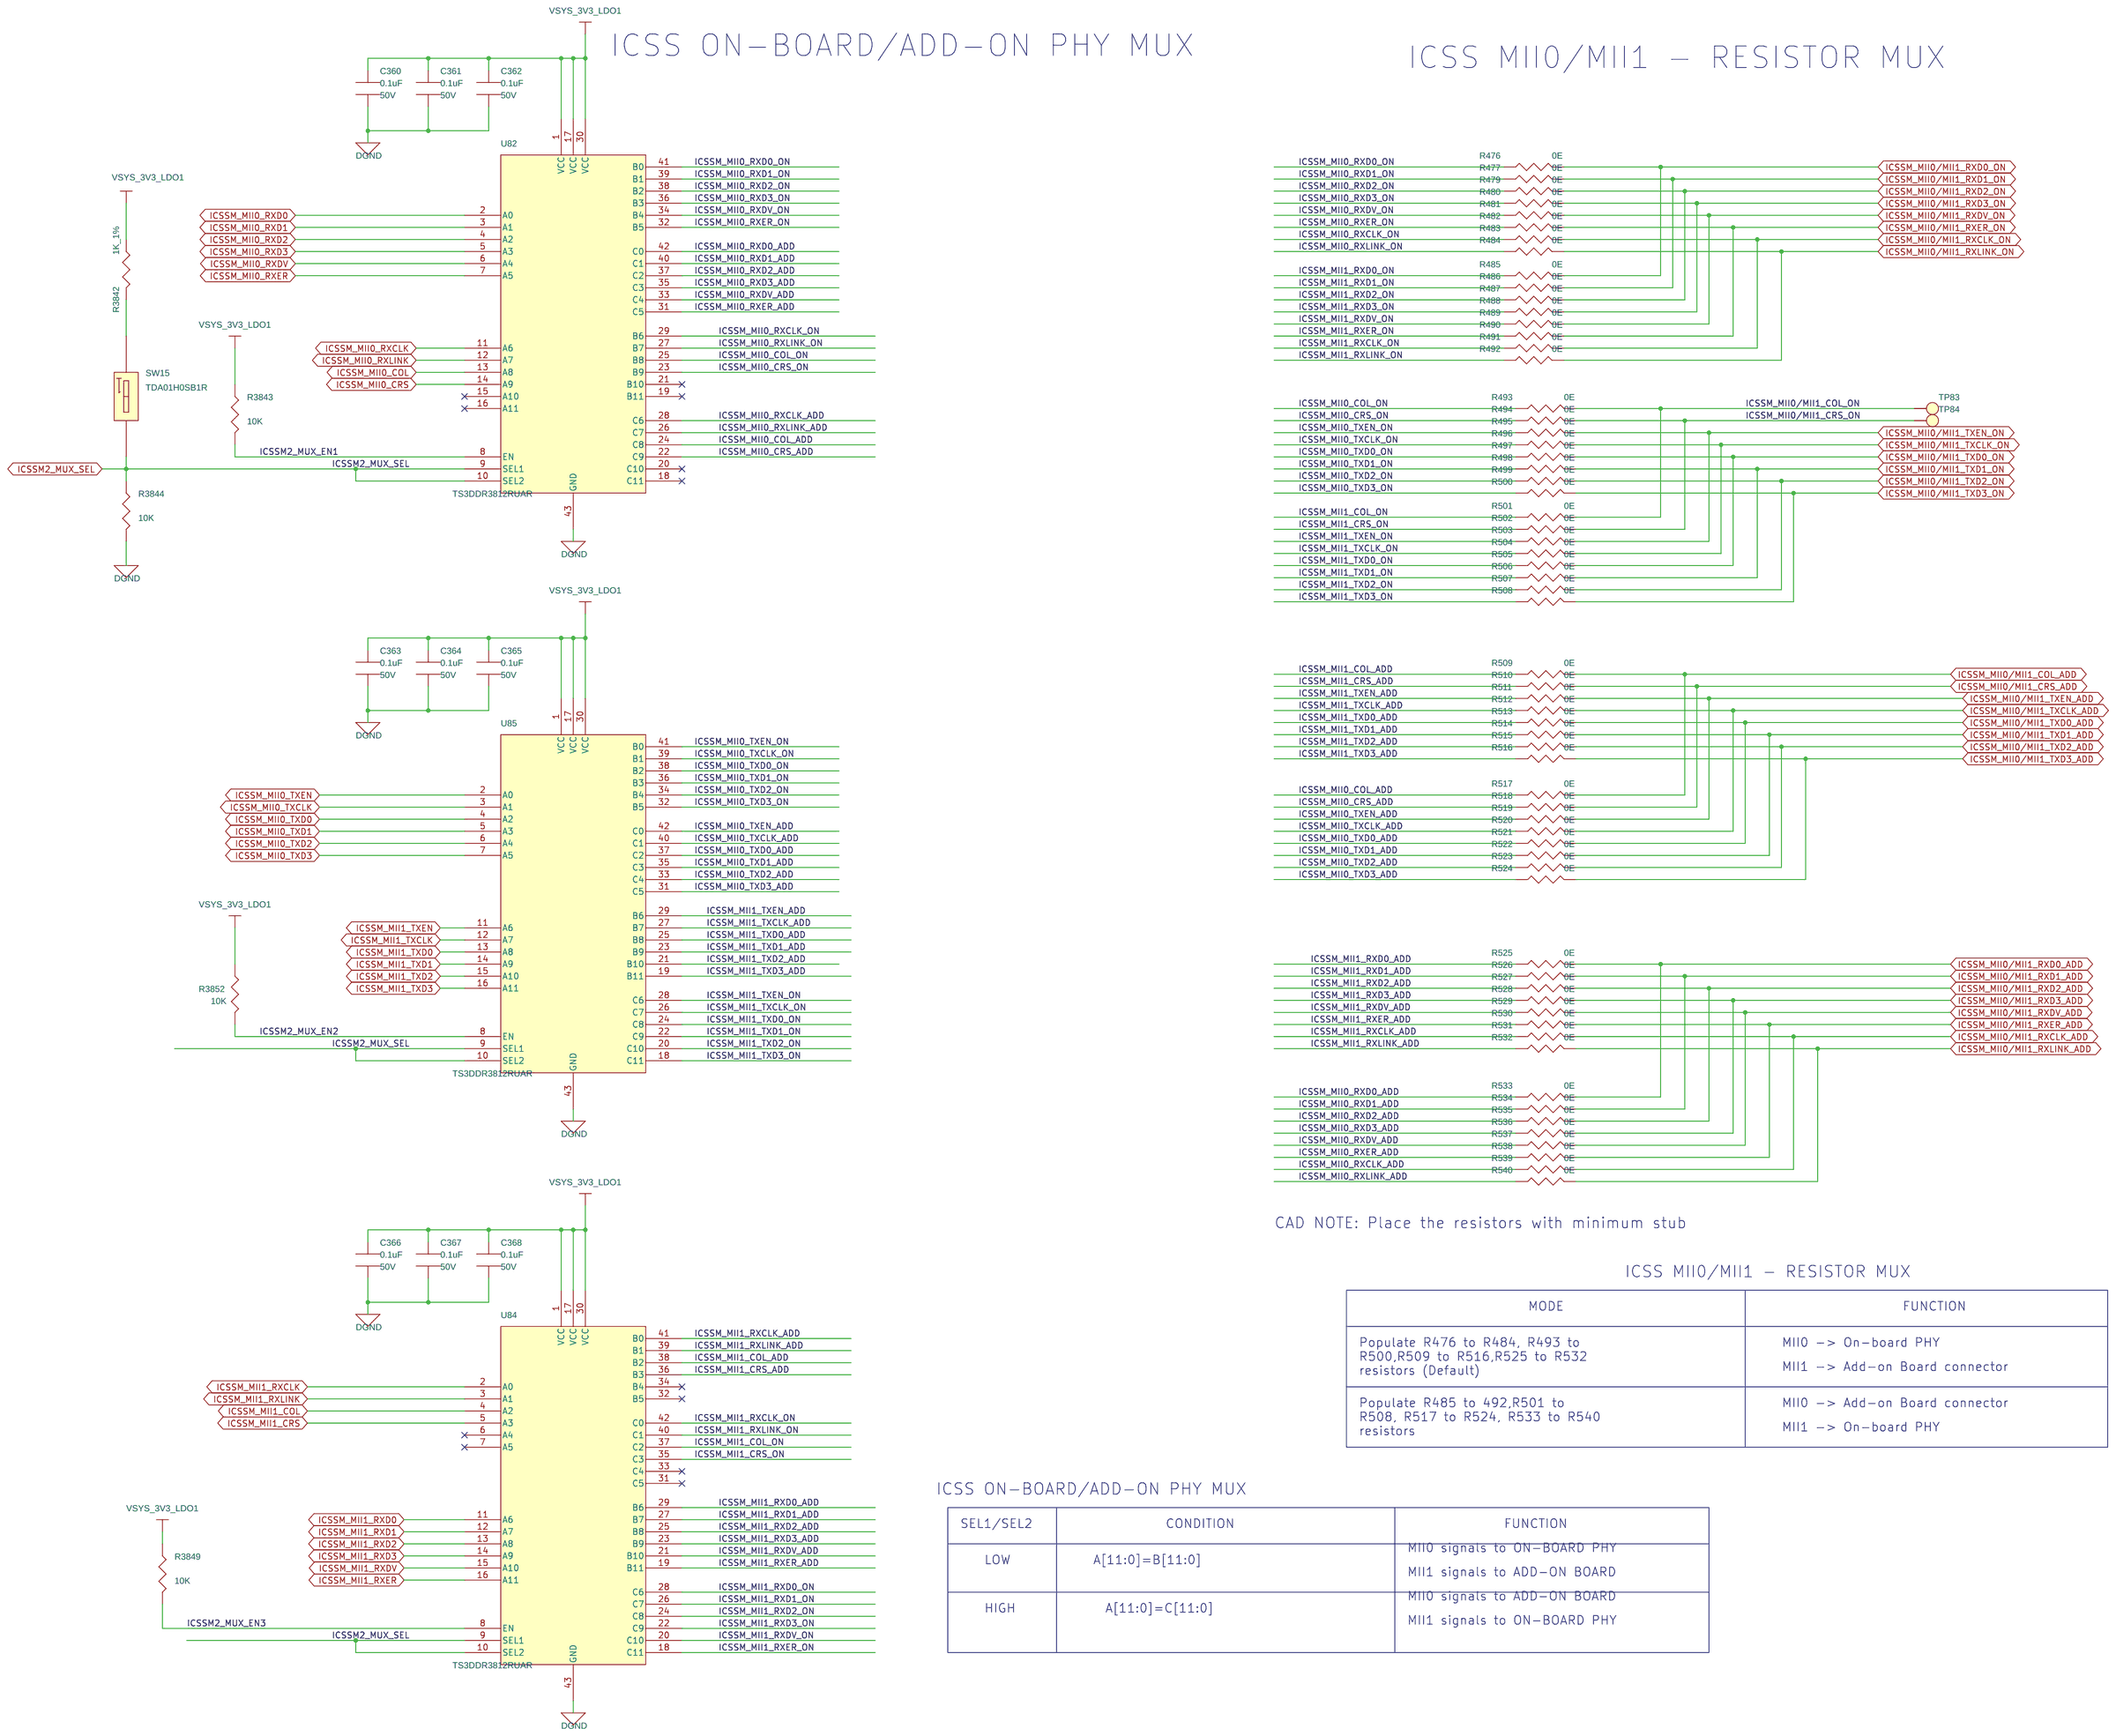
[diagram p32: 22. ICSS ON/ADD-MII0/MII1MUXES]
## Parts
sheet 21. ICSS ETHERNET/HSEC MUXES
C357  0.1uF  [CAP0402_0-75]
C358  0.1uF  [CAP0402_0-75]
C359  0.1uF  [CAP0402_0-75]
C369  0.1uF  [CAP0402_0-75]
C370  0.1uF  [CAP0402_0-75]
C371  0.1uF  [CAP0402_0-75]
C372  0.1uF  [CAP0402_0-75]
C373  0.1uF  [CAP0402_0-75]
C374  0.1uF  [CAP0402_0-75]
R1381  10K  [RES0402_0-5]
R1383  10K  [RES0402_0-5]
R1399  0E  [RES0402_0-5]
R3858  1K_1%  [RES0402_0-5]
R3861  10K  [RES0402_0-5]
R3864  10K  [RES0402_0-5]
R3872  1K_1%  [RES0402_0-5]
R3873  10K  [RES0402_0-5]
SW14  TDA01H0SB1R  [SW_TDA01H0S_240X90_SMD_2-3]
SW16  TDA01H0SB1R  [SW_TDA01H0S_240X90_SMD_2-3]
U87  TS3DDR3812RUAR  [TQFN42_19-68_140X360_0-8]
U88  TS3DDR3812RUAR  [TQFN42_19-68_140X360_0-8]
U89  TS3DDR3812RUAR  [TQFN42_19-68_140X360_0-8]
sheet 22. ICSS ON/ADD-MII0/MII1MUXES
C360  0.1uF  [CAP0402_0-75]
C361  0.1uF  [CAP0402_0-75]
C362  0.1uF  [CAP0402_0-75]
C363  0.1uF  [CAP0402_0-75]
C364  0.1uF  [CAP0402_0-75]
C365  0.1uF  [CAP0402_0-75]
C366  0.1uF  [CAP0402_0-75]
C367  0.1uF  [CAP0402_0-75]
C368  0.1uF  [CAP0402_0-75]
R476  0E  [RES0201_0-5]
R477  0E  [RES0201_0-5]
R479  0E  [RES0201_0-5]
R480  0E  [RES0201_0-5]
R481  0E  [RES0201_0-5]
R482  0E  [RES0201_0-5]
R483  0E  [RES0201_0-5]
R484  0E  [RES0201_0-5]
R485  0E  [RES0201_0-5]
R486  0E  [RES0201_0-5]
R487  0E  [RES0201_0-5]
R488  0E  [RES0201_0-5]
R489  0E  [RES0201_0-5]
R490  0E  [RES0201_0-5]
R491  0E  [RES0201_0-5]
R492  0E  [RES0201_0-5]
R493  0E  [RES0201_0-5]
R494  0E  [RES0201_0-5]
R495  0E  [RES0201_0-5]
R496  0E  [RES0201_0-5]
R497  0E  [RES0201_0-5]
R498  0E  [RES0201_0-5]
R499  0E  [RES0201_0-5]
R500  0E  [RES0201_0-5]
R501  0E  [RES0201_0-5]
R502  0E  [RES0201_0-5]
R503  0E  [RES0201_0-5]
R504  0E  [RES0201_0-5]
R505  0E  [RES0201_0-5]
R506  0E  [RES0201_0-5]
R507  0E  [RES0201_0-5]
R508  0E  [RES0201_0-5]
R509  0E  [RES0201_0-5]
R510  0E  [RES0201_0-5]
R511  0E  [RES0201_0-5]
R512  0E  [RES0201_0-5]
R513  0E  [RES0201_0-5]
R514  0E  [RES0201_0-5]
R515  0E  [RES0201_0-5]
R516  0E  [RES0201_0-5]
R517  0E  [RES0201_0-5]
R518  0E  [RES0201_0-5]
R519  0E  [RES0201_0-5]
R520  0E  [RES0201_0-5]
R521  0E  [RES0201_0-5]
R522  0E  [RES0201_0-5]
R523  0E  [RES0201_0-5]
R524  0E  [RES0201_0-5]
R525  0E  [RES0201_0-5]
R526  0E  [RES0201_0-5]
R527  0E  [RES0201_0-5]
R528  0E  [RES0201_0-5]
R529  0E  [RES0201_0-5]
R530  0E  [RES0201_0-5]
R531  0E  [RES0201_0-5]
R532  0E  [RES0201_0-5]
R533  0E  [RES0201_0-5]
R534  0E  [RES0201_0-5]
R535  0E  [RES0201_0-5]
R536  0E  [RES0201_0-5]
R537  0E  [RES0201_0-5]
R538  0E  [RES0201_0-5]
R539  0E  [RES0201_0-5]
R540  0E  [RES0201_0-5]
R3842  1K_1%  [RES0402_0-5]
R3843  10K  [RES0402_0-5]
R3844  10K  [RES0402_0-5]
R3849  10K  [RES0402_0-5]
R3852  10K  [RES0402_0-5]
SW15  TDA01H0SB1R  [SW_TDA01H0S_240X90_SMD_2-3]
TP83  TP20_SMD  [TP20_SMD]
TP84  TP20_SMD  [TP20_SMD]
U82  TS3DDR3812RUAR  [TQFN42_19-68_140X360_0-8]
U84  TS3DDR3812RUAR  [TQFN42_19-68_140X360_0-8]
U85  TS3DDR3812RUAR  [TQFN42_19-68_140X360_0-8]
sheet 33. CC EVM NOTES, HW & LABELS
ACC1  PLAIN WASHER_M2.5  [NA]
ACC2  PLAIN WASHER_M2.5  [NA]
ACC3  PLAIN WASHER_M2.5  [NA]
ACC4  PLAIN WASHER_M2.5  [NA]
ACC5  728  [NA]
ACC6  728  [NA]
ACC7  728  [NA]
ACC8  728  [NA]
FID1  FID_40X80  [FID_40X80]
FID2  FID_40X80  [FID_40X80]
FID3  FID_40X80  [FID_40X80]
FID4  FID_40X80  [FID_40X80]
FID5  FID_40X80  [FID_40X80]
FID6  FID_40X80  [FID_40X80]
LBL1  AM6-COMPROCEVM  [NA]
LBL2  AM6-COMPROCEVM  [NA]
LBL3  AM6-COMPROCEVM  [NA]
LOGO1  Texas Intruments  [TI_Stacked_Overlay_Small]
LOGO2  For Evaluation only; not FCC approved for resale  [FCC_disclaimer]
LOGO3  WEEE Mark  [TI_Stacked_Overlay_Small]
LOGO4  CE Mark  [TI_Stacked_Overlay_Small]
LOGO5  High Temperature  [TI_Stacked_Overlay_Small]
MH1  HEX SPACER_M2.5 X 12  [NA]
MH2  HEX SPACER_M2.5 X 12  [NA]
MH3  HEX SPACER_M2.5 X 12  [NA]
MH4  HEX SPACER_M2.5 X 12  [NA]
MH5  PAN HEAD_M2.5 X 4  [NA]
MH6  PAN HEAD_M2.5 X 4  [NA]
MH7  PAN HEAD_M2.5 X 4  [NA]
MH8  PAN HEAD_M2.5 X 4  [NA]
MH9  PAN HEAD_M2.5 X 8  [NA]
MH10  PAN HEAD_M2.5 X 8  [NA]
MH11  PAN HEAD_M2.5 X 8  [NA]
MH12  PAN HEAD_M2.5 X 8  [NA]
PCB1  PROC159E1
SH-J2  SPC02SYAN  [NA]
SH-J3  SPC02SYAN  [NA]
SH-J4  SPC02SYAN  [NA]

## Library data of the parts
C357-C374 = CAP: CAP CERAMIC 0.1uF 50V 10% X7R 0402; Chkd/date: MANIRAJA/261020; Crtd /date: ALVY/211020; Custom_Duty: 15%; Customs_HS_Code: 85322990; Distributor_name: DIGIKEY; Distributor_part_number: 490-10700-1-ND; Footprint Path: Y:\MIS_DATABASE\Library\ALTIUM_TOOL\PCB_FOOTPRINTS\Altium_Footprint_Lib.PcbLib; Height: 0.55MM; Library Path: Y:\MIS_DATABASE\Library\ALTIUM_TOOL\SCHEMATICS_PARTS\MS_DISCRETE_Library.schlib; Mfr_name: MURATA; Mfr_part_number: GRM155R71H104KE14D; Mistral Part No: 120011100014-R; Package: 0402; Part_type: CAPACITORS\CERAMIC; Project: J7_CP; RoHS: RoHS; Temperature: -55°C+125°C; Tolerance: 10%; Voltage: 50V; Wattage: NA; Weight: 3.1mg; Datasheet: Y:\MIS_DATABASE\DATASHEETS\CAPACITORS\GRM155R71H104KE14.PDF
R1381 R1383 R3843 R3844 R3849 R3852 R3861 R3864 R3873 = RESISTOR: RES 10K 1/16W 5% 0402; Chkd/date: VASANTHA/061216; Crtd /date: MAZHAR/230805; Custom_Duty: 15%; Customs_HS_Code: 85332119; Distributor_name: DIGIKEY; Distributor_part_number: 311-10KJRCT-ND; Footprint Path: Y:\MIS_DATABASE\Library\ALTIUM_TOOL\PCB_FOOTPRINTS\Altium_Footprint_Lib.PcbLib; Height: 0.40MM; Library Path: Y:\MIS_DATABASE\Library\ALTIUM_TOOL\SCHEMATICS_PARTS\MS_DISCRETE_Library.schlib; Mfr_name: YAGEO AMERICA; Mfr_part_number: RC0402JR-0710KL; Mistral Part No: 110011060021-R; Package: 0402; Part_type: RESISTORS\FIXED; Project: HSE; RoHS: RoHS; Temperature: -55°C+155°C; Tolerance: 5%; Voltage: NA; Wattage: 1/16W; Weight: 0.65mg; Datasheet: Y:\MIS_DATABASE\DATASHEETS\RESISTORS\RCXXXXL-SER_MAR18.PDF
R1399 = RESISTOR: RES 0E 1/10W JUMPER 0402; Chkd/date: VASANTHA/061216; Crtd /date: NAVEED/201014; Custom_Duty: 15%; Customs_HS_Code: 85332119; Distributor_name: DIGIKEY; Distributor_part_number: P0.0JCT-ND; Footprint Path: Y:\MIS_DATABASE\Library\ALTIUM_TOOL\PCB_FOOTPRINTS\Altium_Footprint_Lib.PcbLib; Height: 0.40MM; IBISSP_MODLES: VALUE REPEATING 2 TIME; Library Path: Y:\MIS_DATABASE\Library\ALTIUM_TOOL\SCHEMATICS_PARTS\MS_DISCRETE_Library.schlib; Mfr_name: PANASONIC-ECG; Mfr_part_number: ERJ-2GE0R00X; Mistral Part No: 110018030052-R; Package: 0402; Part_type: RESISTORS\FIXED; Project: AEGIS POM; RoHS: RoHS; Temperature: -55°C+155°C; Tolerance: NA; Voltage: NA; Wattage: 1/10W; Weight: 0.8mg; Datasheet: Y:\MIS_DATABASE\DATASHEETS\RESISTORS\PAN-ERJSER_NOV17.PDF
R3842 R3858 R3872 = RESISTOR: RES 1K 1/10W 1% 0402; Chkd/date: VASANTHA/281216; Crtd /date: MAZHAR/150506; Custom_Duty: 15%; Customs_HS_Code: 85332119; Distributor_name: DIGIKEY; Distributor_part_number: P1.00KLCT-ND; Footprint Path: Y:\MIS_DATABASE\Library\ALTIUM_TOOL\PCB_FOOTPRINTS\Altium_Footprint_Lib.PcbLib; Height: 0.40MM; Library Path: Y:\MIS_DATABASE\Library\ALTIUM_TOOL\SCHEMATICS_PARTS\MS_DISCRETE_Library.schlib; Mfr_name: PANASONIC-ECG; Mfr_part_number: ERJ-2RKF1001X; Mistral Part No: 110009030411-R; Package: 0402; Part_type: RESISTORS\FIXED; Project: VOCERA; RoHS: RoHS; Temperature: -55°C+155°C; Tolerance: 1%; Voltage: NA; Wattage: 1/10W; Weight: 0.8mg; Datasheet: Y:\MIS_DATABASE\DATASHEETS\RESISTORS\PAN-ERJSER_NOV17.PDF
SW14-SW16 = SW2_CHS-01TA: SWITCH SLIDE 1POS SPST SMD; Chkd/date: MANIRAJA/031018; Crtd /date: MANIRAJA/031018; Custom_Duty: 24%; Customs_HS_Code: 85369090; Distributor_name: DIGIKEY; Distributor_part_number: CKN10538CT-ND; Footprint Path: Y:\MIS_DATABASE\Library\ALTIUM_TOOL\PCB_FOOTPRINTS\Altium_Footprint_Lib.PcbLib; Height: 2.30MM; Library Path: Y:\MIS_DATABASE\Library\ALTIUM_TOOL\SCHEMATICS_PARTS\MS_SWITCH_Library.schlib; Mfr_name: CK; Mistral Part No: 130018100003-R; Package: SMD; Part_type: ELECTRO-MECHANICAL\SWITCH; Project: TI_60GHz-AOP; RoHS: RoHS; Temperature: -40°C+85°C; Tolerance: NA; Voltage: NA; Wattage: NA; Weight: NA; Datasheet: Y:\MIS_DATABASE\DATASHEETS\MISC\SWITCHES\TDAXX-SER.PDF
U82 U84 U85 U87-U89 = TS3DDR3812RUAR_WQFN42: IC 12-CH 1:2 MUX/DEMUX SWITCH FOR DDR3 APPLICATION WQFN42; Chkd/date: MANIRAJA/250918; Crtd /date: ALVY/250918; Custom_Duty: 15%; Customs_HS_Code: 85423100; Distributor_name: DIGIKEY; Distributor_part_number: 296-28307-1-ND; Footprint Path: Y:\MIS_DATABASE\Library\ALTIUM_TOOL\PCB_FOOTPRINTS\Altium_Footprint_Lib.PcbLib; Height: 0.80MM; Library Path: Y:\MIS_DATABASE\Library\ALTIUM_TOOL\SCHEMATICS_PARTS\MS_COMBINATIONAL_Library.schlib; Mfr_name: TEXAS INSTRUMENTS; Mistral Part No: 141018090023-R; Package: WQFN42; Part_type: ICS\DIGITAL\COMBINATIONAL; Project: TI_J7ES_EVM_CP; RoHS: RoHS; Temperature: -40°C+85°C; Tolerance: NA; Voltage: NA; Wattage: NA; Weight: 54.8mg; Datasheet: Y:\MIS_DATABASE\DATASHEETS\ICS\DIGITAL\COMBINATIONAL\TS3DDR3812.PDF
R476 R477 R479-R540 = RESISTOR: RES 0E 1/20W 5% 0201; Chkd/date: NAVEED/301214; Crtd /date: MUDDU/120710; Custom_Duty: 15%; Customs_HS_Code: 85332119; Distributor_name: DIGIKEY; Distributor_part_number: 311-0.0NCT-ND; Footprint Path: Y:\MIS_DATABASE\Library\ALTIUM_TOOL\PCB_FOOTPRINTS\Altium_Footprint_Lib.PcbLib; Height: 0.26MM; Library Path: Y:\MIS_DATABASE\Library\ALTIUM_TOOL\SCHEMATICS_PARTS\MS_DISCRETE_Library.schlib; Mfr_name: YAGEO AMERICA; Mfr_part_number: RC0201JR-070RL; Mistral Part No: 110010070067-R; Package: 0201; Part_type: RESISTORS\FIXED; Project: PB_BUGBASE; RoHS: RoHS; Temperature: -55°C+125°C; Tolerance: 5%; Voltage: NA; Wattage: 1/20W; Weight: 0.17mg; Datasheet: Y:\MIS_DATABASE\DATASHEETS\RESISTORS\RCXXXXL-SER_MAR18.PDF
TP83 TP84 = TESTPOINT: TESTPOINT CIR 20 SMD; Chkd/date: SHREESHAIL/171006; Crtd /date: MAZHAR/171006; Custom_Duty: NA; Customs_HS_Code: NA; Distributor_name: NA; Distributor_part_number: NA; Footprint Path: Y:\MIS_DATABASE\Library\ALTIUM_TOOL\PCB_FOOTPRINTS\Altium_Footprint_Lib.PcbLib; Height: NA; Library Path: Y:\MIS_DATABASE\Library\ALTIUM_TOOL\SCHEMATICS_PARTS\MS_DISCRETE_Library.schlib; MECHANICAL 3D STEP FILE: NA; Mfr_name: LOCAL; Mistral Part No: NA; Package: SMD; Project: BT MODULE_CSRBC04; RoHS: NA; Temperature: NA; Tolerance: NA; Voltage: NA; Wattage: NA; Weight: NA; Datasheet: NA
ACC1-ACC4 = WASHER_PLAIN: PLAIN WASHER FOR M2.5 NYLON; Chkd/date: MANIRAJA/110321; Crtd /date: ALVY/110321; Distributor_name: DIGIKEY; Distributor_part_number: RPC1999-ND; Mfr_name: ESSENTRA; Mfr_part_number: MFW020A; Mistral Part No: 160021030026-R; Part_type: MECHANICAL\WASHERS; Project: J7ES_SK_BRD; RoHS: RoHS; Datasheet: Y:\MIS_DATABASE\DATASHEETS\MISC\MECHANICAL\WASHER-MFWXXX.PDF
ACC5-ACC8 = ACCESSORY: ACCESSORIE RECESSED BUMPER 19.05MM DIA; Chkd/date: MANIRAJA/110718; Crtd /date: MANIRAJA/110718; Distributor_name: DIGIKEY; Distributor_part_number: 36-728-ND; Mfr_name: KEYSTONE; Mistral Part No: 160018070042-R; Part_type: ACCESSORIES; Project: TI_MAXIE_CPB; RoHS: RoHS; Weight: 2042mg; Datasheet: Y:\MIS_DATABASE\DATASHEETS\MISC\ACCESSORIES\728.PDF
FID1-FID6 = Fiducial
LBL1-LBL3 = ACCESSORY_THT-3-423-10: ACCESSORIE 1 WORKHORSE POLYSTER LABLE 0.25" X 1"; Chkd/date: MANIRAJA/270218; Crtd /date: ALVY/260218; Footprint Path: Y:\MIS_DATABASE\Library\ALTIUM_TOOL\PCB_FOOTPRINTS\Altium_Footprint_Lib.PcbLib; Library Path: Y:\MIS_DATABASE\Library\ALTIUM_TOOL\SCHEMATICS_PARTS\MS_MECHANICAL_Library.schlib; Mfr_name: BRADY; Mfr_part_number: THT-103-423-10; Mistral Part No: 160018020185; Part_type: ACCESSORIES; Project: TI_MAXIE_CPB
LOGO1 LOGO3-LOGO5 = TI_Logo
LOGO2 = FCC_disclaimer
MH1-MH4 = HEX_SPACER_FF: HEX SPACER FEMALE TO FEMALE M2.5 X 12MM SS; Chkd/date: ALVY/081021; Crtd /date: MANIRAJA/081021; Distributor_name: DIGIKEY; Distributor_part_number: 36-24464-ND; Height: 12.00MM; Mfr_name: KEYSTONE; Mfr_part_number: 24464; Mistral Part No: 160021100022-R; Package: SS; Part_type: MECHANICAL\SPACER; Project: ENEKOM_SMART SENSOR SYSTEM; RoHS: RoHS; Weight: 1479mg; Datasheet: Y:\MIS_DATABASE\DATASHEETS\MISC\ACCESSORIES\KS-24460-4.PDF
MH5-MH8 = SCREW_PAN: PHILLIPS PAN HEAD SCREW - M2.5 X 4 SS-316; Chkd/date: MANIRAJA/190218; Crtd /date: MANIRAJA/190218; Distributor_name: DIGIKEY; Distributor_part_number: 36-29300-ND; Footprint Path: Y:\MIS_DATABASE\Library\ALTIUM_TOOL\PCB_FOOTPRINTS\Altium_Footprint_Lib.PcbLib; Height: 4.00MM; Library Path: Y:\MIS_DATABASE\Library\ALTIUM_TOOL\SCHEMATICS_PARTS\MS_MECHANICAL_Library.schlib; Mfr_name: KEYSTONE; Mfr_part_number: 29300; Mistral Part No: 160018020076-R; Package: SS; Part_type: MECHANICAL\SCREWS; Project: TI_MAXIE_CPB; RoHS: RoHS; Datasheet: Y:\MIS_DATABASE\DATASHEETS\MISC\MECHANICAL\29300.PDF
MH9-MH12 = SCREW_PAN: PHILLIPS PAN HEAD SCREW - M2.5 X 8 SS; Chkd/date: MANIRAJA/110321; Crtd /date: ALVY/110321; Height: 8.00MM; Mfr_name: APM; Mfr_part_number: RM2.5X8-2701; Mistral Part No: 160021030025-R; Package: SS; Part_type: MECHANICAL\SCREWS; Project: J7ES_SK_BRD; RoHS: RoHS; Datasheet: Y:\MIS_DATABASE\DATASHEETS\MISC\MECHANICAL\APM-CATALOG.PDF
PCB1 = ACCESSORY_PROC078: AM263x CC AUTO EVM Board REV E1 BARE PCB; Mfr_name: ANY; Mfr_part_number: PROC153E1
SH-J2-SH-J4 = ACCESSORY: ACCESSORIE JUMPER SHORTING GOLD FLASH; Chkd/date: SUHAS\211010; Crtd /date: USMAN/301208; Distributor_name: DIGIKEY; Distributor_part_number: S9001-ND; Footprint Path: Y:\MIS_DATABASE\Library\ALTIUM_TOOL\PCB_FOOTPRINTS\Altium_Footprint_Lib.PcbLib; Library Path: Y:\MIS_DATABASE\Library\ALTIUM_TOOL\SCHEMATICS_PARTS\MS_MECHANICAL_Library.schlib; Mfr_name: SULLINS CONNECTOR; Mistral Part No: 160009030153-R; Part_type: ACCESSORIES; Project: SMART VIEW_NVR; RoHS: RoHS; Temperature: -55°C+105°C; Datasheet: Y:\MIS_DATABASE\DATASHEETS\MISC\MODULES\SPC02SYAN.PDF

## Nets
DGND: C357.2 C358.2 C359.2 C360.2 C361.2 C362.2 C363.2 C364.2 C365.2 C366.2 C367.2 C368.2 C369.2 C370.2 C371.2 C372.2 C373.2 C374.2 R1383.1 R3844.1 R3873.1 U82.43(GND) U84.43(GND) U85.43(GND) U87.43(GND) U88.43(GND) U89.43(GND) ; also on sheet 1 2 3 4 6 7 8 9 10 11 12 13 14 15 16 17 24 25 26 27 28 29 30
HSEC_MII0_COL: U87.24(C8) ; also on sheet 6
HSEC_MII0_CRS: U87.22(C9) ; also on sheet 6
HSEC_MII0_RXCLK: U87.28(C6) ; also on sheet 6
HSEC_MII0_RXD0: U87.42(C0) ; also on sheet 6
HSEC_MII0_RXD1: U87.40(C1) ; also on sheet 6
HSEC_MII0_RXD2: U87.37(C2) ; also on sheet 6
HSEC_MII0_RXD3: U87.35(C3) ; also on sheet 6
HSEC_MII0_RXDV: U87.33(C4) ; also on sheet 6
HSEC_MII0_RXER: U87.31(C5) ; also on sheet 6
HSEC_MII0_RXLINK: U87.26(C7) ; also on sheet 6
HSEC_MII0_TXCLK: U88.40(C1) ; also on sheet 6
HSEC_MII0_TXD0: U88.37(C2) ; also on sheet 6
HSEC_MII0_TXD1: U88.35(C3) ; also on sheet 6
HSEC_MII0_TXD2: U88.33(C4) ; also on sheet 6
HSEC_MII0_TXD3: U88.31(C5) ; also on sheet 6
HSEC_MII0_TXEN: U88.42(C0) ; also on sheet 6
HSEC_MII1_COL: U89.24(C8) ; also on sheet 6
HSEC_MII1_CRS(RES0_PWMOUT0): U89.22(C9) ; also on sheet 2 6
HSEC_MII1_RXCLK: U89.28(C6) ; also on sheet 6
HSEC_MII1_RXD0: U89.42(C0) ; also on sheet 6
HSEC_MII1_RXD1: U89.40(C1) ; also on sheet 6
HSEC_MII1_RXD2: U89.37(C2) ; also on sheet 6
HSEC_MII1_RXD3: U89.35(C3) ; also on sheet 6
HSEC_MII1_RXDV: U89.33(C4) ; also on sheet 6
HSEC_MII1_RXER: U89.31(C5) ; also on sheet 6
HSEC_MII1_RXLINK: U89.26(C7) ; also on sheet 6
HSEC_MII1_TXCLK: U88.18(C11) ; also on sheet 6
HSEC_MII1_TXD0: U88.28(C6) ; also on sheet 6
HSEC_MII1_TXD1: U88.26(C7) ; also on sheet 6
HSEC_MII1_TXD2: U88.24(C8) ; also on sheet 6
HSEC_MII1_TXD3: U88.22(C9) ; also on sheet 6
HSEC_MII1_TXEN: U88.20(C10) ; also on sheet 6
ICSSM0_MUX_SEL: R1383.2 SW14.1 U87.9(SEL1) U87.10(SEL2) U88.9(SEL1) ; also on sheet 12
ICSSM1_MUX_EN1: R1381.1 U87.8(EN)
ICSSM1_MUX_EN2: R3861.2 U88.8(EN)
ICSSM1_MUX_EN3: R3864.1 U89.8(EN)
ICSSM1_MUX_SEL: R3873.2 SW16.1 U88.10(SEL2) U89.9(SEL1) U89.10(SEL2) ; also on sheet 12
ICSSM2_MUX_EN1: R3843.1 U82.8(EN)
ICSSM2_MUX_EN2: R3852.1 U85.8(EN)
ICSSM2_MUX_EN3: R3849.1 U84.8(EN)
ICSSM2_MUX_SEL: R3844.2 SW15.1 U82.9(SEL1) U82.10(SEL2) U84.9(SEL1) U84.10(SEL2) U85.9(SEL1) U85.10(SEL2) ; also on sheet 12
ICSSM_MII0/MII1_COL_ADD: R509.2 R517.2 ; also on sheet 7
ICSSM_MII0/MII1_COL_ON: R493.2 R501.2 TP83.1(TP)
ICSSM_MII0/MII1_CRS_ADD: R510.2 R518.2 ; also on sheet 7
ICSSM_MII0/MII1_CRS_ON: R494.2 R502.2 TP84.1(TP)
ICSSM_MII0/MII1_RXCLK_ADD: R531.2 R539.2 ; also on sheet 7
ICSSM_MII0/MII1_RXCLK_ON: R483.2 R491.2 ; also on sheet 15
ICSSM_MII0/MII1_RXD0_ADD: R525.2 R533.2 ; also on sheet 7
ICSSM_MII0/MII1_RXD0_ON: R476.2 R485.2 ; also on sheet 15
ICSSM_MII0/MII1_RXD1_ADD: R526.2 R534.2 ; also on sheet 7
ICSSM_MII0/MII1_RXD1_ON: R477.2 R486.2 ; also on sheet 15
ICSSM_MII0/MII1_RXD2_ADD: R527.2 R535.2 ; also on sheet 7
ICSSM_MII0/MII1_RXD2_ON: R479.2 R487.2 ; also on sheet 15
ICSSM_MII0/MII1_RXD3_ADD: R528.2 R536.2 ; also on sheet 7
ICSSM_MII0/MII1_RXD3_ON: R480.2 R488.2 ; also on sheet 15
ICSSM_MII0/MII1_RXDV_ADD: R529.2 R537.2 ; also on sheet 7
ICSSM_MII0/MII1_RXDV_ON: R481.2 R489.2 ; also on sheet 15
ICSSM_MII0/MII1_RXER_ADD: R530.2 R538.2 ; also on sheet 7
ICSSM_MII0/MII1_RXER_ON: R482.2 R490.2 ; also on sheet 15
ICSSM_MII0/MII1_RXLINK_ADD: R532.2 R540.2 ; also on sheet 7
ICSSM_MII0/MII1_RXLINK_ON: R484.2 R492.2 ; also on sheet 15
ICSSM_MII0/MII1_TXCLK_ADD: R512.2 R520.2 ; also on sheet 7
ICSSM_MII0/MII1_TXCLK_ON: R496.2 R504.2 ; also on sheet 15
ICSSM_MII0/MII1_TXD0_ADD: R513.2 R521.2 ; also on sheet 7
ICSSM_MII0/MII1_TXD0_ON: R497.2 R505.2 ; also on sheet 15
ICSSM_MII0/MII1_TXD1_ADD: R514.2 R522.2 ; also on sheet 7
ICSSM_MII0/MII1_TXD1_ON: R498.2 R506.2 ; also on sheet 15
ICSSM_MII0/MII1_TXD2_ADD: R515.2 R523.2 ; also on sheet 7
ICSSM_MII0/MII1_TXD2_ON: R499.2 R507.2 ; also on sheet 15
ICSSM_MII0/MII1_TXD3_ADD: R516.2 R524.2 ; also on sheet 7
ICSSM_MII0/MII1_TXD3_ON: R500.2 R508.2 ; also on sheet 15
ICSSM_MII0/MII1_TXEN_ADD: R511.2 R519.2 ; also on sheet 7
ICSSM_MII0/MII1_TXEN_ON: R495.2 R503.2 ; also on sheet 15
ICSSM_MII0_COL: U82.13(A8) U87.25(B8)
ICSSM_MII0_COL_ADD: R517.1 U82.24(C8)
ICSSM_MII0_COL_ON: R493.1 U82.25(B8)
ICSSM_MII0_CRS: U82.14(A9) U87.23(B9)
ICSSM_MII0_CRS_ADD: R518.1 U82.22(C9)
ICSSM_MII0_CRS_ON: R494.1 U82.23(B9)
ICSSM_MII0_RXCLK: U82.11(A6) U87.29(B6)
ICSSM_MII0_RXCLK_ADD: R539.1 U82.28(C6)
ICSSM_MII0_RXCLK_ON: R483.1 U82.29(B6)
ICSSM_MII0_RXD0: U82.2(A0) U87.41(B0)
ICSSM_MII0_RXD0_ADD: R533.1 U82.42(C0)
ICSSM_MII0_RXD0_ON: R476.1 U82.41(B0)
ICSSM_MII0_RXD1: U82.3(A1) U87.39(B1)
ICSSM_MII0_RXD1_ADD: R534.1 U82.40(C1)
ICSSM_MII0_RXD1_ON: R477.1 U82.39(B1)
ICSSM_MII0_RXD2: U82.4(A2) U87.38(B2)
ICSSM_MII0_RXD2_ADD: R535.1 U82.37(C2)
ICSSM_MII0_RXD2_ON: R479.1 U82.38(B2)
ICSSM_MII0_RXD3: U82.5(A3) U87.36(B3)
ICSSM_MII0_RXD3_ADD: R536.1 U82.35(C3)
ICSSM_MII0_RXD3_ON: R480.1 U82.36(B3)
ICSSM_MII0_RXDV: U82.6(A4) U87.34(B4)
ICSSM_MII0_RXDV_ADD: R537.1 U82.33(C4)
ICSSM_MII0_RXDV_ON: R481.1 U82.34(B4)
ICSSM_MII0_RXER: U82.7(A5) U87.32(B5)
ICSSM_MII0_RXER_ADD: R538.1 U82.31(C5)
ICSSM_MII0_RXER_ON: R482.1 U82.32(B5)
ICSSM_MII0_RXLINK: U82.12(A7) U87.27(B7)
ICSSM_MII0_RXLINK_ADD: R540.1 U82.26(C7)
ICSSM_MII0_RXLINK_ON: R484.1 U82.27(B7)
ICSSM_MII0_TXCLK: U85.3(A1) U88.39(B1)
ICSSM_MII0_TXCLK_ADD: R520.1 U85.40(C1)
ICSSM_MII0_TXCLK_ON: R496.1 U85.39(B1)
ICSSM_MII0_TXD0: U85.4(A2) U88.38(B2)
ICSSM_MII0_TXD0_ADD: R521.1 U85.37(C2)
ICSSM_MII0_TXD0_ON: R497.1 U85.38(B2)
ICSSM_MII0_TXD1: U85.5(A3) U88.36(B3)
ICSSM_MII0_TXD1_ADD: R522.1 U85.35(C3)
ICSSM_MII0_TXD1_ON: R498.1 U85.36(B3)
ICSSM_MII0_TXD2: U85.6(A4) U88.34(B4)
ICSSM_MII0_TXD2_ADD: R523.1 U85.33(C4)
ICSSM_MII0_TXD2_ON: R499.1 U85.34(B4)
ICSSM_MII0_TXD3: U85.7(A5) U88.32(B5)
ICSSM_MII0_TXD3_ADD: R524.1 U85.31(C5)
ICSSM_MII0_TXD3_ON: R500.1 U85.32(B5)
ICSSM_MII0_TXEN: U85.2(A0) U88.41(B0)
ICSSM_MII0_TXEN_ADD: R519.1 U85.42(C0)
ICSSM_MII0_TXEN_ON: R495.1 U85.41(B0)
ICSSM_MII1_COL: U84.4(A2) U89.25(B8)
ICSSM_MII1_COL_ADD: R509.1 U84.38(B2)
ICSSM_MII1_COL_ON: R501.1 U84.37(C2)
ICSSM_MII1_CRS: U84.5(A3) U89.23(B9)
ICSSM_MII1_CRS_ADD: R510.1 U84.36(B3)
ICSSM_MII1_CRS_ON: R502.1 U84.35(C3)
ICSSM_MII1_RXCLK: U84.2(A0) U89.29(B6)
ICSSM_MII1_RXCLK_ADD: R531.1 U84.41(B0)
ICSSM_MII1_RXCLK_ON: R491.1 U84.42(C0)
ICSSM_MII1_RXD0: U84.11(A6) U89.41(B0)
ICSSM_MII1_RXD0_ADD: R525.1 U84.29(B6)
ICSSM_MII1_RXD0_ON: R485.1 U84.28(C6)
ICSSM_MII1_RXD1: U84.12(A7) U89.39(B1)
ICSSM_MII1_RXD1_ADD: R526.1 U84.27(B7)
ICSSM_MII1_RXD1_ON: R486.1 U84.26(C7)
ICSSM_MII1_RXD2: U84.13(A8) U89.38(B2)
ICSSM_MII1_RXD2_ADD: R527.1 U84.25(B8)
ICSSM_MII1_RXD2_ON: R487.1 U84.24(C8)
ICSSM_MII1_RXD3: U84.14(A9) U89.36(B3)
ICSSM_MII1_RXD3_ADD: R528.1 U84.23(B9)
ICSSM_MII1_RXD3_ON: R488.1 U84.22(C9)
ICSSM_MII1_RXDV: U84.15(A10) U89.34(B4)
ICSSM_MII1_RXDV_ADD: R529.1 U84.21(B10)
ICSSM_MII1_RXDV_ON: R489.1 U84.20(C10)
ICSSM_MII1_RXER: U84.16(A11) U89.32(B5)
ICSSM_MII1_RXER_ADD: R530.1 U84.19(B11)
ICSSM_MII1_RXER_ON: R490.1 U84.18(C11)
ICSSM_MII1_RXLINK: U84.3(A1) U89.27(B7)
ICSSM_MII1_RXLINK_ADD: R532.1 U84.39(B1)
ICSSM_MII1_RXLINK_ON: R492.1 U84.40(C1)
ICSSM_MII1_TXCLK: R1399.1 U85.12(A7)
ICSSM_MII1_TXCLK_ADD: R512.1 U85.27(B7)
ICSSM_MII1_TXCLK_ON: R504.1 U85.26(C7)
ICSSM_MII1_TXD0: U85.13(A8) U88.29(B6)
ICSSM_MII1_TXD0_ADD: R513.1 U85.25(B8)
ICSSM_MII1_TXD0_ON: R505.1 U85.24(C8)
ICSSM_MII1_TXD1: U85.14(A9) U88.27(B7)
ICSSM_MII1_TXD1_ADD: R514.1 U85.23(B9)
ICSSM_MII1_TXD1_ON: R506.1 U85.22(C9)
ICSSM_MII1_TXD2: U85.15(A10) U88.25(B8)
ICSSM_MII1_TXD2_ADD: R515.1 U85.21(B10)
ICSSM_MII1_TXD2_ON: R507.1 U85.20(C10)
ICSSM_MII1_TXD3: U85.16(A11) U88.23(B9)
ICSSM_MII1_TXD3_ADD: R516.1 U85.19(B11)
ICSSM_MII1_TXD3_ON: R508.1 U85.18(C11)
ICSSM_MII1_TXEN: U85.11(A6) U88.21(B10)
ICSSM_MII1_TXEN_ADD: R511.1 U85.29(B6)
ICSSM_MII1_TXEN_ON: R503.1 U85.28(C6)
PR0_PRU0_GPIO0: U87.2(A0) ; also on sheet 15
PR0_PRU0_GPIO1: U87.3(A1) ; also on sheet 15
PR0_PRU0_GPIO2: U87.4(A2) ; also on sheet 15
PR0_PRU0_GPIO3: U87.5(A3) ; also on sheet 15
PR0_PRU0_GPIO4: U87.6(A4) ; also on sheet 15
PR0_PRU0_GPIO5: U87.7(A5) ; also on sheet 15
PR0_PRU0_GPIO6: U87.11(A6) ; also on sheet 15
PR0_PRU0_GPIO8: U87.12(A7) ; also on sheet 15
PR0_PRU0_GPIO9: U87.13(A8) ; also on sheet 15
PR0_PRU0_GPIO10: U87.14(A9) ; also on sheet 15
PR0_PRU0_GPIO11: U88.4(A2) ; also on sheet 15
PR0_PRU0_GPIO12: U88.5(A3) ; also on sheet 15
PR0_PRU0_GPIO13: U88.6(A4) ; also on sheet 15
PR0_PRU0_GPIO14: U88.7(A5) ; also on sheet 15
PR0_PRU0_GPIO15: U88.2(A0) ; also on sheet 15
PR0_PRU0_GPIO16: U88.3(A1) ; also on sheet 15
PR0_PRU1_GPIO0: U89.2(A0) ; also on sheet 7
PR0_PRU1_GPIO1: U89.3(A1) ; also on sheet 7
PR0_PRU1_GPIO2: U89.4(A2) ; also on sheet 7
PR0_PRU1_GPIO3: U89.5(A3) ; also on sheet 7
PR0_PRU1_GPIO4: U89.6(A4) ; also on sheet 7
PR0_PRU1_GPIO5: U89.7(A5) ; also on sheet 7
PR0_PRU1_GPIO6: U89.11(A6) ; also on sheet 7
PR0_PRU1_GPIO8: U89.12(A7) ; also on sheet 7
PR0_PRU1_GPIO9: U89.13(A8) ; also on sheet 7
PR0_PRU1_GPIO10: U89.14(A9) ; also on sheet 7
PR0_PRU1_GPIO11: U88.11(A6) ; also on sheet 7
PR0_PRU1_GPIO12: U88.12(A7) ; also on sheet 7
PR0_PRU1_GPIO13: U88.13(A8) ; also on sheet 7
PR0_PRU1_GPIO14: U88.14(A9) ; also on sheet 7
PR0_PRU1_GPIO15: U88.15(A10) ; also on sheet 7
PR0_PRU1_GPIO16: U88.16(A11) ; also on sheet 7
VSYS_3V3_LDO1: C357.1 C358.1 C359.1 C360.1 C361.1 C362.1 C363.1 C364.1 C365.1 C366.1 C367.1 C368.1 C369.1 C370.1 C371.1 C372.1 C373.1 C374.1 R1381.2 R3842.1 R3843.2 R3849.2 R3852.2 R3858.1 R3861.1 R3864.2 R3872.1 U82.1(VCC) U82.17(VCC) U82.30(VCC) U84.1(VCC) U84.17(VCC) U84.30(VCC) U85.1(VCC) U85.17(VCC) U85.30(VCC) U87.1(VCC) U87.17(VCC) U87.30(VCC) U88.1(VCC) U88.17(VCC) U88.30(VCC) U89.1(VCC) U89.17(VCC) U89.30(VCC) ; also on sheet 1 6 7 9 10 11 12 13 14 15 16 17 24 26 27 28 29 30
N35672996: R3842.2 SW15.2
N35820709: R3858.2 SW14.2
N35821153: R1399.2 U88.19(B11)
N35844058: R3872.2 SW16.2

Not connected (* = marked no-connect by the designer): U82 15(A10)* 16(A11)* 18(C11)* 19(B11)* 20(C10)* 21(B10)*; U84 6(A4)* 7(A5)* 31(C5)* 32(B5)* 33(C4)* 34(B4)*; U87 15(A10)* 16(A11)* 18(C11)* 19(B11)* 20(C10)* 21(B10)*; U89 15(A10)* 16(A11)* 18(C11)* 19(B11)* 20(C10)* 21(B10)*

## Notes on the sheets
sheet 31
- EVM Development & Evaluation test circuitry
- (TI EVM Only)
- NOTES, HW & LABELS
- ASSEMBLY NOTES
- STANDOFFs
- FIDUCIALS
- 1. All MSL components should be baked as per JEDEC
  standard.
  2. PCB should be baked at 120 degree for 8 hours.
  3. Board assembly must comply with workmanship standards.
  IPC-A-610 Class 2, unless otherwise specified.
  4. These assemblies are ESD sensitive, ESD precautions
  shall be observed.
  5. These assemblies must be clean and free from flux and
  all contaminants. Use of no clean flux is not acceptable.
  6. Provide serial numbers to the assembled boards for
  identification.
  7. The assembled board are wrapped in ESD Covers(individual)
  and
  packed securely before shipment.
- WASHER's
- BARE PCB
- SCREWS
- SH-J2 Shall be mounted on J20 to
  enable the PMIC  VIA WAKE1 PIN OF
  PMIC
- RUBBER FEET
- LABELS
- Board Serial No.
- EVM Orderable No.
- SH-J3 Shall be mounted on J22 to
  enable the PMIC  VIA WAKE2 PIN OF
  PMIC
- SH-J4 Shall be mounted on J21 to
  enable the TCAN WAKE
- Assembly Revision.
- Orderable Part Numbers
- Variant
- Label Text
- LOGOs
- 001
- TMDSCNCD263P
- 002
- TMDSCNCD263P-SIP
- Texas Intruments
- For Evaluation only; not FCC approved for resale
- WEEE Mark
- CE Mark
- High Temperature
sheet 32
- ICSS Ethernet/HSEC  MUX
- ICSS Ethernet/HSEC  MUX
- SEL1/SEL2
- CONDITION
- FUNCTION
- LOW
- A[11:0]=B[11:0]
- MII0/MII1 signals to PHYs
- HIGH
- A[11:0]=C[11:0]
- MII0/MII1 signals to HSEC
sheet 33
- ICSS ON-BOARD/ADD-ON PHY MUX
- ICSS MII0/MII1 - RESISTOR MUX
- CAD NOTE: Place the resistors with minimum stub
- ICSS MII0/MII1 - RESISTOR MUX
- MODE
- FUNCTION
- Populate R476 to R484, R493 to
  R500,R509 to R516,R525 to R532
  resistors (Default)
- MII0 -> On-board PHY
- MII1 -> Add-on Board connector
- Populate R485 to 492,R501 to
  R508, R517 to R524, R533 to R540
  resistors
- MII0 -> Add-on Board connector
- MII1 -> On-board PHY
- ICSS ON-BOARD/ADD-ON PHY MUX
- SEL1/SEL2
- CONDITION
- FUNCTION
- MII0 signals to ON-BOARD PHY
- LOW
- A[11:0]=B[11:0]
- MII1 signals to ADD-ON BOARD
- HIGH
- A[11:0]=C[11:0]
- MII0 signals to ADD-ON BOARD
- MII1 signals to ON-BOARD PHY
